VERSION 5.8 ;
BUSBITCHARS "[]" ;
DIVIDERCHAR "/" ;
UNITS
    DATABASE MICRONS 1000 ;
END UNITS

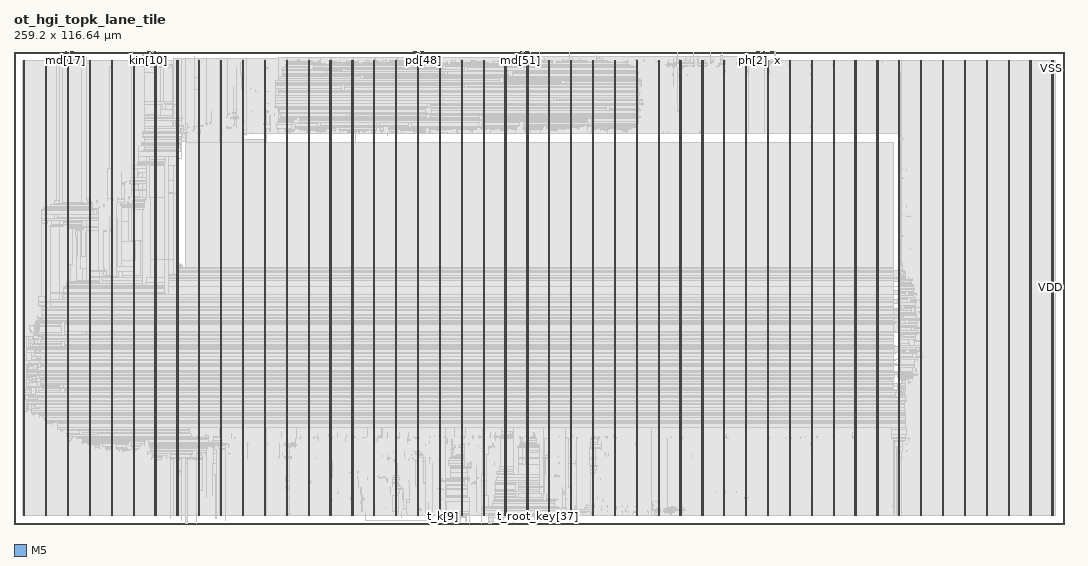
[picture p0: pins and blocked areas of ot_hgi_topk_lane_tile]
MACRO ot_hgi_topk_lane_tile
  FOREIGN ot_hgi_topk_lane_tile 0 0 ;
  CLASS BLOCK ;
  SIZE 259.2 BY 116.64 ;
  PIN clk
    DIRECTION INPUT ;
    USE SIGNAL ;
    PORT
      LAYER M5 ;
        RECT  31.92 116.556 31.944 116.64 ;
    END
  END clk
  PIN clr
    DIRECTION INPUT ;
    USE SIGNAL ;
    PORT
      LAYER M5 ;
        RECT  32.016 116.556 32.04 116.64 ;
    END
  END clr
  PIN kin[0]
    DIRECTION INPUT ;
    USE SIGNAL ;
    PORT
      LAYER M5 ;
        RECT  32.112 116.556 32.136 116.64 ;
    END
  END kin[0]
  PIN kin[10]
    DIRECTION INPUT ;
    USE SIGNAL ;
    PORT
      LAYER M5 ;
        RECT  33.072 116.556 33.096 116.64 ;
    END
  END kin[10]
  PIN kin[11]
    DIRECTION INPUT ;
    USE SIGNAL ;
    PORT
      LAYER M5 ;
        RECT  33.168 116.556 33.192 116.64 ;
    END
  END kin[11]
  PIN kin[1]
    DIRECTION INPUT ;
    USE SIGNAL ;
    PORT
      LAYER M5 ;
        RECT  32.208 116.556 32.232 116.64 ;
    END
  END kin[1]
  PIN kin[2]
    DIRECTION INPUT ;
    USE SIGNAL ;
    PORT
      LAYER M5 ;
        RECT  32.304 116.556 32.328 116.64 ;
    END
  END kin[2]
  PIN kin[3]
    DIRECTION INPUT ;
    USE SIGNAL ;
    PORT
      LAYER M5 ;
        RECT  32.4 116.556 32.424 116.64 ;
    END
  END kin[3]
  PIN kin[4]
    DIRECTION INPUT ;
    USE SIGNAL ;
    PORT
      LAYER M5 ;
        RECT  32.496 116.556 32.52 116.64 ;
    END
  END kin[4]
  PIN kin[5]
    DIRECTION INPUT ;
    USE SIGNAL ;
    PORT
      LAYER M5 ;
        RECT  32.592 116.556 32.616 116.64 ;
    END
  END kin[5]
  PIN kin[6]
    DIRECTION INPUT ;
    USE SIGNAL ;
    PORT
      LAYER M5 ;
        RECT  32.688 116.556 32.712 116.64 ;
    END
  END kin[6]
  PIN kin[7]
    DIRECTION INPUT ;
    USE SIGNAL ;
    PORT
      LAYER M5 ;
        RECT  32.784 116.556 32.808 116.64 ;
    END
  END kin[7]
  PIN kin[8]
    DIRECTION INPUT ;
    USE SIGNAL ;
    PORT
      LAYER M5 ;
        RECT  32.88 116.556 32.904 116.64 ;
    END
  END kin[8]
  PIN kin[9]
    DIRECTION INPUT ;
    USE SIGNAL ;
    PORT
      LAYER M5 ;
        RECT  32.976 116.556 33 116.64 ;
    END
  END kin[9]
  PIN mcr
    DIRECTION INPUT ;
    USE SIGNAL ;
    PORT
      LAYER M5 ;
        RECT  33.264 116.556 33.288 116.64 ;
    END
  END mcr
  PIN md[0]
    DIRECTION OUTPUT ;
    USE SIGNAL ;
    PORT
      LAYER M5 ;
        RECT  33.36 116.556 33.384 116.64 ;
    END
  END md[0]
  PIN md[10]
    DIRECTION OUTPUT ;
    USE SIGNAL ;
    PORT
      LAYER M5 ;
        RECT  34.32 116.556 34.344 116.64 ;
    END
  END md[10]
  PIN md[11]
    DIRECTION OUTPUT ;
    USE SIGNAL ;
    PORT
      LAYER M5 ;
        RECT  34.416 116.556 34.44 116.64 ;
    END
  END md[11]
  PIN md[12]
    DIRECTION OUTPUT ;
    USE SIGNAL ;
    PORT
      LAYER M5 ;
        RECT  34.512 116.556 34.536 116.64 ;
    END
  END md[12]
  PIN md[13]
    DIRECTION OUTPUT ;
    USE SIGNAL ;
    PORT
      LAYER M5 ;
        RECT  34.608 116.556 34.632 116.64 ;
    END
  END md[13]
  PIN md[14]
    DIRECTION OUTPUT ;
    USE SIGNAL ;
    PORT
      LAYER M5 ;
        RECT  34.704 116.556 34.728 116.64 ;
    END
  END md[14]
  PIN md[15]
    DIRECTION OUTPUT ;
    USE SIGNAL ;
    PORT
      LAYER M5 ;
        RECT  34.8 116.556 34.824 116.64 ;
    END
  END md[15]
  PIN md[16]
    DIRECTION OUTPUT ;
    USE SIGNAL ;
    PORT
      LAYER M5 ;
        RECT  34.896 116.556 34.92 116.64 ;
    END
  END md[16]
  PIN md[17]
    DIRECTION OUTPUT ;
    USE SIGNAL ;
    PORT
      LAYER M5 ;
        RECT  12.72 116.556 12.744 116.64 ;
    END
  END md[17]
  PIN md[18]
    DIRECTION OUTPUT ;
    USE SIGNAL ;
    PORT
      LAYER M5 ;
        RECT  12.816 116.556 12.84 116.64 ;
    END
  END md[18]
  PIN md[19]
    DIRECTION OUTPUT ;
    USE SIGNAL ;
    PORT
      LAYER M5 ;
        RECT  12.912 116.556 12.936 116.64 ;
    END
  END md[19]
  PIN md[1]
    DIRECTION OUTPUT ;
    USE SIGNAL ;
    PORT
      LAYER M5 ;
        RECT  33.456 116.556 33.48 116.64 ;
    END
  END md[1]
  PIN md[20]
    DIRECTION OUTPUT ;
    USE SIGNAL ;
    PORT
      LAYER M5 ;
        RECT  13.008 116.556 13.032 116.64 ;
    END
  END md[20]
  PIN md[21]
    DIRECTION OUTPUT ;
    USE SIGNAL ;
    PORT
      LAYER M5 ;
        RECT  13.104 116.556 13.128 116.64 ;
    END
  END md[21]
  PIN md[22]
    DIRECTION OUTPUT ;
    USE SIGNAL ;
    PORT
      LAYER M5 ;
        RECT  13.2 116.556 13.224 116.64 ;
    END
  END md[22]
  PIN md[23]
    DIRECTION OUTPUT ;
    USE SIGNAL ;
    PORT
      LAYER M5 ;
        RECT  13.296 116.556 13.32 116.64 ;
    END
  END md[23]
  PIN md[24]
    DIRECTION OUTPUT ;
    USE SIGNAL ;
    PORT
      LAYER M5 ;
        RECT  13.392 116.556 13.416 116.64 ;
    END
  END md[24]
  PIN md[25]
    DIRECTION OUTPUT ;
    USE SIGNAL ;
    PORT
      LAYER M5 ;
        RECT  13.488 116.556 13.512 116.64 ;
    END
  END md[25]
  PIN md[26]
    DIRECTION OUTPUT ;
    USE SIGNAL ;
    PORT
      LAYER M5 ;
        RECT  13.584 116.556 13.608 116.64 ;
    END
  END md[26]
  PIN md[27]
    DIRECTION OUTPUT ;
    USE SIGNAL ;
    PORT
      LAYER M5 ;
        RECT  13.68 116.556 13.704 116.64 ;
    END
  END md[27]
  PIN md[28]
    DIRECTION OUTPUT ;
    USE SIGNAL ;
    PORT
      LAYER M5 ;
        RECT  13.776 116.556 13.8 116.64 ;
    END
  END md[28]
  PIN md[29]
    DIRECTION OUTPUT ;
    USE SIGNAL ;
    PORT
      LAYER M5 ;
        RECT  13.872 116.556 13.896 116.64 ;
    END
  END md[29]
  PIN md[2]
    DIRECTION OUTPUT ;
    USE SIGNAL ;
    PORT
      LAYER M5 ;
        RECT  33.552 116.556 33.576 116.64 ;
    END
  END md[2]
  PIN md[30]
    DIRECTION OUTPUT ;
    USE SIGNAL ;
    PORT
      LAYER M5 ;
        RECT  13.968 116.556 13.992 116.64 ;
    END
  END md[30]
  PIN md[31]
    DIRECTION OUTPUT ;
    USE SIGNAL ;
    PORT
      LAYER M5 ;
        RECT  14.064 116.556 14.088 116.64 ;
    END
  END md[31]
  PIN md[32]
    DIRECTION OUTPUT ;
    USE SIGNAL ;
    PORT
      LAYER M5 ;
        RECT  14.16 116.556 14.184 116.64 ;
    END
  END md[32]
  PIN md[33]
    DIRECTION OUTPUT ;
    USE SIGNAL ;
    PORT
      LAYER M5 ;
        RECT  14.256 116.556 14.28 116.64 ;
    END
  END md[33]
  PIN md[34]
    DIRECTION OUTPUT ;
    USE SIGNAL ;
    PORT
      LAYER M5 ;
        RECT  14.352 116.556 14.376 116.64 ;
    END
  END md[34]
  PIN md[35]
    DIRECTION OUTPUT ;
    USE SIGNAL ;
    PORT
      LAYER M5 ;
        RECT  14.448 116.556 14.472 116.64 ;
    END
  END md[35]
  PIN md[36]
    DIRECTION OUTPUT ;
    USE SIGNAL ;
    PORT
      LAYER M5 ;
        RECT  14.544 116.556 14.568 116.64 ;
    END
  END md[36]
  PIN md[37]
    DIRECTION OUTPUT ;
    USE SIGNAL ;
    PORT
      LAYER M5 ;
        RECT  14.64 116.556 14.664 116.64 ;
    END
  END md[37]
  PIN md[38]
    DIRECTION OUTPUT ;
    USE SIGNAL ;
    PORT
      LAYER M5 ;
        RECT  14.736 116.556 14.76 116.64 ;
    END
  END md[38]
  PIN md[39]
    DIRECTION OUTPUT ;
    USE SIGNAL ;
    PORT
      LAYER M5 ;
        RECT  14.832 116.556 14.856 116.64 ;
    END
  END md[39]
  PIN md[3]
    DIRECTION OUTPUT ;
    USE SIGNAL ;
    PORT
      LAYER M5 ;
        RECT  33.648 116.556 33.672 116.64 ;
    END
  END md[3]
  PIN md[40]
    DIRECTION OUTPUT ;
    USE SIGNAL ;
    PORT
      LAYER M5 ;
        RECT  14.928 116.556 14.952 116.64 ;
    END
  END md[40]
  PIN md[41]
    DIRECTION OUTPUT ;
    USE SIGNAL ;
    PORT
      LAYER M5 ;
        RECT  15.024 116.556 15.048 116.64 ;
    END
  END md[41]
  PIN md[42]
    DIRECTION OUTPUT ;
    USE SIGNAL ;
    PORT
      LAYER M5 ;
        RECT  15.12 116.556 15.144 116.64 ;
    END
  END md[42]
  PIN md[43]
    DIRECTION OUTPUT ;
    USE SIGNAL ;
    PORT
      LAYER M5 ;
        RECT  15.216 116.556 15.24 116.64 ;
    END
  END md[43]
  PIN md[44]
    DIRECTION OUTPUT ;
    USE SIGNAL ;
    PORT
      LAYER M5 ;
        RECT  15.312 116.556 15.336 116.64 ;
    END
  END md[44]
  PIN md[45]
    DIRECTION OUTPUT ;
    USE SIGNAL ;
    PORT
      LAYER M5 ;
        RECT  15.408 116.556 15.432 116.64 ;
    END
  END md[45]
  PIN md[46]
    DIRECTION OUTPUT ;
    USE SIGNAL ;
    PORT
      LAYER M5 ;
        RECT  15.504 116.556 15.528 116.64 ;
    END
  END md[46]
  PIN md[47]
    DIRECTION OUTPUT ;
    USE SIGNAL ;
    PORT
      LAYER M5 ;
        RECT  15.6 116.556 15.624 116.64 ;
    END
  END md[47]
  PIN md[48]
    DIRECTION OUTPUT ;
    USE SIGNAL ;
    PORT
      LAYER M5 ;
        RECT  15.696 116.556 15.72 116.64 ;
    END
  END md[48]
  PIN md[49]
    DIRECTION OUTPUT ;
    USE SIGNAL ;
    PORT
      LAYER M5 ;
        RECT  124.848 116.556 124.872 116.64 ;
    END
  END md[49]
  PIN md[4]
    DIRECTION OUTPUT ;
    USE SIGNAL ;
    PORT
      LAYER M5 ;
        RECT  33.744 116.556 33.768 116.64 ;
    END
  END md[4]
  PIN md[50]
    DIRECTION OUTPUT ;
    USE SIGNAL ;
    PORT
      LAYER M5 ;
        RECT  124.944 116.556 124.968 116.64 ;
    END
  END md[50]
  PIN md[51]
    DIRECTION OUTPUT ;
    USE SIGNAL ;
    PORT
      LAYER M5 ;
        RECT  125.04 116.556 125.064 116.64 ;
    END
  END md[51]
  PIN md[52]
    DIRECTION OUTPUT ;
    USE SIGNAL ;
    PORT
      LAYER M5 ;
        RECT  125.136 116.556 125.16 116.64 ;
    END
  END md[52]
  PIN md[53]
    DIRECTION OUTPUT ;
    USE SIGNAL ;
    PORT
      LAYER M5 ;
        RECT  125.232 116.556 125.256 116.64 ;
    END
  END md[53]
  PIN md[5]
    DIRECTION OUTPUT ;
    USE SIGNAL ;
    PORT
      LAYER M5 ;
        RECT  33.84 116.556 33.864 116.64 ;
    END
  END md[5]
  PIN md[6]
    DIRECTION OUTPUT ;
    USE SIGNAL ;
    PORT
      LAYER M5 ;
        RECT  33.936 116.556 33.96 116.64 ;
    END
  END md[6]
  PIN md[7]
    DIRECTION OUTPUT ;
    USE SIGNAL ;
    PORT
      LAYER M5 ;
        RECT  34.032 116.556 34.056 116.64 ;
    END
  END md[7]
  PIN md[8]
    DIRECTION OUTPUT ;
    USE SIGNAL ;
    PORT
      LAYER M5 ;
        RECT  34.128 116.556 34.152 116.64 ;
    END
  END md[8]
  PIN md[9]
    DIRECTION OUTPUT ;
    USE SIGNAL ;
    PORT
      LAYER M5 ;
        RECT  34.224 116.556 34.248 116.64 ;
    END
  END md[9]
  PIN me
    DIRECTION OUTPUT ;
    USE SIGNAL ;
    PORT
      LAYER M5 ;
        RECT  125.328 116.556 125.352 116.64 ;
    END
  END me
  PIN mv
    DIRECTION OUTPUT ;
    USE SIGNAL ;
    PORT
      LAYER M5 ;
        RECT  125.424 116.556 125.448 116.64 ;
    END
  END mv
  PIN ok
    DIRECTION OUTPUT ;
    USE SIGNAL ;
    PORT
      LAYER M5 ;
        RECT  125.52 116.556 125.544 116.64 ;
    END
  END ok
  PIN pd[0]
    DIRECTION INPUT ;
    USE SIGNAL ;
    PORT
      LAYER M5 ;
        RECT  125.616 116.556 125.64 116.64 ;
    END
  END pd[0]
  PIN pd[10]
    DIRECTION INPUT ;
    USE SIGNAL ;
    PORT
      LAYER M5 ;
        RECT  126.576 116.556 126.6 116.64 ;
    END
  END pd[10]
  PIN pd[11]
    DIRECTION INPUT ;
    USE SIGNAL ;
    PORT
      LAYER M5 ;
        RECT  126.672 116.556 126.696 116.64 ;
    END
  END pd[11]
  PIN pd[12]
    DIRECTION INPUT ;
    USE SIGNAL ;
    PORT
      LAYER M5 ;
        RECT  126.768 116.556 126.792 116.64 ;
    END
  END pd[12]
  PIN pd[13]
    DIRECTION INPUT ;
    USE SIGNAL ;
    PORT
      LAYER M5 ;
        RECT  126.864 116.556 126.888 116.64 ;
    END
  END pd[13]
  PIN pd[14]
    DIRECTION INPUT ;
    USE SIGNAL ;
    PORT
      LAYER M5 ;
        RECT  126.96 116.556 126.984 116.64 ;
    END
  END pd[14]
  PIN pd[15]
    DIRECTION INPUT ;
    USE SIGNAL ;
    PORT
      LAYER M5 ;
        RECT  127.056 116.556 127.08 116.64 ;
    END
  END pd[15]
  PIN pd[16]
    DIRECTION INPUT ;
    USE SIGNAL ;
    PORT
      LAYER M5 ;
        RECT  127.152 116.556 127.176 116.64 ;
    END
  END pd[16]
  PIN pd[17]
    DIRECTION INPUT ;
    USE SIGNAL ;
    PORT
      LAYER M5 ;
        RECT  127.248 116.556 127.272 116.64 ;
    END
  END pd[17]
  PIN pd[18]
    DIRECTION INPUT ;
    USE SIGNAL ;
    PORT
      LAYER M5 ;
        RECT  127.344 116.556 127.368 116.64 ;
    END
  END pd[18]
  PIN pd[19]
    DIRECTION INPUT ;
    USE SIGNAL ;
    PORT
      LAYER M5 ;
        RECT  127.44 116.556 127.464 116.64 ;
    END
  END pd[19]
  PIN pd[1]
    DIRECTION INPUT ;
    USE SIGNAL ;
    PORT
      LAYER M5 ;
        RECT  125.712 116.556 125.736 116.64 ;
    END
  END pd[1]
  PIN pd[20]
    DIRECTION INPUT ;
    USE SIGNAL ;
    PORT
      LAYER M5 ;
        RECT  127.536 116.556 127.56 116.64 ;
    END
  END pd[20]
  PIN pd[21]
    DIRECTION INPUT ;
    USE SIGNAL ;
    PORT
      LAYER M5 ;
        RECT  127.632 116.556 127.656 116.64 ;
    END
  END pd[21]
  PIN pd[22]
    DIRECTION INPUT ;
    USE SIGNAL ;
    PORT
      LAYER M5 ;
        RECT  127.728 116.556 127.752 116.64 ;
    END
  END pd[22]
  PIN pd[23]
    DIRECTION INPUT ;
    USE SIGNAL ;
    PORT
      LAYER M5 ;
        RECT  127.824 116.556 127.848 116.64 ;
    END
  END pd[23]
  PIN pd[24]
    DIRECTION INPUT ;
    USE SIGNAL ;
    PORT
      LAYER M5 ;
        RECT  98.736 116.556 98.76 116.64 ;
    END
  END pd[24]
  PIN pd[25]
    DIRECTION INPUT ;
    USE SIGNAL ;
    PORT
      LAYER M5 ;
        RECT  98.832 116.556 98.856 116.64 ;
    END
  END pd[25]
  PIN pd[26]
    DIRECTION INPUT ;
    USE SIGNAL ;
    PORT
      LAYER M5 ;
        RECT  98.928 116.556 98.952 116.64 ;
    END
  END pd[26]
  PIN pd[27]
    DIRECTION INPUT ;
    USE SIGNAL ;
    PORT
      LAYER M5 ;
        RECT  99.024 116.556 99.048 116.64 ;
    END
  END pd[27]
  PIN pd[28]
    DIRECTION INPUT ;
    USE SIGNAL ;
    PORT
      LAYER M5 ;
        RECT  99.12 116.556 99.144 116.64 ;
    END
  END pd[28]
  PIN pd[29]
    DIRECTION INPUT ;
    USE SIGNAL ;
    PORT
      LAYER M5 ;
        RECT  99.216 116.556 99.24 116.64 ;
    END
  END pd[29]
  PIN pd[2]
    DIRECTION INPUT ;
    USE SIGNAL ;
    PORT
      LAYER M5 ;
        RECT  125.808 116.556 125.832 116.64 ;
    END
  END pd[2]
  PIN pd[30]
    DIRECTION INPUT ;
    USE SIGNAL ;
    PORT
      LAYER M5 ;
        RECT  99.312 116.556 99.336 116.64 ;
    END
  END pd[30]
  PIN pd[31]
    DIRECTION INPUT ;
    USE SIGNAL ;
    PORT
      LAYER M5 ;
        RECT  99.408 116.556 99.432 116.64 ;
    END
  END pd[31]
  PIN pd[32]
    DIRECTION INPUT ;
    USE SIGNAL ;
    PORT
      LAYER M5 ;
        RECT  99.504 116.556 99.528 116.64 ;
    END
  END pd[32]
  PIN pd[33]
    DIRECTION INPUT ;
    USE SIGNAL ;
    PORT
      LAYER M5 ;
        RECT  99.6 116.556 99.624 116.64 ;
    END
  END pd[33]
  PIN pd[34]
    DIRECTION INPUT ;
    USE SIGNAL ;
    PORT
      LAYER M5 ;
        RECT  99.696 116.556 99.72 116.64 ;
    END
  END pd[34]
  PIN pd[35]
    DIRECTION INPUT ;
    USE SIGNAL ;
    PORT
      LAYER M5 ;
        RECT  99.792 116.556 99.816 116.64 ;
    END
  END pd[35]
  PIN pd[36]
    DIRECTION INPUT ;
    USE SIGNAL ;
    PORT
      LAYER M5 ;
        RECT  99.888 116.556 99.912 116.64 ;
    END
  END pd[36]
  PIN pd[37]
    DIRECTION INPUT ;
    USE SIGNAL ;
    PORT
      LAYER M5 ;
        RECT  99.984 116.556 100.008 116.64 ;
    END
  END pd[37]
  PIN pd[38]
    DIRECTION INPUT ;
    USE SIGNAL ;
    PORT
      LAYER M5 ;
        RECT  100.08 116.556 100.104 116.64 ;
    END
  END pd[38]
  PIN pd[39]
    DIRECTION INPUT ;
    USE SIGNAL ;
    PORT
      LAYER M5 ;
        RECT  100.176 116.556 100.2 116.64 ;
    END
  END pd[39]
  PIN pd[3]
    DIRECTION INPUT ;
    USE SIGNAL ;
    PORT
      LAYER M5 ;
        RECT  125.904 116.556 125.928 116.64 ;
    END
  END pd[3]
  PIN pd[40]
    DIRECTION INPUT ;
    USE SIGNAL ;
    PORT
      LAYER M5 ;
        RECT  100.272 116.556 100.296 116.64 ;
    END
  END pd[40]
  PIN pd[41]
    DIRECTION INPUT ;
    USE SIGNAL ;
    PORT
      LAYER M5 ;
        RECT  100.368 116.556 100.392 116.64 ;
    END
  END pd[41]
  PIN pd[42]
    DIRECTION INPUT ;
    USE SIGNAL ;
    PORT
      LAYER M5 ;
        RECT  100.464 116.556 100.488 116.64 ;
    END
  END pd[42]
  PIN pd[43]
    DIRECTION INPUT ;
    USE SIGNAL ;
    PORT
      LAYER M5 ;
        RECT  100.56 116.556 100.584 116.64 ;
    END
  END pd[43]
  PIN pd[44]
    DIRECTION INPUT ;
    USE SIGNAL ;
    PORT
      LAYER M5 ;
        RECT  100.656 116.556 100.68 116.64 ;
    END
  END pd[44]
  PIN pd[45]
    DIRECTION INPUT ;
    USE SIGNAL ;
    PORT
      LAYER M5 ;
        RECT  100.752 116.556 100.776 116.64 ;
    END
  END pd[45]
  PIN pd[46]
    DIRECTION INPUT ;
    USE SIGNAL ;
    PORT
      LAYER M5 ;
        RECT  100.848 116.556 100.872 116.64 ;
    END
  END pd[46]
  PIN pd[47]
    DIRECTION INPUT ;
    USE SIGNAL ;
    PORT
      LAYER M5 ;
        RECT  100.944 116.556 100.968 116.64 ;
    END
  END pd[47]
  PIN pd[48]
    DIRECTION INPUT ;
    USE SIGNAL ;
    PORT
      LAYER M5 ;
        RECT  101.04 116.556 101.064 116.64 ;
    END
  END pd[48]
  PIN pd[49]
    DIRECTION INPUT ;
    USE SIGNAL ;
    PORT
      LAYER M5 ;
        RECT  101.136 116.556 101.16 116.64 ;
    END
  END pd[49]
  PIN pd[4]
    DIRECTION INPUT ;
    USE SIGNAL ;
    PORT
      LAYER M5 ;
        RECT  126 116.556 126.024 116.64 ;
    END
  END pd[4]
  PIN pd[50]
    DIRECTION INPUT ;
    USE SIGNAL ;
    PORT
      LAYER M5 ;
        RECT  101.232 116.556 101.256 116.64 ;
    END
  END pd[50]
  PIN pd[51]
    DIRECTION INPUT ;
    USE SIGNAL ;
    PORT
      LAYER M5 ;
        RECT  101.328 116.556 101.352 116.64 ;
    END
  END pd[51]
  PIN pd[52]
    DIRECTION INPUT ;
    USE SIGNAL ;
    PORT
      LAYER M5 ;
        RECT  101.424 116.556 101.448 116.64 ;
    END
  END pd[52]
  PIN pd[53]
    DIRECTION INPUT ;
    USE SIGNAL ;
    PORT
      LAYER M5 ;
        RECT  101.52 116.556 101.544 116.64 ;
    END
  END pd[53]
  PIN pd[5]
    DIRECTION INPUT ;
    USE SIGNAL ;
    PORT
      LAYER M5 ;
        RECT  126.096 116.556 126.12 116.64 ;
    END
  END pd[5]
  PIN pd[6]
    DIRECTION INPUT ;
    USE SIGNAL ;
    PORT
      LAYER M5 ;
        RECT  126.192 116.556 126.216 116.64 ;
    END
  END pd[6]
  PIN pd[7]
    DIRECTION INPUT ;
    USE SIGNAL ;
    PORT
      LAYER M5 ;
        RECT  126.288 116.556 126.312 116.64 ;
    END
  END pd[7]
  PIN pd[8]
    DIRECTION INPUT ;
    USE SIGNAL ;
    PORT
      LAYER M5 ;
        RECT  126.384 116.556 126.408 116.64 ;
    END
  END pd[8]
  PIN pd[9]
    DIRECTION INPUT ;
    USE SIGNAL ;
    PORT
      LAYER M5 ;
        RECT  126.48 116.556 126.504 116.64 ;
    END
  END pd[9]
  PIN ph[0]
    DIRECTION INPUT ;
    USE SIGNAL ;
    PORT
      LAYER M5 ;
        RECT  101.616 116.556 101.64 116.64 ;
    END
  END ph[0]
  PIN ph[1]
    DIRECTION INPUT ;
    USE SIGNAL ;
    PORT
      LAYER M5 ;
        RECT  101.712 116.556 101.736 116.64 ;
    END
  END ph[1]
  PIN ph[2]
    DIRECTION INPUT ;
    USE SIGNAL ;
    PORT
      LAYER M5 ;
        RECT  182.448 116.556 182.472 116.64 ;
    END
  END ph[2]
  PIN pv
    DIRECTION INPUT ;
    USE SIGNAL ;
    PORT
      LAYER M5 ;
        RECT  182.544 116.556 182.568 116.64 ;
    END
  END pv
  PIN q
    DIRECTION OUTPUT ;
    USE SIGNAL ;
    PORT
      LAYER M5 ;
        RECT  182.64 116.556 182.664 116.64 ;
    END
  END q
  PIN root[0]
    DIRECTION OUTPUT ;
    USE SIGNAL ;
    PORT
      LAYER M5 ;
        RECT  182.736 116.556 182.76 116.64 ;
    END
  END root[0]
  PIN root[10]
    DIRECTION OUTPUT ;
    USE SIGNAL ;
    PORT
      LAYER M5 ;
        RECT  183.696 116.556 183.72 116.64 ;
    END
  END root[10]
  PIN root[11]
    DIRECTION OUTPUT ;
    USE SIGNAL ;
    PORT
      LAYER M5 ;
        RECT  183.792 116.556 183.816 116.64 ;
    END
  END root[11]
  PIN root[12]
    DIRECTION OUTPUT ;
    USE SIGNAL ;
    PORT
      LAYER M5 ;
        RECT  183.888 116.556 183.912 116.64 ;
    END
  END root[12]
  PIN root[13]
    DIRECTION OUTPUT ;
    USE SIGNAL ;
    PORT
      LAYER M5 ;
        RECT  183.984 116.556 184.008 116.64 ;
    END
  END root[13]
  PIN root[14]
    DIRECTION OUTPUT ;
    USE SIGNAL ;
    PORT
      LAYER M5 ;
        RECT  184.08 116.556 184.104 116.64 ;
    END
  END root[14]
  PIN root[15]
    DIRECTION OUTPUT ;
    USE SIGNAL ;
    PORT
      LAYER M5 ;
        RECT  184.176 116.556 184.2 116.64 ;
    END
  END root[15]
  PIN root[16]
    DIRECTION OUTPUT ;
    USE SIGNAL ;
    PORT
      LAYER M5 ;
        RECT  184.272 116.556 184.296 116.64 ;
    END
  END root[16]
  PIN root[17]
    DIRECTION OUTPUT ;
    USE SIGNAL ;
    PORT
      LAYER M5 ;
        RECT  184.368 116.556 184.392 116.64 ;
    END
  END root[17]
  PIN root[18]
    DIRECTION OUTPUT ;
    USE SIGNAL ;
    PORT
      LAYER M5 ;
        RECT  184.464 116.556 184.488 116.64 ;
    END
  END root[18]
  PIN root[19]
    DIRECTION OUTPUT ;
    USE SIGNAL ;
    PORT
      LAYER M5 ;
        RECT  184.56 116.556 184.584 116.64 ;
    END
  END root[19]
  PIN root[1]
    DIRECTION OUTPUT ;
    USE SIGNAL ;
    PORT
      LAYER M5 ;
        RECT  182.832 116.556 182.856 116.64 ;
    END
  END root[1]
  PIN root[20]
    DIRECTION OUTPUT ;
    USE SIGNAL ;
    PORT
      LAYER M5 ;
        RECT  184.656 116.556 184.68 116.64 ;
    END
  END root[20]
  PIN root[21]
    DIRECTION OUTPUT ;
    USE SIGNAL ;
    PORT
      LAYER M5 ;
        RECT  184.752 116.556 184.776 116.64 ;
    END
  END root[21]
  PIN root[22]
    DIRECTION OUTPUT ;
    USE SIGNAL ;
    PORT
      LAYER M5 ;
        RECT  184.848 116.556 184.872 116.64 ;
    END
  END root[22]
  PIN root[23]
    DIRECTION OUTPUT ;
    USE SIGNAL ;
    PORT
      LAYER M5 ;
        RECT  184.944 116.556 184.968 116.64 ;
    END
  END root[23]
  PIN root[24]
    DIRECTION OUTPUT ;
    USE SIGNAL ;
    PORT
      LAYER M5 ;
        RECT  185.04 116.556 185.064 116.64 ;
    END
  END root[24]
  PIN root[25]
    DIRECTION OUTPUT ;
    USE SIGNAL ;
    PORT
      LAYER M5 ;
        RECT  185.136 116.556 185.16 116.64 ;
    END
  END root[25]
  PIN root[26]
    DIRECTION OUTPUT ;
    USE SIGNAL ;
    PORT
      LAYER M5 ;
        RECT  185.232 116.556 185.256 116.64 ;
    END
  END root[26]
  PIN root[27]
    DIRECTION OUTPUT ;
    USE SIGNAL ;
    PORT
      LAYER M5 ;
        RECT  185.328 116.556 185.352 116.64 ;
    END
  END root[27]
  PIN root[28]
    DIRECTION OUTPUT ;
    USE SIGNAL ;
    PORT
      LAYER M5 ;
        RECT  185.424 116.556 185.448 116.64 ;
    END
  END root[28]
  PIN root[29]
    DIRECTION OUTPUT ;
    USE SIGNAL ;
    PORT
      LAYER M5 ;
        RECT  186.096 116.556 186.12 116.64 ;
    END
  END root[29]
  PIN root[2]
    DIRECTION OUTPUT ;
    USE SIGNAL ;
    PORT
      LAYER M5 ;
        RECT  182.928 116.556 182.952 116.64 ;
    END
  END root[2]
  PIN root[30]
    DIRECTION OUTPUT ;
    USE SIGNAL ;
    PORT
      LAYER M5 ;
        RECT  186.192 116.556 186.216 116.64 ;
    END
  END root[30]
  PIN root[31]
    DIRECTION OUTPUT ;
    USE SIGNAL ;
    PORT
      LAYER M5 ;
        RECT  186.288 116.556 186.312 116.64 ;
    END
  END root[31]
  PIN root[32]
    DIRECTION OUTPUT ;
    USE SIGNAL ;
    PORT
      LAYER M5 ;
        RECT  186.384 116.556 186.408 116.64 ;
    END
  END root[32]
  PIN root[33]
    DIRECTION OUTPUT ;
    USE SIGNAL ;
    PORT
      LAYER M5 ;
        RECT  186.48 116.556 186.504 116.64 ;
    END
  END root[33]
  PIN root[34]
    DIRECTION OUTPUT ;
    USE SIGNAL ;
    PORT
      LAYER M5 ;
        RECT  186.576 116.556 186.6 116.64 ;
    END
  END root[34]
  PIN root[35]
    DIRECTION OUTPUT ;
    USE SIGNAL ;
    PORT
      LAYER M5 ;
        RECT  186.672 116.556 186.696 116.64 ;
    END
  END root[35]
  PIN root[36]
    DIRECTION OUTPUT ;
    USE SIGNAL ;
    PORT
      LAYER M5 ;
        RECT  186.768 116.556 186.792 116.64 ;
    END
  END root[36]
  PIN root[37]
    DIRECTION OUTPUT ;
    USE SIGNAL ;
    PORT
      LAYER M5 ;
        RECT  186.864 116.556 186.888 116.64 ;
    END
  END root[37]
  PIN root[38]
    DIRECTION OUTPUT ;
    USE SIGNAL ;
    PORT
      LAYER M5 ;
        RECT  186.96 116.556 186.984 116.64 ;
    END
  END root[38]
  PIN root[39]
    DIRECTION OUTPUT ;
    USE SIGNAL ;
    PORT
      LAYER M5 ;
        RECT  187.056 116.556 187.08 116.64 ;
    END
  END root[39]
  PIN root[3]
    DIRECTION OUTPUT ;
    USE SIGNAL ;
    PORT
      LAYER M5 ;
        RECT  183.024 116.556 183.048 116.64 ;
    END
  END root[3]
  PIN root[40]
    DIRECTION OUTPUT ;
    USE SIGNAL ;
    PORT
      LAYER M5 ;
        RECT  187.152 116.556 187.176 116.64 ;
    END
  END root[40]
  PIN root[41]
    DIRECTION OUTPUT ;
    USE SIGNAL ;
    PORT
      LAYER M5 ;
        RECT  187.248 116.556 187.272 116.64 ;
    END
  END root[41]
  PIN root[42]
    DIRECTION OUTPUT ;
    USE SIGNAL ;
    PORT
      LAYER M5 ;
        RECT  187.344 116.556 187.368 116.64 ;
    END
  END root[42]
  PIN root[43]
    DIRECTION OUTPUT ;
    USE SIGNAL ;
    PORT
      LAYER M5 ;
        RECT  187.44 116.556 187.464 116.64 ;
    END
  END root[43]
  PIN root[44]
    DIRECTION OUTPUT ;
    USE SIGNAL ;
    PORT
      LAYER M5 ;
        RECT  187.536 116.556 187.56 116.64 ;
    END
  END root[44]
  PIN root[45]
    DIRECTION OUTPUT ;
    USE SIGNAL ;
    PORT
      LAYER M5 ;
        RECT  187.632 116.556 187.656 116.64 ;
    END
  END root[45]
  PIN root[46]
    DIRECTION OUTPUT ;
    USE SIGNAL ;
    PORT
      LAYER M5 ;
        RECT  187.728 116.556 187.752 116.64 ;
    END
  END root[46]
  PIN root[47]
    DIRECTION OUTPUT ;
    USE SIGNAL ;
    PORT
      LAYER M5 ;
        RECT  187.824 116.556 187.848 116.64 ;
    END
  END root[47]
  PIN root[48]
    DIRECTION OUTPUT ;
    USE SIGNAL ;
    PORT
      LAYER M5 ;
        RECT  187.92 116.556 187.944 116.64 ;
    END
  END root[48]
  PIN root[49]
    DIRECTION OUTPUT ;
    USE SIGNAL ;
    PORT
      LAYER M5 ;
        RECT  188.016 116.556 188.04 116.64 ;
    END
  END root[49]
  PIN root[4]
    DIRECTION OUTPUT ;
    USE SIGNAL ;
    PORT
      LAYER M5 ;
        RECT  183.12 116.556 183.144 116.64 ;
    END
  END root[4]
  PIN root[50]
    DIRECTION OUTPUT ;
    USE SIGNAL ;
    PORT
      LAYER M5 ;
        RECT  188.112 116.556 188.136 116.64 ;
    END
  END root[50]
  PIN root[51]
    DIRECTION OUTPUT ;
    USE SIGNAL ;
    PORT
      LAYER M5 ;
        RECT  188.208 116.556 188.232 116.64 ;
    END
  END root[51]
  PIN root[52]
    DIRECTION OUTPUT ;
    USE SIGNAL ;
    PORT
      LAYER M5 ;
        RECT  188.304 116.556 188.328 116.64 ;
    END
  END root[52]
  PIN root[5]
    DIRECTION OUTPUT ;
    USE SIGNAL ;
    PORT
      LAYER M5 ;
        RECT  183.216 116.556 183.24 116.64 ;
    END
  END root[5]
  PIN root[6]
    DIRECTION OUTPUT ;
    USE SIGNAL ;
    PORT
      LAYER M5 ;
        RECT  183.312 116.556 183.336 116.64 ;
    END
  END root[6]
  PIN root[7]
    DIRECTION OUTPUT ;
    USE SIGNAL ;
    PORT
      LAYER M5 ;
        RECT  183.408 116.556 183.432 116.64 ;
    END
  END root[7]
  PIN root[8]
    DIRECTION OUTPUT ;
    USE SIGNAL ;
    PORT
      LAYER M5 ;
        RECT  183.504 116.556 183.528 116.64 ;
    END
  END root[8]
  PIN root[9]
    DIRECTION OUTPUT ;
    USE SIGNAL ;
    PORT
      LAYER M5 ;
        RECT  183.6 116.556 183.624 116.64 ;
    END
  END root[9]
  PIN rst_n
    DIRECTION INPUT ;
    USE SIGNAL ;
    PORT
      LAYER M5 ;
        RECT  188.4 116.556 188.424 116.64 ;
    END
  END rst_n
  PIN t_clr_go
    DIRECTION OUTPUT ;
    USE SIGNAL ;
    PORT
      LAYER M5 ;
        RECT  118.032 0 118.056 0.084 ;
    END
  END t_clr_go
  PIN t_ext_d[0]
    DIRECTION INPUT ;
    USE SIGNAL ;
    PORT
      LAYER M5 ;
        RECT  118.128 0 118.152 0.084 ;
    END
  END t_ext_d[0]
  PIN t_ext_d[10]
    DIRECTION INPUT ;
    USE SIGNAL ;
    PORT
      LAYER M5 ;
        RECT  119.088 0 119.112 0.084 ;
    END
  END t_ext_d[10]
  PIN t_ext_d[11]
    DIRECTION INPUT ;
    USE SIGNAL ;
    PORT
      LAYER M5 ;
        RECT  119.184 0 119.208 0.084 ;
    END
  END t_ext_d[11]
  PIN t_ext_d[12]
    DIRECTION INPUT ;
    USE SIGNAL ;
    PORT
      LAYER M5 ;
        RECT  119.28 0 119.304 0.084 ;
    END
  END t_ext_d[12]
  PIN t_ext_d[13]
    DIRECTION INPUT ;
    USE SIGNAL ;
    PORT
      LAYER M5 ;
        RECT  119.376 0 119.4 0.084 ;
    END
  END t_ext_d[13]
  PIN t_ext_d[14]
    DIRECTION INPUT ;
    USE SIGNAL ;
    PORT
      LAYER M5 ;
        RECT  119.472 0 119.496 0.084 ;
    END
  END t_ext_d[14]
  PIN t_ext_d[15]
    DIRECTION INPUT ;
    USE SIGNAL ;
    PORT
      LAYER M5 ;
        RECT  119.568 0 119.592 0.084 ;
    END
  END t_ext_d[15]
  PIN t_ext_d[16]
    DIRECTION INPUT ;
    USE SIGNAL ;
    PORT
      LAYER M5 ;
        RECT  119.664 0 119.688 0.084 ;
    END
  END t_ext_d[16]
  PIN t_ext_d[17]
    DIRECTION INPUT ;
    USE SIGNAL ;
    PORT
      LAYER M5 ;
        RECT  119.76 0 119.784 0.084 ;
    END
  END t_ext_d[17]
  PIN t_ext_d[18]
    DIRECTION INPUT ;
    USE SIGNAL ;
    PORT
      LAYER M5 ;
        RECT  119.856 0 119.88 0.084 ;
    END
  END t_ext_d[18]
  PIN t_ext_d[19]
    DIRECTION INPUT ;
    USE SIGNAL ;
    PORT
      LAYER M5 ;
        RECT  119.952 0 119.976 0.084 ;
    END
  END t_ext_d[19]
  PIN t_ext_d[1]
    DIRECTION INPUT ;
    USE SIGNAL ;
    PORT
      LAYER M5 ;
        RECT  118.224 0 118.248 0.084 ;
    END
  END t_ext_d[1]
  PIN t_ext_d[20]
    DIRECTION INPUT ;
    USE SIGNAL ;
    PORT
      LAYER M5 ;
        RECT  120.048 0 120.072 0.084 ;
    END
  END t_ext_d[20]
  PIN t_ext_d[21]
    DIRECTION INPUT ;
    USE SIGNAL ;
    PORT
      LAYER M5 ;
        RECT  120.144 0 120.168 0.084 ;
    END
  END t_ext_d[21]
  PIN t_ext_d[22]
    DIRECTION INPUT ;
    USE SIGNAL ;
    PORT
      LAYER M5 ;
        RECT  120.24 0 120.264 0.084 ;
    END
  END t_ext_d[22]
  PIN t_ext_d[23]
    DIRECTION INPUT ;
    USE SIGNAL ;
    PORT
      LAYER M5 ;
        RECT  120.336 0 120.36 0.084 ;
    END
  END t_ext_d[23]
  PIN t_ext_d[24]
    DIRECTION INPUT ;
    USE SIGNAL ;
    PORT
      LAYER M5 ;
        RECT  120.432 0 120.456 0.084 ;
    END
  END t_ext_d[24]
  PIN t_ext_d[25]
    DIRECTION INPUT ;
    USE SIGNAL ;
    PORT
      LAYER M5 ;
        RECT  120.528 0 120.552 0.084 ;
    END
  END t_ext_d[25]
  PIN t_ext_d[26]
    DIRECTION INPUT ;
    USE SIGNAL ;
    PORT
      LAYER M5 ;
        RECT  120.624 0 120.648 0.084 ;
    END
  END t_ext_d[26]
  PIN t_ext_d[27]
    DIRECTION INPUT ;
    USE SIGNAL ;
    PORT
      LAYER M5 ;
        RECT  120.72 0 120.744 0.084 ;
    END
  END t_ext_d[27]
  PIN t_ext_d[28]
    DIRECTION INPUT ;
    USE SIGNAL ;
    PORT
      LAYER M5 ;
        RECT  120.816 0 120.84 0.084 ;
    END
  END t_ext_d[28]
  PIN t_ext_d[29]
    DIRECTION INPUT ;
    USE SIGNAL ;
    PORT
      LAYER M5 ;
        RECT  120.912 0 120.936 0.084 ;
    END
  END t_ext_d[29]
  PIN t_ext_d[2]
    DIRECTION INPUT ;
    USE SIGNAL ;
    PORT
      LAYER M5 ;
        RECT  118.32 0 118.344 0.084 ;
    END
  END t_ext_d[2]
  PIN t_ext_d[30]
    DIRECTION INPUT ;
    USE SIGNAL ;
    PORT
      LAYER M5 ;
        RECT  124.848 0 124.872 0.084 ;
    END
  END t_ext_d[30]
  PIN t_ext_d[31]
    DIRECTION INPUT ;
    USE SIGNAL ;
    PORT
      LAYER M5 ;
        RECT  124.944 0 124.968 0.084 ;
    END
  END t_ext_d[31]
  PIN t_ext_d[32]
    DIRECTION INPUT ;
    USE SIGNAL ;
    PORT
      LAYER M5 ;
        RECT  125.04 0 125.064 0.084 ;
    END
  END t_ext_d[32]
  PIN t_ext_d[33]
    DIRECTION INPUT ;
    USE SIGNAL ;
    PORT
      LAYER M5 ;
        RECT  125.136 0 125.16 0.084 ;
    END
  END t_ext_d[33]
  PIN t_ext_d[34]
    DIRECTION INPUT ;
    USE SIGNAL ;
    PORT
      LAYER M5 ;
        RECT  125.232 0 125.256 0.084 ;
    END
  END t_ext_d[34]
  PIN t_ext_d[35]
    DIRECTION INPUT ;
    USE SIGNAL ;
    PORT
      LAYER M5 ;
        RECT  125.328 0 125.352 0.084 ;
    END
  END t_ext_d[35]
  PIN t_ext_d[36]
    DIRECTION INPUT ;
    USE SIGNAL ;
    PORT
      LAYER M5 ;
        RECT  125.424 0 125.448 0.084 ;
    END
  END t_ext_d[36]
  PIN t_ext_d[37]
    DIRECTION INPUT ;
    USE SIGNAL ;
    PORT
      LAYER M5 ;
        RECT  125.52 0 125.544 0.084 ;
    END
  END t_ext_d[37]
  PIN t_ext_d[38]
    DIRECTION INPUT ;
    USE SIGNAL ;
    PORT
      LAYER M5 ;
        RECT  125.616 0 125.64 0.084 ;
    END
  END t_ext_d[38]
  PIN t_ext_d[39]
    DIRECTION INPUT ;
    USE SIGNAL ;
    PORT
      LAYER M5 ;
        RECT  125.712 0 125.736 0.084 ;
    END
  END t_ext_d[39]
  PIN t_ext_d[3]
    DIRECTION INPUT ;
    USE SIGNAL ;
    PORT
      LAYER M5 ;
        RECT  118.416 0 118.44 0.084 ;
    END
  END t_ext_d[3]
  PIN t_ext_d[40]
    DIRECTION INPUT ;
    USE SIGNAL ;
    PORT
      LAYER M5 ;
        RECT  125.808 0 125.832 0.084 ;
    END
  END t_ext_d[40]
  PIN t_ext_d[41]
    DIRECTION INPUT ;
    USE SIGNAL ;
    PORT
      LAYER M5 ;
        RECT  125.904 0 125.928 0.084 ;
    END
  END t_ext_d[41]
  PIN t_ext_d[42]
    DIRECTION INPUT ;
    USE SIGNAL ;
    PORT
      LAYER M5 ;
        RECT  126 0 126.024 0.084 ;
    END
  END t_ext_d[42]
  PIN t_ext_d[43]
    DIRECTION INPUT ;
    USE SIGNAL ;
    PORT
      LAYER M5 ;
        RECT  126.096 0 126.12 0.084 ;
    END
  END t_ext_d[43]
  PIN t_ext_d[44]
    DIRECTION INPUT ;
    USE SIGNAL ;
    PORT
      LAYER M5 ;
        RECT  126.192 0 126.216 0.084 ;
    END
  END t_ext_d[44]
  PIN t_ext_d[45]
    DIRECTION INPUT ;
    USE SIGNAL ;
    PORT
      LAYER M5 ;
        RECT  126.288 0 126.312 0.084 ;
    END
  END t_ext_d[45]
  PIN t_ext_d[46]
    DIRECTION INPUT ;
    USE SIGNAL ;
    PORT
      LAYER M5 ;
        RECT  126.384 0 126.408 0.084 ;
    END
  END t_ext_d[46]
  PIN t_ext_d[47]
    DIRECTION INPUT ;
    USE SIGNAL ;
    PORT
      LAYER M5 ;
        RECT  126.48 0 126.504 0.084 ;
    END
  END t_ext_d[47]
  PIN t_ext_d[48]
    DIRECTION INPUT ;
    USE SIGNAL ;
    PORT
      LAYER M5 ;
        RECT  126.576 0 126.6 0.084 ;
    END
  END t_ext_d[48]
  PIN t_ext_d[49]
    DIRECTION INPUT ;
    USE SIGNAL ;
    PORT
      LAYER M5 ;
        RECT  126.672 0 126.696 0.084 ;
    END
  END t_ext_d[49]
  PIN t_ext_d[4]
    DIRECTION INPUT ;
    USE SIGNAL ;
    PORT
      LAYER M5 ;
        RECT  118.512 0 118.536 0.084 ;
    END
  END t_ext_d[4]
  PIN t_ext_d[50]
    DIRECTION INPUT ;
    USE SIGNAL ;
    PORT
      LAYER M5 ;
        RECT  126.768 0 126.792 0.084 ;
    END
  END t_ext_d[50]
  PIN t_ext_d[51]
    DIRECTION INPUT ;
    USE SIGNAL ;
    PORT
      LAYER M5 ;
        RECT  126.864 0 126.888 0.084 ;
    END
  END t_ext_d[51]
  PIN t_ext_d[52]
    DIRECTION INPUT ;
    USE SIGNAL ;
    PORT
      LAYER M5 ;
        RECT  126.96 0 126.984 0.084 ;
    END
  END t_ext_d[52]
  PIN t_ext_d[53]
    DIRECTION INPUT ;
    USE SIGNAL ;
    PORT
      LAYER M5 ;
        RECT  127.056 0 127.08 0.084 ;
    END
  END t_ext_d[53]
  PIN t_ext_d[5]
    DIRECTION INPUT ;
    USE SIGNAL ;
    PORT
      LAYER M5 ;
        RECT  118.608 0 118.632 0.084 ;
    END
  END t_ext_d[5]
  PIN t_ext_d[6]
    DIRECTION INPUT ;
    USE SIGNAL ;
    PORT
      LAYER M5 ;
        RECT  118.704 0 118.728 0.084 ;
    END
  END t_ext_d[6]
  PIN t_ext_d[7]
    DIRECTION INPUT ;
    USE SIGNAL ;
    PORT
      LAYER M5 ;
        RECT  118.8 0 118.824 0.084 ;
    END
  END t_ext_d[7]
  PIN t_ext_d[8]
    DIRECTION INPUT ;
    USE SIGNAL ;
    PORT
      LAYER M5 ;
        RECT  118.896 0 118.92 0.084 ;
    END
  END t_ext_d[8]
  PIN t_ext_d[9]
    DIRECTION INPUT ;
    USE SIGNAL ;
    PORT
      LAYER M5 ;
        RECT  118.992 0 119.016 0.084 ;
    END
  END t_ext_d[9]
  PIN t_ext_v
    DIRECTION INPUT ;
    USE SIGNAL ;
    PORT
      LAYER M5 ;
        RECT  127.152 0 127.176 0.084 ;
    END
  END t_ext_v
  PIN t_idle
    DIRECTION INPUT ;
    USE SIGNAL ;
    PORT
      LAYER M5 ;
        RECT  127.248 0 127.272 0.084 ;
    END
  END t_idle
  PIN t_k[0]
    DIRECTION OUTPUT ;
    USE SIGNAL ;
    PORT
      LAYER M5 ;
        RECT  127.344 0 127.368 0.084 ;
    END
  END t_k[0]
  PIN t_k[10]
    DIRECTION OUTPUT ;
    USE SIGNAL ;
    PORT
      LAYER M5 ;
        RECT  106.032 0 106.056 0.084 ;
    END
  END t_k[10]
  PIN t_k[11]
    DIRECTION OUTPUT ;
    USE SIGNAL ;
    PORT
      LAYER M5 ;
        RECT  106.128 0 106.152 0.084 ;
    END
  END t_k[11]
  PIN t_k[1]
    DIRECTION OUTPUT ;
    USE SIGNAL ;
    PORT
      LAYER M5 ;
        RECT  127.44 0 127.464 0.084 ;
    END
  END t_k[1]
  PIN t_k[2]
    DIRECTION OUTPUT ;
    USE SIGNAL ;
    PORT
      LAYER M5 ;
        RECT  127.536 0 127.56 0.084 ;
    END
  END t_k[2]
  PIN t_k[3]
    DIRECTION OUTPUT ;
    USE SIGNAL ;
    PORT
      LAYER M5 ;
        RECT  127.632 0 127.656 0.084 ;
    END
  END t_k[3]
  PIN t_k[4]
    DIRECTION OUTPUT ;
    USE SIGNAL ;
    PORT
      LAYER M5 ;
        RECT  127.728 0 127.752 0.084 ;
    END
  END t_k[4]
  PIN t_k[5]
    DIRECTION OUTPUT ;
    USE SIGNAL ;
    PORT
      LAYER M5 ;
        RECT  127.824 0 127.848 0.084 ;
    END
  END t_k[5]
  PIN t_k[6]
    DIRECTION OUTPUT ;
    USE SIGNAL ;
    PORT
      LAYER M5 ;
        RECT  105.648 0 105.672 0.084 ;
    END
  END t_k[6]
  PIN t_k[7]
    DIRECTION OUTPUT ;
    USE SIGNAL ;
    PORT
      LAYER M5 ;
        RECT  105.744 0 105.768 0.084 ;
    END
  END t_k[7]
  PIN t_k[8]
    DIRECTION OUTPUT ;
    USE SIGNAL ;
    PORT
      LAYER M5 ;
        RECT  105.84 0 105.864 0.084 ;
    END
  END t_k[8]
  PIN t_k[9]
    DIRECTION OUTPUT ;
    USE SIGNAL ;
    PORT
      LAYER M5 ;
        RECT  105.936 0 105.96 0.084 ;
    END
  END t_k[9]
  PIN t_op_cr
    DIRECTION INPUT ;
    USE SIGNAL ;
    PORT
      LAYER M5 ;
        RECT  106.224 0 106.248 0.084 ;
    END
  END t_op_cr
  PIN t_op_ext
    DIRECTION OUTPUT ;
    USE SIGNAL ;
    PORT
      LAYER M5 ;
        RECT  106.32 0 106.344 0.084 ;
    END
  END t_op_ext
  PIN t_op_v
    DIRECTION OUTPUT ;
    USE SIGNAL ;
    PORT
      LAYER M5 ;
        RECT  106.416 0 106.44 0.084 ;
    END
  END t_op_v
  PIN t_op_x[0]
    DIRECTION OUTPUT ;
    USE SIGNAL ;
    PORT
      LAYER M5 ;
        RECT  106.512 0 106.536 0.084 ;
    END
  END t_op_x[0]
  PIN t_op_x[10]
    DIRECTION OUTPUT ;
    USE SIGNAL ;
    PORT
      LAYER M5 ;
        RECT  107.472 0 107.496 0.084 ;
    END
  END t_op_x[10]
  PIN t_op_x[11]
    DIRECTION OUTPUT ;
    USE SIGNAL ;
    PORT
      LAYER M5 ;
        RECT  107.568 0 107.592 0.084 ;
    END
  END t_op_x[11]
  PIN t_op_x[12]
    DIRECTION OUTPUT ;
    USE SIGNAL ;
    PORT
      LAYER M5 ;
        RECT  107.664 0 107.688 0.084 ;
    END
  END t_op_x[12]
  PIN t_op_x[13]
    DIRECTION OUTPUT ;
    USE SIGNAL ;
    PORT
      LAYER M5 ;
        RECT  107.76 0 107.784 0.084 ;
    END
  END t_op_x[13]
  PIN t_op_x[14]
    DIRECTION OUTPUT ;
    USE SIGNAL ;
    PORT
      LAYER M5 ;
        RECT  107.856 0 107.88 0.084 ;
    END
  END t_op_x[14]
  PIN t_op_x[15]
    DIRECTION OUTPUT ;
    USE SIGNAL ;
    PORT
      LAYER M5 ;
        RECT  107.952 0 107.976 0.084 ;
    END
  END t_op_x[15]
  PIN t_op_x[16]
    DIRECTION OUTPUT ;
    USE SIGNAL ;
    PORT
      LAYER M5 ;
        RECT  108.048 0 108.072 0.084 ;
    END
  END t_op_x[16]
  PIN t_op_x[17]
    DIRECTION OUTPUT ;
    USE SIGNAL ;
    PORT
      LAYER M5 ;
        RECT  108.144 0 108.168 0.084 ;
    END
  END t_op_x[17]
  PIN t_op_x[18]
    DIRECTION OUTPUT ;
    USE SIGNAL ;
    PORT
      LAYER M5 ;
        RECT  108.24 0 108.264 0.084 ;
    END
  END t_op_x[18]
  PIN t_op_x[19]
    DIRECTION OUTPUT ;
    USE SIGNAL ;
    PORT
      LAYER M5 ;
        RECT  108.336 0 108.36 0.084 ;
    END
  END t_op_x[19]
  PIN t_op_x[1]
    DIRECTION OUTPUT ;
    USE SIGNAL ;
    PORT
      LAYER M5 ;
        RECT  106.608 0 106.632 0.084 ;
    END
  END t_op_x[1]
  PIN t_op_x[20]
    DIRECTION OUTPUT ;
    USE SIGNAL ;
    PORT
      LAYER M5 ;
        RECT  108.432 0 108.456 0.084 ;
    END
  END t_op_x[20]
  PIN t_op_x[21]
    DIRECTION OUTPUT ;
    USE SIGNAL ;
    PORT
      LAYER M5 ;
        RECT  108.528 0 108.552 0.084 ;
    END
  END t_op_x[21]
  PIN t_op_x[22]
    DIRECTION OUTPUT ;
    USE SIGNAL ;
    PORT
      LAYER M5 ;
        RECT  108.624 0 108.648 0.084 ;
    END
  END t_op_x[22]
  PIN t_op_x[23]
    DIRECTION OUTPUT ;
    USE SIGNAL ;
    PORT
      LAYER M5 ;
        RECT  108.72 0 108.744 0.084 ;
    END
  END t_op_x[23]
  PIN t_op_x[24]
    DIRECTION OUTPUT ;
    USE SIGNAL ;
    PORT
      LAYER M5 ;
        RECT  108.816 0 108.84 0.084 ;
    END
  END t_op_x[24]
  PIN t_op_x[25]
    DIRECTION OUTPUT ;
    USE SIGNAL ;
    PORT
      LAYER M5 ;
        RECT  108.912 0 108.936 0.084 ;
    END
  END t_op_x[25]
  PIN t_op_x[26]
    DIRECTION OUTPUT ;
    USE SIGNAL ;
    PORT
      LAYER M5 ;
        RECT  109.008 0 109.032 0.084 ;
    END
  END t_op_x[26]
  PIN t_op_x[27]
    DIRECTION OUTPUT ;
    USE SIGNAL ;
    PORT
      LAYER M5 ;
        RECT  109.104 0 109.128 0.084 ;
    END
  END t_op_x[27]
  PIN t_op_x[28]
    DIRECTION OUTPUT ;
    USE SIGNAL ;
    PORT
      LAYER M5 ;
        RECT  109.2 0 109.224 0.084 ;
    END
  END t_op_x[28]
  PIN t_op_x[29]
    DIRECTION OUTPUT ;
    USE SIGNAL ;
    PORT
      LAYER M5 ;
        RECT  109.296 0 109.32 0.084 ;
    END
  END t_op_x[29]
  PIN t_op_x[2]
    DIRECTION OUTPUT ;
    USE SIGNAL ;
    PORT
      LAYER M5 ;
        RECT  106.704 0 106.728 0.084 ;
    END
  END t_op_x[2]
  PIN t_op_x[30]
    DIRECTION OUTPUT ;
    USE SIGNAL ;
    PORT
      LAYER M5 ;
        RECT  109.392 0 109.416 0.084 ;
    END
  END t_op_x[30]
  PIN t_op_x[31]
    DIRECTION OUTPUT ;
    USE SIGNAL ;
    PORT
      LAYER M5 ;
        RECT  109.488 0 109.512 0.084 ;
    END
  END t_op_x[31]
  PIN t_op_x[32]
    DIRECTION OUTPUT ;
    USE SIGNAL ;
    PORT
      LAYER M5 ;
        RECT  109.584 0 109.608 0.084 ;
    END
  END t_op_x[32]
  PIN t_op_x[33]
    DIRECTION OUTPUT ;
    USE SIGNAL ;
    PORT
      LAYER M5 ;
        RECT  109.68 0 109.704 0.084 ;
    END
  END t_op_x[33]
  PIN t_op_x[34]
    DIRECTION OUTPUT ;
    USE SIGNAL ;
    PORT
      LAYER M5 ;
        RECT  109.776 0 109.8 0.084 ;
    END
  END t_op_x[34]
  PIN t_op_x[35]
    DIRECTION OUTPUT ;
    USE SIGNAL ;
    PORT
      LAYER M5 ;
        RECT  109.872 0 109.896 0.084 ;
    END
  END t_op_x[35]
  PIN t_op_x[36]
    DIRECTION OUTPUT ;
    USE SIGNAL ;
    PORT
      LAYER M5 ;
        RECT  109.968 0 109.992 0.084 ;
    END
  END t_op_x[36]
  PIN t_op_x[37]
    DIRECTION OUTPUT ;
    USE SIGNAL ;
    PORT
      LAYER M5 ;
        RECT  110.064 0 110.088 0.084 ;
    END
  END t_op_x[37]
  PIN t_op_x[38]
    DIRECTION OUTPUT ;
    USE SIGNAL ;
    PORT
      LAYER M5 ;
        RECT  110.16 0 110.184 0.084 ;
    END
  END t_op_x[38]
  PIN t_op_x[39]
    DIRECTION OUTPUT ;
    USE SIGNAL ;
    PORT
      LAYER M5 ;
        RECT  110.256 0 110.28 0.084 ;
    END
  END t_op_x[39]
  PIN t_op_x[3]
    DIRECTION OUTPUT ;
    USE SIGNAL ;
    PORT
      LAYER M5 ;
        RECT  106.8 0 106.824 0.084 ;
    END
  END t_op_x[3]
  PIN t_op_x[40]
    DIRECTION OUTPUT ;
    USE SIGNAL ;
    PORT
      LAYER M5 ;
        RECT  110.352 0 110.376 0.084 ;
    END
  END t_op_x[40]
  PIN t_op_x[41]
    DIRECTION OUTPUT ;
    USE SIGNAL ;
    PORT
      LAYER M5 ;
        RECT  110.448 0 110.472 0.084 ;
    END
  END t_op_x[41]
  PIN t_op_x[42]
    DIRECTION OUTPUT ;
    USE SIGNAL ;
    PORT
      LAYER M5 ;
        RECT  110.544 0 110.568 0.084 ;
    END
  END t_op_x[42]
  PIN t_op_x[43]
    DIRECTION OUTPUT ;
    USE SIGNAL ;
    PORT
      LAYER M5 ;
        RECT  110.64 0 110.664 0.084 ;
    END
  END t_op_x[43]
  PIN t_op_x[44]
    DIRECTION OUTPUT ;
    USE SIGNAL ;
    PORT
      LAYER M5 ;
        RECT  110.736 0 110.76 0.084 ;
    END
  END t_op_x[44]
  PIN t_op_x[45]
    DIRECTION OUTPUT ;
    USE SIGNAL ;
    PORT
      LAYER M5 ;
        RECT  110.832 0 110.856 0.084 ;
    END
  END t_op_x[45]
  PIN t_op_x[46]
    DIRECTION OUTPUT ;
    USE SIGNAL ;
    PORT
      LAYER M5 ;
        RECT  110.928 0 110.952 0.084 ;
    END
  END t_op_x[46]
  PIN t_op_x[47]
    DIRECTION OUTPUT ;
    USE SIGNAL ;
    PORT
      LAYER M5 ;
        RECT  111.024 0 111.048 0.084 ;
    END
  END t_op_x[47]
  PIN t_op_x[48]
    DIRECTION OUTPUT ;
    USE SIGNAL ;
    PORT
      LAYER M5 ;
        RECT  111.12 0 111.144 0.084 ;
    END
  END t_op_x[48]
  PIN t_op_x[49]
    DIRECTION OUTPUT ;
    USE SIGNAL ;
    PORT
      LAYER M5 ;
        RECT  111.216 0 111.24 0.084 ;
    END
  END t_op_x[49]
  PIN t_op_x[4]
    DIRECTION OUTPUT ;
    USE SIGNAL ;
    PORT
      LAYER M5 ;
        RECT  106.896 0 106.92 0.084 ;
    END
  END t_op_x[4]
  PIN t_op_x[50]
    DIRECTION OUTPUT ;
    USE SIGNAL ;
    PORT
      LAYER M5 ;
        RECT  111.312 0 111.336 0.084 ;
    END
  END t_op_x[50]
  PIN t_op_x[51]
    DIRECTION OUTPUT ;
    USE SIGNAL ;
    PORT
      LAYER M5 ;
        RECT  111.408 0 111.432 0.084 ;
    END
  END t_op_x[51]
  PIN t_op_x[52]
    DIRECTION OUTPUT ;
    USE SIGNAL ;
    PORT
      LAYER M5 ;
        RECT  111.504 0 111.528 0.084 ;
    END
  END t_op_x[52]
  PIN t_op_x[53]
    DIRECTION OUTPUT ;
    USE SIGNAL ;
    PORT
      LAYER M5 ;
        RECT  111.6 0 111.624 0.084 ;
    END
  END t_op_x[53]
  PIN t_op_x[5]
    DIRECTION OUTPUT ;
    USE SIGNAL ;
    PORT
      LAYER M5 ;
        RECT  106.992 0 107.016 0.084 ;
    END
  END t_op_x[5]
  PIN t_op_x[6]
    DIRECTION OUTPUT ;
    USE SIGNAL ;
    PORT
      LAYER M5 ;
        RECT  107.088 0 107.112 0.084 ;
    END
  END t_op_x[6]
  PIN t_op_x[7]
    DIRECTION OUTPUT ;
    USE SIGNAL ;
    PORT
      LAYER M5 ;
        RECT  107.184 0 107.208 0.084 ;
    END
  END t_op_x[7]
  PIN t_op_x[8]
    DIRECTION OUTPUT ;
    USE SIGNAL ;
    PORT
      LAYER M5 ;
        RECT  107.28 0 107.304 0.084 ;
    END
  END t_op_x[8]
  PIN t_op_x[9]
    DIRECTION OUTPUT ;
    USE SIGNAL ;
    PORT
      LAYER M5 ;
        RECT  107.376 0 107.4 0.084 ;
    END
  END t_op_x[9]
  PIN t_root_key[0]
    DIRECTION INPUT ;
    USE SIGNAL ;
    PORT
      LAYER M5 ;
        RECT  111.696 0 111.72 0.084 ;
    END
  END t_root_key[0]
  PIN t_root_key[10]
    DIRECTION INPUT ;
    USE SIGNAL ;
    PORT
      LAYER M5 ;
        RECT  121.872 0 121.896 0.084 ;
    END
  END t_root_key[10]
  PIN t_root_key[11]
    DIRECTION INPUT ;
    USE SIGNAL ;
    PORT
      LAYER M5 ;
        RECT  121.968 0 121.992 0.084 ;
    END
  END t_root_key[11]
  PIN t_root_key[12]
    DIRECTION INPUT ;
    USE SIGNAL ;
    PORT
      LAYER M5 ;
        RECT  122.064 0 122.088 0.084 ;
    END
  END t_root_key[12]
  PIN t_root_key[13]
    DIRECTION INPUT ;
    USE SIGNAL ;
    PORT
      LAYER M5 ;
        RECT  122.16 0 122.184 0.084 ;
    END
  END t_root_key[13]
  PIN t_root_key[14]
    DIRECTION INPUT ;
    USE SIGNAL ;
    PORT
      LAYER M5 ;
        RECT  122.256 0 122.28 0.084 ;
    END
  END t_root_key[14]
  PIN t_root_key[15]
    DIRECTION INPUT ;
    USE SIGNAL ;
    PORT
      LAYER M5 ;
        RECT  122.352 0 122.376 0.084 ;
    END
  END t_root_key[15]
  PIN t_root_key[16]
    DIRECTION INPUT ;
    USE SIGNAL ;
    PORT
      LAYER M5 ;
        RECT  122.448 0 122.472 0.084 ;
    END
  END t_root_key[16]
  PIN t_root_key[17]
    DIRECTION INPUT ;
    USE SIGNAL ;
    PORT
      LAYER M5 ;
        RECT  122.544 0 122.568 0.084 ;
    END
  END t_root_key[17]
  PIN t_root_key[18]
    DIRECTION INPUT ;
    USE SIGNAL ;
    PORT
      LAYER M5 ;
        RECT  122.64 0 122.664 0.084 ;
    END
  END t_root_key[18]
  PIN t_root_key[19]
    DIRECTION INPUT ;
    USE SIGNAL ;
    PORT
      LAYER M5 ;
        RECT  122.736 0 122.76 0.084 ;
    END
  END t_root_key[19]
  PIN t_root_key[1]
    DIRECTION INPUT ;
    USE SIGNAL ;
    PORT
      LAYER M5 ;
        RECT  121.008 0 121.032 0.084 ;
    END
  END t_root_key[1]
  PIN t_root_key[20]
    DIRECTION INPUT ;
    USE SIGNAL ;
    PORT
      LAYER M5 ;
        RECT  122.832 0 122.856 0.084 ;
    END
  END t_root_key[20]
  PIN t_root_key[21]
    DIRECTION INPUT ;
    USE SIGNAL ;
    PORT
      LAYER M5 ;
        RECT  122.928 0 122.952 0.084 ;
    END
  END t_root_key[21]
  PIN t_root_key[22]
    DIRECTION INPUT ;
    USE SIGNAL ;
    PORT
      LAYER M5 ;
        RECT  123.024 0 123.048 0.084 ;
    END
  END t_root_key[22]
  PIN t_root_key[23]
    DIRECTION INPUT ;
    USE SIGNAL ;
    PORT
      LAYER M5 ;
        RECT  123.12 0 123.144 0.084 ;
    END
  END t_root_key[23]
  PIN t_root_key[24]
    DIRECTION INPUT ;
    USE SIGNAL ;
    PORT
      LAYER M5 ;
        RECT  123.216 0 123.24 0.084 ;
    END
  END t_root_key[24]
  PIN t_root_key[25]
    DIRECTION INPUT ;
    USE SIGNAL ;
    PORT
      LAYER M5 ;
        RECT  123.312 0 123.336 0.084 ;
    END
  END t_root_key[25]
  PIN t_root_key[26]
    DIRECTION INPUT ;
    USE SIGNAL ;
    PORT
      LAYER M5 ;
        RECT  123.408 0 123.432 0.084 ;
    END
  END t_root_key[26]
  PIN t_root_key[27]
    DIRECTION INPUT ;
    USE SIGNAL ;
    PORT
      LAYER M5 ;
        RECT  123.504 0 123.528 0.084 ;
    END
  END t_root_key[27]
  PIN t_root_key[28]
    DIRECTION INPUT ;
    USE SIGNAL ;
    PORT
      LAYER M5 ;
        RECT  123.6 0 123.624 0.084 ;
    END
  END t_root_key[28]
  PIN t_root_key[29]
    DIRECTION INPUT ;
    USE SIGNAL ;
    PORT
      LAYER M5 ;
        RECT  123.696 0 123.72 0.084 ;
    END
  END t_root_key[29]
  PIN t_root_key[2]
    DIRECTION INPUT ;
    USE SIGNAL ;
    PORT
      LAYER M5 ;
        RECT  121.104 0 121.128 0.084 ;
    END
  END t_root_key[2]
  PIN t_root_key[30]
    DIRECTION INPUT ;
    USE SIGNAL ;
    PORT
      LAYER M5 ;
        RECT  123.792 0 123.816 0.084 ;
    END
  END t_root_key[30]
  PIN t_root_key[31]
    DIRECTION INPUT ;
    USE SIGNAL ;
    PORT
      LAYER M5 ;
        RECT  123.888 0 123.912 0.084 ;
    END
  END t_root_key[31]
  PIN t_root_key[32]
    DIRECTION INPUT ;
    USE SIGNAL ;
    PORT
      LAYER M5 ;
        RECT  123.984 0 124.008 0.084 ;
    END
  END t_root_key[32]
  PIN t_root_key[33]
    DIRECTION INPUT ;
    USE SIGNAL ;
    PORT
      LAYER M5 ;
        RECT  128.976 0 129 0.084 ;
    END
  END t_root_key[33]
  PIN t_root_key[34]
    DIRECTION INPUT ;
    USE SIGNAL ;
    PORT
      LAYER M5 ;
        RECT  129.072 0 129.096 0.084 ;
    END
  END t_root_key[34]
  PIN t_root_key[35]
    DIRECTION INPUT ;
    USE SIGNAL ;
    PORT
      LAYER M5 ;
        RECT  129.168 0 129.192 0.084 ;
    END
  END t_root_key[35]
  PIN t_root_key[36]
    DIRECTION INPUT ;
    USE SIGNAL ;
    PORT
      LAYER M5 ;
        RECT  129.264 0 129.288 0.084 ;
    END
  END t_root_key[36]
  PIN t_root_key[37]
    DIRECTION INPUT ;
    USE SIGNAL ;
    PORT
      LAYER M5 ;
        RECT  129.36 0 129.384 0.084 ;
    END
  END t_root_key[37]
  PIN t_root_key[38]
    DIRECTION INPUT ;
    USE SIGNAL ;
    PORT
      LAYER M5 ;
        RECT  129.456 0 129.48 0.084 ;
    END
  END t_root_key[38]
  PIN t_root_key[39]
    DIRECTION INPUT ;
    USE SIGNAL ;
    PORT
      LAYER M5 ;
        RECT  129.552 0 129.576 0.084 ;
    END
  END t_root_key[39]
  PIN t_root_key[3]
    DIRECTION INPUT ;
    USE SIGNAL ;
    PORT
      LAYER M5 ;
        RECT  121.2 0 121.224 0.084 ;
    END
  END t_root_key[3]
  PIN t_root_key[40]
    DIRECTION INPUT ;
    USE SIGNAL ;
    PORT
      LAYER M5 ;
        RECT  129.648 0 129.672 0.084 ;
    END
  END t_root_key[40]
  PIN t_root_key[41]
    DIRECTION INPUT ;
    USE SIGNAL ;
    PORT
      LAYER M5 ;
        RECT  129.744 0 129.768 0.084 ;
    END
  END t_root_key[41]
  PIN t_root_key[42]
    DIRECTION INPUT ;
    USE SIGNAL ;
    PORT
      LAYER M5 ;
        RECT  129.84 0 129.864 0.084 ;
    END
  END t_root_key[42]
  PIN t_root_key[43]
    DIRECTION INPUT ;
    USE SIGNAL ;
    PORT
      LAYER M5 ;
        RECT  129.936 0 129.96 0.084 ;
    END
  END t_root_key[43]
  PIN t_root_key[44]
    DIRECTION INPUT ;
    USE SIGNAL ;
    PORT
      LAYER M5 ;
        RECT  130.032 0 130.056 0.084 ;
    END
  END t_root_key[44]
  PIN t_root_key[45]
    DIRECTION INPUT ;
    USE SIGNAL ;
    PORT
      LAYER M5 ;
        RECT  130.128 0 130.152 0.084 ;
    END
  END t_root_key[45]
  PIN t_root_key[46]
    DIRECTION INPUT ;
    USE SIGNAL ;
    PORT
      LAYER M5 ;
        RECT  130.224 0 130.248 0.084 ;
    END
  END t_root_key[46]
  PIN t_root_key[47]
    DIRECTION INPUT ;
    USE SIGNAL ;
    PORT
      LAYER M5 ;
        RECT  130.32 0 130.344 0.084 ;
    END
  END t_root_key[47]
  PIN t_root_key[48]
    DIRECTION INPUT ;
    USE SIGNAL ;
    PORT
      LAYER M5 ;
        RECT  130.416 0 130.44 0.084 ;
    END
  END t_root_key[48]
  PIN t_root_key[49]
    DIRECTION INPUT ;
    USE SIGNAL ;
    PORT
      LAYER M5 ;
        RECT  130.512 0 130.536 0.084 ;
    END
  END t_root_key[49]
  PIN t_root_key[4]
    DIRECTION INPUT ;
    USE SIGNAL ;
    PORT
      LAYER M5 ;
        RECT  121.296 0 121.32 0.084 ;
    END
  END t_root_key[4]
  PIN t_root_key[50]
    DIRECTION INPUT ;
    USE SIGNAL ;
    PORT
      LAYER M5 ;
        RECT  130.608 0 130.632 0.084 ;
    END
  END t_root_key[50]
  PIN t_root_key[51]
    DIRECTION INPUT ;
    USE SIGNAL ;
    PORT
      LAYER M5 ;
        RECT  130.704 0 130.728 0.084 ;
    END
  END t_root_key[51]
  PIN t_root_key[52]
    DIRECTION INPUT ;
    USE SIGNAL ;
    PORT
      LAYER M5 ;
        RECT  130.8 0 130.824 0.084 ;
    END
  END t_root_key[52]
  PIN t_root_key[5]
    DIRECTION INPUT ;
    USE SIGNAL ;
    PORT
      LAYER M5 ;
        RECT  121.392 0 121.416 0.084 ;
    END
  END t_root_key[5]
  PIN t_root_key[6]
    DIRECTION INPUT ;
    USE SIGNAL ;
    PORT
      LAYER M5 ;
        RECT  121.488 0 121.512 0.084 ;
    END
  END t_root_key[6]
  PIN t_root_key[7]
    DIRECTION INPUT ;
    USE SIGNAL ;
    PORT
      LAYER M5 ;
        RECT  121.584 0 121.608 0.084 ;
    END
  END t_root_key[7]
  PIN t_root_key[8]
    DIRECTION INPUT ;
    USE SIGNAL ;
    PORT
      LAYER M5 ;
        RECT  121.68 0 121.704 0.084 ;
    END
  END t_root_key[8]
  PIN t_root_key[9]
    DIRECTION INPUT ;
    USE SIGNAL ;
    PORT
      LAYER M5 ;
        RECT  121.776 0 121.8 0.084 ;
    END
  END t_root_key[9]
  PIN x
    DIRECTION OUTPUT ;
    USE SIGNAL ;
    PORT
      LAYER M5 ;
        RECT  188.496 116.556 188.52 116.64 ;
    END
  END x
  PIN VDD
    DIRECTION INOUT ;
    USE POWER ;
    PORT
      LAYER M5 ;
        RECT  256.392 2.151 256.512 114.489 ;
        RECT  250.992 2.151 251.112 114.489 ;
        RECT  245.592 2.151 245.712 114.489 ;
        RECT  240.192 2.151 240.312 114.489 ;
        RECT  234.792 2.151 234.912 114.489 ;
        RECT  229.392 2.151 229.512 114.489 ;
        RECT  223.992 2.151 224.112 114.489 ;
        RECT  218.592 2.151 218.712 114.489 ;
        RECT  213.192 2.151 213.312 114.489 ;
        RECT  207.792 2.151 207.912 114.489 ;
        RECT  202.392 2.151 202.512 114.489 ;
        RECT  196.992 2.151 197.112 114.489 ;
        RECT  191.592 2.151 191.712 114.489 ;
        RECT  186.192 2.151 186.312 114.489 ;
        RECT  180.792 2.151 180.912 114.489 ;
        RECT  175.392 2.151 175.512 114.489 ;
        RECT  169.992 2.151 170.112 114.489 ;
        RECT  164.592 2.151 164.712 114.489 ;
        RECT  159.192 2.151 159.312 114.489 ;
        RECT  153.792 2.151 153.912 114.489 ;
        RECT  148.392 2.151 148.512 114.489 ;
        RECT  142.992 2.151 143.112 114.489 ;
        RECT  137.592 2.151 137.712 114.489 ;
        RECT  132.192 2.151 132.312 114.489 ;
        RECT  126.792 2.151 126.912 114.489 ;
        RECT  121.392 2.151 121.512 114.489 ;
        RECT  115.992 2.151 116.112 114.489 ;
        RECT  110.592 2.151 110.712 114.489 ;
        RECT  105.192 2.151 105.312 114.489 ;
        RECT  99.792 2.151 99.912 114.489 ;
        RECT  94.392 2.151 94.512 114.489 ;
        RECT  88.992 2.151 89.112 114.489 ;
        RECT  83.592 2.151 83.712 114.489 ;
        RECT  78.192 2.151 78.312 114.489 ;
        RECT  72.792 2.151 72.912 114.489 ;
        RECT  67.392 2.151 67.512 114.489 ;
        RECT  61.992 2.151 62.112 114.489 ;
        RECT  56.592 2.151 56.712 114.489 ;
        RECT  51.192 2.151 51.312 114.489 ;
        RECT  45.792 2.151 45.912 114.489 ;
        RECT  40.392 2.151 40.512 114.489 ;
        RECT  34.992 2.151 35.112 114.489 ;
        RECT  29.592 2.151 29.712 114.489 ;
        RECT  24.192 2.151 24.312 114.489 ;
        RECT  18.792 2.151 18.912 114.489 ;
        RECT  13.392 2.151 13.512 114.489 ;
        RECT  7.992 2.151 8.112 114.489 ;
        RECT  2.592 2.151 2.712 114.489 ;
    END
  END VDD
  PIN VSS
    DIRECTION INOUT ;
    USE GROUND ;
    PORT
      LAYER M5 ;
        RECT  256.2 2.137 256.32 114.503 ;
        RECT  250.8 2.137 250.92 114.503 ;
        RECT  245.4 2.137 245.52 114.503 ;
        RECT  240 2.137 240.12 114.503 ;
        RECT  234.6 2.137 234.72 114.503 ;
        RECT  229.2 2.137 229.32 114.503 ;
        RECT  223.8 2.137 223.92 114.503 ;
        RECT  218.4 2.137 218.52 114.503 ;
        RECT  213 2.137 213.12 114.503 ;
        RECT  207.6 2.137 207.72 114.503 ;
        RECT  202.2 2.137 202.32 114.503 ;
        RECT  196.8 2.137 196.92 114.503 ;
        RECT  191.4 2.137 191.52 114.503 ;
        RECT  186 2.137 186.12 114.503 ;
        RECT  180.6 2.137 180.72 114.503 ;
        RECT  175.2 2.137 175.32 114.503 ;
        RECT  169.8 2.137 169.92 114.503 ;
        RECT  164.4 2.137 164.52 114.503 ;
        RECT  159 2.137 159.12 114.503 ;
        RECT  153.6 2.137 153.72 114.503 ;
        RECT  148.2 2.137 148.32 114.503 ;
        RECT  142.8 2.137 142.92 114.503 ;
        RECT  137.4 2.137 137.52 114.503 ;
        RECT  132 2.137 132.12 114.503 ;
        RECT  126.6 2.137 126.72 114.503 ;
        RECT  121.2 2.137 121.32 114.503 ;
        RECT  115.8 2.137 115.92 114.503 ;
        RECT  110.4 2.137 110.52 114.503 ;
        RECT  105 2.137 105.12 114.503 ;
        RECT  99.6 2.137 99.72 114.503 ;
        RECT  94.2 2.137 94.32 114.503 ;
        RECT  88.8 2.137 88.92 114.503 ;
        RECT  83.4 2.137 83.52 114.503 ;
        RECT  78 2.137 78.12 114.503 ;
        RECT  72.6 2.137 72.72 114.503 ;
        RECT  67.2 2.137 67.32 114.503 ;
        RECT  61.8 2.137 61.92 114.503 ;
        RECT  56.4 2.137 56.52 114.503 ;
        RECT  51 2.137 51.12 114.503 ;
        RECT  45.6 2.137 45.72 114.503 ;
        RECT  40.2 2.137 40.32 114.503 ;
        RECT  34.8 2.137 34.92 114.503 ;
        RECT  29.4 2.137 29.52 114.503 ;
        RECT  24 2.137 24.12 114.503 ;
        RECT  18.6 2.137 18.72 114.503 ;
        RECT  13.2 2.137 13.32 114.503 ;
        RECT  7.8 2.137 7.92 114.503 ;
        RECT  2.4 2.137 2.52 114.503 ;
    END
  END VSS
  OBS
    LAYER RVTN ;
     RECT  2.16 2.16 257.04 2.295 ;
     RECT  2.16 2.565 257.04 2.835 ;
     RECT  2.16 3.105 257.04 3.375 ;
     RECT  2.16 3.645 257.04 3.915 ;
     RECT  2.16 4.185 257.04 4.455 ;
     RECT  2.16 4.725 257.04 4.995 ;
     RECT  2.16 5.265 257.04 5.535 ;
     RECT  2.16 5.805 257.04 6.075 ;
     RECT  2.16 6.345 257.04 6.615 ;
     RECT  2.16 6.885 257.04 7.155 ;
     RECT  2.16 7.425 257.04 7.695 ;
     RECT  2.16 7.965 257.04 8.235 ;
     RECT  2.16 8.505 257.04 8.775 ;
     RECT  2.16 9.045 257.04 9.315 ;
     RECT  2.16 9.585 257.04 9.855 ;
     RECT  2.16 10.125 257.04 10.395 ;
     RECT  2.16 10.665 257.04 10.935 ;
     RECT  2.16 11.205 257.04 11.475 ;
     RECT  2.16 11.745 257.04 12.015 ;
     RECT  2.16 12.285 257.04 12.555 ;
     RECT  2.16 12.825 257.04 13.095 ;
     RECT  2.16 13.365 257.04 13.635 ;
     RECT  2.16 13.905 257.04 14.175 ;
     RECT  2.16 14.445 257.04 14.715 ;
     RECT  2.16 14.985 257.04 15.255 ;
     RECT  2.16 15.525 257.04 15.795 ;
     RECT  2.16 16.065 257.04 16.335 ;
     RECT  2.16 16.605 257.04 16.875 ;
     RECT  2.16 17.145 257.04 17.415 ;
     RECT  2.16 17.685 257.04 17.955 ;
     RECT  2.16 18.225 257.04 18.495 ;
     RECT  2.16 18.765 257.04 19.035 ;
     RECT  2.16 19.305 257.04 19.575 ;
     RECT  2.16 19.845 257.04 20.115 ;
     RECT  2.16 20.385 257.04 20.655 ;
     RECT  2.16 20.925 257.04 21.195 ;
     RECT  2.16 21.465 257.04 21.6 ;
     RECT  2.16 21.6 40.284 21.735 ;
     RECT  219.132 21.6 257.04 21.735 ;
     RECT  2.16 22.005 40.284 22.275 ;
     RECT  219.132 22.005 257.04 22.275 ;
     RECT  2.16 22.545 40.284 22.815 ;
     RECT  219.132 22.545 257.04 22.815 ;
     RECT  2.16 23.085 40.284 23.355 ;
     RECT  219.132 23.085 257.04 23.355 ;
     RECT  2.16 23.625 40.284 23.895 ;
     RECT  219.132 23.625 257.04 23.895 ;
     RECT  2.16 24.165 40.284 24.435 ;
     RECT  219.132 24.165 257.04 24.435 ;
     RECT  2.16 24.705 40.284 24.975 ;
     RECT  219.132 24.705 257.04 24.975 ;
     RECT  2.16 25.245 40.284 25.515 ;
     RECT  219.132 25.245 257.04 25.515 ;
     RECT  2.16 25.785 40.284 26.055 ;
     RECT  219.132 25.785 257.04 26.055 ;
     RECT  2.16 26.325 40.284 26.595 ;
     RECT  219.132 26.325 257.04 26.595 ;
     RECT  2.16 26.865 40.284 27.135 ;
     RECT  219.132 26.865 257.04 27.135 ;
     RECT  2.16 27.405 40.284 27.675 ;
     RECT  219.132 27.405 257.04 27.675 ;
     RECT  2.16 27.945 40.284 28.215 ;
     RECT  219.132 27.945 257.04 28.215 ;
     RECT  2.16 28.485 40.284 28.755 ;
     RECT  219.132 28.485 257.04 28.755 ;
     RECT  2.16 29.025 40.284 29.295 ;
     RECT  219.132 29.025 257.04 29.295 ;
     RECT  2.16 29.565 40.284 29.835 ;
     RECT  219.132 29.565 257.04 29.835 ;
     RECT  2.16 30.105 40.284 30.375 ;
     RECT  219.132 30.105 257.04 30.375 ;
     RECT  2.16 30.645 40.284 30.915 ;
     RECT  219.132 30.645 257.04 30.915 ;
     RECT  2.16 31.185 40.284 31.455 ;
     RECT  219.132 31.185 257.04 31.455 ;
     RECT  2.16 31.725 40.284 31.995 ;
     RECT  219.132 31.725 257.04 31.995 ;
     RECT  2.16 32.265 40.284 32.535 ;
     RECT  219.132 32.265 257.04 32.535 ;
     RECT  2.16 32.805 40.284 33.075 ;
     RECT  219.132 32.805 257.04 33.075 ;
     RECT  2.16 33.345 40.284 33.615 ;
     RECT  219.132 33.345 257.04 33.615 ;
     RECT  2.16 33.885 40.284 34.155 ;
     RECT  219.132 33.885 257.04 34.155 ;
     RECT  2.16 34.425 40.284 34.695 ;
     RECT  219.132 34.425 257.04 34.695 ;
     RECT  2.16 34.965 40.284 35.235 ;
     RECT  219.132 34.965 257.04 35.235 ;
     RECT  2.16 35.505 40.284 35.775 ;
     RECT  219.132 35.505 257.04 35.775 ;
     RECT  2.16 36.045 40.284 36.315 ;
     RECT  219.132 36.045 257.04 36.315 ;
     RECT  2.16 36.585 40.284 36.855 ;
     RECT  219.132 36.585 257.04 36.855 ;
     RECT  2.16 37.125 40.284 37.395 ;
     RECT  219.132 37.125 257.04 37.395 ;
     RECT  2.16 37.665 40.284 37.935 ;
     RECT  219.132 37.665 257.04 37.935 ;
     RECT  2.16 38.205 40.284 38.475 ;
     RECT  219.132 38.205 257.04 38.475 ;
     RECT  2.16 38.745 40.284 39.015 ;
     RECT  219.132 38.745 257.04 39.015 ;
     RECT  2.16 39.285 40.284 39.555 ;
     RECT  219.132 39.285 257.04 39.555 ;
     RECT  2.16 39.825 40.284 40.095 ;
     RECT  219.132 39.825 257.04 40.095 ;
     RECT  2.16 40.365 40.284 40.635 ;
     RECT  219.132 40.365 257.04 40.635 ;
     RECT  2.16 40.905 40.284 41.175 ;
     RECT  219.132 40.905 257.04 41.175 ;
     RECT  2.16 41.445 40.284 41.715 ;
     RECT  219.132 41.445 257.04 41.715 ;
     RECT  2.16 41.985 40.284 42.255 ;
     RECT  219.132 41.985 257.04 42.255 ;
     RECT  2.16 42.525 40.284 42.795 ;
     RECT  219.132 42.525 257.04 42.795 ;
     RECT  2.16 43.065 40.284 43.335 ;
     RECT  219.132 43.065 257.04 43.335 ;
     RECT  2.16 43.605 40.284 43.875 ;
     RECT  219.132 43.605 257.04 43.875 ;
     RECT  2.16 44.145 40.284 44.415 ;
     RECT  219.132 44.145 257.04 44.415 ;
     RECT  2.16 44.685 40.284 44.955 ;
     RECT  219.132 44.685 257.04 44.955 ;
     RECT  2.16 45.225 40.284 45.495 ;
     RECT  219.132 45.225 257.04 45.495 ;
     RECT  2.16 45.765 40.284 46.035 ;
     RECT  219.132 45.765 257.04 46.035 ;
     RECT  2.16 46.305 40.284 46.575 ;
     RECT  219.132 46.305 257.04 46.575 ;
     RECT  2.16 46.845 40.284 47.115 ;
     RECT  219.132 46.845 257.04 47.115 ;
     RECT  2.16 47.385 40.284 47.655 ;
     RECT  219.132 47.385 257.04 47.655 ;
     RECT  2.16 47.925 40.284 48.195 ;
     RECT  219.132 47.925 257.04 48.195 ;
     RECT  2.16 48.465 40.284 48.735 ;
     RECT  219.132 48.465 257.04 48.735 ;
     RECT  2.16 49.005 40.284 49.275 ;
     RECT  219.132 49.005 257.04 49.275 ;
     RECT  2.16 49.545 40.284 49.815 ;
     RECT  219.132 49.545 257.04 49.815 ;
     RECT  2.16 50.085 40.284 50.355 ;
     RECT  219.132 50.085 257.04 50.355 ;
     RECT  2.16 50.625 40.284 50.895 ;
     RECT  219.132 50.625 257.04 50.895 ;
     RECT  2.16 51.165 40.284 51.435 ;
     RECT  219.132 51.165 257.04 51.435 ;
     RECT  2.16 51.705 40.284 51.975 ;
     RECT  219.132 51.705 257.04 51.975 ;
     RECT  2.16 52.245 40.284 52.515 ;
     RECT  219.132 52.245 257.04 52.515 ;
     RECT  2.16 52.785 40.284 53.055 ;
     RECT  219.132 52.785 257.04 53.055 ;
     RECT  2.16 53.325 40.284 53.595 ;
     RECT  219.132 53.325 257.04 53.595 ;
     RECT  2.16 53.865 40.284 54.135 ;
     RECT  219.132 53.865 257.04 54.135 ;
     RECT  2.16 54.405 40.284 54.675 ;
     RECT  219.132 54.405 257.04 54.675 ;
     RECT  2.16 54.945 40.284 55.215 ;
     RECT  219.132 54.945 257.04 55.215 ;
     RECT  2.16 55.485 40.284 55.755 ;
     RECT  219.132 55.485 257.04 55.755 ;
     RECT  2.16 56.025 40.284 56.295 ;
     RECT  219.132 56.025 257.04 56.295 ;
     RECT  2.16 56.565 40.284 56.835 ;
     RECT  219.132 56.565 257.04 56.835 ;
     RECT  2.16 57.105 40.284 57.375 ;
     RECT  219.132 57.105 257.04 57.375 ;
     RECT  2.16 57.645 40.284 57.915 ;
     RECT  219.132 57.645 257.04 57.915 ;
     RECT  2.16 58.185 40.284 58.455 ;
     RECT  219.132 58.185 257.04 58.455 ;
     RECT  2.16 58.725 40.284 58.995 ;
     RECT  219.132 58.725 257.04 58.995 ;
     RECT  2.16 59.265 40.284 59.535 ;
     RECT  219.132 59.265 257.04 59.535 ;
     RECT  2.16 59.805 40.284 60.075 ;
     RECT  219.132 59.805 257.04 60.075 ;
     RECT  2.16 60.345 40.284 60.615 ;
     RECT  219.132 60.345 257.04 60.615 ;
     RECT  2.16 60.885 40.284 61.155 ;
     RECT  219.132 60.885 257.04 61.155 ;
     RECT  2.16 61.425 40.284 61.695 ;
     RECT  219.132 61.425 257.04 61.695 ;
     RECT  2.16 61.965 40.284 62.235 ;
     RECT  219.132 61.965 257.04 62.235 ;
     RECT  2.16 62.505 40.284 62.775 ;
     RECT  219.132 62.505 257.04 62.775 ;
     RECT  2.16 63.045 40.284 63.315 ;
     RECT  219.132 63.045 257.04 63.315 ;
     RECT  2.16 63.585 40.284 63.855 ;
     RECT  219.132 63.585 257.04 63.855 ;
     RECT  2.16 64.125 40.284 64.395 ;
     RECT  219.132 64.125 257.04 64.395 ;
     RECT  2.16 64.665 40.284 64.935 ;
     RECT  219.132 64.665 257.04 64.935 ;
     RECT  2.16 65.205 40.284 65.475 ;
     RECT  219.132 65.205 257.04 65.475 ;
     RECT  2.16 65.745 40.284 66.015 ;
     RECT  219.132 65.745 257.04 66.015 ;
     RECT  2.16 66.285 40.284 66.555 ;
     RECT  219.132 66.285 257.04 66.555 ;
     RECT  2.16 66.825 40.284 67.095 ;
     RECT  219.132 66.825 257.04 67.095 ;
     RECT  2.16 67.365 40.284 67.635 ;
     RECT  219.132 67.365 257.04 67.635 ;
     RECT  2.16 67.905 40.284 68.175 ;
     RECT  219.132 67.905 257.04 68.175 ;
     RECT  2.16 68.445 40.284 68.715 ;
     RECT  219.132 68.445 257.04 68.715 ;
     RECT  2.16 68.985 40.284 69.255 ;
     RECT  219.132 68.985 257.04 69.255 ;
     RECT  2.16 69.525 40.284 69.795 ;
     RECT  219.132 69.525 257.04 69.795 ;
     RECT  2.16 70.065 40.284 70.335 ;
     RECT  219.132 70.065 257.04 70.335 ;
     RECT  2.16 70.605 40.284 70.875 ;
     RECT  219.132 70.605 257.04 70.875 ;
     RECT  2.16 71.145 40.284 71.415 ;
     RECT  219.132 71.145 257.04 71.415 ;
     RECT  2.16 71.685 40.284 71.955 ;
     RECT  219.132 71.685 257.04 71.955 ;
     RECT  2.16 72.225 40.284 72.495 ;
     RECT  219.132 72.225 257.04 72.495 ;
     RECT  2.16 72.765 40.284 73.035 ;
     RECT  219.132 72.765 257.04 73.035 ;
     RECT  2.16 73.305 40.284 73.575 ;
     RECT  219.132 73.305 257.04 73.575 ;
     RECT  2.16 73.845 40.284 74.115 ;
     RECT  219.132 73.845 257.04 74.115 ;
     RECT  2.16 74.385 40.284 74.655 ;
     RECT  219.132 74.385 257.04 74.655 ;
     RECT  2.16 74.925 40.284 75.195 ;
     RECT  219.132 74.925 257.04 75.195 ;
     RECT  2.16 75.465 40.284 75.735 ;
     RECT  219.132 75.465 257.04 75.735 ;
     RECT  2.16 76.005 40.284 76.275 ;
     RECT  219.132 76.005 257.04 76.275 ;
     RECT  2.16 76.545 40.284 76.815 ;
     RECT  219.132 76.545 257.04 76.815 ;
     RECT  2.16 77.085 40.284 77.355 ;
     RECT  219.132 77.085 257.04 77.355 ;
     RECT  2.16 77.625 40.284 77.895 ;
     RECT  219.132 77.625 257.04 77.895 ;
     RECT  2.16 78.165 40.284 78.435 ;
     RECT  219.132 78.165 257.04 78.435 ;
     RECT  2.16 78.705 40.284 78.975 ;
     RECT  219.132 78.705 257.04 78.975 ;
     RECT  2.16 79.245 40.284 79.515 ;
     RECT  219.132 79.245 257.04 79.515 ;
     RECT  2.16 79.785 40.284 80.055 ;
     RECT  219.132 79.785 257.04 80.055 ;
     RECT  2.16 80.325 40.284 80.595 ;
     RECT  219.132 80.325 257.04 80.595 ;
     RECT  2.16 80.865 40.284 81.135 ;
     RECT  219.132 80.865 257.04 81.135 ;
     RECT  2.16 81.405 40.284 81.675 ;
     RECT  219.132 81.405 257.04 81.675 ;
     RECT  2.16 81.945 40.284 82.215 ;
     RECT  219.132 81.945 257.04 82.215 ;
     RECT  2.16 82.485 40.284 82.755 ;
     RECT  219.132 82.485 257.04 82.755 ;
     RECT  2.16 83.025 40.284 83.295 ;
     RECT  219.132 83.025 257.04 83.295 ;
     RECT  2.16 83.565 40.284 83.835 ;
     RECT  219.132 83.565 257.04 83.835 ;
     RECT  2.16 84.105 40.284 84.375 ;
     RECT  219.132 84.105 257.04 84.375 ;
     RECT  2.16 84.645 40.284 84.915 ;
     RECT  219.132 84.645 257.04 84.915 ;
     RECT  2.16 85.185 40.284 85.455 ;
     RECT  219.132 85.185 257.04 85.455 ;
     RECT  2.16 85.725 40.284 85.995 ;
     RECT  219.132 85.725 257.04 85.995 ;
     RECT  2.16 86.265 40.284 86.535 ;
     RECT  219.132 86.265 257.04 86.535 ;
     RECT  2.16 86.805 40.284 87.075 ;
     RECT  219.132 86.805 257.04 87.075 ;
     RECT  2.16 87.345 40.284 87.615 ;
     RECT  219.132 87.345 257.04 87.615 ;
     RECT  2.16 87.885 40.284 88.155 ;
     RECT  219.132 87.885 257.04 88.155 ;
     RECT  2.16 88.425 40.284 88.695 ;
     RECT  219.132 88.425 257.04 88.695 ;
     RECT  2.16 88.965 40.284 89.235 ;
     RECT  219.132 88.965 257.04 89.235 ;
     RECT  2.16 89.505 40.284 89.775 ;
     RECT  219.132 89.505 257.04 89.775 ;
     RECT  2.16 90.045 40.284 90.315 ;
     RECT  219.132 90.045 257.04 90.315 ;
     RECT  2.16 90.585 40.284 90.855 ;
     RECT  219.132 90.585 257.04 90.855 ;
     RECT  2.16 91.125 40.284 91.395 ;
     RECT  219.132 91.125 257.04 91.395 ;
     RECT  2.16 91.665 40.284 91.935 ;
     RECT  219.132 91.665 257.04 91.935 ;
     RECT  2.16 92.205 40.284 92.475 ;
     RECT  219.132 92.205 257.04 92.475 ;
     RECT  2.16 92.745 40.284 93.015 ;
     RECT  219.132 92.745 257.04 93.015 ;
     RECT  2.16 93.285 40.284 93.555 ;
     RECT  219.132 93.285 257.04 93.555 ;
     RECT  2.16 93.825 40.284 94.095 ;
     RECT  219.132 93.825 257.04 94.095 ;
     RECT  2.16 94.365 40.284 94.635 ;
     RECT  219.132 94.365 257.04 94.635 ;
     RECT  2.16 94.905 40.284 95.175 ;
     RECT  219.132 94.905 257.04 95.175 ;
     RECT  2.16 95.445 40.284 95.715 ;
     RECT  219.132 95.445 257.04 95.715 ;
     RECT  2.16 95.985 40.284 96.255 ;
     RECT  219.132 95.985 257.04 96.255 ;
     RECT  2.16 96.525 257.04 96.795 ;
     RECT  2.16 97.065 257.04 97.335 ;
     RECT  2.16 97.605 257.04 97.875 ;
     RECT  2.16 98.145 257.04 98.415 ;
     RECT  2.16 98.685 257.04 98.955 ;
     RECT  2.16 99.225 257.04 99.495 ;
     RECT  2.16 99.765 257.04 100.035 ;
     RECT  2.16 100.305 257.04 100.575 ;
     RECT  2.16 100.845 257.04 101.115 ;
     RECT  2.16 101.385 257.04 101.655 ;
     RECT  2.16 101.925 257.04 102.195 ;
     RECT  2.16 102.465 257.04 102.735 ;
     RECT  2.16 103.005 257.04 103.275 ;
     RECT  2.16 103.545 257.04 103.815 ;
     RECT  2.16 104.085 257.04 104.355 ;
     RECT  2.16 104.625 257.04 104.895 ;
     RECT  2.16 105.165 257.04 105.435 ;
     RECT  2.16 105.705 257.04 105.975 ;
     RECT  2.16 106.245 257.04 106.515 ;
     RECT  2.16 106.785 257.04 107.055 ;
     RECT  2.16 107.325 257.04 107.595 ;
     RECT  2.16 107.865 257.04 108.135 ;
     RECT  2.16 108.405 257.04 108.675 ;
     RECT  2.16 108.945 257.04 109.215 ;
     RECT  2.16 109.485 257.04 109.755 ;
     RECT  2.16 110.025 257.04 110.295 ;
     RECT  2.16 110.565 257.04 110.835 ;
     RECT  2.16 111.105 257.04 111.375 ;
     RECT  2.16 111.645 257.04 111.915 ;
     RECT  2.16 112.185 257.04 112.455 ;
     RECT  2.16 112.725 257.04 112.995 ;
     RECT  2.16 113.265 257.04 113.535 ;
     RECT  2.16 113.805 257.04 114.075 ;
     RECT  2.16 114.345 257.04 114.48 ;
    LAYER RVTP ;
     RECT  2.16 2.295 257.04 2.565 ;
     RECT  2.16 2.835 257.04 3.105 ;
     RECT  2.16 3.375 257.04 3.645 ;
     RECT  2.16 3.915 257.04 4.185 ;
     RECT  2.16 4.455 257.04 4.725 ;
     RECT  2.16 4.995 257.04 5.265 ;
     RECT  2.16 5.535 257.04 5.805 ;
     RECT  2.16 6.075 257.04 6.345 ;
     RECT  2.16 6.615 257.04 6.885 ;
     RECT  2.16 7.155 257.04 7.425 ;
     RECT  2.16 7.695 257.04 7.965 ;
     RECT  2.16 8.235 257.04 8.505 ;
     RECT  2.16 8.775 257.04 9.045 ;
     RECT  2.16 9.315 257.04 9.585 ;
     RECT  2.16 9.855 257.04 10.125 ;
     RECT  2.16 10.395 257.04 10.665 ;
     RECT  2.16 10.935 257.04 11.205 ;
     RECT  2.16 11.475 257.04 11.745 ;
     RECT  2.16 12.015 257.04 12.285 ;
     RECT  2.16 12.555 257.04 12.825 ;
     RECT  2.16 13.095 257.04 13.365 ;
     RECT  2.16 13.635 257.04 13.905 ;
     RECT  2.16 14.175 257.04 14.445 ;
     RECT  2.16 14.715 257.04 14.985 ;
     RECT  2.16 15.255 257.04 15.525 ;
     RECT  2.16 15.795 257.04 16.065 ;
     RECT  2.16 16.335 257.04 16.605 ;
     RECT  2.16 16.875 257.04 17.145 ;
     RECT  2.16 17.415 257.04 17.685 ;
     RECT  2.16 17.955 257.04 18.225 ;
     RECT  2.16 18.495 257.04 18.765 ;
     RECT  2.16 19.035 257.04 19.305 ;
     RECT  2.16 19.575 257.04 19.845 ;
     RECT  2.16 20.115 257.04 20.385 ;
     RECT  2.16 20.655 257.04 20.925 ;
     RECT  2.16 21.195 257.04 21.465 ;
     RECT  2.16 21.735 40.284 22.005 ;
     RECT  219.132 21.735 257.04 22.005 ;
     RECT  2.16 22.275 40.284 22.545 ;
     RECT  219.132 22.275 257.04 22.545 ;
     RECT  2.16 22.815 40.284 23.085 ;
     RECT  219.132 22.815 257.04 23.085 ;
     RECT  2.16 23.355 40.284 23.625 ;
     RECT  219.132 23.355 257.04 23.625 ;
     RECT  2.16 23.895 40.284 24.165 ;
     RECT  219.132 23.895 257.04 24.165 ;
     RECT  2.16 24.435 40.284 24.705 ;
     RECT  219.132 24.435 257.04 24.705 ;
     RECT  2.16 24.975 40.284 25.245 ;
     RECT  219.132 24.975 257.04 25.245 ;
     RECT  2.16 25.515 40.284 25.785 ;
     RECT  219.132 25.515 257.04 25.785 ;
     RECT  2.16 26.055 40.284 26.325 ;
     RECT  219.132 26.055 257.04 26.325 ;
     RECT  2.16 26.595 40.284 26.865 ;
     RECT  219.132 26.595 257.04 26.865 ;
     RECT  2.16 27.135 40.284 27.405 ;
     RECT  219.132 27.135 257.04 27.405 ;
     RECT  2.16 27.675 40.284 27.945 ;
     RECT  219.132 27.675 257.04 27.945 ;
     RECT  2.16 28.215 40.284 28.485 ;
     RECT  219.132 28.215 257.04 28.485 ;
     RECT  2.16 28.755 40.284 29.025 ;
     RECT  219.132 28.755 257.04 29.025 ;
     RECT  2.16 29.295 40.284 29.565 ;
     RECT  219.132 29.295 257.04 29.565 ;
     RECT  2.16 29.835 40.284 30.105 ;
     RECT  219.132 29.835 257.04 30.105 ;
     RECT  2.16 30.375 40.284 30.645 ;
     RECT  219.132 30.375 257.04 30.645 ;
     RECT  2.16 30.915 40.284 31.185 ;
     RECT  219.132 30.915 257.04 31.185 ;
     RECT  2.16 31.455 40.284 31.725 ;
     RECT  219.132 31.455 257.04 31.725 ;
     RECT  2.16 31.995 40.284 32.265 ;
     RECT  219.132 31.995 257.04 32.265 ;
     RECT  2.16 32.535 40.284 32.805 ;
     RECT  219.132 32.535 257.04 32.805 ;
     RECT  2.16 33.075 40.284 33.345 ;
     RECT  219.132 33.075 257.04 33.345 ;
     RECT  2.16 33.615 40.284 33.885 ;
     RECT  219.132 33.615 257.04 33.885 ;
     RECT  2.16 34.155 40.284 34.425 ;
     RECT  219.132 34.155 257.04 34.425 ;
     RECT  2.16 34.695 40.284 34.965 ;
     RECT  219.132 34.695 257.04 34.965 ;
     RECT  2.16 35.235 40.284 35.505 ;
     RECT  219.132 35.235 257.04 35.505 ;
     RECT  2.16 35.775 40.284 36.045 ;
     RECT  219.132 35.775 257.04 36.045 ;
     RECT  2.16 36.315 40.284 36.585 ;
     RECT  219.132 36.315 257.04 36.585 ;
     RECT  2.16 36.855 40.284 37.125 ;
     RECT  219.132 36.855 257.04 37.125 ;
     RECT  2.16 37.395 40.284 37.665 ;
     RECT  219.132 37.395 257.04 37.665 ;
     RECT  2.16 37.935 40.284 38.205 ;
     RECT  219.132 37.935 257.04 38.205 ;
     RECT  2.16 38.475 40.284 38.745 ;
     RECT  219.132 38.475 257.04 38.745 ;
     RECT  2.16 39.015 40.284 39.285 ;
     RECT  219.132 39.015 257.04 39.285 ;
     RECT  2.16 39.555 40.284 39.825 ;
     RECT  219.132 39.555 257.04 39.825 ;
     RECT  2.16 40.095 40.284 40.365 ;
     RECT  219.132 40.095 257.04 40.365 ;
     RECT  2.16 40.635 40.284 40.905 ;
     RECT  219.132 40.635 257.04 40.905 ;
     RECT  2.16 41.175 40.284 41.445 ;
     RECT  219.132 41.175 257.04 41.445 ;
     RECT  2.16 41.715 40.284 41.985 ;
     RECT  219.132 41.715 257.04 41.985 ;
     RECT  2.16 42.255 40.284 42.525 ;
     RECT  219.132 42.255 257.04 42.525 ;
     RECT  2.16 42.795 40.284 43.065 ;
     RECT  219.132 42.795 257.04 43.065 ;
     RECT  2.16 43.335 40.284 43.605 ;
     RECT  219.132 43.335 257.04 43.605 ;
     RECT  2.16 43.875 40.284 44.145 ;
     RECT  219.132 43.875 257.04 44.145 ;
     RECT  2.16 44.415 40.284 44.685 ;
     RECT  219.132 44.415 257.04 44.685 ;
     RECT  2.16 44.955 40.284 45.225 ;
     RECT  219.132 44.955 257.04 45.225 ;
     RECT  2.16 45.495 40.284 45.765 ;
     RECT  219.132 45.495 257.04 45.765 ;
     RECT  2.16 46.035 40.284 46.305 ;
     RECT  219.132 46.035 257.04 46.305 ;
     RECT  2.16 46.575 40.284 46.845 ;
     RECT  219.132 46.575 257.04 46.845 ;
     RECT  2.16 47.115 40.284 47.385 ;
     RECT  219.132 47.115 257.04 47.385 ;
     RECT  2.16 47.655 40.284 47.925 ;
     RECT  219.132 47.655 257.04 47.925 ;
     RECT  2.16 48.195 40.284 48.465 ;
     RECT  219.132 48.195 257.04 48.465 ;
     RECT  2.16 48.735 40.284 49.005 ;
     RECT  219.132 48.735 257.04 49.005 ;
     RECT  2.16 49.275 40.284 49.545 ;
     RECT  219.132 49.275 257.04 49.545 ;
     RECT  2.16 49.815 40.284 50.085 ;
     RECT  219.132 49.815 257.04 50.085 ;
     RECT  2.16 50.355 40.284 50.625 ;
     RECT  219.132 50.355 257.04 50.625 ;
     RECT  2.16 50.895 40.284 51.165 ;
     RECT  219.132 50.895 257.04 51.165 ;
     RECT  2.16 51.435 40.284 51.705 ;
     RECT  219.132 51.435 257.04 51.705 ;
     RECT  2.16 51.975 40.284 52.245 ;
     RECT  219.132 51.975 257.04 52.245 ;
     RECT  2.16 52.515 40.284 52.785 ;
     RECT  219.132 52.515 257.04 52.785 ;
     RECT  2.16 53.055 40.284 53.325 ;
     RECT  219.132 53.055 257.04 53.325 ;
     RECT  2.16 53.595 40.284 53.865 ;
     RECT  219.132 53.595 257.04 53.865 ;
     RECT  2.16 54.135 40.284 54.405 ;
     RECT  219.132 54.135 257.04 54.405 ;
     RECT  2.16 54.675 40.284 54.945 ;
     RECT  219.132 54.675 257.04 54.945 ;
     RECT  2.16 55.215 40.284 55.485 ;
     RECT  219.132 55.215 257.04 55.485 ;
     RECT  2.16 55.755 40.284 56.025 ;
     RECT  219.132 55.755 257.04 56.025 ;
     RECT  2.16 56.295 40.284 56.565 ;
     RECT  219.132 56.295 257.04 56.565 ;
     RECT  2.16 56.835 40.284 57.105 ;
     RECT  219.132 56.835 257.04 57.105 ;
     RECT  2.16 57.375 40.284 57.645 ;
     RECT  219.132 57.375 257.04 57.645 ;
     RECT  2.16 57.915 40.284 58.185 ;
     RECT  219.132 57.915 257.04 58.185 ;
     RECT  2.16 58.455 40.284 58.725 ;
     RECT  219.132 58.455 257.04 58.725 ;
     RECT  2.16 58.995 40.284 59.265 ;
     RECT  219.132 58.995 257.04 59.265 ;
     RECT  2.16 59.535 40.284 59.805 ;
     RECT  219.132 59.535 257.04 59.805 ;
     RECT  2.16 60.075 40.284 60.345 ;
     RECT  219.132 60.075 257.04 60.345 ;
     RECT  2.16 60.615 40.284 60.885 ;
     RECT  219.132 60.615 257.04 60.885 ;
     RECT  2.16 61.155 40.284 61.425 ;
     RECT  219.132 61.155 257.04 61.425 ;
     RECT  2.16 61.695 40.284 61.965 ;
     RECT  219.132 61.695 257.04 61.965 ;
     RECT  2.16 62.235 40.284 62.505 ;
     RECT  219.132 62.235 257.04 62.505 ;
     RECT  2.16 62.775 40.284 63.045 ;
     RECT  219.132 62.775 257.04 63.045 ;
     RECT  2.16 63.315 40.284 63.585 ;
     RECT  219.132 63.315 257.04 63.585 ;
     RECT  2.16 63.855 40.284 64.125 ;
     RECT  219.132 63.855 257.04 64.125 ;
     RECT  2.16 64.395 40.284 64.665 ;
     RECT  219.132 64.395 257.04 64.665 ;
     RECT  2.16 64.935 40.284 65.205 ;
     RECT  219.132 64.935 257.04 65.205 ;
     RECT  2.16 65.475 40.284 65.745 ;
     RECT  219.132 65.475 257.04 65.745 ;
     RECT  2.16 66.015 40.284 66.285 ;
     RECT  219.132 66.015 257.04 66.285 ;
     RECT  2.16 66.555 40.284 66.825 ;
     RECT  219.132 66.555 257.04 66.825 ;
     RECT  2.16 67.095 40.284 67.365 ;
     RECT  219.132 67.095 257.04 67.365 ;
     RECT  2.16 67.635 40.284 67.905 ;
     RECT  219.132 67.635 257.04 67.905 ;
     RECT  2.16 68.175 40.284 68.445 ;
     RECT  219.132 68.175 257.04 68.445 ;
     RECT  2.16 68.715 40.284 68.985 ;
     RECT  219.132 68.715 257.04 68.985 ;
     RECT  2.16 69.255 40.284 69.525 ;
     RECT  219.132 69.255 257.04 69.525 ;
     RECT  2.16 69.795 40.284 70.065 ;
     RECT  219.132 69.795 257.04 70.065 ;
     RECT  2.16 70.335 40.284 70.605 ;
     RECT  219.132 70.335 257.04 70.605 ;
     RECT  2.16 70.875 40.284 71.145 ;
     RECT  219.132 70.875 257.04 71.145 ;
     RECT  2.16 71.415 40.284 71.685 ;
     RECT  219.132 71.415 257.04 71.685 ;
     RECT  2.16 71.955 40.284 72.225 ;
     RECT  219.132 71.955 257.04 72.225 ;
     RECT  2.16 72.495 40.284 72.765 ;
     RECT  219.132 72.495 257.04 72.765 ;
     RECT  2.16 73.035 40.284 73.305 ;
     RECT  219.132 73.035 257.04 73.305 ;
     RECT  2.16 73.575 40.284 73.845 ;
     RECT  219.132 73.575 257.04 73.845 ;
     RECT  2.16 74.115 40.284 74.385 ;
     RECT  219.132 74.115 257.04 74.385 ;
     RECT  2.16 74.655 40.284 74.925 ;
     RECT  219.132 74.655 257.04 74.925 ;
     RECT  2.16 75.195 40.284 75.465 ;
     RECT  219.132 75.195 257.04 75.465 ;
     RECT  2.16 75.735 40.284 76.005 ;
     RECT  219.132 75.735 257.04 76.005 ;
     RECT  2.16 76.275 40.284 76.545 ;
     RECT  219.132 76.275 257.04 76.545 ;
     RECT  2.16 76.815 40.284 77.085 ;
     RECT  219.132 76.815 257.04 77.085 ;
     RECT  2.16 77.355 40.284 77.625 ;
     RECT  219.132 77.355 257.04 77.625 ;
     RECT  2.16 77.895 40.284 78.165 ;
     RECT  219.132 77.895 257.04 78.165 ;
     RECT  2.16 78.435 40.284 78.705 ;
     RECT  219.132 78.435 257.04 78.705 ;
     RECT  2.16 78.975 40.284 79.245 ;
     RECT  219.132 78.975 257.04 79.245 ;
     RECT  2.16 79.515 40.284 79.785 ;
     RECT  219.132 79.515 257.04 79.785 ;
     RECT  2.16 80.055 40.284 80.325 ;
     RECT  219.132 80.055 257.04 80.325 ;
     RECT  2.16 80.595 40.284 80.865 ;
     RECT  219.132 80.595 257.04 80.865 ;
     RECT  2.16 81.135 40.284 81.405 ;
     RECT  219.132 81.135 257.04 81.405 ;
     RECT  2.16 81.675 40.284 81.945 ;
     RECT  219.132 81.675 257.04 81.945 ;
     RECT  2.16 82.215 40.284 82.485 ;
     RECT  219.132 82.215 257.04 82.485 ;
     RECT  2.16 82.755 40.284 83.025 ;
     RECT  219.132 82.755 257.04 83.025 ;
     RECT  2.16 83.295 40.284 83.565 ;
     RECT  219.132 83.295 257.04 83.565 ;
     RECT  2.16 83.835 40.284 84.105 ;
     RECT  219.132 83.835 257.04 84.105 ;
     RECT  2.16 84.375 40.284 84.645 ;
     RECT  219.132 84.375 257.04 84.645 ;
     RECT  2.16 84.915 40.284 85.185 ;
     RECT  219.132 84.915 257.04 85.185 ;
     RECT  2.16 85.455 40.284 85.725 ;
     RECT  219.132 85.455 257.04 85.725 ;
     RECT  2.16 85.995 40.284 86.265 ;
     RECT  219.132 85.995 257.04 86.265 ;
     RECT  2.16 86.535 40.284 86.805 ;
     RECT  219.132 86.535 257.04 86.805 ;
     RECT  2.16 87.075 40.284 87.345 ;
     RECT  219.132 87.075 257.04 87.345 ;
     RECT  2.16 87.615 40.284 87.885 ;
     RECT  219.132 87.615 257.04 87.885 ;
     RECT  2.16 88.155 40.284 88.425 ;
     RECT  219.132 88.155 257.04 88.425 ;
     RECT  2.16 88.695 40.284 88.965 ;
     RECT  219.132 88.695 257.04 88.965 ;
     RECT  2.16 89.235 40.284 89.505 ;
     RECT  219.132 89.235 257.04 89.505 ;
     RECT  2.16 89.775 40.284 90.045 ;
     RECT  219.132 89.775 257.04 90.045 ;
     RECT  2.16 90.315 40.284 90.585 ;
     RECT  219.132 90.315 257.04 90.585 ;
     RECT  2.16 90.855 40.284 91.125 ;
     RECT  219.132 90.855 257.04 91.125 ;
     RECT  2.16 91.395 40.284 91.665 ;
     RECT  219.132 91.395 257.04 91.665 ;
     RECT  2.16 91.935 40.284 92.205 ;
     RECT  219.132 91.935 257.04 92.205 ;
     RECT  2.16 92.475 40.284 92.745 ;
     RECT  219.132 92.475 257.04 92.745 ;
     RECT  2.16 93.015 40.284 93.285 ;
     RECT  219.132 93.015 257.04 93.285 ;
     RECT  2.16 93.555 40.284 93.825 ;
     RECT  219.132 93.555 257.04 93.825 ;
     RECT  2.16 94.095 40.284 94.365 ;
     RECT  219.132 94.095 257.04 94.365 ;
     RECT  2.16 94.635 40.284 94.905 ;
     RECT  219.132 94.635 257.04 94.905 ;
     RECT  2.16 95.175 40.284 95.445 ;
     RECT  219.132 95.175 257.04 95.445 ;
     RECT  2.16 95.715 40.284 95.985 ;
     RECT  219.132 95.715 257.04 95.985 ;
     RECT  2.16 96.255 40.284 96.39 ;
     RECT  219.132 96.255 257.04 96.39 ;
     RECT  2.16 96.39 257.04 96.525 ;
     RECT  2.16 96.795 257.04 97.065 ;
     RECT  2.16 97.335 257.04 97.605 ;
     RECT  2.16 97.875 257.04 98.145 ;
     RECT  2.16 98.415 257.04 98.685 ;
     RECT  2.16 98.955 257.04 99.225 ;
     RECT  2.16 99.495 257.04 99.765 ;
     RECT  2.16 100.035 257.04 100.305 ;
     RECT  2.16 100.575 257.04 100.845 ;
     RECT  2.16 101.115 257.04 101.385 ;
     RECT  2.16 101.655 257.04 101.925 ;
     RECT  2.16 102.195 257.04 102.465 ;
     RECT  2.16 102.735 257.04 103.005 ;
     RECT  2.16 103.275 257.04 103.545 ;
     RECT  2.16 103.815 257.04 104.085 ;
     RECT  2.16 104.355 257.04 104.625 ;
     RECT  2.16 104.895 257.04 105.165 ;
     RECT  2.16 105.435 257.04 105.705 ;
     RECT  2.16 105.975 257.04 106.245 ;
     RECT  2.16 106.515 257.04 106.785 ;
     RECT  2.16 107.055 257.04 107.325 ;
     RECT  2.16 107.595 257.04 107.865 ;
     RECT  2.16 108.135 257.04 108.405 ;
     RECT  2.16 108.675 257.04 108.945 ;
     RECT  2.16 109.215 257.04 109.485 ;
     RECT  2.16 109.755 257.04 110.025 ;
     RECT  2.16 110.295 257.04 110.565 ;
     RECT  2.16 110.835 257.04 111.105 ;
     RECT  2.16 111.375 257.04 111.645 ;
     RECT  2.16 111.915 257.04 112.185 ;
     RECT  2.16 112.455 257.04 112.725 ;
     RECT  2.16 112.995 257.04 113.265 ;
     RECT  2.16 113.535 257.04 113.805 ;
     RECT  2.16 114.075 257.04 114.345 ;
    LAYER M1 ;
     RECT  2.16 2.151 257.04 21.609 ;
     RECT  42.336 23.76 217.08 94.248 ;
     RECT  2.16 21.609 40.284 96.381 ;
     RECT  219.132 21.609 257.04 96.381 ;
     RECT  2.16 96.381 257.04 114.489 ;
    LAYER M2 ;
     RECT  2.16 2.151 39.307 114.489 ;
     RECT  39.307 2.151 40.284 114.876 ;
     RECT  40.284 2.151 40.32 24.309 ;
     RECT  40.284 53.064 40.32 55.476 ;
     RECT  40.284 58.851 40.32 58.869 ;
     RECT  40.284 63.171 40.32 63.189 ;
     RECT  40.284 64.791 40.32 114.876 ;
     RECT  40.284 43.002 40.343 47.754 ;
     RECT  40.32 54.72 40.379 55.476 ;
     RECT  40.284 25.29 40.487 42.246 ;
     RECT  40.32 53.064 40.487 53.856 ;
     RECT  40.32 92.826 40.487 92.844 ;
     RECT  40.343 43.002 40.667 45.414 ;
     RECT  40.343 46.206 40.667 47.07 ;
     RECT  40.667 46.206 40.703 47.034 ;
     RECT  40.487 53.568 40.919 53.856 ;
     RECT  40.32 92.016 41.063 92.034 ;
     RECT  40.284 48.942 41.135 51.354 ;
     RECT  41.135 48.978 41.279 51.354 ;
     RECT  40.32 94.374 41.287 95.544 ;
     RECT  40.32 96.381 41.287 114.876 ;
     RECT  41.279 49.248 41.315 51.354 ;
     RECT  40.919 53.568 41.315 53.658 ;
     RECT  40.32 90.216 41.315 90.234 ;
     RECT  41.315 50.13 41.387 51.354 ;
     RECT  41.215 57.582 41.495 57.6 ;
     RECT  41.315 49.248 41.567 49.266 ;
     RECT  40.667 43.002 41.603 45.288 ;
     RECT  40.487 25.596 41.863 42.246 ;
     RECT  40.32 2.151 42.336 23.724 ;
     RECT  41.863 25.326 42.336 42.246 ;
     RECT  41.603 43.074 42.336 45.288 ;
     RECT  40.703 46.35 42.336 47.034 ;
     RECT  41.387 50.256 42.336 51.354 ;
     RECT  41.315 53.568 42.336 53.586 ;
     RECT  40.379 55.458 42.336 55.476 ;
     RECT  40.284 56.376 42.336 56.394 ;
     RECT  41.287 94.374 42.336 114.876 ;
     RECT  42.336 2.151 50.611 114.876 ;
     RECT  50.611 2.07 56.759 114.876 ;
     RECT  56.759 96.03 57.515 114.876 ;
     RECT  57.515 96.381 61.915 114.876 ;
     RECT  61.915 96.336 62.195 114.876 ;
     RECT  56.759 2.07 62.375 94.896 ;
     RECT  62.195 96.381 65.191 114.876 ;
     RECT  65.191 96.381 67.315 115.182 ;
     RECT  67.315 96.336 67.595 115.182 ;
     RECT  67.595 96.381 72.715 115.182 ;
     RECT  72.715 96.336 72.995 115.182 ;
     RECT  72.995 96.381 75.703 115.182 ;
     RECT  75.703 96.381 78.115 115.218 ;
     RECT  78.115 96.336 78.395 115.218 ;
     RECT  78.395 96.381 83.515 115.218 ;
     RECT  83.515 96.336 83.795 115.218 ;
     RECT  83.795 96.381 88.915 115.218 ;
     RECT  88.915 96.336 89.195 115.218 ;
     RECT  89.195 96.381 94.315 115.218 ;
     RECT  94.315 96.336 94.595 115.218 ;
     RECT  94.595 96.381 99.643 115.218 ;
     RECT  99.643 96.336 101.507 115.218 ;
     RECT  62.375 2.07 106.591 94.248 ;
     RECT  86.719 0.846 108.311 0.864 ;
     RECT  109.543 1.152 109.643 1.17 ;
     RECT  106.591 1.998 110.435 94.248 ;
     RECT  110.435 2.07 115.735 94.248 ;
     RECT  115.735 1.998 123.079 94.248 ;
     RECT  123.079 1.926 126.563 94.248 ;
     RECT  101.507 96.381 127.435 115.218 ;
     RECT  126.563 1.962 130.595 94.248 ;
     RECT  130.595 1.998 136.175 94.248 ;
     RECT  136.175 2.034 157.451 94.248 ;
     RECT  127.435 96.381 181.427 115.416 ;
     RECT  181.427 115.398 183.587 115.416 ;
     RECT  181.427 96.381 185.351 114.57 ;
     RECT  157.451 2.151 217.08 94.248 ;
     RECT  217.08 2.151 217.319 23.85 ;
     RECT  217.08 31.392 217.463 32.454 ;
     RECT  217.08 26.91 217.499 26.928 ;
     RECT  217.319 2.151 217.967 23.544 ;
     RECT  217.08 54.45 218.083 55.512 ;
     RECT  217.967 2.151 218.147 23.454 ;
     RECT  217.08 28.458 218.191 28.476 ;
     RECT  217.08 33.822 218.191 34.614 ;
     RECT  217.08 37.026 218.191 37.584 ;
     RECT  218.191 28.458 218.291 29.052 ;
     RECT  217.463 31.5 218.299 32.454 ;
     RECT  218.191 33.282 218.299 34.614 ;
     RECT  217.08 56.574 218.299 57.564 ;
     RECT  217.08 58.536 218.299 58.716 ;
     RECT  218.191 36.396 218.327 37.584 ;
     RECT  218.335 82.611 218.399 82.629 ;
     RECT  217.08 59.742 218.659 62.604 ;
     RECT  218.299 31.5 218.731 34.614 ;
     RECT  218.551 25.182 218.803 25.2 ;
     RECT  218.659 59.742 218.839 62.73 ;
     RECT  218.731 70.65 218.839 70.668 ;
     RECT  218.731 30.771 218.875 34.614 ;
     RECT  218.327 36.396 218.875 37.494 ;
     RECT  218.875 64.602 218.911 64.62 ;
     RECT  217.08 42.336 218.947 43.794 ;
     RECT  218.839 59.508 218.947 62.73 ;
     RECT  218.947 59.508 219.019 63.144 ;
     RECT  218.147 2.151 219.132 23.148 ;
     RECT  218.803 25.101 219.132 25.2 ;
     RECT  217.08 25.956 219.132 25.974 ;
     RECT  218.291 28.458 219.132 28.476 ;
     RECT  218.875 29.466 219.132 29.484 ;
     RECT  218.875 30.771 219.132 34.686 ;
     RECT  218.875 35.676 219.132 37.494 ;
     RECT  217.08 39.186 219.132 39.204 ;
     RECT  217.08 40.608 219.132 40.626 ;
     RECT  218.947 42.336 219.132 44.406 ;
     RECT  218.911 46.116 219.132 46.134 ;
     RECT  217.08 47.196 219.132 53.244 ;
     RECT  218.083 54.45 219.132 55.674 ;
     RECT  218.299 56.574 219.132 58.716 ;
     RECT  219.019 59.508 219.132 63.846 ;
     RECT  218.911 64.602 219.132 64.854 ;
     RECT  218.839 70.65 219.132 70.704 ;
     RECT  218.803 78.642 219.132 78.696 ;
     RECT  218.767 86.58 219.132 86.679 ;
     RECT  218.767 94.572 219.132 94.662 ;
     RECT  185.351 96.381 219.132 114.489 ;
     RECT  219.132 2.151 257.04 114.489 ;
    LAYER M3 ;
     RECT  42.408 0.043 42.426 0.091 ;
     RECT  117.684 0.091 118.17 0.139 ;
     RECT  127.224 0.091 127.386 0.221 ;
     RECT  102.312 0.187 102.618 0.317 ;
     RECT  107.784 0.091 108.306 0.523 ;
     RECT  109.152 0.475 109.17 0.523 ;
     RECT  106.416 0.523 106.434 0.571 ;
     RECT  107.784 0.523 109.17 0.571 ;
     RECT  111.384 0.523 111.402 0.571 ;
     RECT  117.108 0.139 118.17 0.571 ;
     RECT  120.24 0.523 120.258 0.571 ;
     RECT  106.2 0.571 106.434 1.003 ;
     RECT  124.92 0.571 125.478 1.003 ;
     RECT  124.668 1.003 125.478 1.099 ;
     RECT  107.784 0.571 110.286 1.147 ;
     RECT  124.596 1.099 125.478 1.675 ;
     RECT  106.2 1.003 106.578 1.723 ;
     RECT  107.784 1.147 110.322 1.723 ;
     RECT  111.384 0.571 111.582 1.723 ;
     RECT  117.108 0.571 118.35 1.723 ;
     RECT  119.772 0.571 120.906 1.723 ;
     RECT  123.372 0.187 123.39 1.723 ;
     RECT  124.596 1.675 126.054 1.723 ;
     RECT  127.368 0.221 127.386 1.723 ;
     RECT  128.592 0.091 128.61 1.723 ;
     RECT  129.636 0.571 129.654 1.723 ;
     RECT  106.2 1.723 111.618 1.771 ;
     RECT  128.592 1.723 130.662 1.771 ;
     RECT  131.472 0.859 131.49 1.771 ;
     RECT  106.2 1.771 111.69 1.867 ;
     RECT  115.452 0.187 115.47 1.993 ;
     RECT  117.108 1.723 127.53 2.065 ;
     RECT  128.592 1.771 131.49 2.065 ;
     RECT  104.868 0.955 104.886 2.101 ;
     RECT  106.2 1.867 111.726 2.101 ;
     RECT  45.108 0.139 45.126 2.143 ;
     RECT  50.616 2.065 50.634 2.143 ;
     RECT  115.452 1.993 115.758 2.143 ;
     RECT  117.108 2.065 131.49 2.143 ;
     RECT  117.108 2.143 132.105 2.191 ;
     RECT  157.428 2.029 157.446 2.219 ;
     RECT  67.215 2.143 67.305 2.227 ;
     RECT  157.284 2.227 157.302 2.285 ;
     RECT  117.108 2.191 132.822 2.299 ;
     RECT  134.604 2.299 134.622 2.371 ;
     RECT  159.015 2.143 159.105 2.371 ;
     RECT  2.415 2.143 2.505 2.413 ;
     RECT  7.815 2.143 7.905 2.413 ;
     RECT  13.215 2.143 13.305 2.413 ;
     RECT  18.615 2.143 18.705 2.413 ;
     RECT  24.015 2.143 24.105 2.413 ;
     RECT  29.415 2.143 29.505 2.413 ;
     RECT  34.815 2.143 34.905 2.413 ;
     RECT  40.215 2.143 40.305 2.413 ;
     RECT  45.108 2.143 45.705 2.413 ;
     RECT  50.616 2.143 51.105 2.413 ;
     RECT  56.415 2.143 56.505 2.413 ;
     RECT  61.815 2.143 61.905 2.413 ;
     RECT  72.615 2.143 72.705 2.413 ;
     RECT  78.015 2.143 78.105 2.413 ;
     RECT  83.415 2.143 83.505 2.413 ;
     RECT  88.815 2.143 88.905 2.413 ;
     RECT  94.215 2.143 94.305 2.413 ;
     RECT  99.615 2.143 99.705 2.413 ;
     RECT  115.452 2.143 115.905 2.413 ;
     RECT  137.415 2.143 137.505 2.413 ;
     RECT  142.815 2.143 142.905 2.413 ;
     RECT  148.215 2.143 148.305 2.413 ;
     RECT  153.615 2.143 153.705 2.413 ;
     RECT  158.22 2.371 159.105 2.413 ;
     RECT  164.415 2.143 164.505 2.413 ;
     RECT  169.815 2.143 169.905 2.413 ;
     RECT  175.215 2.143 175.305 2.413 ;
     RECT  180.615 2.143 180.705 2.413 ;
     RECT  186.015 2.143 186.105 2.413 ;
     RECT  191.415 2.143 191.505 2.413 ;
     RECT  196.815 2.143 196.905 2.413 ;
     RECT  202.215 2.143 202.305 2.413 ;
     RECT  207.615 2.143 207.705 2.413 ;
     RECT  213.015 2.143 213.105 2.413 ;
     RECT  218.415 2.143 218.505 2.413 ;
     RECT  223.815 2.143 223.905 2.413 ;
     RECT  229.215 2.143 229.305 2.413 ;
     RECT  234.615 2.143 234.705 2.413 ;
     RECT  240.015 2.143 240.105 2.413 ;
     RECT  245.415 2.143 245.505 2.413 ;
     RECT  250.815 2.143 250.905 2.413 ;
     RECT  256.215 2.143 256.305 2.413 ;
     RECT  104.868 2.101 111.726 2.461 ;
     RECT  112.536 0.043 112.554 2.461 ;
     RECT  117.108 2.299 133.29 2.461 ;
     RECT  142.815 2.413 143.097 2.461 ;
     RECT  104.868 2.461 112.554 2.489 ;
     RECT  152.784 2.371 152.802 2.489 ;
     RECT  138.528 2.461 138.546 2.497 ;
     RECT  97.164 2.371 97.182 2.525 ;
     RECT  117.108 2.461 133.362 2.569 ;
     RECT  142.344 2.461 143.097 2.569 ;
     RECT  94.215 2.413 94.497 2.605 ;
     RECT  115.452 2.413 116.097 2.605 ;
     RECT  117.108 2.569 133.398 2.605 ;
     RECT  162.18 2.371 162.198 2.605 ;
     RECT  114.588 2.101 114.606 2.633 ;
     RECT  56.415 2.413 56.697 2.635 ;
     RECT  67.215 2.227 67.914 2.635 ;
     RECT  78.015 2.413 78.297 2.635 ;
     RECT  88.815 2.413 89.097 2.635 ;
     RECT  99.615 2.413 99.897 2.635 ;
     RECT  162.036 2.605 162.198 2.641 ;
     RECT  164.415 2.413 164.697 2.641 ;
     RECT  56.304 2.635 56.697 2.669 ;
     RECT  67.104 2.635 67.914 2.669 ;
     RECT  77.904 2.635 78.297 2.669 ;
     RECT  88.704 2.635 89.097 2.669 ;
     RECT  99.504 2.635 99.897 2.669 ;
     RECT  161.676 2.641 162.306 2.731 ;
     RECT  141.372 2.641 141.39 2.767 ;
     RECT  142.272 2.569 143.097 2.767 ;
     RECT  140.328 2.263 140.346 2.803 ;
     RECT  33.948 2.731 33.966 2.813 ;
     RECT  158.22 2.413 159.297 2.827 ;
     RECT  160.74 2.605 160.758 2.827 ;
     RECT  140.148 2.803 140.346 2.839 ;
     RECT  134.532 2.371 134.622 2.875 ;
     RECT  137.415 2.413 137.697 2.875 ;
     RECT  138.528 2.497 139.122 2.875 ;
     RECT  153.615 2.413 153.897 2.875 ;
     RECT  155.592 2.839 155.61 2.909 ;
     RECT  102.312 0.317 102.33 2.911 ;
     RECT  139.896 2.839 140.346 2.911 ;
     RECT  141.12 2.767 141.39 2.911 ;
     RECT  160.488 2.827 160.758 2.911 ;
     RECT  161.676 2.731 163.026 2.911 ;
     RECT  134.496 2.875 134.622 3.001 ;
     RECT  136.152 1.993 136.17 3.001 ;
     RECT  134.172 3.001 134.91 3.019 ;
     RECT  150.156 2.101 150.174 3.019 ;
     RECT  156.528 2.605 156.546 3.019 ;
     RECT  86.724 0.841 86.742 3.029 ;
     RECT  95.724 1.483 95.742 3.029 ;
     RECT  101.7 2.911 102.33 3.029 ;
     RECT  105.015 2.489 112.554 3.029 ;
     RECT  149.976 3.019 150.174 3.029 ;
     RECT  156.348 3.019 156.546 3.029 ;
     RECT  158.22 2.827 159.57 3.029 ;
     RECT  149.976 3.029 149.994 3.065 ;
     RECT  152.82 2.875 153.897 3.065 ;
     RECT  136.044 3.001 136.17 3.067 ;
     RECT  139.896 2.911 141.39 3.067 ;
     RECT  142.2 2.767 143.097 3.067 ;
     RECT  105.015 3.029 105.966 3.101 ;
     RECT  135.9 3.067 136.17 3.109 ;
     RECT  137.415 2.875 139.122 3.109 ;
     RECT  160.488 2.911 163.026 3.109 ;
     RECT  152.82 3.065 152.838 3.137 ;
     RECT  94.215 2.605 94.986 3.145 ;
     RECT  151.632 2.875 151.65 3.173 ;
     RECT  134.136 3.019 134.91 3.181 ;
     RECT  135.684 3.109 136.17 3.181 ;
     RECT  136.944 3.109 139.122 3.181 ;
     RECT  157.32 3.145 157.338 3.181 ;
     RECT  160.416 3.109 163.026 3.271 ;
     RECT  146.484 3.181 146.502 3.299 ;
     RECT  151.056 3.181 151.146 3.299 ;
     RECT  156.348 3.029 156.474 3.299 ;
     RECT  157.248 3.181 157.338 3.299 ;
     RECT  115.452 2.605 133.398 3.307 ;
     RECT  134.136 3.181 139.122 3.307 ;
     RECT  157.32 3.299 157.338 3.307 ;
     RECT  164.415 2.641 164.97 3.307 ;
     RECT  115.416 3.307 139.122 3.341 ;
     RECT  156.348 3.299 156.366 3.341 ;
     RECT  99.54 2.669 99.897 3.343 ;
     RECT  160.272 3.271 163.026 3.343 ;
     RECT  163.908 3.307 165.222 3.343 ;
     RECT  160.272 3.343 165.222 3.403 ;
     RECT  115.452 3.341 139.122 3.407 ;
     RECT  157.32 3.307 157.41 3.451 ;
     RECT  158.22 3.029 159.534 3.451 ;
     RECT  157.32 3.451 159.534 3.479 ;
     RECT  105.015 3.101 105.297 3.541 ;
     RECT  88.815 2.669 89.097 3.547 ;
     RECT  218.415 2.413 218.697 3.547 ;
     RECT  99.54 3.343 100.566 3.569 ;
     RECT  137.415 3.407 139.122 3.569 ;
     RECT  160.272 3.403 165.654 3.569 ;
     RECT  104.472 3.541 105.297 3.581 ;
     RECT  158.472 3.479 159.534 3.605 ;
     RECT  160.56 3.569 165.402 3.605 ;
     RECT  91.872 3.595 91.89 3.641 ;
     RECT  139.896 3.067 143.097 3.641 ;
     RECT  88.815 3.547 89.19 3.677 ;
     RECT  139.896 3.641 139.914 3.677 ;
     RECT  158.58 3.605 159.534 3.677 ;
     RECT  160.56 3.605 165.222 3.677 ;
     RECT  218.412 3.547 218.697 3.677 ;
     RECT  148.215 2.413 148.497 3.685 ;
     RECT  158.652 3.677 159.534 3.749 ;
     RECT  96.156 3.595 96.174 3.811 ;
     RECT  96.948 2.605 96.966 3.811 ;
     RECT  159.015 3.749 159.534 3.839 ;
     RECT  96.156 3.811 96.966 3.869 ;
     RECT  99.54 3.569 100.386 3.869 ;
     RECT  152.172 3.811 152.19 3.869 ;
     RECT  96.156 3.869 96.174 3.875 ;
     RECT  151.056 3.299 151.074 3.875 ;
     RECT  157.32 3.479 157.662 3.875 ;
     RECT  160.56 3.677 163.458 3.911 ;
     RECT  160.704 3.911 163.458 3.917 ;
     RECT  115.452 3.407 136.278 3.947 ;
     RECT  135.324 3.947 136.278 3.965 ;
     RECT  161.424 3.917 163.458 3.965 ;
     RECT  164.304 3.677 165.222 3.965 ;
     RECT  140.796 3.641 143.097 3.979 ;
     RECT  138.42 3.569 138.87 4.019 ;
     RECT  91.764 3.721 91.782 4.109 ;
     RECT  115.452 3.947 134.55 4.109 ;
     RECT  161.424 3.965 163.026 4.109 ;
     RECT  140.796 3.979 143.19 4.123 ;
     RECT  146.592 3.979 146.61 4.123 ;
     RECT  140.796 4.123 143.298 4.145 ;
     RECT  146.484 4.123 146.61 4.157 ;
     RECT  148.215 3.685 148.806 4.219 ;
     RECT  162.288 4.109 163.026 4.253 ;
     RECT  163.008 4.253 163.026 4.289 ;
     RECT  115.452 4.109 134.118 4.301 ;
     RECT  56.415 2.669 56.697 4.351 ;
     RECT  67.215 2.669 67.914 4.351 ;
     RECT  78.015 2.669 78.297 4.351 ;
     RECT  88.815 3.677 89.097 4.351 ;
     RECT  146.484 4.157 146.502 4.351 ;
     RECT  153.615 3.065 153.897 4.351 ;
     RECT  175.215 2.413 175.497 4.351 ;
     RECT  186.015 2.413 186.297 4.351 ;
     RECT  196.815 2.413 197.097 4.351 ;
     RECT  207.615 2.413 207.897 4.351 ;
     RECT  90.792 4.225 90.81 4.379 ;
     RECT  145.044 3.271 145.062 4.379 ;
     RECT  148.215 4.219 149.094 4.379 ;
     RECT  151.344 4.123 151.47 4.379 ;
     RECT  56.304 4.351 56.697 4.397 ;
     RECT  67.104 4.351 67.914 4.397 ;
     RECT  77.904 4.351 78.297 4.397 ;
     RECT  88.632 4.351 89.097 4.397 ;
     RECT  146.196 4.351 146.502 4.397 ;
     RECT  153.504 4.351 153.897 4.397 ;
     RECT  164.304 3.965 164.697 4.397 ;
     RECT  175.104 4.351 175.497 4.397 ;
     RECT  185.904 4.351 186.297 4.397 ;
     RECT  196.704 4.351 197.097 4.397 ;
     RECT  207.504 4.351 207.897 4.397 ;
     RECT  118.08 4.301 134.118 4.415 ;
     RECT  138.528 4.019 138.87 4.445 ;
     RECT  141.372 4.145 143.298 4.445 ;
     RECT  150.192 4.411 150.21 4.451 ;
     RECT  146.484 4.397 146.502 4.493 ;
     RECT  151.452 4.379 151.47 4.493 ;
     RECT  152.46 4.459 152.478 4.493 ;
     RECT  216.936 4.363 216.954 4.493 ;
     RECT  90.288 4.495 90.306 4.531 ;
     RECT  141.372 4.445 143.097 4.541 ;
     RECT  157.644 3.875 157.662 4.603 ;
     RECT  90.108 4.531 90.306 4.649 ;
     RECT  90.108 4.649 90.126 4.685 ;
     RECT  157.644 4.603 157.986 4.801 ;
     RECT  141.372 4.541 141.39 4.829 ;
     RECT  157.608 4.801 157.986 4.877 ;
     RECT  99.54 3.869 99.897 4.891 ;
     RECT  157.644 4.877 157.986 4.919 ;
     RECT  88.704 4.397 89.097 4.925 ;
     RECT  99.504 4.891 99.897 4.925 ;
     RECT  118.08 4.415 133.47 4.955 ;
     RECT  85.896 3.145 85.914 5.131 ;
     RECT  102.312 3.029 102.33 5.189 ;
     RECT  96.948 3.869 96.966 5.197 ;
     RECT  106.848 3.029 112.554 5.431 ;
     RECT  159.015 3.839 159.297 5.431 ;
     RECT  85.464 5.131 85.914 5.459 ;
     RECT  157.644 4.919 157.662 5.459 ;
     RECT  118.404 4.955 133.47 5.467 ;
     RECT  85.536 5.459 85.914 5.501 ;
     RECT  158.436 5.431 159.297 5.549 ;
     RECT  118.404 5.467 133.758 5.729 ;
     RECT  118.404 5.729 130.554 5.741 ;
     RECT  145.188 5.611 145.206 5.765 ;
     RECT  78.015 4.397 78.297 5.851 ;
     RECT  131.364 5.729 133.758 5.947 ;
     RECT  136.224 5.947 136.242 5.995 ;
     RECT  96.948 5.197 97.578 5.999 ;
     RECT  131.364 5.947 134.478 5.999 ;
     RECT  145.44 5.881 145.458 5.999 ;
     RECT  83.415 2.413 83.697 6.043 ;
     RECT  85.896 5.501 85.914 6.043 ;
     RECT  105.015 3.581 105.297 6.043 ;
     RECT  118.656 5.741 130.554 6.071 ;
     RECT  78.015 5.851 78.678 6.077 ;
     RECT  105.015 6.043 105.822 6.077 ;
     RECT  146.448 5.971 146.466 6.077 ;
     RECT  96.12 4.387 96.138 6.115 ;
     RECT  135.324 3.965 135.342 6.151 ;
     RECT  85.896 6.043 86.49 6.173 ;
     RECT  136.224 5.995 136.494 6.179 ;
     RECT  133.452 5.999 133.758 6.221 ;
     RECT  131.364 5.999 132.534 6.269 ;
     RECT  133.452 6.221 133.47 6.269 ;
     RECT  136.476 6.179 136.494 6.269 ;
     RECT  138.852 4.445 138.87 6.283 ;
     RECT  144.036 6.283 144.054 6.379 ;
     RECT  180.615 2.413 180.897 6.379 ;
     RECT  138.528 6.283 138.87 6.413 ;
     RECT  143.928 6.379 144.054 6.413 ;
     RECT  56.415 4.397 56.697 6.511 ;
     RECT  67.215 4.397 67.914 6.511 ;
     RECT  78.015 6.077 78.297 6.511 ;
     RECT  153.615 4.397 153.897 6.511 ;
     RECT  164.415 4.397 164.697 6.511 ;
     RECT  175.215 4.397 175.497 6.511 ;
     RECT  180.432 6.379 180.897 6.511 ;
     RECT  186.015 4.397 186.297 6.511 ;
     RECT  196.815 4.397 197.097 6.511 ;
     RECT  207.615 4.397 207.897 6.511 ;
     RECT  82.98 6.043 83.697 6.539 ;
     RECT  118.656 6.071 130.158 6.539 ;
     RECT  143.928 6.413 143.946 6.539 ;
     RECT  180.432 6.511 181.242 6.539 ;
     RECT  56.304 6.511 56.697 6.557 ;
     RECT  67.104 6.511 67.914 6.557 ;
     RECT  77.904 6.511 78.297 6.557 ;
     RECT  83.268 6.539 83.697 6.557 ;
     RECT  144.756 6.511 144.774 6.557 ;
     RECT  153.504 6.511 153.897 6.557 ;
     RECT  164.304 6.511 164.697 6.557 ;
     RECT  175.104 6.511 175.497 6.557 ;
     RECT  185.904 6.511 186.297 6.557 ;
     RECT  196.704 6.511 197.097 6.557 ;
     RECT  207.504 6.511 207.897 6.557 ;
     RECT  180.615 6.539 181.242 6.605 ;
     RECT  106.56 5.431 112.554 6.611 ;
     RECT  214.344 6.523 214.362 6.653 ;
     RECT  106.56 6.611 112.05 6.811 ;
     RECT  106.416 6.811 112.05 6.845 ;
     RECT  118.656 6.539 123.714 6.845 ;
     RECT  85.896 6.173 85.914 7.079 ;
     RECT  93.492 3.145 94.986 7.079 ;
     RECT  106.596 6.845 112.05 7.151 ;
     RECT  115.452 4.301 117.126 7.151 ;
     RECT  135.324 6.151 135.414 7.231 ;
     RECT  131.364 6.269 132.297 7.259 ;
     RECT  118.728 6.845 123.714 7.385 ;
     RECT  124.524 6.539 130.158 7.429 ;
     RECT  124.488 7.429 130.158 7.457 ;
     RECT  118.764 7.385 123.714 7.501 ;
     RECT  124.488 7.457 129.762 7.501 ;
     RECT  95.868 6.115 96.138 7.619 ;
     RECT  94.215 7.079 94.986 7.735 ;
     RECT  79.884 7.435 79.902 7.861 ;
     RECT  135.324 7.231 135.846 7.861 ;
     RECT  175.215 6.557 175.497 7.861 ;
     RECT  218.415 3.677 218.697 7.867 ;
     RECT  79.884 7.861 80.226 7.889 ;
     RECT  80.208 7.889 80.226 7.901 ;
     RECT  173.484 7.861 173.502 7.901 ;
     RECT  175.215 7.861 175.59 7.901 ;
     RECT  118.764 7.501 129.762 7.925 ;
     RECT  135.324 7.861 136.098 7.925 ;
     RECT  136.08 7.925 136.098 7.949 ;
     RECT  178.452 7.861 178.47 7.949 ;
     RECT  179.568 7.915 179.586 7.961 ;
     RECT  218.304 7.867 218.697 7.997 ;
     RECT  45.108 2.413 45.897 8.203 ;
     RECT  118.764 7.925 123.678 8.311 ;
     RECT  106.848 7.151 112.05 8.395 ;
     RECT  96.12 7.619 96.138 8.429 ;
     RECT  118.692 8.311 123.678 8.429 ;
     RECT  105.015 6.077 105.297 8.437 ;
     RECT  106.596 8.395 112.05 8.437 ;
     RECT  105.015 8.437 112.05 8.477 ;
     RECT  124.524 7.925 129.762 8.509 ;
     RECT  106.596 8.477 112.05 8.525 ;
     RECT  94.215 7.735 95.238 8.545 ;
     RECT  56.415 6.557 56.697 8.671 ;
     RECT  67.215 6.557 67.914 8.671 ;
     RECT  78.015 6.557 78.297 8.671 ;
     RECT  88.815 4.925 89.097 8.671 ;
     RECT  99.54 4.925 99.897 8.671 ;
     RECT  105.015 8.477 105.426 8.671 ;
     RECT  94.215 8.545 95.922 8.699 ;
     RECT  104.508 8.671 105.426 8.699 ;
     RECT  106.848 8.525 112.05 8.699 ;
     RECT  104.508 8.699 105.297 8.717 ;
     RECT  137.415 3.569 137.697 8.941 ;
     RECT  85.644 7.195 85.662 8.969 ;
     RECT  135.324 7.925 135.342 8.969 ;
     RECT  92.988 7.195 93.006 9.067 ;
     RECT  124.524 8.509 129.834 9.085 ;
     RECT  130.968 7.429 130.986 9.085 ;
     RECT  92.808 9.067 93.006 9.113 ;
     RECT  94.215 8.699 95.562 9.239 ;
     RECT  124.524 9.085 130.986 9.239 ;
     RECT  56.304 8.671 56.697 9.245 ;
     RECT  67.104 8.671 67.914 9.245 ;
     RECT  77.904 8.671 78.297 9.245 ;
     RECT  88.704 8.671 89.097 9.245 ;
     RECT  98.604 9.211 98.622 9.341 ;
     RECT  93.312 9.247 93.33 9.355 ;
     RECT  99.504 8.671 99.897 9.355 ;
     RECT  94.215 9.239 95.274 9.509 ;
     RECT  106.848 8.699 112.014 9.509 ;
     RECT  106.848 9.509 111.258 9.661 ;
     RECT  114.264 2.911 114.282 9.751 ;
     RECT  94.215 9.509 95.058 9.779 ;
     RECT  124.524 9.239 129.798 9.821 ;
     RECT  113.904 9.751 114.282 9.823 ;
     RECT  118.764 8.429 123.678 9.823 ;
     RECT  112.896 9.661 112.914 9.931 ;
     RECT  113.832 9.823 114.282 9.931 ;
     RECT  118.584 9.823 123.678 9.959 ;
     RECT  112.86 9.931 114.282 9.965 ;
     RECT  93.312 9.355 93.474 10.021 ;
     RECT  94.215 9.779 94.878 10.021 ;
     RECT  40.215 2.413 40.497 10.027 ;
     RECT  93.312 10.021 94.878 10.049 ;
     RECT  112.896 9.965 114.282 10.049 ;
     RECT  101.484 3.145 101.502 10.057 ;
     RECT  101.448 10.057 101.502 10.093 ;
     RECT  118.764 9.959 123.678 10.129 ;
     RECT  124.524 9.821 129.762 10.129 ;
     RECT  40.215 10.027 40.59 10.157 ;
     RECT  93.384 10.049 94.878 10.157 ;
     RECT  92.592 10.123 92.61 10.229 ;
     RECT  101.052 10.093 101.502 10.229 ;
     RECT  113.256 10.049 114.282 10.229 ;
     RECT  72.615 2.413 72.897 10.291 ;
     RECT  97.56 5.999 97.578 10.319 ;
     RECT  72.615 10.291 73.458 10.349 ;
     RECT  113.796 10.229 114.282 10.445 ;
     RECT  105.015 8.717 105.297 10.561 ;
     RECT  106.596 9.661 111.258 10.561 ;
     RECT  92.232 10.267 92.25 10.589 ;
     RECT  105.015 10.561 111.258 10.637 ;
     RECT  85.068 9.085 85.086 10.741 ;
     RECT  92.16 10.741 92.178 10.795 ;
     RECT  72.615 10.349 73.17 10.829 ;
     RECT  56.415 9.245 56.697 10.831 ;
     RECT  67.215 9.245 67.914 10.831 ;
     RECT  78.015 9.245 78.297 10.831 ;
     RECT  88.815 9.245 89.097 10.831 ;
     RECT  92.016 10.795 92.178 10.831 ;
     RECT  111.996 9.509 112.014 10.843 ;
     RECT  97.452 10.435 97.47 10.859 ;
     RECT  115.452 7.151 116.694 10.859 ;
     RECT  118.764 10.129 129.762 10.859 ;
     RECT  106.488 10.637 111.258 10.903 ;
     RECT  111.996 10.843 112.446 10.903 ;
     RECT  93.528 10.157 94.878 11.011 ;
     RECT  85.068 10.741 85.158 11.129 ;
     RECT  91.944 10.831 92.178 11.129 ;
     RECT  105.015 10.637 105.714 11.129 ;
     RECT  106.488 10.903 112.446 11.129 ;
     RECT  106.488 11.129 106.506 11.165 ;
     RECT  143.928 11.131 143.946 11.165 ;
     RECT  144.756 11.101 144.774 11.165 ;
     RECT  91.944 11.129 91.998 11.201 ;
     RECT  105.015 11.129 105.498 11.213 ;
     RECT  114.264 10.445 114.282 11.227 ;
     RECT  107.352 11.129 112.446 11.273 ;
     RECT  83.415 6.557 83.697 11.371 ;
     RECT  90.18 11.227 90.63 11.371 ;
     RECT  91.62 11.245 91.638 11.371 ;
     RECT  87.228 10.891 87.246 11.399 ;
     RECT  90.18 11.371 91.638 11.399 ;
     RECT  93.528 11.011 95.202 11.399 ;
     RECT  107.64 11.273 112.446 11.399 ;
     RECT  119.016 10.859 129.762 11.399 ;
     RECT  131.832 7.259 132.297 11.399 ;
     RECT  83.232 11.371 83.862 11.405 ;
     RECT  90.18 11.399 91.422 11.405 ;
     RECT  93.528 11.399 94.806 11.405 ;
     RECT  114.264 11.227 114.606 11.405 ;
     RECT  77.904 10.831 78.297 11.407 ;
     RECT  84.888 11.245 84.906 11.407 ;
     RECT  84.672 11.407 84.906 11.507 ;
     RECT  107.64 11.399 112.302 11.549 ;
     RECT  133.524 11.551 133.542 11.641 ;
     RECT  84.708 11.507 84.906 11.669 ;
     RECT  91.296 11.405 91.422 11.669 ;
     RECT  84.708 11.669 84.726 11.705 ;
     RECT  91.296 11.669 91.314 11.705 ;
     RECT  133.524 11.641 133.614 11.821 ;
     RECT  56.304 10.831 56.697 11.849 ;
     RECT  67.104 10.831 67.914 11.849 ;
     RECT  77.904 11.407 78.534 11.849 ;
     RECT  88.704 10.831 89.097 11.939 ;
     RECT  90.036 11.551 90.054 11.939 ;
     RECT  93.564 11.405 94.806 11.939 ;
     RECT  133.524 11.821 134.55 11.939 ;
     RECT  93.564 11.939 94.662 11.975 ;
     RECT  93.564 11.975 94.59 11.981 ;
     RECT  133.776 11.939 134.55 12.083 ;
     RECT  218.415 7.997 218.697 12.091 ;
     RECT  40.215 10.157 40.497 12.187 ;
     RECT  133.776 12.083 133.902 12.209 ;
     RECT  133.776 12.209 133.794 12.221 ;
     RECT  49.104 7.123 49.122 12.253 ;
     RECT  49.86 1.387 49.878 12.253 ;
     RECT  130.968 9.239 130.986 12.253 ;
     RECT  106.596 12.019 106.614 12.281 ;
     RECT  115.452 10.859 116.586 12.281 ;
     RECT  119.412 11.399 129.762 12.281 ;
     RECT  83.415 11.405 83.862 12.479 ;
     RECT  218.304 12.091 218.697 12.509 ;
     RECT  40.215 12.187 40.59 12.523 ;
     RECT  41.436 0.859 41.454 12.523 ;
     RECT  119.412 12.281 123.354 12.523 ;
     RECT  83.415 12.479 83.697 12.715 ;
     RECT  83.196 12.715 83.697 12.757 ;
     RECT  142.2 4.541 143.097 12.793 ;
     RECT  82.8 12.757 83.697 12.797 ;
     RECT  84.708 12.523 84.726 12.811 ;
     RECT  107.64 11.549 112.014 12.821 ;
     RECT  78.015 11.849 78.534 12.991 ;
     RECT  40.215 12.523 41.454 13.003 ;
     RECT  84.708 12.811 85.014 13.019 ;
     RECT  119.124 12.523 123.354 13.019 ;
     RECT  83.196 12.797 83.697 13.037 ;
     RECT  40.104 13.003 41.454 13.091 ;
     RECT  56.415 11.849 56.697 13.435 ;
     RECT  67.215 11.849 67.914 13.435 ;
     RECT  88.815 11.939 89.097 13.435 ;
     RECT  142.2 12.793 143.55 13.441 ;
     RECT  56.304 13.435 56.697 13.469 ;
     RECT  67.104 13.435 67.914 13.469 ;
     RECT  77.904 12.991 78.534 13.469 ;
     RECT  88.704 13.435 89.097 13.469 ;
     RECT  119.916 13.019 123.354 13.559 ;
     RECT  107.64 12.821 111.978 13.675 ;
     RECT  107.64 13.675 112.626 13.873 ;
     RECT  107.64 13.873 112.95 14.009 ;
     RECT  119.952 13.559 123.354 14.099 ;
     RECT  107.64 14.009 112.878 14.189 ;
     RECT  142.2 13.441 143.874 14.251 ;
     RECT  142.2 14.251 144.018 14.405 ;
     RECT  107.64 14.189 111.114 14.521 ;
     RECT  142.2 14.405 143.802 14.521 ;
     RECT  114.264 11.405 114.282 14.549 ;
     RECT  142.164 14.521 143.802 14.549 ;
     RECT  138.852 6.413 138.87 14.647 ;
     RECT  111.924 14.189 112.878 14.675 ;
     RECT  124.488 12.281 129.762 14.711 ;
     RECT  124.488 14.711 125.55 14.813 ;
     RECT  136.872 8.941 137.697 14.827 ;
     RECT  138.672 14.647 138.87 14.827 ;
     RECT  42.408 0.091 42.858 14.881 ;
     RECT  49.104 12.253 49.878 14.909 ;
     RECT  94.215 11.981 94.59 14.909 ;
     RECT  103.392 0.523 103.41 14.909 ;
     RECT  107.136 14.521 111.114 14.909 ;
     RECT  136.872 14.827 138.87 14.945 ;
     RECT  112.032 14.675 112.878 14.957 ;
     RECT  138.492 14.945 138.87 14.989 ;
     RECT  106.128 15.019 106.146 15.053 ;
     RECT  94.215 14.909 94.497 15.061 ;
     RECT  99.108 9.355 99.897 15.061 ;
     RECT  112.68 14.957 112.878 15.061 ;
     RECT  112.68 15.061 113.058 15.215 ;
     RECT  138.492 14.989 138.942 15.215 ;
     RECT  134.532 14.989 134.55 15.287 ;
     RECT  138.528 15.215 138.942 15.287 ;
     RECT  118.584 14.449 118.602 15.323 ;
     RECT  112.68 15.215 112.698 15.359 ;
     RECT  94.14 15.061 94.497 15.421 ;
     RECT  101.052 10.229 101.466 15.421 ;
     RECT  78.015 13.469 78.534 15.449 ;
     RECT  83.415 13.037 83.697 15.451 ;
     RECT  100.692 15.421 101.466 15.485 ;
     RECT  93.96 15.421 94.497 15.565 ;
     RECT  99.072 15.061 99.897 15.565 ;
     RECT  138.528 15.287 138.87 15.629 ;
     RECT  34.815 2.413 35.097 15.691 ;
     RECT  98.964 15.565 99.897 15.719 ;
     RECT  107.28 14.909 111.114 15.725 ;
     RECT  93.78 15.565 94.497 15.799 ;
     RECT  34.815 15.691 35.514 15.835 ;
     RECT  34.815 15.835 35.838 15.871 ;
     RECT  42.408 14.881 42.93 15.871 ;
     RECT  92.484 15.727 92.502 15.871 ;
     RECT  93.744 15.799 94.497 15.871 ;
     RECT  142.164 14.549 143.658 15.871 ;
     RECT  83.415 15.451 83.79 15.989 ;
     RECT  33.912 15.979 33.93 15.997 ;
     RECT  42.408 15.871 43.326 15.997 ;
     RECT  33.912 15.997 34.002 16.025 ;
     RECT  93.564 15.871 94.497 16.025 ;
     RECT  97.452 15.739 97.47 16.025 ;
     RECT  38.52 1.435 38.538 16.033 ;
     RECT  40.215 13.091 40.497 16.033 ;
     RECT  41.436 13.091 41.454 16.033 ;
     RECT  44.244 15.997 44.262 16.033 ;
     RECT  45.108 8.203 46.458 16.033 ;
     RECT  40.215 16.033 41.454 16.069 ;
     RECT  42.408 15.997 43.47 16.075 ;
     RECT  44.244 16.033 46.458 16.075 ;
     RECT  67.215 13.469 67.914 16.075 ;
     RECT  38.52 16.033 39.006 16.105 ;
     RECT  83.415 15.989 83.697 16.105 ;
     RECT  130.968 12.253 131.202 16.105 ;
     RECT  56.415 13.469 56.697 16.123 ;
     RECT  67.215 16.075 68.598 16.123 ;
     RECT  78.015 15.449 78.354 16.123 ;
     RECT  88.815 13.469 89.097 16.123 ;
     RECT  92.304 15.871 92.502 16.123 ;
     RECT  38.52 16.105 39.33 16.141 ;
     RECT  40.215 16.069 41.49 16.141 ;
     RECT  98.712 15.835 98.73 16.141 ;
     RECT  130.536 16.105 131.202 16.141 ;
     RECT  132.015 11.399 132.297 16.141 ;
     RECT  56.304 16.123 56.697 16.169 ;
     RECT  77.904 16.123 78.354 16.169 ;
     RECT  88.704 16.123 89.097 16.169 ;
     RECT  83.304 16.105 83.697 16.259 ;
     RECT  98.388 16.141 98.73 16.259 ;
     RECT  107.424 15.725 111.114 16.259 ;
     RECT  67.104 16.123 68.598 16.267 ;
     RECT  102.6 15.025 102.618 16.267 ;
     RECT  124.488 14.813 125.514 16.267 ;
     RECT  126.36 14.711 129.762 16.267 ;
     RECT  98.388 16.259 98.406 16.295 ;
     RECT  66.816 16.267 68.598 16.301 ;
     RECT  102.6 16.267 102.726 16.301 ;
     RECT  107.496 16.259 111.114 16.301 ;
     RECT  130.536 16.141 132.297 16.301 ;
     RECT  218.415 12.509 218.697 16.315 ;
     RECT  74.592 16.231 74.61 16.331 ;
     RECT  65.376 16.105 65.394 16.339 ;
     RECT  66.816 16.301 68.49 16.339 ;
     RECT  64.548 16.303 64.566 16.349 ;
     RECT  92.304 16.123 92.934 16.349 ;
     RECT  218.304 16.315 218.697 16.363 ;
     RECT  42.408 16.075 46.458 16.367 ;
     RECT  37.584 16.141 37.602 16.375 ;
     RECT  38.52 16.141 41.49 16.375 ;
     RECT  42.408 16.367 43.866 16.375 ;
     RECT  66.744 16.339 68.49 16.397 ;
     RECT  102.708 16.301 102.726 16.397 ;
     RECT  65.376 16.339 65.538 16.403 ;
     RECT  33.984 16.025 34.002 16.411 ;
     RECT  34.815 15.871 36.378 16.411 ;
     RECT  106.092 16.363 106.11 16.439 ;
     RECT  218.304 16.363 219.402 16.439 ;
     RECT  33.984 16.411 36.378 16.445 ;
     RECT  124.488 16.267 129.762 16.445 ;
     RECT  218.304 16.439 219.222 16.445 ;
     RECT  34.2 16.445 36.378 16.501 ;
     RECT  99.615 15.719 99.897 16.501 ;
     RECT  101.052 15.485 101.466 16.501 ;
     RECT  37.584 16.375 43.866 16.529 ;
     RECT  96.516 16.315 96.534 16.529 ;
     RECT  97.596 16.141 97.614 16.529 ;
     RECT  99.615 16.501 101.466 16.529 ;
     RECT  130.716 16.301 132.297 16.529 ;
     RECT  142.164 15.871 143.766 16.529 ;
     RECT  66.744 16.397 68.382 16.541 ;
     RECT  108 16.301 111.114 16.541 ;
     RECT  134.496 16.363 134.514 16.541 ;
     RECT  218.304 16.445 218.697 16.541 ;
     RECT  34.2 16.501 36.666 16.573 ;
     RECT  45.108 16.367 46.458 16.799 ;
     RECT  92.304 16.349 92.322 16.799 ;
     RECT  99.615 16.529 101.07 16.799 ;
     RECT  108 16.541 108.198 16.799 ;
     RECT  108.972 16.541 111.114 16.799 ;
     RECT  146.34 16.681 146.358 16.799 ;
     RECT  167.292 16.771 167.31 16.829 ;
     RECT  108 16.799 108.126 16.835 ;
     RECT  130.968 16.529 132.297 16.835 ;
     RECT  166.176 16.795 166.194 16.835 ;
     RECT  90.864 16.771 90.882 16.877 ;
     RECT  34.2 16.573 36.702 16.879 ;
     RECT  37.584 16.529 37.602 16.879 ;
     RECT  130.968 16.835 131.094 16.907 ;
     RECT  109.044 16.799 111.114 16.925 ;
     RECT  99.615 16.799 100.962 17.035 ;
     RECT  98.064 16.951 98.226 17.069 ;
     RECT  109.332 16.925 111.114 17.105 ;
     RECT  115.815 12.281 116.586 17.113 ;
     RECT  115.815 17.113 117.162 17.141 ;
     RECT  47.592 6.583 47.61 17.149 ;
     RECT  38.664 16.529 43.866 17.221 ;
     RECT  109.332 17.105 109.35 17.249 ;
     RECT  34.2 16.879 37.602 17.311 ;
     RECT  56.415 16.169 56.697 17.311 ;
     RECT  49.176 14.909 49.878 17.323 ;
     RECT  53.244 17.179 53.262 17.323 ;
     RECT  99.108 17.035 100.962 17.339 ;
     RECT  146.844 16.951 146.862 17.339 ;
     RECT  66.384 17.077 66.402 17.357 ;
     RECT  53.244 17.323 53.37 17.371 ;
     RECT  145.872 17.083 146.07 17.375 ;
     RECT  34.2 17.311 37.638 17.383 ;
     RECT  52.884 17.371 53.37 17.411 ;
     RECT  49.032 17.323 49.878 17.453 ;
     RECT  53.352 17.411 53.37 17.453 ;
     RECT  102.6 17.323 102.618 17.453 ;
     RECT  34.2 17.383 37.89 17.455 ;
     RECT  45.108 16.799 46.314 17.455 ;
     RECT  33.012 17.083 33.03 17.491 ;
     RECT  33.768 17.455 37.89 17.491 ;
     RECT  38.664 17.221 44.082 17.491 ;
     RECT  45 17.455 46.314 17.581 ;
     RECT  47.268 17.149 47.61 17.581 ;
     RECT  108.072 16.835 108.126 17.609 ;
     RECT  147.06 17.611 147.078 17.645 ;
     RECT  108.108 17.609 108.126 17.653 ;
     RECT  146.052 17.375 146.07 17.681 ;
     RECT  126.36 16.445 129.762 17.761 ;
     RECT  67.215 16.541 67.914 17.851 ;
     RECT  78.015 16.169 78.354 17.851 ;
     RECT  88.815 16.169 89.097 17.851 ;
     RECT  99.108 17.339 100.35 17.851 ;
     RECT  110.415 17.105 111.114 17.851 ;
     RECT  153.615 6.557 153.897 17.851 ;
     RECT  164.415 6.557 164.697 17.851 ;
     RECT  175.215 7.901 175.497 17.851 ;
     RECT  186.015 6.557 186.297 17.851 ;
     RECT  196.815 6.557 197.097 17.851 ;
     RECT  207.615 6.557 207.897 17.851 ;
     RECT  218.415 16.541 218.697 17.851 ;
     RECT  96.408 16.951 96.426 17.879 ;
     RECT  98.604 17.851 100.35 17.879 ;
     RECT  33.012 17.491 44.082 17.885 ;
     RECT  56.304 17.311 56.697 17.885 ;
     RECT  67.104 17.851 67.914 17.885 ;
     RECT  77.904 17.851 78.354 17.885 ;
     RECT  88.704 17.851 89.097 17.885 ;
     RECT  110.304 17.851 111.114 17.885 ;
     RECT  153.504 17.851 153.897 17.885 ;
     RECT  164.304 17.851 164.697 17.885 ;
     RECT  175.104 17.851 175.497 17.885 ;
     RECT  185.904 17.851 186.297 17.885 ;
     RECT  196.704 17.851 197.097 17.885 ;
     RECT  207.504 17.851 207.897 17.885 ;
     RECT  94.215 16.025 94.497 17.887 ;
     RECT  98.604 17.879 100.206 17.915 ;
     RECT  218.304 17.851 218.697 17.923 ;
     RECT  93.708 17.887 94.497 17.933 ;
     RECT  218.304 17.923 219.006 17.959 ;
     RECT  98.604 17.915 98.622 17.981 ;
     RECT  218.304 17.959 219.258 17.981 ;
     RECT  26.892 17.851 26.91 17.995 ;
     RECT  26.892 17.995 27.378 18.031 ;
     RECT  33.66 17.885 44.082 18.031 ;
     RECT  220.356 17.947 220.374 18.031 ;
     RECT  220.356 18.031 220.662 18.059 ;
     RECT  220.644 18.059 220.662 18.077 ;
     RECT  126.252 17.761 129.762 18.149 ;
     RECT  33.66 18.031 44.226 18.157 ;
     RECT  45 17.581 47.61 18.157 ;
     RECT  29.415 2.413 29.697 18.193 ;
     RECT  22.752 18.193 22.77 18.301 ;
     RECT  26.136 17.851 26.154 18.301 ;
     RECT  26.892 18.031 28.17 18.301 ;
     RECT  50.616 2.413 51.297 18.301 ;
     RECT  52.128 0.811 52.146 18.301 ;
     RECT  108.108 17.653 108.594 18.379 ;
     RECT  49.176 17.453 49.878 18.419 ;
     RECT  22.716 18.301 22.95 18.427 ;
     RECT  24.015 2.413 24.297 18.427 ;
     RECT  25.452 18.301 28.17 18.427 ;
     RECT  29.415 18.193 30.33 18.427 ;
     RECT  144.684 18.391 144.702 18.427 ;
     RECT  25.38 18.427 30.33 18.455 ;
     RECT  107.82 18.379 108.594 18.455 ;
     RECT  21.672 18.427 21.69 18.461 ;
     RECT  28.8 18.455 30.33 18.461 ;
     RECT  25.38 18.455 27.918 18.499 ;
     RECT  50.616 18.301 52.146 18.535 ;
     RECT  144.684 18.427 144.918 18.535 ;
     RECT  217.332 18.499 217.35 18.535 ;
     RECT  22.716 18.427 24.297 18.571 ;
     RECT  25.308 18.499 27.918 18.571 ;
     RECT  29.16 18.461 30.33 18.571 ;
     RECT  108.108 18.455 108.594 18.571 ;
     RECT  25.236 18.571 27.918 18.599 ;
     RECT  115.815 17.141 116.097 18.661 ;
     RECT  142.164 16.529 143.55 18.661 ;
     RECT  144.324 18.535 144.954 18.661 ;
     RECT  117.144 17.141 117.162 18.667 ;
     RECT  25.236 18.599 27.882 18.697 ;
     RECT  115.488 18.661 116.097 18.701 ;
     RECT  33.66 18.157 47.61 18.715 ;
     RECT  21.024 18.571 21.33 18.761 ;
     RECT  20.124 18.697 20.142 18.763 ;
     RECT  21.024 18.761 21.222 18.763 ;
     RECT  22.644 18.571 24.297 18.763 ;
     RECT  124.488 16.445 125.514 18.763 ;
     RECT  25.2 18.697 27.882 18.769 ;
     RECT  33.66 18.715 47.682 18.769 ;
     RECT  110.415 17.885 111.114 18.769 ;
     RECT  117.144 18.667 117.306 18.769 ;
     RECT  124.344 18.763 125.514 18.805 ;
     RECT  22.644 18.763 24.318 18.841 ;
     RECT  33.552 18.769 47.682 18.841 ;
     RECT  49.176 18.419 49.446 18.841 ;
     RECT  108.108 18.571 108.774 18.841 ;
     RECT  110.376 18.769 111.186 18.841 ;
     RECT  67.215 17.885 67.914 18.859 ;
     RECT  25.092 18.769 27.882 18.869 ;
     RECT  78.015 17.885 78.354 18.869 ;
     RECT  109.8 18.841 111.186 18.959 ;
     RECT  142.164 18.661 144.954 18.959 ;
     RECT  33.552 18.841 47.718 18.967 ;
     RECT  124.344 18.805 125.586 18.967 ;
     RECT  126.36 18.149 129.762 18.967 ;
     RECT  114.912 18.931 114.93 18.989 ;
     RECT  109.872 18.959 111.114 18.995 ;
     RECT  117.036 18.769 117.306 19.003 ;
     RECT  118.584 18.931 118.602 19.031 ;
     RECT  115.704 18.701 116.097 19.037 ;
     RECT  117.036 19.003 117.774 19.037 ;
     RECT  49.104 18.841 49.446 19.039 ;
     RECT  67.215 18.859 68.274 19.039 ;
     RECT  124.344 18.967 129.762 19.039 ;
     RECT  138.852 15.629 138.87 19.039 ;
     RECT  33.372 18.967 47.718 19.051 ;
     RECT  48.708 19.039 49.446 19.075 ;
     RECT  67.215 19.039 68.706 19.075 ;
     RECT  69.552 18.841 69.57 19.075 ;
     RECT  117.756 19.037 117.774 19.075 ;
     RECT  29.16 18.571 30.978 19.111 ;
     RECT  33.372 19.051 47.79 19.111 ;
     RECT  48.528 19.075 49.446 19.111 ;
     RECT  217.26 18.535 217.35 19.111 ;
     RECT  218.415 17.981 219.258 19.111 ;
     RECT  138.528 19.039 138.87 19.139 ;
     RECT  22.572 18.841 24.318 19.195 ;
     RECT  21.96 19.195 24.318 19.201 ;
     RECT  29.16 19.111 31.05 19.201 ;
     RECT  32.364 19.111 32.382 19.229 ;
     RECT  117.756 19.075 118.278 19.229 ;
     RECT  124.344 19.039 129.834 19.229 ;
     RECT  20.124 18.763 21.222 19.273 ;
     RECT  28.836 19.201 31.05 19.277 ;
     RECT  29.052 19.277 31.05 19.291 ;
     RECT  108.108 18.841 108.99 19.301 ;
     RECT  114.768 19.075 114.786 19.337 ;
     RECT  124.668 19.229 129.834 19.337 ;
     RECT  29.052 19.291 31.122 19.345 ;
     RECT  50.472 18.535 52.146 19.345 ;
     RECT  124.668 19.337 129.762 19.373 ;
     RECT  52.992 18.805 53.01 19.381 ;
     RECT  33.372 19.111 49.446 19.471 ;
     RECT  50.292 19.345 52.146 19.471 ;
     RECT  56.415 17.885 56.697 19.471 ;
     RECT  153.615 17.885 153.897 19.471 ;
     RECT  164.415 17.885 164.697 19.471 ;
     RECT  175.215 17.885 175.497 19.471 ;
     RECT  186.015 17.885 186.297 19.471 ;
     RECT  196.815 17.885 197.097 19.471 ;
     RECT  207.615 17.885 207.897 19.471 ;
     RECT  29.052 19.345 31.374 19.483 ;
     RECT  67.215 19.075 69.57 19.483 ;
     RECT  118.044 19.229 118.278 19.499 ;
     RECT  18.615 2.413 18.897 19.507 ;
     RECT  33.372 19.471 52.146 19.507 ;
     RECT  52.92 19.381 53.01 19.507 ;
     RECT  33.372 19.507 53.01 19.579 ;
     RECT  66.816 19.483 69.642 19.579 ;
     RECT  66.744 19.579 69.642 19.613 ;
     RECT  124.668 19.373 129.726 19.643 ;
     RECT  18.615 19.507 19.17 19.651 ;
     RECT  19.944 19.273 21.222 19.651 ;
     RECT  25.2 18.869 27.882 19.651 ;
     RECT  33.372 19.579 53.298 19.651 ;
     RECT  66.744 19.613 69.57 19.651 ;
     RECT  112.284 19.615 112.302 19.651 ;
     RECT  109.98 18.995 111.114 19.679 ;
     RECT  142.2 18.959 144.954 19.679 ;
     RECT  33.264 19.651 53.298 19.709 ;
     RECT  33.264 19.709 52.794 19.769 ;
     RECT  66.708 19.651 69.57 19.769 ;
     RECT  101.628 19.345 101.646 19.769 ;
     RECT  124.668 19.643 128.97 19.769 ;
     RECT  106.596 18.535 106.614 19.777 ;
     RECT  110.415 19.679 111.114 19.777 ;
     RECT  118.116 19.499 118.278 19.777 ;
     RECT  33.264 19.769 51.606 19.805 ;
     RECT  66.708 19.769 67.806 19.805 ;
     RECT  118.116 19.777 118.35 19.805 ;
     RECT  220.356 19.741 220.374 19.805 ;
     RECT  21.96 19.201 24.354 19.813 ;
     RECT  25.2 19.651 28.314 19.813 ;
     RECT  61.815 2.413 62.097 19.819 ;
     RECT  65.52 16.403 65.538 19.841 ;
     RECT  66.708 19.805 67.497 19.841 ;
     RECT  17.064 19.813 17.082 19.849 ;
     RECT  18.18 19.651 21.222 19.849 ;
     RECT  57.744 16.231 57.762 19.849 ;
     RECT  112.284 19.651 112.446 19.853 ;
     RECT  52.704 19.769 52.794 19.877 ;
     RECT  114.588 19.777 114.606 19.877 ;
     RECT  118.332 19.805 118.35 19.877 ;
     RECT  129.708 19.643 129.726 19.877 ;
     RECT  16.992 19.849 17.082 19.885 ;
     RECT  110.415 19.777 111.186 19.913 ;
     RECT  18.036 19.849 21.222 19.915 ;
     RECT  21.96 19.813 28.314 19.915 ;
     RECT  16.992 19.885 17.118 19.921 ;
     RECT  29.052 19.483 31.446 19.921 ;
     RECT  32.22 19.345 32.238 19.921 ;
     RECT  57.744 19.849 57.834 19.921 ;
     RECT  52.776 19.877 52.794 19.949 ;
     RECT  54.72 19.849 54.738 19.949 ;
     RECT  56.304 19.471 56.697 19.949 ;
     RECT  57.6 19.921 57.834 19.949 ;
     RECT  61.815 19.819 62.73 19.949 ;
     RECT  66.744 19.841 67.497 19.949 ;
     RECT  74.664 19.819 74.682 19.949 ;
     RECT  86.652 19.819 86.67 19.949 ;
     RECT  98.604 19.819 98.622 19.949 ;
     RECT  106.596 19.777 106.65 19.949 ;
     RECT  112.428 19.853 112.446 19.949 ;
     RECT  220.644 19.915 220.662 19.949 ;
     RECT  132.015 16.835 132.297 20.011 ;
     RECT  33.264 19.805 51.462 20.039 ;
     RECT  142.2 19.679 144.162 20.039 ;
     RECT  131.904 20.011 132.297 20.045 ;
     RECT  153.504 19.471 153.897 20.045 ;
     RECT  164.304 19.471 164.697 20.045 ;
     RECT  175.104 19.471 175.497 20.045 ;
     RECT  185.904 19.471 186.297 20.045 ;
     RECT  196.704 19.471 197.097 20.045 ;
     RECT  207.504 19.471 207.897 20.045 ;
     RECT  16.992 19.921 17.19 20.047 ;
     RECT  33.264 20.039 47.97 20.075 ;
     RECT  57.6 19.949 57.618 20.075 ;
     RECT  68.616 19.769 69.57 20.075 ;
     RECT  16.596 20.047 17.19 20.083 ;
     RECT  18.036 19.915 28.314 20.083 ;
     RECT  108.108 19.301 108.198 20.083 ;
     RECT  124.92 19.769 128.97 20.093 ;
     RECT  214.344 20.011 214.362 20.141 ;
     RECT  108.072 20.083 108.198 20.155 ;
     RECT  144.936 19.679 144.954 20.183 ;
     RECT  13.215 2.413 13.497 20.191 ;
     RECT  97.236 20.119 97.254 20.191 ;
     RECT  16.596 20.083 28.314 20.219 ;
     RECT  48.96 20.039 51.462 20.219 ;
     RECT  145.008 20.191 145.026 20.309 ;
     RECT  29.052 19.921 32.238 20.317 ;
     RECT  88.815 17.885 89.097 20.317 ;
     RECT  106.668 19.963 106.974 20.345 ;
     RECT  16.812 20.219 28.314 20.389 ;
     RECT  29.052 20.317 32.418 20.389 ;
     RECT  108.036 20.155 108.198 20.461 ;
     RECT  217.26 19.111 219.258 20.461 ;
     RECT  102.6 19.777 102.618 20.489 ;
     RECT  217.26 20.461 219.582 20.539 ;
     RECT  48.96 20.219 51.297 20.579 ;
     RECT  13.215 20.191 13.806 20.587 ;
     RECT  107.964 20.461 108.198 20.587 ;
     RECT  217.044 20.539 219.582 20.587 ;
     RECT  126.396 20.093 128.97 20.615 ;
     RECT  49.032 20.579 51.297 20.621 ;
     RECT  144.144 20.039 144.162 20.635 ;
     RECT  16.812 20.389 32.418 20.695 ;
     RECT  49.068 20.621 51.297 20.723 ;
     RECT  97.128 20.191 97.254 20.731 ;
     RECT  106.668 20.345 106.902 20.731 ;
     RECT  107.964 20.587 108.27 20.731 ;
     RECT  217.044 20.587 219.762 20.731 ;
     RECT  142.2 20.039 143.097 20.821 ;
     RECT  142.2 20.821 143.334 20.849 ;
     RECT  112.86 20.875 112.878 20.88 ;
     RECT  97.128 20.731 97.794 20.885 ;
     RECT  107.964 20.731 108.342 20.885 ;
     RECT  16.812 20.695 32.454 20.893 ;
     RECT  33.264 20.075 47.898 20.893 ;
     RECT  112.857 20.88 112.881 20.919 ;
     RECT  112.86 20.919 112.881 20.921 ;
     RECT  108.324 20.885 108.342 20.957 ;
     RECT  97.128 20.885 97.47 20.965 ;
     RECT  126.396 20.615 128.862 20.993 ;
     RECT  16.812 20.893 47.898 21.001 ;
     RECT  99.615 17.915 99.897 21.001 ;
     RECT  207.615 20.045 207.897 21.001 ;
     RECT  220.896 20.683 220.914 21.001 ;
     RECT  220.896 21.001 221.202 21.053 ;
     RECT  15.984 21.001 47.898 21.091 ;
     RECT  130.968 16.907 130.986 21.091 ;
     RECT  132.015 20.045 132.297 21.091 ;
     RECT  142.236 20.849 143.334 21.091 ;
     RECT  144.144 20.635 144.27 21.091 ;
     RECT  67.215 19.949 67.497 21.115 ;
     RECT  69.552 20.075 69.57 21.115 ;
     RECT  75.24 20.587 75.258 21.115 ;
     RECT  110.415 19.913 110.697 21.115 ;
     RECT  115.815 19.037 116.097 21.115 ;
     RECT  120.06 14.099 123.354 21.115 ;
     RECT  136.872 14.945 137.697 21.115 ;
     RECT  164.415 20.045 164.697 21.115 ;
     RECT  217.044 20.731 220.086 21.115 ;
     RECT  69.552 21.115 69.714 21.119 ;
     RECT  88.815 20.317 89.73 21.119 ;
     RECT  106.596 20.731 106.902 21.119 ;
     RECT  130.968 21.091 132.297 21.119 ;
     RECT  136.296 21.115 137.697 21.119 ;
     RECT  142.236 21.091 144.27 21.119 ;
     RECT  161.424 4.109 161.442 21.119 ;
     RECT  70.704 21.091 70.722 21.127 ;
     RECT  94.215 17.933 94.497 21.127 ;
     RECT  118.908 20.659 118.926 21.127 ;
     RECT  142.272 21.119 144.27 21.127 ;
     RECT  191.415 2.413 191.697 21.127 ;
     RECT  131.616 21.119 132.297 21.149 ;
     RECT  79.632 21.115 79.65 21.155 ;
     RECT  13.215 20.587 14.13 21.163 ;
     RECT  78.015 18.869 78.297 21.163 ;
     RECT  118.836 21.127 118.926 21.163 ;
     RECT  138.852 19.139 138.87 21.163 ;
     RECT  148.215 4.379 148.497 21.163 ;
     RECT  186.015 20.045 186.297 21.163 ;
     RECT  190.404 21.127 190.422 21.163 ;
     RECT  110.415 21.115 110.79 21.199 ;
     RECT  118.656 21.163 118.926 21.199 ;
     RECT  176.292 21.127 176.31 21.199 ;
     RECT  190.404 21.163 190.494 21.199 ;
     RECT  124.92 20.093 125.586 21.211 ;
     RECT  70.596 21.127 70.722 21.227 ;
     RECT  142.272 21.127 144.594 21.227 ;
     RECT  174.42 21.127 174.438 21.227 ;
     RECT  176.22 21.199 176.31 21.227 ;
     RECT  190.404 21.199 190.53 21.227 ;
     RECT  191.415 21.127 191.934 21.227 ;
     RECT  175.215 20.045 175.497 21.235 ;
     RECT  176.22 21.227 176.238 21.235 ;
     RECT  175.215 21.235 176.238 21.245 ;
     RECT  54.504 21.115 54.522 21.259 ;
     RECT  15.408 21.091 47.898 21.263 ;
     RECT  49.14 20.723 51.297 21.263 ;
     RECT  83.415 16.259 83.697 21.271 ;
     RECT  90.648 21.127 90.666 21.271 ;
     RECT  92.052 21.235 92.07 21.271 ;
     RECT  94.215 21.127 95.094 21.271 ;
     RECT  216.612 21.115 220.086 21.271 ;
     RECT  67.215 21.115 67.59 21.293 ;
     RECT  118.584 21.199 118.926 21.293 ;
     RECT  146.484 21.163 146.61 21.293 ;
     RECT  162.18 21.235 162.198 21.293 ;
     RECT  190.476 21.227 190.53 21.293 ;
     RECT  74.808 21.115 75.258 21.299 ;
     RECT  142.488 21.227 144.558 21.299 ;
     RECT  190.512 21.293 190.53 21.299 ;
     RECT  191.415 21.227 191.862 21.299 ;
     RECT  99.144 21.001 99.897 21.307 ;
     RECT  115.596 21.115 116.097 21.307 ;
     RECT  106.596 21.119 106.794 21.341 ;
     RECT  186.015 21.163 186.426 21.341 ;
     RECT  216.612 21.271 220.59 21.341 ;
     RECT  49.32 21.263 51.297 21.347 ;
     RECT  56.415 19.949 56.697 21.347 ;
     RECT  61.815 19.949 62.097 21.347 ;
     RECT  67.215 21.293 67.497 21.347 ;
     RECT  72.615 10.829 72.897 21.347 ;
     RECT  88.815 21.119 89.097 21.347 ;
     RECT  105.015 11.213 105.297 21.347 ;
     RECT  131.904 21.149 132.297 21.347 ;
     RECT  169.815 2.413 170.097 21.347 ;
     RECT  180.615 6.605 180.897 21.347 ;
     RECT  186.015 21.341 186.297 21.347 ;
     RECT  191.415 21.299 191.697 21.347 ;
     RECT  202.215 2.413 202.497 21.347 ;
     RECT  206.928 21.001 207.897 21.347 ;
     RECT  213.015 2.413 213.297 21.347 ;
     RECT  83.415 21.271 83.826 21.355 ;
     RECT  114.66 21.091 114.678 21.355 ;
     RECT  115.596 21.307 116.19 21.355 ;
     RECT  118.62 21.293 118.926 21.355 ;
     RECT  119.988 21.115 123.354 21.355 ;
     RECT  153.615 20.045 153.897 21.355 ;
     RECT  159.015 5.549 159.297 21.355 ;
     RECT  164.415 21.115 164.97 21.355 ;
     RECT  194.256 21.163 194.274 21.355 ;
     RECT  196.815 20.045 197.097 21.355 ;
     RECT  198.216 21.259 198.234 21.355 ;
     RECT  66.024 21.115 66.042 21.361 ;
     RECT  69.696 21.119 69.714 21.361 ;
     RECT  83.415 21.355 84.258 21.361 ;
     RECT  90 21.271 90.666 21.361 ;
     RECT  49.32 21.347 51.105 21.389 ;
     RECT  54.504 21.259 54.738 21.389 ;
     RECT  83.196 21.361 84.258 21.389 ;
     RECT  94.215 21.271 95.238 21.389 ;
     RECT  97.056 20.965 97.47 21.389 ;
     RECT  98.604 21.307 99.99 21.389 ;
     RECT  124.848 21.211 125.586 21.389 ;
     RECT  126.396 20.993 128.754 21.389 ;
     RECT  136.296 21.119 136.314 21.389 ;
     RECT  138.852 21.163 139.086 21.389 ;
     RECT  144.36 21.299 144.558 21.389 ;
     RECT  148.215 21.163 148.806 21.389 ;
     RECT  153.615 21.355 153.99 21.389 ;
     RECT  159.015 21.355 159.39 21.389 ;
     RECT  164.412 21.355 164.97 21.389 ;
     RECT  194.256 21.355 194.382 21.389 ;
     RECT  196.815 21.355 197.19 21.389 ;
     RECT  106.596 21.341 106.614 21.397 ;
     RECT  114.66 21.355 116.19 21.397 ;
     RECT  146.484 21.293 146.502 21.397 ;
     RECT  106.452 21.397 106.614 21.403 ;
     RECT  15.408 21.263 46.458 21.425 ;
     RECT  54.504 21.389 54.522 21.425 ;
     RECT  66.024 21.361 66.15 21.425 ;
     RECT  69.696 21.361 69.822 21.425 ;
     RECT  74.052 21.211 74.07 21.425 ;
     RECT  74.808 21.299 74.97 21.425 ;
     RECT  81.9 20.461 81.918 21.425 ;
     RECT  85.932 21.307 86.67 21.425 ;
     RECT  108.576 21.235 108.594 21.425 ;
     RECT  113.112 21.001 113.418 21.433 ;
     RECT  86.652 21.425 86.67 21.437 ;
     RECT  98.604 21.389 98.622 21.437 ;
     RECT  99.615 21.389 99.99 21.437 ;
     RECT  103.608 21.397 103.626 21.437 ;
     RECT  114.624 21.397 116.19 21.437 ;
     RECT  145.98 21.397 146.502 21.437 ;
     RECT  114.624 21.437 116.082 21.451 ;
     RECT  92.052 21.271 92.178 21.461 ;
     RECT  83.196 21.389 83.973 21.48 ;
     RECT  83.196 21.48 83.97 21.485 ;
     RECT  94.215 21.389 95.166 21.485 ;
     RECT  124.848 21.389 124.974 21.485 ;
     RECT  127.728 21.389 128.754 21.485 ;
     RECT  194.364 21.389 194.382 21.485 ;
     RECT  195.372 21.361 195.39 21.485 ;
     RECT  198.216 21.355 198.342 21.485 ;
     RECT  78.015 21.163 78.678 21.497 ;
     RECT  102.708 21.307 102.726 21.499 ;
     RECT  137.304 21.119 137.697 21.499 ;
     RECT  78.015 21.497 78.606 21.505 ;
     RECT  117.684 21.397 117.702 21.505 ;
     RECT  153.615 21.389 153.81 21.505 ;
     RECT  159.015 21.389 159.21 21.505 ;
     RECT  164.412 21.389 164.61 21.505 ;
     RECT  169.815 21.347 170.01 21.505 ;
     RECT  175.215 21.245 175.986 21.505 ;
     RECT  180.615 21.347 180.81 21.505 ;
     RECT  186.015 21.347 186.21 21.505 ;
     RECT  191.415 21.347 191.61 21.505 ;
     RECT  196.815 21.389 197.01 21.505 ;
     RECT  202.215 21.347 202.41 21.505 ;
     RECT  213.015 21.347 213.21 21.505 ;
     RECT  46.44 21.425 46.458 21.533 ;
     RECT  49.32 21.389 50.202 21.533 ;
     RECT  90 21.361 90.702 21.533 ;
     RECT  102.6 21.499 102.726 21.533 ;
     RECT  117.468 21.505 117.702 21.533 ;
     RECT  137.304 21.499 138.042 21.533 ;
     RECT  144.36 21.389 144.522 21.533 ;
     RECT  146.052 21.437 146.502 21.533 ;
     RECT  13.215 21.163 14.49 21.541 ;
     RECT  15.408 21.425 44.154 21.541 ;
     RECT  90.108 21.533 90.702 21.541 ;
     RECT  110.415 21.199 111.294 21.541 ;
     RECT  126.396 21.389 126.81 21.541 ;
     RECT  148.215 21.389 148.485 21.547 ;
     RECT  13.215 21.541 44.154 21.569 ;
     RECT  45 21.425 45.705 21.569 ;
     RECT  74.196 21.469 74.214 21.569 ;
     RECT  77.58 21.505 78.606 21.569 ;
     RECT  118.62 21.355 123.354 21.569 ;
     RECT  83.196 21.485 83.826 21.581 ;
     RECT  106.344 21.403 106.614 21.581 ;
     RECT  110.304 21.541 111.402 21.581 ;
     RECT  114.588 21.451 116.082 21.581 ;
     RECT  131.904 21.347 132.21 21.581 ;
     RECT  142.524 21.299 143.622 21.581 ;
     RECT  153.504 21.505 153.81 21.581 ;
     RECT  158.904 21.505 159.21 21.581 ;
     RECT  164.304 21.505 164.61 21.581 ;
     RECT  169.704 21.505 170.01 21.581 ;
     RECT  175.104 21.505 175.986 21.581 ;
     RECT  180.504 21.505 180.81 21.581 ;
     RECT  185.904 21.505 186.21 21.581 ;
     RECT  191.304 21.505 191.61 21.581 ;
     RECT  196.704 21.505 197.01 21.581 ;
     RECT  202.104 21.505 202.41 21.581 ;
     RECT  206.928 21.347 207.81 21.581 ;
     RECT  212.904 21.505 213.21 21.581 ;
     RECT  105.015 21.347 105.21 21.595 ;
     RECT  45.615 21.569 45.705 21.617 ;
     RECT  51.015 21.389 51.105 21.617 ;
     RECT  56.415 21.347 56.505 21.617 ;
     RECT  61.815 21.347 61.905 21.617 ;
     RECT  67.215 21.347 67.305 21.617 ;
     RECT  72.615 21.347 72.705 21.617 ;
     RECT  83.415 21.581 83.826 21.617 ;
     RECT  88.815 21.347 88.905 21.617 ;
     RECT  94.215 21.485 94.305 21.617 ;
     RECT  99.615 21.437 99.705 21.617 ;
     RECT  110.415 21.581 111.402 21.617 ;
     RECT  132.015 21.581 132.105 21.617 ;
     RECT  142.632 21.581 143.622 21.617 ;
     RECT  153.615 21.581 153.705 21.617 ;
     RECT  159.015 21.581 159.105 21.617 ;
     RECT  164.415 21.581 164.505 21.617 ;
     RECT  169.815 21.581 169.905 21.617 ;
     RECT  175.215 21.581 175.986 21.617 ;
     RECT  180.615 21.581 180.705 21.617 ;
     RECT  186.015 21.581 186.105 21.617 ;
     RECT  191.415 21.581 191.505 21.617 ;
     RECT  196.815 21.581 196.905 21.617 ;
     RECT  202.215 21.581 202.305 21.617 ;
     RECT  206.928 21.581 207.705 21.617 ;
     RECT  213.015 21.581 213.105 21.617 ;
     RECT  102.6 21.533 102.618 21.629 ;
     RECT  106.56 21.581 106.614 21.629 ;
     RECT  114.588 21.581 114.93 21.629 ;
     RECT  115.704 21.581 116.082 21.629 ;
     RECT  125.964 21.541 126.81 21.629 ;
     RECT  127.944 21.485 128.754 21.629 ;
     RECT  143.604 21.617 143.622 21.629 ;
     RECT  146.124 21.533 146.502 21.629 ;
     RECT  13.215 21.569 43.866 21.659 ;
     RECT  49.824 21.533 49.842 21.659 ;
     RECT  70.704 21.227 70.722 21.659 ;
     RECT  82.08 21.541 82.17 21.659 ;
     RECT  104.904 21.595 105.21 21.659 ;
     RECT  106.596 21.629 106.614 21.659 ;
     RECT  110.664 21.617 111.402 21.659 ;
     RECT  113.112 21.433 113.49 21.659 ;
     RECT  117.468 21.533 117.63 21.659 ;
     RECT  128.268 21.629 128.754 21.659 ;
     RECT  134.532 21.541 134.55 21.659 ;
     RECT  137.304 21.533 138.006 21.659 ;
     RECT  142.632 21.617 142.65 21.659 ;
     RECT  146.124 21.629 146.142 21.659 ;
     RECT  148.032 21.547 148.485 21.659 ;
     RECT  13.215 21.659 19.926 21.667 ;
     RECT  126.504 21.629 126.81 21.695 ;
     RECT  137.304 21.659 137.934 21.695 ;
     RECT  148.104 21.659 148.485 21.72 ;
     RECT  77.58 21.569 78.282 21.725 ;
     RECT  114.912 21.629 114.93 21.725 ;
     RECT  148.104 21.72 148.482 21.725 ;
     RECT  118.62 21.569 119.034 21.731 ;
     RECT  77.58 21.725 77.706 21.821 ;
     RECT  120.06 21.569 123.354 21.821 ;
     RECT  148.104 21.725 148.122 21.821 ;
     RECT  47.196 21.263 47.898 21.839 ;
     RECT  113.112 21.659 113.13 21.869 ;
     RECT  137.916 21.695 137.934 21.869 ;
     RECT  103.752 21.541 103.77 21.917 ;
     RECT  116.064 21.629 116.082 21.917 ;
     RECT  120.24 21.821 123.354 21.917 ;
     RECT  90.108 21.541 90.846 21.965 ;
     RECT  128.268 21.659 128.682 21.965 ;
     RECT  83.808 21.617 83.826 22.001 ;
     RECT  120.348 21.917 123.354 22.001 ;
     RECT  82.08 21.659 82.098 22.037 ;
     RECT  126.54 21.695 126.594 22.037 ;
     RECT  77.688 21.821 77.706 22.073 ;
     RECT  74.952 21.425 74.97 22.109 ;
     RECT  126.54 22.037 126.558 22.109 ;
     RECT  47.196 21.839 47.214 22.154 ;
     RECT  216.612 21.341 220.158 22.171 ;
     RECT  12.996 21.667 19.926 22.199 ;
     RECT  12.996 22.199 16.146 22.235 ;
     RECT  20.664 21.659 43.866 22.271 ;
     RECT  53.604 21.091 53.622 22.271 ;
     RECT  175.968 21.617 175.986 22.271 ;
     RECT  95.148 21.485 95.166 22.541 ;
     RECT  97.452 21.389 97.47 22.541 ;
     RECT  118.944 21.731 118.962 22.577 ;
     RECT  128.268 21.965 128.574 22.577 ;
     RECT  117.612 21.659 117.63 22.613 ;
     RECT  128.556 22.577 128.574 22.613 ;
     RECT  16.92 22.199 19.926 22.621 ;
     RECT  20.664 22.271 43.362 22.621 ;
     RECT  92.16 21.461 92.178 22.649 ;
     RECT  206.928 21.617 206.946 22.649 ;
     RECT  79.812 21.271 79.83 22.694 ;
     RECT  66.132 21.425 66.15 22.739 ;
     RECT  120.348 22.001 122.562 22.819 ;
     RECT  123.336 22.001 123.354 22.819 ;
     RECT  11.88 22.795 11.898 23.017 ;
     RECT  11.808 23.017 11.898 23.053 ;
     RECT  13.104 22.235 16.146 23.053 ;
     RECT  16.92 22.621 43.362 23.053 ;
     RECT  216.612 22.171 220.41 23.213 ;
     RECT  11.556 23.053 11.898 23.251 ;
     RECT  13.104 23.053 43.362 23.251 ;
     RECT  11.556 23.251 43.362 23.323 ;
     RECT  221.184 23.251 221.202 23.357 ;
     RECT  10.836 23.323 43.362 23.76 ;
     RECT  69.804 21.425 69.822 23.76 ;
     RECT  87.264 21.541 87.282 23.76 ;
     RECT  90.828 21.965 90.846 23.76 ;
     RECT  108.684 21.541 108.702 23.76 ;
     RECT  111.384 21.659 111.402 23.76 ;
     RECT  120.348 22.819 123.354 23.76 ;
     RECT  216.612 23.213 220.374 23.76 ;
     RECT  10.836 23.76 220.374 23.819 ;
     RECT  221.472 23.899 221.49 23.933 ;
     RECT  9.972 24.091 9.99 24.125 ;
     RECT  7.815 2.413 8.097 24.745 ;
     RECT  9.216 24.601 9.234 24.745 ;
     RECT  7.815 24.745 9.234 24.781 ;
     RECT  10.836 23.819 220.086 24.907 ;
     RECT  10.8 24.907 220.086 25.051 ;
     RECT  7.815 24.781 9.522 25.141 ;
     RECT  10.764 25.051 220.086 25.141 ;
     RECT  7.815 25.141 220.086 25.243 ;
     RECT  7.668 25.243 220.086 25.555 ;
     RECT  7.416 25.555 220.086 26.221 ;
     RECT  7.344 26.221 220.086 26.401 ;
     RECT  6.264 26.401 6.282 26.671 ;
     RECT  7.02 26.401 220.086 26.671 ;
     RECT  4.464 26.869 4.482 26.941 ;
     RECT  6.192 26.671 220.086 26.941 ;
     RECT  4.464 26.941 5.202 27.139 ;
     RECT  4.464 27.139 5.274 27.301 ;
     RECT  6.12 26.941 220.086 27.301 ;
     RECT  4.284 27.301 220.086 27.599 ;
     RECT  2.415 2.413 2.697 27.877 ;
     RECT  2.415 27.877 3.186 27.917 ;
     RECT  4.284 27.599 220.05 27.917 ;
     RECT  4.284 27.917 219.942 28.021 ;
     RECT  4.104 28.021 219.942 28.715 ;
     RECT  3.492 29.323 3.51 29.461 ;
     RECT  4.284 28.715 219.942 29.461 ;
     RECT  2.415 27.917 2.697 29.605 ;
     RECT  3.492 29.461 219.942 29.605 ;
     RECT  2.412 29.605 219.942 29.645 ;
     RECT  2.415 29.645 219.942 30.235 ;
     RECT  2.415 30.235 220.374 30.569 ;
     RECT  221.184 30.715 221.202 30.749 ;
     RECT  3.564 30.569 220.05 31.181 ;
     RECT  219.024 31.181 220.05 31.277 ;
     RECT  3.564 31.181 218.07 31.373 ;
     RECT  2.415 30.569 2.718 31.531 ;
     RECT  3.564 31.373 217.71 31.531 ;
     RECT  219.276 31.277 220.05 31.649 ;
     RECT  2.415 31.531 2.754 31.657 ;
     RECT  3.492 31.531 217.71 31.657 ;
     RECT  219.384 31.649 220.05 31.853 ;
     RECT  2.415 31.657 217.71 32.341 ;
     RECT  2.415 32.341 217.782 32.431 ;
     RECT  219.384 31.853 219.942 32.491 ;
     RECT  2.415 32.431 217.818 32.495 ;
     RECT  219.276 32.491 219.942 32.729 ;
     RECT  219.42 32.729 219.942 32.813 ;
     RECT  2.415 32.495 11.394 32.845 ;
     RECT  12.492 32.495 217.818 32.875 ;
     RECT  219.564 32.813 219.942 32.881 ;
     RECT  219.564 32.881 220.05 32.957 ;
     RECT  12.492 32.875 218.322 33.067 ;
     RECT  12.492 33.067 218.358 33.197 ;
     RECT  218.196 33.197 218.358 33.305 ;
     RECT  12.492 33.197 217.206 33.313 ;
     RECT  2.376 32.845 11.394 33.349 ;
     RECT  218.232 33.305 218.358 33.377 ;
     RECT  2.376 33.349 11.646 33.547 ;
     RECT  12.384 33.313 217.206 33.547 ;
     RECT  219.564 32.957 220.014 33.547 ;
     RECT  2.376 33.547 217.206 33.575 ;
     RECT  2.415 33.575 217.206 33.581 ;
     RECT  219.42 33.547 220.014 33.739 ;
     RECT  2.415 33.581 11.322 33.845 ;
     RECT  3.42 33.845 11.322 33.881 ;
     RECT  3.42 33.881 5.778 33.953 ;
     RECT  6.552 33.881 11.322 34.079 ;
     RECT  218.304 33.377 218.358 34.079 ;
     RECT  219.384 33.739 220.014 34.123 ;
     RECT  6.588 34.079 11.322 34.501 ;
     RECT  12.168 33.581 217.206 34.501 ;
     RECT  6.588 34.501 217.206 34.619 ;
     RECT  2.415 33.845 2.697 34.663 ;
     RECT  218.88 34.123 220.014 34.691 ;
     RECT  3.528 33.953 5.778 34.925 ;
     RECT  220.896 34.795 220.914 35.035 ;
     RECT  220.896 35.035 221.202 35.069 ;
     RECT  3.6 34.925 5.778 35.179 ;
     RECT  3.6 35.179 5.814 35.275 ;
     RECT  6.588 34.619 217.08 35.275 ;
     RECT  219.312 34.691 220.014 35.311 ;
     RECT  219.312 35.311 220.122 35.581 ;
     RECT  3.6 35.275 217.08 35.609 ;
     RECT  219.312 35.581 220.734 35.659 ;
     RECT  3.6 35.609 4.662 35.671 ;
     RECT  5.436 35.609 217.08 35.843 ;
     RECT  218.88 35.659 220.734 35.851 ;
     RECT  221.688 35.671 221.706 35.851 ;
     RECT  2.415 34.663 2.754 36.085 ;
     RECT  3.564 35.671 4.662 36.085 ;
     RECT  6.336 35.843 217.08 36.091 ;
     RECT  218.88 35.851 221.706 36.235 ;
     RECT  218.196 36.235 221.706 36.379 ;
     RECT  2.415 36.085 4.662 36.391 ;
     RECT  5.436 35.843 5.526 36.391 ;
     RECT  218.196 36.379 222.03 36.419 ;
     RECT  218.304 36.419 222.03 36.461 ;
     RECT  218.88 36.461 222.03 36.545 ;
     RECT  218.916 36.545 222.03 36.625 ;
     RECT  218.916 36.625 222.354 36.661 ;
     RECT  2.415 36.391 5.526 36.751 ;
     RECT  6.336 36.091 217.242 36.751 ;
     RECT  218.916 36.661 223.002 36.851 ;
     RECT  2.415 36.751 217.242 36.859 ;
     RECT  218.916 36.851 222.246 37.049 ;
     RECT  222.984 36.851 223.002 37.049 ;
     RECT  218.916 37.049 221.922 37.157 ;
     RECT  2.415 36.859 217.278 37.327 ;
     RECT  218.916 37.157 221.886 37.471 ;
     RECT  2.412 37.327 217.278 37.483 ;
     RECT  218.304 37.471 221.886 37.483 ;
     RECT  2.412 37.483 221.886 37.589 ;
     RECT  2.412 37.589 217.89 37.613 ;
     RECT  2.412 37.613 217.17 37.859 ;
     RECT  2.412 37.859 2.697 37.867 ;
     RECT  222.66 37.741 222.678 38.471 ;
     RECT  218.916 37.589 221.886 38.551 ;
     RECT  218.916 38.551 222.174 38.635 ;
     RECT  2.376 37.867 2.697 38.779 ;
     RECT  3.42 37.859 217.17 38.779 ;
     RECT  2.376 38.779 217.17 39.181 ;
     RECT  218.304 38.635 222.174 39.181 ;
     RECT  2.376 39.181 222.174 39.341 ;
     RECT  2.376 39.341 217.782 39.479 ;
     RECT  3.42 39.479 217.782 39.515 ;
     RECT  3.708 39.515 217.782 39.533 ;
     RECT  3.708 39.533 217.17 40.267 ;
     RECT  3.708 40.267 217.206 40.363 ;
     RECT  3.708 40.363 217.494 40.405 ;
     RECT  2.376 39.479 2.697 40.441 ;
     RECT  3.6 40.405 217.494 40.441 ;
     RECT  2.376 40.441 217.494 40.445 ;
     RECT  2.415 40.445 217.494 40.631 ;
     RECT  218.736 39.341 222.174 40.711 ;
     RECT  222.912 40.171 222.93 40.711 ;
     RECT  218.736 40.711 222.93 40.981 ;
     RECT  223.815 2.413 224.097 40.981 ;
     RECT  218.736 40.981 223.002 41.071 ;
     RECT  223.815 40.981 224.226 41.071 ;
     RECT  218.736 41.071 224.226 41.099 ;
     RECT  218.736 41.099 221.958 41.135 ;
     RECT  218.736 41.135 221.886 41.227 ;
     RECT  2.415 40.631 217.17 41.251 ;
     RECT  218.304 41.227 221.886 41.279 ;
     RECT  222.696 41.099 224.226 41.279 ;
     RECT  218.304 41.279 221.742 41.357 ;
     RECT  222.696 41.279 224.097 41.357 ;
     RECT  2.376 41.251 217.17 41.405 ;
     RECT  222.696 41.357 223.002 41.405 ;
     RECT  3.708 41.405 217.17 41.995 ;
     RECT  218.736 41.357 221.742 42.025 ;
     RECT  218.736 42.025 221.778 42.061 ;
     RECT  222.696 41.405 222.894 42.061 ;
     RECT  3.708 41.995 217.206 42.091 ;
     RECT  218.736 42.061 222.894 42.269 ;
     RECT  2.376 41.405 2.898 42.283 ;
     RECT  3.708 42.091 217.494 42.283 ;
     RECT  221.076 42.269 222.894 42.331 ;
     RECT  2.376 42.283 217.494 42.359 ;
     RECT  221.076 42.331 223.074 42.571 ;
     RECT  223.815 41.357 224.097 42.571 ;
     RECT  218.736 42.269 220.194 42.601 ;
     RECT  221.076 42.571 224.097 42.719 ;
     RECT  218.304 42.601 220.194 42.755 ;
     RECT  218.736 42.755 220.194 42.791 ;
     RECT  221.076 42.719 222.714 43.051 ;
     RECT  2.376 42.359 217.206 43.099 ;
     RECT  218.808 42.791 220.194 43.141 ;
     RECT  220.968 43.051 222.714 43.141 ;
     RECT  2.376 43.099 217.242 43.295 ;
     RECT  2.415 43.295 217.242 43.439 ;
     RECT  3.924 43.439 217.242 43.529 ;
     RECT  2.415 43.439 3.186 43.565 ;
     RECT  218.808 43.141 222.714 43.681 ;
     RECT  223.452 42.719 224.097 43.681 ;
     RECT  2.415 43.565 2.934 43.709 ;
     RECT  4.14 43.529 217.242 43.771 ;
     RECT  4.14 43.771 217.494 43.853 ;
     RECT  4.14 43.853 11.754 43.871 ;
     RECT  218.808 43.681 224.097 44.011 ;
     RECT  12.564 43.853 217.494 44.141 ;
     RECT  218.304 44.011 224.097 44.141 ;
     RECT  12.564 44.141 217.206 44.237 ;
     RECT  4.14 43.871 11.682 44.347 ;
     RECT  3.492 44.347 11.682 44.381 ;
     RECT  4.14 44.381 11.682 44.411 ;
     RECT  4.176 44.411 11.682 44.519 ;
     RECT  218.808 44.141 221.166 44.609 ;
     RECT  2.415 43.709 2.697 44.761 ;
     RECT  2.415 44.761 3.402 44.813 ;
     RECT  2.415 44.813 3.258 44.861 ;
     RECT  222.228 44.141 224.097 45.031 ;
     RECT  6.624 44.519 11.682 45.121 ;
     RECT  12.564 44.237 217.17 45.121 ;
     RECT  222.192 45.031 224.097 45.391 ;
     RECT  222.048 45.391 224.097 45.419 ;
     RECT  4.176 44.519 5.85 45.451 ;
     RECT  4.176 45.451 5.886 45.455 ;
     RECT  4.248 45.455 5.886 45.463 ;
     RECT  6.624 45.121 217.17 45.463 ;
     RECT  218.808 44.609 220.878 45.535 ;
     RECT  218.808 45.535 221.022 45.571 ;
     RECT  222.048 45.419 222.462 45.571 ;
     RECT  218.808 45.571 221.166 45.661 ;
     RECT  221.94 45.571 222.462 45.661 ;
     RECT  4.248 45.463 217.17 45.869 ;
     RECT  218.808 45.661 222.462 45.959 ;
     RECT  219.672 45.959 222.462 46.201 ;
     RECT  4.896 45.869 217.17 46.607 ;
     RECT  12.42 46.607 217.17 46.679 ;
     RECT  219.672 46.201 222.642 46.741 ;
     RECT  218.808 45.959 218.934 46.849 ;
     RECT  219.672 46.741 222.93 46.849 ;
     RECT  4.896 46.607 11.682 46.891 ;
     RECT  218.808 46.849 222.93 47.047 ;
     RECT  223.815 45.419 224.097 47.047 ;
     RECT  4.86 46.891 11.682 47.191 ;
     RECT  17.604 46.679 217.17 47.191 ;
     RECT  218.808 47.047 224.097 47.309 ;
     RECT  4.572 47.191 11.682 47.317 ;
     RECT  4.14 47.317 11.682 47.345 ;
     RECT  17.604 47.191 217.494 47.405 ;
     RECT  12.42 46.679 16.794 47.425 ;
     RECT  17.604 47.405 217.206 47.425 ;
     RECT  12.42 47.425 217.206 47.501 ;
     RECT  218.808 47.309 222.966 47.659 ;
     RECT  218.304 47.659 222.966 47.741 ;
     RECT  218.304 47.741 221.454 47.759 ;
     RECT  4.14 47.345 4.302 47.849 ;
     RECT  4.14 47.849 4.158 47.965 ;
     RECT  3.924 47.965 4.158 47.993 ;
     RECT  222.192 47.741 222.966 48.235 ;
     RECT  223.815 47.309 224.097 48.235 ;
     RECT  222.192 48.235 224.097 48.389 ;
     RECT  218.808 47.759 221.454 48.541 ;
     RECT  222.192 48.389 222.966 48.541 ;
     RECT  5.112 47.345 11.682 48.659 ;
     RECT  218.808 48.541 222.966 48.659 ;
     RECT  5.112 48.659 11.574 48.667 ;
     RECT  4.932 48.667 11.574 48.811 ;
     RECT  4.86 48.811 11.574 48.965 ;
     RECT  218.808 48.659 222.894 49.009 ;
     RECT  3.924 47.993 3.942 49.037 ;
     RECT  218.304 49.009 222.894 49.109 ;
     RECT  12.42 47.501 217.17 49.291 ;
     RECT  12.42 49.291 217.206 49.387 ;
     RECT  4.968 48.965 11.574 49.483 ;
     RECT  218.808 49.109 222.894 49.577 ;
     RECT  4.968 49.483 11.646 49.613 ;
     RECT  220.896 49.577 222.894 49.621 ;
     RECT  5.184 49.613 11.646 49.775 ;
     RECT  12.42 49.387 217.494 49.783 ;
     RECT  5.364 49.775 11.646 49.883 ;
     RECT  5.652 49.883 11.646 49.891 ;
     RECT  12.42 49.783 217.782 49.891 ;
     RECT  5.652 49.891 217.782 49.901 ;
     RECT  5.652 49.901 217.17 50.153 ;
     RECT  220.896 49.621 223.074 50.161 ;
     RECT  223.815 48.389 224.097 50.161 ;
     RECT  218.808 49.577 220.05 50.347 ;
     RECT  218.304 50.347 220.05 50.431 ;
     RECT  220.896 50.161 224.097 50.431 ;
     RECT  5.76 50.153 217.17 50.629 ;
     RECT  218.304 50.431 224.097 50.629 ;
     RECT  5.76 50.629 224.097 50.729 ;
     RECT  5.76 50.729 218.898 50.855 ;
     RECT  223.776 50.729 224.097 51.089 ;
     RECT  5.76 50.855 5.814 51.269 ;
     RECT  5.796 51.269 5.814 51.431 ;
     RECT  219.636 50.729 222.822 51.431 ;
     RECT  6.696 50.855 218.898 51.511 ;
     RECT  219.636 51.431 222.75 51.511 ;
     RECT  6.696 51.511 222.75 51.629 ;
     RECT  218.304 51.629 222.75 51.899 ;
     RECT  218.304 51.899 222.606 52.301 ;
     RECT  223.815 51.089 224.097 52.321 ;
     RECT  222.336 52.301 222.606 52.439 ;
     RECT  223.344 52.321 224.097 52.439 ;
     RECT  6.696 51.629 217.206 52.651 ;
     RECT  218.304 52.301 221.562 52.651 ;
     RECT  6.696 52.651 221.562 52.709 ;
     RECT  6.696 52.709 218.898 52.889 ;
     RECT  219.672 52.709 221.562 53.159 ;
     RECT  222.336 52.439 222.498 53.221 ;
     RECT  219.924 53.159 221.562 53.401 ;
     RECT  222.336 53.221 222.642 53.401 ;
     RECT  223.815 52.439 224.097 53.401 ;
     RECT  219.924 53.401 224.097 53.519 ;
     RECT  6.696 52.889 217.206 53.549 ;
     RECT  8.892 53.549 217.206 53.645 ;
     RECT  6.696 53.549 8.097 53.761 ;
     RECT  219.924 53.519 222.642 53.789 ;
     RECT  6.228 53.761 8.097 53.905 ;
     RECT  219.924 53.789 222.498 53.905 ;
     RECT  218.808 52.889 218.898 53.941 ;
     RECT  219.78 53.905 222.498 53.941 ;
     RECT  218.808 53.941 222.498 54.599 ;
     RECT  6.012 53.905 8.097 54.715 ;
     RECT  8.892 53.645 217.17 54.715 ;
     RECT  221.292 54.599 222.498 54.751 ;
     RECT  6.012 54.715 217.17 54.905 ;
     RECT  221.292 54.751 222.714 54.955 ;
     RECT  9 54.905 217.17 54.985 ;
     RECT  221.292 54.955 222.894 55.051 ;
     RECT  221.292 55.051 223.038 55.139 ;
     RECT  223.815 53.519 224.097 55.255 ;
     RECT  221.292 55.139 222.678 55.409 ;
     RECT  223.452 55.255 224.097 55.409 ;
     RECT  221.292 55.409 222.534 55.445 ;
     RECT  9 54.985 217.206 55.481 ;
     RECT  217.98 55.381 217.998 55.531 ;
     RECT  218.808 54.599 220.446 55.531 ;
     RECT  217.98 55.531 220.446 55.661 ;
     RECT  218.088 55.661 220.446 55.679 ;
     RECT  218.808 55.679 220.446 55.831 ;
     RECT  221.292 55.445 222.426 55.831 ;
     RECT  11.88 55.481 217.206 55.853 ;
     RECT  11.916 55.853 217.206 55.949 ;
     RECT  221.256 55.831 222.426 55.949 ;
     RECT  218.808 55.831 220.482 56.011 ;
     RECT  221.256 55.949 221.994 56.011 ;
     RECT  6.012 54.905 8.097 56.129 ;
     RECT  218.808 56.011 221.994 56.333 ;
     RECT  11.916 55.949 217.17 56.597 ;
     RECT  220.824 56.333 221.994 56.731 ;
     RECT  222.768 56.371 222.786 56.731 ;
     RECT  9 55.481 11.142 56.803 ;
     RECT  11.916 56.597 37.386 56.803 ;
     RECT  9 56.803 37.386 56.831 ;
     RECT  218.808 56.333 220.05 56.875 ;
     RECT  220.824 56.731 222.786 56.939 ;
     RECT  9 56.831 37.134 57.029 ;
     RECT  218.304 56.875 220.05 57.029 ;
     RECT  220.824 56.939 222.354 57.029 ;
     RECT  9 57.029 37.098 57.053 ;
     RECT  9 57.053 11.178 57.065 ;
     RECT  220.824 57.029 222.21 57.065 ;
     RECT  218.808 57.029 220.05 57.145 ;
     RECT  218.808 57.145 220.086 57.343 ;
     RECT  220.824 57.065 221.994 57.343 ;
     RECT  218.808 57.343 221.994 57.931 ;
     RECT  218.304 57.931 221.994 57.991 ;
     RECT  218.304 57.991 222.246 58.109 ;
     RECT  12.132 57.053 37.098 58.145 ;
     RECT  12.24 58.145 37.098 58.289 ;
     RECT  12.492 58.289 37.098 58.523 ;
     RECT  222.912 58.531 222.93 58.649 ;
     RECT  12.528 58.523 37.098 58.685 ;
     RECT  38.16 56.597 217.17 58.693 ;
     RECT  218.304 58.109 222.138 58.721 ;
     RECT  12.996 58.685 37.098 58.919 ;
     RECT  218.736 58.721 222.138 58.919 ;
     RECT  218.736 58.919 221.958 59.099 ;
     RECT  218.736 59.099 221.85 59.189 ;
     RECT  12.996 58.919 31.77 59.261 ;
     RECT  12.996 59.261 21.114 59.309 ;
     RECT  218.736 59.189 221.562 59.467 ;
     RECT  13.032 59.309 21.114 59.495 ;
     RECT  218.304 59.467 221.562 59.531 ;
     RECT  32.544 58.919 37.098 59.729 ;
     RECT  13.215 59.495 21.114 59.741 ;
     RECT  13.215 59.741 14.31 59.765 ;
     RECT  21.924 59.261 22.95 59.995 ;
     RECT  23.688 59.261 31.77 59.995 ;
     RECT  15.372 59.741 21.114 59.999 ;
     RECT  15.372 59.999 15.822 60.035 ;
     RECT  16.56 59.999 21.114 60.035 ;
     RECT  38.088 58.693 217.17 60.043 ;
     RECT  219.492 59.531 221.562 60.151 ;
     RECT  219.492 60.151 221.922 60.269 ;
     RECT  218.304 59.531 218.754 60.385 ;
     RECT  219.492 60.269 219.978 60.385 ;
     RECT  218.304 60.385 219.978 60.511 ;
     RECT  38.088 60.043 217.206 60.523 ;
     RECT  218.232 60.511 219.978 60.523 ;
     RECT  221.724 60.269 221.742 60.539 ;
     RECT  220.896 60.269 220.914 60.749 ;
     RECT  21.924 59.995 31.77 60.845 ;
     RECT  32.652 59.729 37.098 60.845 ;
     RECT  18.615 60.035 21.114 60.853 ;
     RECT  21.924 60.845 25.866 60.853 ;
     RECT  33.012 60.845 37.098 60.953 ;
     RECT  38.088 60.523 219.978 60.953 ;
     RECT  18.615 60.853 25.866 60.989 ;
     RECT  18.615 60.989 25.83 61.115 ;
     RECT  218.232 60.953 219.978 61.195 ;
     RECT  38.088 60.953 217.17 61.229 ;
     RECT  218.232 61.195 220.05 61.325 ;
     RECT  22.212 61.115 24.297 61.349 ;
     RECT  26.82 60.845 31.77 61.349 ;
     RECT  30.672 61.349 31.77 61.373 ;
     RECT  22.212 61.349 22.842 61.385 ;
     RECT  218.232 61.325 218.754 61.517 ;
     RECT  38.088 61.229 39.906 61.613 ;
     RECT  219.492 61.325 220.05 61.735 ;
     RECT  40.644 61.229 217.17 62.041 ;
     RECT  39.996 62.041 217.17 62.141 ;
     RECT  219.492 61.735 220.086 62.159 ;
     RECT  18.615 61.115 21.186 62.311 ;
     RECT  22.212 61.385 22.734 62.311 ;
     RECT  219.492 62.159 219.978 62.339 ;
     RECT  18.615 62.311 21.222 62.401 ;
     RECT  21.996 62.311 22.734 62.401 ;
     RECT  18.615 62.401 22.734 62.437 ;
     RECT  25.38 61.115 25.83 62.437 ;
     RECT  26.82 61.349 29.697 62.437 ;
     RECT  218.736 61.517 218.754 62.437 ;
     RECT  219.492 62.339 219.762 62.437 ;
     RECT  40.644 62.141 217.17 62.443 ;
     RECT  18.615 62.437 22.806 62.501 ;
     RECT  21.852 62.501 22.806 62.609 ;
     RECT  40.644 62.443 217.206 62.669 ;
     RECT  218.736 62.437 219.762 62.671 ;
     RECT  21.852 62.609 22.23 62.699 ;
     RECT  31.248 61.373 31.77 62.699 ;
     RECT  218.664 62.671 219.762 62.699 ;
     RECT  218.664 62.699 219.438 62.735 ;
     RECT  22.068 62.699 22.23 62.969 ;
     RECT  16.956 60.035 17.874 63.013 ;
     RECT  22.14 62.969 22.23 63.077 ;
     RECT  40.644 62.669 217.08 63.163 ;
     RECT  40.215 63.163 217.08 63.197 ;
     RECT  40.644 63.197 217.08 63.341 ;
     RECT  40.644 63.341 41.598 63.533 ;
     RECT  25.38 62.437 29.697 63.581 ;
     RECT  25.38 63.581 25.758 63.653 ;
     RECT  40.644 63.533 41.49 63.725 ;
     RECT  218.772 62.735 219.438 63.779 ;
     RECT  13.215 59.765 13.878 64.075 ;
     RECT  218.772 63.779 219.402 64.085 ;
     RECT  40.644 63.725 41.454 64.109 ;
     RECT  40.644 64.109 40.806 64.301 ;
     RECT  218.772 64.085 219.366 64.319 ;
     RECT  218.772 64.319 218.934 64.859 ;
     RECT  26.496 63.581 29.697 65.011 ;
     RECT  33.588 60.953 37.098 65.209 ;
     RECT  38.088 61.613 39.258 65.209 ;
     RECT  33.588 65.209 39.258 65.261 ;
     RECT  16.416 63.013 17.874 65.975 ;
     RECT  15.372 60.035 15.498 66.091 ;
     RECT  218.772 64.859 218.79 66.667 ;
     RECT  221.364 67.819 221.382 68.099 ;
     RECT  220.356 68.251 220.374 68.285 ;
     RECT  31.248 62.699 31.698 69.691 ;
     RECT  26.496 65.011 30.114 69.755 ;
     RECT  29.052 69.755 30.114 69.871 ;
     RECT  30.888 69.691 31.698 69.871 ;
     RECT  218.772 66.667 218.862 70.645 ;
     RECT  15.372 66.091 15.678 70.681 ;
     RECT  218.736 70.645 218.862 70.681 ;
     RECT  218.736 70.681 218.898 71.035 ;
     RECT  218.736 71.035 219.582 71.069 ;
     RECT  218.736 71.069 219.294 71.261 ;
     RECT  17.604 65.975 17.874 71.879 ;
     RECT  22.14 63.077 22.158 72.265 ;
     RECT  22.14 72.265 22.662 72.301 ;
     RECT  23.652 61.349 24.297 72.301 ;
     RECT  22.14 72.301 22.842 72.419 ;
     RECT  22.14 72.419 22.158 72.455 ;
     RECT  23.58 72.301 24.297 72.455 ;
     RECT  17.856 71.879 17.874 72.463 ;
     RECT  18.615 62.501 20.97 72.463 ;
     RECT  15.3 70.681 15.678 72.499 ;
     RECT  16.416 65.975 16.722 72.499 ;
     RECT  15.3 72.499 16.722 72.661 ;
     RECT  23.616 72.455 24.297 72.689 ;
     RECT  15.3 72.661 17.082 72.805 ;
     RECT  13.215 64.075 14.526 72.967 ;
     RECT  15.264 72.805 17.082 72.967 ;
     RECT  13.215 72.967 17.082 73.075 ;
     RECT  17.856 72.463 20.97 73.075 ;
     RECT  9 57.065 11.142 73.381 ;
     RECT  8.82 73.381 11.142 73.471 ;
     RECT  8.82 73.471 11.754 73.499 ;
     RECT  13.215 73.075 20.97 73.499 ;
     RECT  8.928 73.499 11.754 73.531 ;
     RECT  13.215 73.499 17.118 73.535 ;
     RECT  13.215 73.535 16.794 73.741 ;
     RECT  8.928 73.531 12.294 73.769 ;
     RECT  9.18 73.769 12.294 74.039 ;
     RECT  12.168 74.039 12.294 74.047 ;
     RECT  13.068 73.741 16.794 74.047 ;
     RECT  6.696 56.129 8.097 74.119 ;
     RECT  12.168 74.047 16.794 74.389 ;
     RECT  12.168 74.389 16.866 74.461 ;
     RECT  26.496 69.755 28.314 74.615 ;
     RECT  12.168 74.461 16.902 74.623 ;
     RECT  12.168 74.623 16.938 74.857 ;
     RECT  9.18 74.039 11.322 74.965 ;
     RECT  12.168 74.857 17.082 74.965 ;
     RECT  17.856 73.499 20.97 74.965 ;
     RECT  6.696 74.119 8.19 75.001 ;
     RECT  9.18 74.965 20.97 75.001 ;
     RECT  6.696 75.001 20.97 75.299 ;
     RECT  6.732 75.299 20.97 75.461 ;
     RECT  25.38 63.653 25.434 75.461 ;
     RECT  10.656 75.461 20.97 75.695 ;
     RECT  23.652 72.689 24.297 75.695 ;
     RECT  10.728 75.695 20.97 75.725 ;
     RECT  220.284 75.835 220.302 75.901 ;
     RECT  221.184 75.883 221.202 75.901 ;
     RECT  220.284 75.901 221.202 75.929 ;
     RECT  220.284 75.929 220.914 76.013 ;
     RECT  220.284 76.013 220.302 76.199 ;
     RECT  10.8 75.725 20.97 76.307 ;
     RECT  218.736 71.261 218.898 76.351 ;
     RECT  218.736 76.351 219.294 76.363 ;
     RECT  218.376 76.363 219.294 76.397 ;
     RECT  6.732 75.461 9.882 76.477 ;
     RECT  10.8 76.307 19.674 76.477 ;
     RECT  6.732 76.477 19.674 77.315 ;
     RECT  6.84 77.315 19.674 77.521 ;
     RECT  20.412 76.307 20.97 77.521 ;
     RECT  6.84 77.521 20.97 77.549 ;
     RECT  29.052 69.871 31.698 77.701 ;
     RECT  7.236 77.549 20.97 77.819 ;
     RECT  7.236 77.819 19.53 77.855 ;
     RECT  20.412 77.819 20.97 77.927 ;
     RECT  26.64 74.615 28.314 78.061 ;
     RECT  29.052 77.701 31.986 78.061 ;
     RECT  7.236 77.855 19.494 78.089 ;
     RECT  20.952 77.927 20.97 78.097 ;
     RECT  20.952 78.097 21.042 78.125 ;
     RECT  26.64 78.061 31.986 78.241 ;
     RECT  7.815 78.089 19.494 78.395 ;
     RECT  21.024 78.125 21.042 78.395 ;
     RECT  26.64 78.241 32.094 78.439 ;
     RECT  9.072 78.395 19.494 78.467 ;
     RECT  22.248 78.403 22.266 78.475 ;
     RECT  218.376 76.397 218.898 78.601 ;
     RECT  21.06 78.511 21.186 78.629 ;
     RECT  26.64 78.439 32.202 78.629 ;
     RECT  220.32 78.091 220.338 78.629 ;
     RECT  26.64 78.629 32.13 78.637 ;
     RECT  21.06 78.629 21.078 78.653 ;
     RECT  218.376 78.601 219.294 78.653 ;
     RECT  218.376 78.653 218.898 78.665 ;
     RECT  25.38 75.461 25.398 78.701 ;
     RECT  22.14 78.475 22.266 78.781 ;
     RECT  9.108 78.467 19.494 78.899 ;
     RECT  21.996 78.781 22.266 78.899 ;
     RECT  9.108 78.899 9.126 78.935 ;
     RECT  21.996 78.899 22.014 78.935 ;
     RECT  26.316 78.637 32.13 78.935 ;
     RECT  26.316 78.935 27.162 78.979 ;
     RECT  25.344 78.781 25.362 79.015 ;
     RECT  25.2 79.015 25.362 79.181 ;
     RECT  27.9 78.935 32.13 79.205 ;
     RECT  10.044 78.899 19.494 79.229 ;
     RECT  11.952 79.229 17.154 79.277 ;
     RECT  18.252 79.229 19.494 79.313 ;
     RECT  26.208 78.979 27.162 79.435 ;
     RECT  18.252 79.313 19.386 79.475 ;
     RECT  20.484 79.321 20.502 79.519 ;
     RECT  18.252 79.475 19.098 79.547 ;
     RECT  27.9 79.205 28.35 79.583 ;
     RECT  20.484 79.519 20.61 79.591 ;
     RECT  29.232 79.205 32.13 79.681 ;
     RECT  20.304 79.591 20.61 79.709 ;
     RECT  10.044 79.229 11.214 79.745 ;
     RECT  20.304 79.709 20.502 79.745 ;
     RECT  29.232 79.681 32.202 79.745 ;
     RECT  20.484 79.745 20.502 79.817 ;
     RECT  29.415 79.745 32.202 79.825 ;
     RECT  24.015 75.695 24.297 79.963 ;
     RECT  24.015 79.963 24.462 80.015 ;
     RECT  25.452 79.435 27.162 80.015 ;
     RECT  18.252 79.547 18.897 80.131 ;
     RECT  29.415 79.825 32.454 80.131 ;
     RECT  26.496 80.015 27.162 80.159 ;
     RECT  23.076 79.789 23.094 80.293 ;
     RECT  24.015 80.015 24.297 80.293 ;
     RECT  28.404 79.987 28.422 80.329 ;
     RECT  26.532 80.159 27.162 80.381 ;
     RECT  25.452 80.015 25.722 80.555 ;
     RECT  25.668 80.555 25.722 80.591 ;
     RECT  33.588 65.261 37.098 80.671 ;
     RECT  25.704 80.591 25.722 80.699 ;
     RECT  29.415 80.131 32.67 80.699 ;
     RECT  29.415 80.699 31.086 80.789 ;
     RECT  28.224 80.329 28.422 80.825 ;
     RECT  29.415 80.789 31.014 80.825 ;
     RECT  29.415 80.825 30.87 80.941 ;
     RECT  38.088 65.261 39.258 81.499 ;
     RECT  40.215 64.783 40.305 81.499 ;
     RECT  38.088 81.499 40.305 81.599 ;
     RECT  38.088 81.599 39.294 81.821 ;
     RECT  28.944 80.941 30.87 82.381 ;
     RECT  31.824 80.699 32.67 82.381 ;
     RECT  28.944 82.381 32.67 82.481 ;
     RECT  28.944 82.481 30.87 82.589 ;
     RECT  218.376 78.665 218.862 82.606 ;
     RECT  26.64 80.381 27.162 83.803 ;
     RECT  28.944 82.589 30.834 83.851 ;
     RECT  26.64 83.803 27.306 84.037 ;
     RECT  28.944 83.851 30.906 84.109 ;
     RECT  31.824 82.481 32.67 84.109 ;
     RECT  26.64 84.037 27.342 84.181 ;
     RECT  26.64 84.181 27.486 84.365 ;
     RECT  27.468 84.365 27.486 84.451 ;
     RECT  28.476 84.109 32.67 84.479 ;
     RECT  27.468 84.451 27.666 84.569 ;
     RECT  27.468 84.569 27.486 84.605 ;
     RECT  38.088 81.821 39.258 84.811 ;
     RECT  38.088 84.811 39.33 84.845 ;
     RECT  28.512 84.479 32.67 84.875 ;
     RECT  218.34 82.606 218.862 85.339 ;
     RECT  218.34 85.339 219.582 85.379 ;
     RECT  28.944 84.875 32.67 85.415 ;
     RECT  218.34 85.379 219.294 85.421 ;
     RECT  30.6 85.415 30.798 86.635 ;
     RECT  26.64 84.365 26.658 86.729 ;
     RECT  30.6 86.635 31.086 86.773 ;
     RECT  31.824 85.415 32.67 86.773 ;
     RECT  220.392 87.211 220.41 87.539 ;
     RECT  28.944 85.415 29.79 87.655 ;
     RECT  30.6 86.773 32.67 87.655 ;
     RECT  218.34 85.421 218.862 87.691 ;
     RECT  218.34 87.691 219.294 87.773 ;
     RECT  23.076 80.293 24.297 87.809 ;
     RECT  28.944 87.655 32.67 88.385 ;
     RECT  38.088 84.845 39.258 88.411 ;
     RECT  40.215 81.599 40.305 88.411 ;
     RECT  33.48 80.671 37.098 88.603 ;
     RECT  30.42 88.385 32.67 88.843 ;
     RECT  33.408 88.603 37.098 88.843 ;
     RECT  30.42 88.843 37.098 88.961 ;
     RECT  30.6 88.961 37.098 89.041 ;
     RECT  30.6 89.041 37.134 89.195 ;
     RECT  30.744 89.195 37.134 89.309 ;
     RECT  30.78 89.309 37.134 89.429 ;
     RECT  33.48 89.429 37.134 89.581 ;
     RECT  33.48 89.581 37.314 89.969 ;
     RECT  30.78 89.429 32.67 90.625 ;
     RECT  33.48 89.969 37.242 90.625 ;
     RECT  30.78 90.625 37.242 90.823 ;
     RECT  38.088 88.411 40.305 90.823 ;
     RECT  30.78 90.823 40.305 91.967 ;
     RECT  41.292 90.211 41.31 92.011 ;
     RECT  31.824 91.967 40.305 92.273 ;
     RECT  32.112 92.273 40.305 92.435 ;
     RECT  32.184 92.435 40.305 92.821 ;
     RECT  41.04 92.011 41.31 92.821 ;
     RECT  32.184 92.821 41.31 93.451 ;
     RECT  30.78 91.967 30.798 93.515 ;
     RECT  31.536 93.451 41.31 93.559 ;
     RECT  31.356 93.559 41.31 93.659 ;
     RECT  31.428 93.659 41.31 93.965 ;
     RECT  31.536 93.965 41.31 94.163 ;
     RECT  42.336 63.341 217.08 94.248 ;
     RECT  220.356 94.075 220.374 94.289 ;
     RECT  220.644 94.363 220.662 94.469 ;
     RECT  218.34 87.773 218.862 94.651 ;
     RECT  32.184 94.163 41.31 94.901 ;
     RECT  32.184 94.901 40.305 94.981 ;
     RECT  218.34 94.651 219.438 95.071 ;
     RECT  218.34 95.071 219.582 95.117 ;
     RECT  32.148 94.981 40.305 95.371 ;
     RECT  32.004 95.371 40.305 95.467 ;
     RECT  41.04 94.901 41.31 95.477 ;
     RECT  41.292 95.477 41.31 95.521 ;
     RECT  31.788 95.467 40.305 95.675 ;
     RECT  41.292 95.521 41.634 96.331 ;
     RECT  42.444 94.248 42.462 96.331 ;
     RECT  56.736 95.449 56.754 96.331 ;
     RECT  57.492 96.025 57.51 96.331 ;
     RECT  62.352 94.248 62.37 96.331 ;
     RECT  84.276 94.248 84.294 96.331 ;
     RECT  88.668 96.043 88.686 96.331 ;
     RECT  51.12 96.331 51.39 96.365 ;
     RECT  56.52 96.331 57.51 96.365 ;
     RECT  31.932 95.675 40.305 96.373 ;
     RECT  41.148 96.331 42.462 96.373 ;
     RECT  99.648 96.331 99.666 96.373 ;
     RECT  31.932 96.373 42.462 96.379 ;
     RECT  88.668 96.331 89.19 96.379 ;
     RECT  99.648 96.373 99.897 96.379 ;
     RECT  105.207 96.373 105.297 96.379 ;
     RECT  143.007 96.373 143.097 96.421 ;
     RECT  217.476 96.331 217.494 96.421 ;
     RECT  218.34 95.117 218.862 96.421 ;
     RECT  31.932 96.379 42.498 96.427 ;
     RECT  56.52 96.365 56.754 96.449 ;
     RECT  57.492 96.365 57.51 96.449 ;
     RECT  217.476 96.421 218.862 96.449 ;
     RECT  101.484 96.331 101.502 96.457 ;
     RECT  102.636 96.427 102.762 96.457 ;
     RECT  109.476 96.379 109.494 96.457 ;
     RECT  107.064 96.421 107.082 96.461 ;
     RECT  217.8 96.449 218.862 96.461 ;
     RECT  31.68 96.427 42.498 96.521 ;
     RECT  88.668 96.379 89.262 96.523 ;
     RECT  102.384 96.457 102.762 96.523 ;
     RECT  105.12 96.379 105.39 96.523 ;
     RECT  58.716 96.457 58.734 96.557 ;
     RECT  101.088 96.457 101.502 96.565 ;
     RECT  88.38 96.523 89.262 96.571 ;
     RECT  94.32 96.331 94.59 96.571 ;
     RECT  142.488 96.421 143.097 96.571 ;
     RECT  41.94 96.521 42.498 96.601 ;
     RECT  93.492 96.379 93.51 96.601 ;
     RECT  94.32 96.571 94.77 96.601 ;
     RECT  99.648 96.379 99.99 96.601 ;
     RECT  101.016 96.565 101.502 96.601 ;
     RECT  109.476 96.457 109.566 96.601 ;
     RECT  126.807 96.373 126.897 96.601 ;
     RECT  148.407 96.373 148.497 96.601 ;
     RECT  170.007 96.373 170.097 96.601 ;
     RECT  102.312 96.523 102.762 96.629 ;
     RECT  51.12 96.365 51.297 96.643 ;
     RECT  56.52 96.449 56.697 96.643 ;
     RECT  61.92 96.331 62.37 96.643 ;
     RECT  67.32 96.331 67.59 96.643 ;
     RECT  72.72 96.331 72.99 96.643 ;
     RECT  78.12 96.331 78.39 96.643 ;
     RECT  83.52 96.331 84.294 96.643 ;
     RECT  99.648 96.601 101.502 96.643 ;
     RECT  105.12 96.523 106.074 96.643 ;
     RECT  110.607 96.373 110.697 96.643 ;
     RECT  116.007 96.373 116.097 96.643 ;
     RECT  121.407 96.373 121.497 96.643 ;
     RECT  132.207 96.373 132.297 96.643 ;
     RECT  137.607 96.373 137.697 96.643 ;
     RECT  148.392 96.601 148.497 96.643 ;
     RECT  153.807 96.373 153.897 96.643 ;
     RECT  159.207 96.373 159.297 96.643 ;
     RECT  164.607 96.373 164.697 96.643 ;
     RECT  175.407 96.373 175.497 96.643 ;
     RECT  180.807 96.373 180.897 96.643 ;
     RECT  186.207 96.373 186.297 96.643 ;
     RECT  191.607 96.373 191.697 96.643 ;
     RECT  197.007 96.373 197.097 96.643 ;
     RECT  202.407 96.373 202.497 96.643 ;
     RECT  207.807 96.373 207.897 96.643 ;
     RECT  213.207 96.373 213.297 96.643 ;
     RECT  102.6 96.629 102.762 96.653 ;
     RECT  105.015 96.643 106.074 96.653 ;
     RECT  106.884 96.601 106.902 96.653 ;
     RECT  147.384 96.601 147.402 96.653 ;
     RECT  72.615 96.643 72.99 96.667 ;
     RECT  85.32 96.523 85.338 96.667 ;
     RECT  67.215 96.643 67.59 96.691 ;
     RECT  99.615 96.643 101.502 96.691 ;
     RECT  109.152 96.601 109.566 96.691 ;
     RECT  58.176 96.601 58.194 96.701 ;
     RECT  82.44 96.691 82.458 96.715 ;
     RECT  83.415 96.643 84.294 96.715 ;
     RECT  86.616 96.619 86.634 96.715 ;
     RECT  98.604 96.523 98.622 96.715 ;
     RECT  146.484 96.523 146.502 96.715 ;
     RECT  151.236 96.523 151.362 96.715 ;
     RECT  31.68 96.521 41.166 96.719 ;
     RECT  41.94 96.601 43.182 96.719 ;
     RECT  92.196 95.995 92.214 96.719 ;
     RECT  142.308 96.571 143.097 96.719 ;
     RECT  218.268 96.461 218.862 96.719 ;
     RECT  98.604 96.715 98.766 96.727 ;
     RECT  151.128 96.715 151.362 96.727 ;
     RECT  99.615 96.691 101.538 96.749 ;
     RECT  109.152 96.691 109.638 96.749 ;
     RECT  218.376 96.719 218.862 96.749 ;
     RECT  45.288 96.331 45.99 96.755 ;
     RECT  90.72 96.715 90.738 96.763 ;
     RECT  160.416 96.601 160.434 96.797 ;
     RECT  161.532 96.601 161.55 96.797 ;
     RECT  90.72 96.763 90.954 96.799 ;
     RECT  72.216 96.667 72.99 96.835 ;
     RECT  90.648 96.799 90.954 96.835 ;
     RECT  91.872 96.799 91.89 96.845 ;
     RECT  169.308 96.601 170.097 96.845 ;
     RECT  76.392 96.835 76.41 96.859 ;
     RECT  113.184 96.571 113.202 96.859 ;
     RECT  31.68 96.719 41.058 96.863 ;
     RECT  67.215 96.691 68.274 96.871 ;
     RECT  72.108 96.835 72.99 96.871 ;
     RECT  75.492 96.799 75.51 96.871 ;
     RECT  76.392 96.859 76.986 96.871 ;
     RECT  79.308 96.835 79.326 96.871 ;
     RECT  151.128 96.727 151.434 96.871 ;
     RECT  80.244 96.859 80.262 96.899 ;
     RECT  44.352 96.871 44.37 96.955 ;
     RECT  93.24 96.601 94.77 96.955 ;
     RECT  74.664 96.763 74.682 96.961 ;
     RECT  75.492 96.871 76.986 96.961 ;
     RECT  82.44 96.715 84.294 96.961 ;
     RECT  85.032 96.667 85.338 96.961 ;
     RECT  86.508 96.715 86.634 96.961 ;
     RECT  98.604 96.727 98.874 96.961 ;
     RECT  99.615 96.749 101.502 96.961 ;
     RECT  44.028 96.955 44.37 96.989 ;
     RECT  86.328 96.961 86.67 96.997 ;
     RECT  90.468 96.835 90.99 96.997 ;
     RECT  67.14 96.871 68.274 97.003 ;
     RECT  86.112 96.997 86.67 97.033 ;
     RECT  90.396 96.997 90.99 97.033 ;
     RECT  95.724 96.523 95.742 97.033 ;
     RECT  123.804 96.421 123.822 97.033 ;
     RECT  72.108 96.871 73.314 97.069 ;
     RECT  88.2 96.571 89.262 97.069 ;
     RECT  90.324 97.033 90.99 97.069 ;
     RECT  95.724 97.033 96.102 97.069 ;
     RECT  150.48 96.871 151.434 97.069 ;
     RECT  90.324 97.069 91.242 97.085 ;
     RECT  133.812 96.871 133.83 97.099 ;
     RECT  71.496 97.069 73.71 97.105 ;
     RECT  74.664 96.961 76.986 97.105 ;
     RECT  81.324 96.961 81.342 97.105 ;
     RECT  82.44 96.961 85.374 97.105 ;
     RECT  88.2 97.069 89.37 97.105 ;
     RECT  105.015 96.653 105.297 97.105 ;
     RECT  120.276 97.069 120.438 97.105 ;
     RECT  121.215 96.643 121.497 97.105 ;
     RECT  133.452 97.099 133.83 97.105 ;
     RECT  78.015 96.643 78.39 97.141 ;
     RECT  79.308 96.871 79.434 97.141 ;
     RECT  86.112 97.033 87.174 97.141 ;
     RECT  95.724 97.069 97.074 97.141 ;
     RECT  98.604 96.961 101.502 97.141 ;
     RECT  112.896 96.859 113.202 97.141 ;
     RECT  120.276 97.105 121.497 97.141 ;
     RECT  123.732 97.033 123.822 97.141 ;
     RECT  126.216 96.601 126.897 97.141 ;
     RECT  132.015 96.643 132.297 97.141 ;
     RECT  133.164 97.105 133.83 97.141 ;
     RECT  146.484 96.715 146.61 97.141 ;
     RECT  51.015 96.643 51.297 97.195 ;
     RECT  56.415 96.643 56.697 97.195 ;
     RECT  61.815 96.643 62.37 97.195 ;
     RECT  67.14 97.003 68.994 97.195 ;
     RECT  80.388 96.907 80.406 97.195 ;
     RECT  81.144 97.105 85.374 97.195 ;
     RECT  86.112 97.141 87.21 97.195 ;
     RECT  45.432 96.755 45.99 97.229 ;
     RECT  80.388 97.195 85.374 97.231 ;
     RECT  86.112 97.195 87.39 97.231 ;
     RECT  95.724 97.141 101.502 97.231 ;
     RECT  120.06 97.141 121.497 97.231 ;
     RECT  61.704 97.195 62.37 97.259 ;
     RECT  45.504 97.229 45.99 97.267 ;
     RECT  128.376 97.231 128.394 97.267 ;
     RECT  132.015 97.141 133.83 97.267 ;
     RECT  150.084 97.069 151.434 97.267 ;
     RECT  126 97.141 126.897 97.291 ;
     RECT  67.104 97.195 69.138 97.303 ;
     RECT  66.744 97.303 69.138 97.339 ;
     RECT  104.328 97.105 105.297 97.339 ;
     RECT  112.392 97.141 113.202 97.339 ;
     RECT  115.815 96.643 116.097 97.339 ;
     RECT  45.504 97.267 46.098 97.373 ;
     RECT  70.74 97.141 70.758 97.375 ;
     RECT  71.496 97.105 76.986 97.375 ;
     RECT  92.7 96.955 94.77 97.375 ;
     RECT  95.508 97.231 101.502 97.375 ;
     RECT  102.6 96.653 102.726 97.375 ;
     RECT  103.932 97.339 105.297 97.375 ;
     RECT  120.06 97.231 121.77 97.375 ;
     RECT  44.28 96.989 44.37 97.411 ;
     RECT  50.904 97.195 51.297 97.411 ;
     RECT  56.304 97.195 56.697 97.411 ;
     RECT  65.16 97.375 65.178 97.411 ;
     RECT  80.388 97.231 87.39 97.411 ;
     RECT  88.2 97.105 89.514 97.411 ;
     RECT  102.564 97.375 103.122 97.411 ;
     RECT  103.932 97.375 105.39 97.411 ;
     RECT  106.308 97.033 106.614 97.411 ;
     RECT  110.415 96.643 110.697 97.411 ;
     RECT  111.996 97.339 113.202 97.411 ;
     RECT  117.648 96.457 117.666 97.411 ;
     RECT  122.76 97.267 122.85 97.411 ;
     RECT  123.732 97.141 123.858 97.411 ;
     RECT  128.376 97.267 128.466 97.411 ;
     RECT  129.96 96.691 129.978 97.411 ;
     RECT  132.015 97.267 133.974 97.411 ;
     RECT  144.864 97.105 144.882 97.411 ;
     RECT  145.656 97.141 146.61 97.411 ;
     RECT  148.215 96.643 148.497 97.411 ;
     RECT  149.868 97.267 151.974 97.411 ;
     RECT  117.648 97.411 118.602 97.435 ;
     RECT  142.488 96.719 143.097 97.435 ;
     RECT  41.94 96.719 42.642 97.439 ;
     RECT  41.94 97.439 41.958 97.469 ;
     RECT  45.504 97.373 45.99 97.469 ;
     RECT  50.904 97.411 51.39 97.469 ;
     RECT  56.304 97.411 56.79 97.469 ;
     RECT  66.744 97.339 69.21 97.469 ;
     RECT  102.564 97.411 106.686 97.483 ;
     RECT  107.46 97.411 107.478 97.483 ;
     RECT  70.128 97.375 76.986 97.501 ;
     RECT  92.7 97.375 101.502 97.501 ;
     RECT  102.564 97.483 108.198 97.501 ;
     RECT  109.152 96.749 109.53 97.501 ;
     RECT  110.415 97.411 113.418 97.501 ;
     RECT  114.156 97.411 114.174 97.501 ;
     RECT  115.815 97.339 116.766 97.501 ;
     RECT  122.76 97.411 123.858 97.501 ;
     RECT  125.892 97.291 127.566 97.501 ;
     RECT  128.376 97.411 128.574 97.501 ;
     RECT  129.384 97.411 130.446 97.501 ;
     RECT  132.015 97.411 134.334 97.501 ;
     RECT  135.144 97.435 135.162 97.501 ;
     RECT  141.66 96.871 141.678 97.501 ;
     RECT  32.184 96.863 41.058 97.531 ;
     RECT  119.916 97.375 121.77 97.531 ;
     RECT  122.76 97.501 124.146 97.531 ;
     RECT  131.904 97.501 134.334 97.531 ;
     RECT  135.144 97.501 135.846 97.531 ;
     RECT  52.56 97.531 52.578 97.537 ;
     RECT  65.16 97.411 65.394 97.537 ;
     RECT  70.128 97.501 77.202 97.537 ;
     RECT  78.015 97.141 79.434 97.537 ;
     RECT  115.344 97.501 116.766 97.537 ;
     RECT  131.472 97.531 135.846 97.537 ;
     RECT  138.996 97.501 139.014 97.537 ;
     RECT  65.16 97.537 65.934 97.573 ;
     RECT  69.264 97.483 69.282 97.573 ;
     RECT  70.128 97.537 79.434 97.573 ;
     RECT  102.456 97.501 108.198 97.573 ;
     RECT  142.488 97.435 143.802 97.573 ;
     RECT  144.864 97.411 147.078 97.573 ;
     RECT  92.52 97.501 101.502 97.609 ;
     RECT  102.42 97.573 108.198 97.609 ;
     RECT  109.152 97.501 114.174 97.609 ;
     RECT  131.472 97.537 136.35 97.609 ;
     RECT  137.415 96.643 137.697 97.609 ;
     RECT  138.996 97.537 139.266 97.609 ;
     RECT  61.815 97.259 62.37 97.627 ;
     RECT  63.18 96.997 63.198 97.627 ;
     RECT  131.472 97.609 137.697 97.627 ;
     RECT  138.996 97.609 139.59 97.645 ;
     RECT  142.488 97.573 147.078 97.645 ;
     RECT  148.215 97.411 152.19 97.645 ;
     RECT  42.768 97.609 42.786 97.681 ;
     RECT  50.904 97.469 51.297 97.681 ;
     RECT  52.416 97.537 53.226 97.681 ;
     RECT  64.944 97.573 65.97 97.681 ;
     RECT  66.744 97.469 68.49 97.681 ;
     RECT  115.164 97.537 116.766 97.681 ;
     RECT  117.648 97.435 119.142 97.681 ;
     RECT  119.916 97.531 124.146 97.681 ;
     RECT  125.892 97.501 130.446 97.681 ;
     RECT  142.488 97.645 152.19 97.681 ;
     RECT  54.72 97.609 54.738 97.709 ;
     RECT  102.42 97.609 114.174 97.771 ;
     RECT  115.164 97.681 124.146 97.771 ;
     RECT  153.615 96.643 153.897 97.771 ;
     RECT  164.415 96.643 164.697 97.771 ;
     RECT  175.215 96.643 175.497 97.771 ;
     RECT  186.015 96.643 186.297 97.771 ;
     RECT  196.815 96.643 197.097 97.771 ;
     RECT  207.615 96.643 207.897 97.771 ;
     RECT  69.264 97.573 79.434 97.819 ;
     RECT  80.388 97.411 89.514 97.819 ;
     RECT  52.416 97.681 53.766 97.835 ;
     RECT  92.448 97.609 101.502 97.843 ;
     RECT  102.42 97.771 124.146 97.843 ;
     RECT  125.892 97.681 130.518 97.843 ;
     RECT  131.436 97.627 137.697 97.867 ;
     RECT  142.488 97.681 152.478 97.879 ;
     RECT  153.504 97.771 153.897 97.879 ;
     RECT  50.724 97.681 51.297 97.907 ;
     RECT  53.748 97.835 53.766 97.907 ;
     RECT  69.264 97.819 79.65 97.915 ;
     RECT  80.388 97.819 89.55 97.915 ;
     RECT  90.396 97.085 91.242 97.915 ;
     RECT  131.436 97.867 137.826 97.915 ;
     RECT  138.996 97.645 139.662 97.915 ;
     RECT  42.768 97.681 42.858 97.951 ;
     RECT  92.448 97.843 124.146 97.979 ;
     RECT  42.768 97.951 43.218 97.997 ;
     RECT  141.624 97.501 141.678 98.041 ;
     RECT  142.488 97.879 153.897 98.041 ;
     RECT  52.416 97.835 53.01 98.045 ;
     RECT  44.28 97.411 44.586 98.059 ;
     RECT  45.504 97.469 45.897 98.059 ;
     RECT  52.452 98.045 53.01 98.093 ;
     RECT  98.244 97.979 124.146 98.093 ;
     RECT  32.184 97.531 41.742 98.105 ;
     RECT  44.28 98.059 45.897 98.105 ;
     RECT  69.264 97.915 91.242 98.105 ;
     RECT  125.892 97.843 130.59 98.107 ;
     RECT  32.184 98.105 40.878 98.141 ;
     RECT  52.452 98.093 52.47 98.141 ;
     RECT  115.668 98.093 124.146 98.141 ;
     RECT  75.672 98.105 91.242 98.149 ;
     RECT  115.704 98.141 124.146 98.185 ;
     RECT  131.436 97.915 139.662 98.185 ;
     RECT  218.415 96.749 218.862 98.203 ;
     RECT  41.652 98.105 41.742 98.221 ;
     RECT  45.504 98.105 45.897 98.221 ;
     RECT  46.62 98.107 46.638 98.221 ;
     RECT  75.672 98.149 91.386 98.221 ;
     RECT  92.448 97.979 97.506 98.221 ;
     RECT  115.704 98.185 124.29 98.221 ;
     RECT  131.436 98.185 139.734 98.221 ;
     RECT  140.472 98.041 140.49 98.221 ;
     RECT  44.28 98.105 44.586 98.249 ;
     RECT  56.304 97.469 56.697 98.249 ;
     RECT  69.264 98.105 74.898 98.249 ;
     RECT  164.304 97.771 164.697 98.249 ;
     RECT  175.104 97.771 175.497 98.249 ;
     RECT  185.904 97.771 186.297 98.249 ;
     RECT  196.704 97.771 197.097 98.249 ;
     RECT  207.504 97.771 207.897 98.249 ;
     RECT  125.892 98.107 130.626 98.311 ;
     RECT  131.436 98.221 140.706 98.311 ;
     RECT  45.504 98.221 46.638 98.339 ;
     RECT  218.304 98.203 218.862 98.339 ;
     RECT  219.888 98.299 219.906 98.339 ;
     RECT  46.62 98.339 46.638 98.347 ;
     RECT  115.704 98.221 124.434 98.347 ;
     RECT  125.892 98.311 140.706 98.347 ;
     RECT  141.48 98.041 153.897 98.347 ;
     RECT  45.504 98.339 45.897 98.381 ;
     RECT  46.62 98.347 46.746 98.381 ;
     RECT  75.672 98.221 97.506 98.381 ;
     RECT  115.704 98.347 124.794 98.443 ;
     RECT  41.652 98.221 41.922 98.447 ;
     RECT  41.904 98.447 41.922 98.477 ;
     RECT  42.768 97.997 42.894 98.477 ;
     RECT  46.728 98.381 46.746 98.477 ;
     RECT  115.704 98.443 124.866 98.483 ;
     RECT  125.892 98.347 153.897 98.491 ;
     RECT  61.815 97.627 63.198 98.525 ;
     RECT  42.768 98.477 42.858 98.573 ;
     RECT  61.815 98.525 62.262 98.581 ;
     RECT  54.144 98.059 54.162 98.609 ;
     RECT  64.728 97.681 68.49 98.617 ;
     RECT  39.96 98.141 40.878 98.621 ;
     RECT  125.892 98.491 153.954 98.621 ;
     RECT  64.62 98.617 68.49 98.669 ;
     RECT  63.072 98.525 63.198 98.681 ;
     RECT  65.016 98.669 68.49 98.689 ;
     RECT  54.972 97.951 54.99 98.725 ;
     RECT  47.484 98.491 47.502 98.731 ;
     RECT  47.484 98.731 47.718 98.875 ;
     RECT  47.304 98.875 47.718 98.879 ;
     RECT  39.96 98.621 40.662 98.887 ;
     RECT  42.768 98.573 42.786 98.909 ;
     RECT  61.524 98.581 62.262 98.915 ;
     RECT  69.552 98.249 74.898 98.915 ;
     RECT  142.524 98.621 153.954 98.923 ;
     RECT  65.016 98.689 68.778 98.995 ;
     RECT  47.304 98.879 47.574 99.023 ;
     RECT  48.348 98.959 48.438 99.031 ;
     RECT  70.128 98.915 74.898 99.031 ;
     RECT  75.672 98.381 89.478 99.031 ;
     RECT  90.216 98.381 97.506 99.031 ;
     RECT  98.244 98.093 114.678 99.031 ;
     RECT  47.484 99.023 47.574 99.053 ;
     RECT  125.892 98.621 141.714 99.059 ;
     RECT  48.348 99.031 48.834 99.149 ;
     RECT  65.016 98.995 69.318 99.149 ;
     RECT  70.128 99.031 89.478 99.163 ;
     RECT  90.216 99.031 114.678 99.163 ;
     RECT  70.128 99.163 114.678 99.185 ;
     RECT  70.38 99.185 114.678 99.193 ;
     RECT  48.42 99.149 48.834 99.197 ;
     RECT  115.704 98.483 124.83 99.211 ;
     RECT  115.632 99.211 124.83 99.265 ;
     RECT  125.892 99.059 141.678 99.265 ;
     RECT  65.016 99.149 69.066 99.329 ;
     RECT  115.632 99.265 141.678 99.391 ;
     RECT  142.524 98.923 154.134 99.419 ;
     RECT  65.196 99.329 69.066 99.491 ;
     RECT  39.924 98.887 40.662 99.571 ;
     RECT  41.436 99.391 41.454 99.571 ;
     RECT  70.38 99.193 114.822 99.571 ;
     RECT  70.38 99.571 114.858 99.643 ;
     RECT  115.596 99.391 141.678 99.643 ;
     RECT  32.184 98.141 39.186 99.691 ;
     RECT  39.924 99.571 41.454 99.691 ;
     RECT  56.415 98.249 56.697 99.691 ;
     RECT  56.415 99.691 56.97 99.725 ;
     RECT  54.54 98.725 54.99 99.841 ;
     RECT  45.615 98.381 45.897 99.931 ;
     RECT  56.415 99.725 56.697 99.931 ;
     RECT  70.38 99.643 141.678 99.959 ;
     RECT  45.504 99.931 45.897 99.965 ;
     RECT  56.304 99.931 56.697 99.965 ;
     RECT  65.52 99.491 69.066 99.967 ;
     RECT  32.184 99.691 41.454 99.995 ;
     RECT  54.468 99.841 54.99 100.027 ;
     RECT  142.524 99.419 154.098 100.027 ;
     RECT  115.596 99.959 141.678 100.075 ;
     RECT  142.488 100.027 154.098 100.075 ;
     RECT  40.14 99.995 41.454 100.103 ;
     RECT  65.52 99.967 69.642 100.109 ;
     RECT  41.4 100.103 41.454 100.111 ;
     RECT  53.46 100.027 54.99 100.111 ;
     RECT  70.38 99.959 114.858 100.139 ;
     RECT  41.4 100.111 41.598 100.229 ;
     RECT  53.46 100.111 55.314 100.229 ;
     RECT  102.636 100.139 114.858 100.265 ;
     RECT  32.184 99.995 39.402 100.301 ;
     RECT  65.88 100.109 69.642 100.315 ;
     RECT  70.38 100.139 101.754 100.315 ;
     RECT  115.596 100.075 154.098 100.315 ;
     RECT  54.144 100.229 55.314 100.459 ;
     RECT  40.215 100.103 40.662 100.499 ;
     RECT  52.56 100.381 52.578 100.499 ;
     RECT  54.144 100.459 55.386 100.499 ;
     RECT  115.596 100.315 154.638 100.499 ;
     RECT  115.596 100.499 154.242 100.535 ;
     RECT  65.88 100.315 101.754 100.637 ;
     RECT  41.4 100.229 41.418 100.685 ;
     RECT  42.192 100.651 42.21 100.685 ;
     RECT  102.744 100.265 114.858 100.741 ;
     RECT  115.596 100.535 154.098 100.741 ;
     RECT  32.184 100.301 39.006 100.769 ;
     RECT  63.18 98.681 63.198 100.769 ;
     RECT  32.184 100.769 35.298 101.039 ;
     RECT  52.74 100.651 52.758 101.155 ;
     RECT  82.764 100.637 101.754 101.191 ;
     RECT  102.744 100.741 154.098 101.191 ;
     RECT  54.144 100.499 54.99 101.317 ;
     RECT  64.404 100.849 64.422 101.345 ;
     RECT  65.88 100.637 81.99 101.353 ;
     RECT  52.74 101.155 53.226 101.357 ;
     RECT  65.592 101.353 81.99 101.389 ;
     RECT  82.764 101.191 154.098 101.389 ;
     RECT  65.592 101.389 154.098 101.417 ;
     RECT  102.852 101.417 154.098 101.453 ;
     RECT  45.615 99.965 45.897 101.551 ;
     RECT  56.415 99.965 56.697 101.551 ;
     RECT  65.592 101.417 101.862 101.551 ;
     RECT  65.556 101.551 101.862 101.579 ;
     RECT  45.504 101.551 45.897 101.597 ;
     RECT  56.304 101.551 56.697 101.597 ;
     RECT  65.556 101.579 101.682 101.597 ;
     RECT  53.964 101.317 54.99 101.615 ;
     RECT  65.592 101.597 101.682 101.615 ;
     RECT  65.592 101.615 101.538 101.687 ;
     RECT  61.815 98.915 62.262 101.695 ;
     RECT  48.816 99.197 48.834 101.759 ;
     RECT  58.392 101.731 58.41 101.849 ;
     RECT  61.815 101.695 62.73 101.851 ;
     RECT  164.415 98.249 164.697 101.947 ;
     RECT  103.068 101.453 154.098 101.957 ;
     RECT  61.815 101.851 62.766 101.981 ;
     RECT  147.06 101.957 154.098 102.001 ;
     RECT  58.68 101.947 58.698 102.029 ;
     RECT  54.144 101.615 54.99 102.227 ;
     RECT  147.06 102.001 154.746 102.263 ;
     RECT  36.252 100.769 39.006 102.389 ;
     RECT  65.592 101.687 101.466 102.397 ;
     RECT  65.052 102.397 101.466 102.469 ;
     RECT  103.068 101.957 146.286 102.505 ;
     RECT  45.615 101.597 45.897 102.523 ;
     RECT  56.415 101.597 56.697 102.523 ;
     RECT  45.504 102.523 45.897 102.569 ;
     RECT  56.304 102.523 56.697 102.569 ;
     RECT  147.06 102.263 154.494 102.569 ;
     RECT  65.052 102.469 101.826 102.703 ;
     RECT  102.996 102.505 146.286 102.703 ;
     RECT  64.296 102.775 64.314 102.811 ;
     RECT  65.052 102.703 146.286 102.811 ;
     RECT  64.296 102.811 146.286 102.929 ;
     RECT  64.296 102.929 102.114 103.181 ;
     RECT  102.888 102.929 146.286 103.243 ;
     RECT  147.06 102.569 154.206 103.243 ;
     RECT  40.215 100.499 40.497 103.441 ;
     RECT  36.252 102.389 36.63 103.469 ;
     RECT  37.404 102.389 39.006 103.531 ;
     RECT  39.924 103.441 40.497 103.531 ;
     RECT  102.888 103.243 154.206 103.549 ;
     RECT  102.888 103.549 154.314 103.585 ;
     RECT  155.052 103.351 155.07 103.585 ;
     RECT  32.184 101.039 35.097 103.621 ;
     RECT  36.252 103.469 36.522 103.621 ;
     RECT  102.888 103.585 155.07 103.621 ;
     RECT  37.404 103.531 40.497 103.649 ;
     RECT  102.888 103.621 155.43 103.709 ;
     RECT  64.44 103.181 102.114 103.711 ;
     RECT  102.888 103.709 154.314 103.711 ;
     RECT  37.404 103.649 39.006 103.723 ;
     RECT  155.052 103.709 155.43 103.739 ;
     RECT  61.815 101.981 62.097 103.771 ;
     RECT  155.088 103.739 155.43 103.811 ;
     RECT  61.815 103.771 62.73 103.901 ;
     RECT  32.184 103.621 36.522 104.279 ;
     RECT  36.252 104.279 36.522 104.287 ;
     RECT  37.26 103.723 39.006 104.287 ;
     RECT  36.252 104.287 39.006 104.315 ;
     RECT  64.44 103.711 154.314 104.423 ;
     RECT  106.02 104.423 154.314 104.549 ;
     RECT  133.992 104.549 154.314 104.557 ;
     RECT  155.088 103.811 155.106 104.557 ;
     RECT  133.992 104.557 155.106 104.729 ;
     RECT  133.992 104.729 154.422 104.819 ;
     RECT  64.44 104.423 105.297 105.367 ;
     RECT  106.02 104.549 133.182 105.367 ;
     RECT  64.44 105.367 133.182 105.403 ;
     RECT  133.992 104.819 154.134 105.403 ;
     RECT  64.44 105.403 154.134 105.737 ;
     RECT  65.196 105.737 154.134 105.745 ;
     RECT  65.196 105.745 154.422 106.555 ;
     RECT  65.196 106.555 154.638 106.589 ;
     RECT  64.44 105.737 64.458 106.651 ;
     RECT  65.196 106.589 154.242 106.651 ;
     RECT  60.12 106.603 60.138 106.709 ;
     RECT  64.44 106.651 154.242 106.709 ;
     RECT  61.815 103.901 62.097 106.747 ;
     RECT  45.615 102.569 45.897 106.843 ;
     RECT  56.415 102.569 56.697 106.843 ;
     RECT  61.815 106.747 62.73 106.877 ;
     RECT  65.196 106.709 154.242 106.877 ;
     RECT  65.196 106.877 154.134 107.123 ;
     RECT  44.568 98.249 44.586 107.221 ;
     RECT  45.504 106.843 45.897 107.221 ;
     RECT  59.508 106.861 59.526 107.249 ;
     RECT  57.6 107.257 57.618 107.309 ;
     RECT  56.304 106.843 56.697 107.527 ;
     RECT  58.392 107.257 58.41 107.555 ;
     RECT  64.44 106.709 64.458 107.611 ;
     RECT  65.196 107.123 80.874 107.611 ;
     RECT  81.684 107.123 154.134 107.693 ;
     RECT  54.144 102.227 54.162 107.699 ;
     RECT  162.036 107.761 162.054 107.837 ;
     RECT  111.924 107.693 154.134 108.067 ;
     RECT  64.44 107.611 80.874 108.131 ;
     RECT  81.684 107.693 111.114 108.337 ;
     RECT  64.584 108.131 80.874 108.373 ;
     RECT  81.612 108.337 111.114 108.373 ;
     RECT  218.415 98.339 218.862 108.427 ;
     RECT  64.584 108.373 111.114 108.445 ;
     RECT  111.924 108.067 154.782 108.445 ;
     RECT  175.215 98.249 175.497 108.571 ;
     RECT  186.015 98.249 186.297 108.571 ;
     RECT  196.815 98.249 197.097 108.571 ;
     RECT  207.615 98.249 207.897 108.571 ;
     RECT  175.104 108.571 175.497 108.605 ;
     RECT  185.904 108.571 186.297 108.605 ;
     RECT  196.704 108.571 197.097 108.605 ;
     RECT  207.504 108.571 207.897 108.605 ;
     RECT  218.304 108.427 218.862 108.605 ;
     RECT  64.584 108.445 154.782 108.707 ;
     RECT  136.044 108.707 154.782 108.749 ;
     RECT  64.584 108.707 135.09 109.049 ;
     RECT  136.188 108.749 154.782 109.147 ;
     RECT  120.816 109.049 135.09 109.247 ;
     RECT  64.584 109.049 119.97 109.409 ;
     RECT  120.852 109.247 135.09 109.409 ;
     RECT  136.188 109.147 154.962 109.409 ;
     RECT  120.888 109.409 135.09 109.489 ;
     RECT  136.188 109.409 154.746 109.489 ;
     RECT  120.888 109.489 154.746 109.679 ;
     RECT  120.888 109.679 154.314 109.715 ;
     RECT  120.888 109.715 154.062 109.949 ;
     RECT  120.888 109.949 153.954 110.021 ;
     RECT  65.196 109.409 119.97 110.057 ;
     RECT  44.568 107.221 45.897 110.219 ;
     RECT  86.328 110.057 119.97 110.227 ;
     RECT  120.888 110.021 153.897 110.227 ;
     RECT  86.328 110.227 153.897 110.525 ;
     RECT  65.196 110.057 85.59 110.561 ;
     RECT  218.415 108.605 218.862 110.561 ;
     RECT  175.215 108.605 175.497 110.635 ;
     RECT  186.015 108.605 186.297 110.635 ;
     RECT  196.815 108.605 197.097 110.635 ;
     RECT  207.615 108.605 207.897 110.635 ;
     RECT  66.276 110.561 85.59 110.779 ;
     RECT  86.328 110.525 121.95 110.779 ;
     RECT  162.792 107.941 162.81 110.779 ;
     RECT  163.836 101.947 164.697 110.779 ;
     RECT  166.32 110.731 166.338 110.861 ;
     RECT  66.276 110.779 121.95 110.909 ;
     RECT  66.276 110.909 106.29 111.101 ;
     RECT  56.232 107.527 56.697 111.109 ;
     RECT  162.468 110.779 162.81 111.149 ;
     RECT  163.836 110.779 164.898 111.149 ;
     RECT  123.012 110.525 153.897 111.181 ;
     RECT  175.104 110.635 175.497 111.209 ;
     RECT  185.904 110.635 186.297 111.209 ;
     RECT  196.704 110.635 197.097 111.209 ;
     RECT  207.504 110.635 207.897 111.209 ;
     RECT  218.415 110.561 218.79 111.341 ;
     RECT  218.415 111.341 218.697 111.355 ;
     RECT  169.815 96.845 170.097 111.451 ;
     RECT  175.215 111.209 175.497 111.451 ;
     RECT  180.615 96.643 180.897 111.451 ;
     RECT  186.015 111.209 186.297 111.451 ;
     RECT  191.415 96.643 191.697 111.451 ;
     RECT  196.815 111.209 197.097 111.451 ;
     RECT  202.215 96.643 202.497 111.451 ;
     RECT  207.615 111.209 207.897 111.451 ;
     RECT  213.015 96.643 213.297 111.451 ;
     RECT  169.815 111.451 170.19 111.485 ;
     RECT  32.184 104.279 35.097 111.541 ;
     RECT  123.012 111.181 154.134 111.547 ;
     RECT  122.976 111.547 154.134 111.641 ;
     RECT  218.304 111.355 218.697 111.677 ;
     RECT  77.868 111.101 106.29 111.685 ;
     RECT  107.064 110.909 121.95 111.685 ;
     RECT  77.868 111.685 122.13 111.691 ;
     RECT  77.868 111.691 122.166 111.713 ;
     RECT  77.868 111.713 111.222 111.725 ;
     RECT  111.96 111.713 122.166 111.847 ;
     RECT  122.976 111.641 153.99 111.847 ;
     RECT  40.215 103.649 40.497 111.883 ;
     RECT  66.276 111.101 77.094 111.883 ;
     RECT  77.868 111.725 81.018 111.883 ;
     RECT  40.215 111.883 40.59 112.013 ;
     RECT  214.416 111.883 214.434 112.013 ;
     RECT  175.215 111.451 175.59 112.061 ;
     RECT  180.615 111.451 180.99 112.061 ;
     RECT  186.015 111.451 186.39 112.061 ;
     RECT  191.415 111.451 191.79 112.061 ;
     RECT  196.815 111.451 197.19 112.061 ;
     RECT  202.215 111.451 202.59 112.061 ;
     RECT  207.615 111.451 207.99 112.061 ;
     RECT  213.015 111.451 213.39 112.061 ;
     RECT  66.276 111.883 81.018 112.145 ;
     RECT  66.276 112.145 72.897 112.219 ;
     RECT  66.06 112.219 72.897 112.253 ;
     RECT  73.62 112.145 81.018 112.301 ;
     RECT  81.828 111.725 111.222 112.301 ;
     RECT  163.836 111.149 164.697 112.379 ;
     RECT  61.815 106.877 62.097 112.507 ;
     RECT  164.304 112.379 164.697 112.507 ;
     RECT  73.728 112.301 81.018 112.523 ;
     RECT  73.872 112.523 81.018 112.531 ;
     RECT  81.828 112.301 105.75 112.531 ;
     RECT  32.184 111.541 35.154 112.649 ;
     RECT  37.008 104.315 39.006 112.649 ;
     RECT  73.872 112.531 105.75 112.649 ;
     RECT  162.792 111.149 162.81 112.699 ;
     RECT  54.972 102.227 54.99 112.781 ;
     RECT  61.815 112.507 62.73 112.781 ;
     RECT  66.384 112.253 72.897 112.793 ;
     RECT  111.96 111.847 153.99 112.793 ;
     RECT  175.215 112.061 175.497 112.795 ;
     RECT  36.252 104.315 36.27 112.801 ;
     RECT  66.96 112.793 72.897 112.829 ;
     RECT  111.96 112.793 153.897 112.829 ;
     RECT  164.304 112.507 165.294 112.829 ;
     RECT  159.015 96.643 159.297 112.843 ;
     RECT  162.792 112.699 163.026 112.843 ;
     RECT  164.34 112.829 165.294 112.843 ;
     RECT  169.815 111.485 170.097 112.843 ;
     RECT  173.484 112.651 173.502 112.843 ;
     RECT  186.015 112.061 186.297 112.891 ;
     RECT  196.815 112.061 197.097 112.891 ;
     RECT  207.615 112.061 207.897 112.891 ;
     RECT  218.415 111.677 218.697 112.891 ;
     RECT  23.616 87.809 24.297 112.919 ;
     RECT  35.928 112.801 36.486 112.919 ;
     RECT  173.484 112.843 174.15 112.919 ;
     RECT  164.34 112.843 165.942 112.927 ;
     RECT  167.976 112.843 167.994 112.927 ;
     RECT  161.748 112.843 161.766 112.939 ;
     RECT  168.984 112.843 170.097 112.939 ;
     RECT  66.996 112.829 72.897 112.955 ;
     RECT  106.488 112.301 111.222 112.963 ;
     RECT  111.96 112.829 121.842 112.963 ;
     RECT  168.984 112.939 170.406 112.987 ;
     RECT  32.184 112.649 35.097 113.035 ;
     RECT  162.504 112.843 163.026 113.035 ;
     RECT  161.388 112.939 161.766 113.071 ;
     RECT  164.34 112.927 166.302 113.071 ;
     RECT  168.984 112.987 170.982 113.071 ;
     RECT  185.904 112.891 186.297 113.131 ;
     RECT  164.34 113.071 166.41 113.179 ;
     RECT  37.62 112.649 39.006 113.189 ;
     RECT  122.724 112.829 152.802 113.189 ;
     RECT  122.724 113.189 152.586 113.225 ;
     RECT  73.908 112.649 105.75 113.227 ;
     RECT  106.488 112.963 121.842 113.227 ;
     RECT  168.984 113.071 171.018 113.227 ;
     RECT  161.172 113.071 161.766 113.269 ;
     RECT  162.504 113.035 163.566 113.269 ;
     RECT  164.34 113.179 166.734 113.269 ;
     RECT  167.58 112.927 167.994 113.269 ;
     RECT  168.804 113.227 171.018 113.269 ;
     RECT  73.908 113.227 121.842 113.333 ;
     RECT  122.724 113.225 151.938 113.333 ;
     RECT  173.844 112.919 174.15 113.341 ;
     RECT  175.104 112.795 175.497 113.341 ;
     RECT  67.104 112.955 72.897 113.357 ;
     RECT  77.832 113.333 121.842 113.357 ;
     RECT  122.868 113.333 151.938 113.369 ;
     RECT  161.172 113.269 163.566 113.419 ;
     RECT  180.615 112.061 180.897 113.419 ;
     RECT  191.415 112.061 191.697 113.419 ;
     RECT  202.215 112.061 202.497 113.419 ;
     RECT  213.015 112.061 213.297 113.419 ;
     RECT  38.304 113.189 39.006 113.459 ;
     RECT  133.956 113.369 151.938 113.459 ;
     RECT  160.776 113.419 163.566 113.459 ;
     RECT  180.504 113.419 180.897 113.459 ;
     RECT  191.304 113.419 191.697 113.459 ;
     RECT  196.704 112.891 197.097 113.459 ;
     RECT  202.104 113.419 202.497 113.459 ;
     RECT  207.504 112.891 207.897 113.459 ;
     RECT  212.904 113.419 213.297 113.459 ;
     RECT  67.215 113.357 72.897 113.467 ;
     RECT  73.908 113.333 76.878 113.467 ;
     RECT  10.476 79.745 11.214 113.495 ;
     RECT  11.952 79.277 16.614 113.495 ;
     RECT  38.988 113.459 39.006 113.495 ;
     RECT  77.868 113.357 121.842 113.495 ;
     RECT  133.956 113.459 151.722 113.495 ;
     RECT  161.172 113.459 163.566 113.495 ;
     RECT  67.215 113.467 73.026 113.503 ;
     RECT  73.764 113.467 76.878 113.503 ;
     RECT  173.844 113.341 175.497 113.503 ;
     RECT  178.488 113.431 178.506 113.503 ;
     RECT  180.615 113.459 180.897 113.503 ;
     RECT  182.52 113.227 182.538 113.503 ;
     RECT  184.932 113.431 184.95 113.539 ;
     RECT  185.904 113.131 186.426 113.575 ;
     RECT  187.668 113.431 187.686 113.575 ;
     RECT  161.28 113.495 163.566 113.611 ;
     RECT  164.34 113.269 167.994 113.611 ;
     RECT  107.82 113.495 121.842 113.645 ;
     RECT  118.224 113.645 121.842 113.701 ;
     RECT  36.108 112.919 36.486 113.729 ;
     RECT  67.215 113.503 76.878 113.729 ;
     RECT  77.868 113.495 107.046 113.729 ;
     RECT  182.52 113.503 182.862 113.729 ;
     RECT  182.52 113.729 182.79 113.737 ;
     RECT  10.692 113.495 11.106 113.765 ;
     RECT  18 80.131 18.897 113.765 ;
     RECT  161.28 113.611 168.066 113.765 ;
     RECT  168.804 113.269 171.162 113.765 ;
     RECT  173.844 113.503 175.554 113.765 ;
     RECT  184.86 113.539 184.95 113.773 ;
     RECT  185.904 113.575 187.686 113.773 ;
     RECT  77.976 113.729 85.374 113.789 ;
     RECT  162.288 113.765 168.066 113.789 ;
     RECT  86.148 113.729 107.046 113.801 ;
     RECT  173.88 113.765 175.554 113.801 ;
     RECT  172.008 113.611 172.098 113.809 ;
     RECT  184.86 113.773 187.686 113.809 ;
     RECT  11.952 113.495 16.254 113.837 ;
     RECT  86.148 113.801 106.002 113.837 ;
     RECT  161.28 113.765 161.478 113.837 ;
     RECT  162.72 113.789 168.066 113.837 ;
     RECT  178.416 113.503 178.506 113.837 ;
     RECT  218.304 112.891 218.697 113.837 ;
     RECT  28.944 88.385 29.697 113.845 ;
     RECT  159.015 112.843 159.354 113.845 ;
     RECT  10.692 113.765 10.71 113.873 ;
     RECT  90.936 113.837 106.002 113.873 ;
     RECT  106.776 113.801 107.046 113.873 ;
     RECT  107.82 113.645 117.126 113.873 ;
     RECT  31.68 113.035 35.097 113.881 ;
     RECT  172.008 113.809 172.206 113.881 ;
     RECT  180.615 113.503 180.954 113.881 ;
     RECT  181.836 113.737 182.79 113.881 ;
     RECT  77.976 113.789 85.014 113.909 ;
     RECT  107.82 113.873 116.802 113.909 ;
     RECT  178.488 113.837 178.506 113.909 ;
     RECT  184.14 113.809 187.686 113.971 ;
     RECT  122.868 113.369 132.93 113.981 ;
     RECT  28.944 113.845 30.222 113.999 ;
     RECT  36.468 113.729 36.486 113.999 ;
     RECT  56.016 111.109 56.697 113.999 ;
     RECT  67.215 113.729 75.726 113.999 ;
     RECT  78.015 113.909 85.014 113.999 ;
     RECT  86.148 113.837 90.162 113.999 ;
     RECT  90.936 113.873 105.822 113.999 ;
     RECT  107.82 113.909 116.766 113.999 ;
     RECT  133.956 113.495 151.506 113.999 ;
     RECT  162.72 113.837 167.922 113.999 ;
     RECT  180.615 113.881 182.79 113.999 ;
     RECT  28.944 113.999 29.697 114.035 ;
     RECT  67.215 113.999 74.358 114.035 ;
     RECT  80.316 113.999 80.442 114.035 ;
     RECT  81.252 113.999 81.27 114.035 ;
     RECT  86.724 113.999 90.162 114.035 ;
     RECT  92.664 113.999 105.642 114.035 ;
     RECT  107.82 113.999 111.762 114.035 ;
     RECT  112.716 113.999 116.766 114.035 ;
     RECT  142.524 113.999 148.497 114.035 ;
     RECT  162.72 113.999 164.697 114.035 ;
     RECT  165.456 113.999 167.922 114.035 ;
     RECT  169.815 113.765 171.018 114.035 ;
     RECT  78.015 113.999 79.578 114.071 ;
     RECT  82.116 113.999 84.978 114.071 ;
     RECT  111.744 114.035 111.762 114.071 ;
     RECT  118.224 113.701 121.986 114.071 ;
     RECT  67.215 114.035 73.926 114.077 ;
     RECT  88.704 114.035 90.162 114.077 ;
     RECT  107.028 113.873 107.046 114.077 ;
     RECT  112.716 114.035 116.514 114.107 ;
     RECT  118.224 114.071 118.602 114.107 ;
     RECT  159.015 113.845 159.39 114.115 ;
     RECT  134.028 113.999 141.786 114.125 ;
     RECT  142.524 114.035 147.258 114.125 ;
     RECT  103.14 114.035 105.642 114.143 ;
     RECT  31.68 113.881 35.154 114.151 ;
     RECT  82.116 114.071 83.697 114.173 ;
     RECT  88.704 114.077 90.018 114.173 ;
     RECT  134.028 114.125 134.226 114.173 ;
     RECT  214.416 114.043 214.434 114.173 ;
     RECT  67.215 114.077 73.566 114.179 ;
     RECT  84.42 114.071 84.978 114.179 ;
     RECT  123.804 113.981 132.93 114.187 ;
     RECT  184.14 113.971 188.046 114.221 ;
     RECT  2.415 44.861 2.697 114.227 ;
     RECT  7.815 78.395 8.097 114.227 ;
     RECT  18.615 113.765 18.897 114.227 ;
     RECT  24.015 112.919 24.297 114.227 ;
     RECT  29.304 114.035 29.697 114.227 ;
     RECT  40.215 112.013 40.497 114.227 ;
     RECT  45.615 110.219 45.897 114.227 ;
     RECT  51.015 97.907 51.297 114.227 ;
     RECT  56.304 113.999 56.697 114.227 ;
     RECT  61.815 112.781 62.097 114.227 ;
     RECT  67.215 114.179 71.046 114.227 ;
     RECT  83.268 114.173 83.697 114.227 ;
     RECT  112.716 114.107 116.097 114.227 ;
     RECT  148.215 114.035 148.497 114.227 ;
     RECT  153.615 112.829 153.897 114.227 ;
     RECT  163.62 114.035 164.697 114.227 ;
     RECT  184.14 114.221 186.297 114.227 ;
     RECT  191.415 113.459 191.697 114.227 ;
     RECT  196.815 113.459 197.097 114.227 ;
     RECT  202.215 113.459 202.497 114.227 ;
     RECT  207.615 113.459 207.897 114.227 ;
     RECT  213.015 113.459 213.297 114.227 ;
     RECT  218.415 113.837 218.697 114.227 ;
     RECT  223.815 55.409 224.097 114.227 ;
     RECT  229.215 2.413 229.497 114.227 ;
     RECT  234.615 2.413 234.897 114.227 ;
     RECT  240.015 2.413 240.297 114.227 ;
     RECT  245.415 2.413 245.697 114.227 ;
     RECT  250.815 2.413 251.097 114.227 ;
     RECT  256.215 2.413 256.497 114.227 ;
     RECT  150.552 113.999 151.506 114.241 ;
     RECT  31.68 114.151 35.226 114.269 ;
     RECT  68.04 114.227 71.046 114.269 ;
     RECT  72.144 114.179 73.458 114.269 ;
     RECT  75.132 113.999 75.726 114.269 ;
     RECT  78.015 114.071 79.542 114.269 ;
     RECT  80.316 114.035 80.37 114.269 ;
     RECT  82.116 114.173 82.314 114.269 ;
     RECT  92.664 114.035 102.402 114.269 ;
     RECT  103.14 114.143 105.606 114.269 ;
     RECT  110.268 114.035 110.898 114.269 ;
     RECT  112.716 114.227 115.905 114.269 ;
     RECT  119.556 114.071 121.986 114.269 ;
     RECT  123.804 114.187 133.182 114.269 ;
     RECT  134.064 114.173 134.226 114.269 ;
     RECT  135 114.125 141.786 114.269 ;
     RECT  142.815 114.125 147.258 114.269 ;
     RECT  150.552 114.241 151.578 114.269 ;
     RECT  158.472 114.115 159.39 114.269 ;
     RECT  162.72 114.035 162.846 114.269 ;
     RECT  168.804 113.765 168.966 114.269 ;
     RECT  180.615 113.999 182.502 114.269 ;
     RECT  172.008 113.881 172.746 114.277 ;
     RECT  12.348 113.837 16.254 114.305 ;
     RECT  69.084 114.269 69.102 114.305 ;
     RECT  70.092 114.269 70.83 114.305 ;
     RECT  82.116 114.269 82.134 114.305 ;
     RECT  83.268 114.227 83.505 114.305 ;
     RECT  86.724 114.035 87.642 114.305 ;
     RECT  92.808 114.269 102.222 114.305 ;
     RECT  103.32 114.269 103.338 114.305 ;
     RECT  108.036 114.035 109.026 114.305 ;
     RECT  119.556 114.269 119.61 114.305 ;
     RECT  134.064 114.269 134.082 114.305 ;
     RECT  135.468 114.269 141.246 114.305 ;
     RECT  155.448 114.151 155.466 114.305 ;
     RECT  159.015 114.269 159.39 114.305 ;
     RECT  161.46 113.837 161.478 114.305 ;
     RECT  165.456 114.035 167.022 114.305 ;
     RECT  167.832 114.035 167.922 114.305 ;
     RECT  72.612 114.269 72.705 114.317 ;
     RECT  84.924 114.179 84.978 114.317 ;
     RECT  120.852 114.269 121.986 114.317 ;
     RECT  122.868 113.981 123.066 114.317 ;
     RECT  75.276 114.269 75.726 114.341 ;
     RECT  108.684 114.305 109.026 114.341 ;
     RECT  112.788 114.269 113.922 114.341 ;
     RECT  67.215 114.227 67.305 114.349 ;
     RECT  168.804 114.269 168.894 114.349 ;
     RECT  70.092 114.305 70.722 114.365 ;
     RECT  73.44 114.269 73.458 114.365 ;
     RECT  86.724 114.305 86.742 114.377 ;
     RECT  91.044 113.999 91.926 114.377 ;
     RECT  92.808 114.305 98.046 114.377 ;
     RECT  119.556 114.305 119.574 114.377 ;
     RECT  123.804 114.269 132.93 114.377 ;
     RECT  136.224 114.305 140.058 114.377 ;
     RECT  121.104 114.317 121.986 114.385 ;
     RECT  184.14 114.227 186.105 114.385 ;
     RECT  92.808 114.377 95.49 114.413 ;
     RECT  96.336 114.377 98.046 114.413 ;
     RECT  104.22 114.269 105.105 114.413 ;
     RECT  113.544 114.341 113.922 114.413 ;
     RECT  123.804 114.377 131.022 114.413 ;
     RECT  131.796 114.377 132.93 114.413 ;
     RECT  136.224 114.377 139.05 114.413 ;
     RECT  139.824 114.377 140.058 114.413 ;
     RECT  142.815 114.269 146.61 114.413 ;
     RECT  174.42 113.801 175.554 114.413 ;
     RECT  184.104 114.385 186.105 114.421 ;
     RECT  66.708 114.349 67.305 114.449 ;
     RECT  75.348 114.341 75.726 114.449 ;
     RECT  78.015 114.269 78.678 114.449 ;
     RECT  80.352 114.269 80.37 114.449 ;
     RECT  84.924 114.317 84.942 114.449 ;
     RECT  88.704 114.173 89.73 114.449 ;
     RECT  91.584 114.377 91.926 114.449 ;
     RECT  92.808 114.413 94.842 114.449 ;
     RECT  96.336 114.413 96.354 114.449 ;
     RECT  109.008 114.341 109.026 114.449 ;
     RECT  118.584 114.107 118.602 114.449 ;
     RECT  123.912 114.413 128.898 114.449 ;
     RECT  129.816 114.413 131.022 114.449 ;
     RECT  136.764 114.413 139.05 114.449 ;
     RECT  143.892 114.413 146.61 114.449 ;
     RECT  151.524 114.269 151.578 114.449 ;
     RECT  98.892 114.305 102.222 114.461 ;
     RECT  123.912 114.449 128.79 114.461 ;
     RECT  131.796 114.413 132.426 114.461 ;
     RECT  136.872 114.449 138.546 114.461 ;
     RECT  139.86 114.413 140.058 114.461 ;
     RECT  2.415 114.227 2.505 114.497 ;
     RECT  7.815 114.227 7.905 114.497 ;
     RECT  18.615 114.227 18.705 114.497 ;
     RECT  24.015 114.227 24.105 114.497 ;
     RECT  29.304 114.227 29.505 114.497 ;
     RECT  40.215 114.227 40.305 114.497 ;
     RECT  51.015 114.227 51.105 114.497 ;
     RECT  61.815 114.227 61.905 114.497 ;
     RECT  67.215 114.449 67.305 114.497 ;
     RECT  72.615 114.317 72.705 114.497 ;
     RECT  78.015 114.449 78.105 114.497 ;
     RECT  83.415 114.305 83.505 114.497 ;
     RECT  92.808 114.449 94.305 114.497 ;
     RECT  105.015 114.413 105.105 114.497 ;
     RECT  115.596 114.269 115.905 114.497 ;
     RECT  131.796 114.461 132.105 114.497 ;
     RECT  142.815 114.413 142.905 114.497 ;
     RECT  148.215 114.227 148.305 114.497 ;
     RECT  159.015 114.305 159.105 114.497 ;
     RECT  169.815 114.035 170.586 114.497 ;
     RECT  180.615 114.269 181.422 114.497 ;
     RECT  183.564 114.421 186.105 114.497 ;
     RECT  191.415 114.227 191.505 114.497 ;
     RECT  196.815 114.227 196.905 114.497 ;
     RECT  202.215 114.227 202.305 114.497 ;
     RECT  207.615 114.227 207.705 114.497 ;
     RECT  213.015 114.227 213.105 114.497 ;
     RECT  218.415 114.227 218.505 114.497 ;
     RECT  223.815 114.227 223.905 114.497 ;
     RECT  229.215 114.227 229.305 114.497 ;
     RECT  234.615 114.227 234.705 114.497 ;
     RECT  240.015 114.227 240.105 114.497 ;
     RECT  245.415 114.227 245.505 114.497 ;
     RECT  250.815 114.227 250.905 114.497 ;
     RECT  256.215 114.227 256.305 114.497 ;
     RECT  12.924 114.305 15.786 114.509 ;
     RECT  98.892 114.461 100.494 114.509 ;
     RECT  102.204 114.461 102.222 114.509 ;
     RECT  137.052 114.461 138.546 114.509 ;
     RECT  140.976 114.305 141.246 114.509 ;
     RECT  180.792 114.497 181.422 114.509 ;
     RECT  45.615 114.227 45.81 114.511 ;
     RECT  153.615 114.227 153.81 114.511 ;
     RECT  87.624 114.305 87.642 114.539 ;
     RECT  92.808 114.497 93.51 114.539 ;
     RECT  97.344 114.413 98.046 114.539 ;
     RECT  98.928 114.509 99.954 114.539 ;
     RECT  110.304 114.269 110.754 114.539 ;
     RECT  115.596 114.497 115.614 114.539 ;
     RECT  121.104 114.385 122.418 114.539 ;
     RECT  137.88 114.509 138.546 114.539 ;
     RECT  141.228 114.509 141.246 114.539 ;
     RECT  146.592 114.449 146.61 114.539 ;
     RECT  151.56 114.449 151.578 114.539 ;
     RECT  166.644 114.305 167.022 114.539 ;
     RECT  170.388 114.497 170.586 114.539 ;
     RECT  171.972 114.277 172.746 114.539 ;
     RECT  174.42 114.413 175.482 114.539 ;
     RECT  13.104 114.509 15.786 114.557 ;
     RECT  45.504 114.511 45.81 114.557 ;
     RECT  56.304 114.227 56.61 114.557 ;
     RECT  99.504 114.539 99.954 114.557 ;
     RECT  110.304 114.539 110.61 114.557 ;
     RECT  121.104 114.539 121.122 114.557 ;
     RECT  123.912 114.461 128.142 114.557 ;
     RECT  131.796 114.497 131.814 114.557 ;
     RECT  153.504 114.511 153.81 114.557 ;
     RECT  163.62 114.227 164.61 114.557 ;
     RECT  174.42 114.539 175.41 114.557 ;
     RECT  178.524 114.379 178.542 114.557 ;
     RECT  182.376 114.269 182.502 114.557 ;
     RECT  88.704 114.449 89.19 114.575 ;
     RECT  91.908 114.449 91.926 114.575 ;
     RECT  135.468 114.305 135.486 114.575 ;
     RECT  162.72 114.269 162.81 114.575 ;
     RECT  165.852 114.305 165.906 114.575 ;
     RECT  168.732 114.349 168.894 114.575 ;
     RECT  170.388 114.539 170.406 114.575 ;
     RECT  98.028 114.539 98.046 114.605 ;
     RECT  99.576 114.557 99.954 114.605 ;
     RECT  123.912 114.557 127.458 114.605 ;
     RECT  183.564 114.497 185.346 114.605 ;
     RECT  121.968 114.539 122.418 114.611 ;
     RECT  155.556 114.421 155.574 114.611 ;
     RECT  52.74 101.357 52.758 114.647 ;
     RECT  88.956 114.575 89.19 114.653 ;
     RECT  99.576 114.605 99.774 114.653 ;
     RECT  187.02 114.221 188.046 114.653 ;
     RECT  70.092 114.365 70.11 114.683 ;
     RECT  121.968 114.611 121.986 114.683 ;
     RECT  13.356 114.557 15.462 114.701 ;
     RECT  126.54 114.605 126.558 114.701 ;
     RECT  47.484 99.053 47.502 114.719 ;
     RECT  123.912 114.605 125.514 114.719 ;
     RECT  172.728 114.539 172.746 114.797 ;
     RECT  131.004 114.449 131.022 114.845 ;
     RECT  39.312 113.611 39.33 114.881 ;
     RECT  139.86 114.461 139.878 114.893 ;
     RECT  184.86 114.605 185.346 114.893 ;
     RECT  143.892 114.449 145.242 114.941 ;
     RECT  162.72 114.575 162.738 114.989 ;
     RECT  163.62 114.557 163.854 115.037 ;
     RECT  167.004 114.539 167.022 115.085 ;
     RECT  31.68 114.269 35.154 115.133 ;
     RECT  165.852 114.575 165.87 115.133 ;
     RECT  13.392 114.701 15.462 115.181 ;
     RECT  124.272 114.719 125.514 115.181 ;
     RECT  182.376 114.557 182.43 115.181 ;
     RECT  65.196 110.561 65.214 115.187 ;
     RECT  75.708 114.449 75.726 115.223 ;
     RECT  181.26 114.509 181.422 115.223 ;
     RECT  181.26 115.223 181.314 115.229 ;
     RECT  183.564 114.605 184.122 115.229 ;
     RECT  124.272 115.181 125.046 115.277 ;
     RECT  183.564 115.229 183.618 115.277 ;
     RECT  125.028 115.277 125.046 115.325 ;
     RECT  185.256 114.893 185.346 115.325 ;
     RECT  17.856 113.881 17.874 115.421 ;
     RECT  44.568 110.219 44.586 115.421 ;
     RECT  127.44 114.605 127.458 115.421 ;
     RECT  185.292 115.325 185.346 115.421 ;
     RECT  137.88 114.539 137.898 115.469 ;
     RECT  143.892 114.941 144.63 115.517 ;
     RECT  185.328 115.421 185.346 115.517 ;
     RECT  143.892 115.517 143.91 115.565 ;
     RECT  168.732 114.575 168.75 115.613 ;
     RECT  174.42 114.557 174.798 115.661 ;
     RECT  14.904 115.181 15.462 115.709 ;
     RECT  181.26 115.229 181.278 115.709 ;
     RECT  13.392 115.181 13.986 115.757 ;
     RECT  14.904 115.709 15.03 115.757 ;
     RECT  31.68 115.133 34.182 115.757 ;
     RECT  124.272 115.277 124.29 115.757 ;
     RECT  182.376 115.181 182.394 115.757 ;
     RECT  183.564 115.277 183.582 115.757 ;
     RECT  13.788 115.757 13.986 115.805 ;
     RECT  15.012 115.757 15.03 115.805 ;
     RECT  31.68 115.757 31.878 115.805 ;
     RECT  33.156 115.757 33.678 115.805 ;
     RECT  31.86 115.805 31.878 115.853 ;
     RECT  99.324 116.059 99.342 116.237 ;
     RECT  174.78 115.661 174.798 116.237 ;
     RECT  171.972 114.539 171.99 116.285 ;
     RECT  163.836 115.037 163.854 116.333 ;
     RECT  100.188 116.299 100.206 116.347 ;
     RECT  13.788 115.805 13.806 116.381 ;
     RECT  33.48 115.805 33.678 116.381 ;
     RECT  167.832 114.305 167.85 116.381 ;
     RECT  127.548 116.107 127.566 116.429 ;
     RECT  125.712 116.347 125.73 116.443 ;
     RECT  100.188 116.347 100.278 116.477 ;
     RECT  137.052 114.509 137.07 116.477 ;
     RECT  184.176 116.395 184.194 116.491 ;
     RECT  100.26 116.477 100.278 116.525 ;
     RECT  125.316 116.443 125.73 116.525 ;
     RECT  129.816 114.449 129.834 116.525 ;
     RECT  187.668 114.653 188.046 116.525 ;
     RECT  125.316 116.525 125.334 116.573 ;
     RECT  184.176 116.491 184.266 116.573 ;
     RECT  29.304 114.497 29.322 116.621 ;
     RECT  34.2 116.491 34.218 116.621 ;
     RECT  184.248 116.573 184.266 116.621 ;
    LAYER M4 ;
     RECT  2.401 29.616 2.408 29.64 ;
     RECT  2.401 37.344 2.408 37.368 ;
     RECT  2.365 40.416 2.408 40.44 ;
     RECT  2.408 2.148 2.512 114.492 ;
     RECT  2.512 2.418 2.704 114.222 ;
     RECT  2.704 40.416 3.011 46.2 ;
     RECT  2.704 33.264 3.017 39.384 ;
     RECT  2.704 27.888 3.059 30.84 ;
     RECT  2.704 31.92 3.059 32.088 ;
     RECT  3.017 33.264 3.059 35.688 ;
     RECT  3.059 27.888 3.203 29.688 ;
     RECT  3.203 27.888 3.443 29.64 ;
     RECT  3.017 36.768 3.443 39.384 ;
     RECT  3.443 28.32 3.521 29.64 ;
     RECT  3.011 43.68 3.539 46.2 ;
     RECT  3.443 37.584 3.683 39.384 ;
     RECT  3.059 34.752 3.737 35.688 ;
     RECT  3.737 34.896 3.773 35.688 ;
     RECT  3.683 37.824 3.773 38.232 ;
     RECT  3.539 43.68 4.019 44.472 ;
     RECT  3.683 39.36 4.057 39.384 ;
     RECT  3.805 33.024 4.129 33.192 ;
     RECT  3.773 37.872 4.169 38.232 ;
     RECT  3.059 31.92 4.237 32.04 ;
     RECT  4.129 33.024 4.237 33.672 ;
     RECT  3.011 40.416 4.241 42.456 ;
     RECT  3.521 28.32 4.277 29.496 ;
     RECT  3.773 34.896 4.421 35.496 ;
     RECT  4.421 34.944 4.457 35.496 ;
     RECT  4.019 43.92 4.565 44.472 ;
     RECT  3.539 45.6 4.597 46.2 ;
     RECT  4.169 38.16 4.777 38.232 ;
     RECT  4.057 39.36 4.777 39.432 ;
     RECT  4.565 44.448 4.849 44.472 ;
     RECT  4.597 45.504 4.849 46.2 ;
     RECT  4.813 47.232 4.849 47.256 ;
     RECT  4.277 28.416 4.853 29.496 ;
     RECT  4.849 44.448 4.925 47.256 ;
     RECT  3.913 49.008 4.957 49.032 ;
     RECT  4.241 41.424 5.029 42.456 ;
     RECT  5.029 41.424 5.105 42.744 ;
     RECT  4.925 44.448 5.123 45.864 ;
     RECT  4.925 46.896 5.245 47.256 ;
     RECT  3.059 30.816 5.317 30.84 ;
     RECT  4.237 31.92 5.317 33.672 ;
     RECT  5.245 46.896 5.317 47.88 ;
     RECT  4.957 49.008 5.317 49.608 ;
     RECT  4.853 28.416 5.321 29.256 ;
     RECT  5.317 30.72 5.363 33.672 ;
     RECT  5.105 42.432 5.389 42.744 ;
     RECT  4.457 34.944 5.425 35.256 ;
     RECT  4.241 40.416 5.501 40.44 ;
     RECT  5.425 34.944 5.537 35.88 ;
     RECT  4.777 38.16 5.605 39.432 ;
     RECT  5.317 46.896 5.641 49.608 ;
     RECT  5.537 35.184 5.651 35.88 ;
     RECT  5.363 32.448 5.677 33.672 ;
     RECT  5.105 41.424 5.677 41.448 ;
     RECT  5.605 37.584 5.681 39.432 ;
     RECT  5.363 30.72 5.753 31.416 ;
     RECT  5.641 46.896 5.789 50.136 ;
     RECT  5.681 38.208 5.825 39.432 ;
     RECT  5.123 45.456 5.897 45.864 ;
     RECT  5.825 38.688 5.929 39.432 ;
     RECT  5.753 31.152 5.933 31.416 ;
     RECT  5.677 32.448 5.939 33.96 ;
     RECT  5.789 47.28 6.005 50.136 ;
     RECT  5.749 37.104 6.083 37.128 ;
     RECT  5.897 45.504 6.085 45.864 ;
     RECT  6.005 47.76 6.217 50.136 ;
     RECT  6.217 47.76 6.323 50.808 ;
     RECT  5.389 42.432 6.325 42.84 ;
     RECT  5.123 44.448 6.325 44.472 ;
     RECT  5.321 28.416 6.361 28.44 ;
     RECT  5.677 40.896 6.419 41.448 ;
     RECT  5.929 38.688 6.437 39.864 ;
     RECT  6.325 42.432 6.437 44.472 ;
     RECT  6.437 38.688 6.467 39.576 ;
     RECT  6.361 26.88 6.473 26.904 ;
     RECT  5.651 35.184 6.581 35.832 ;
     RECT  6.467 38.688 6.617 39.432 ;
     RECT  6.581 35.184 6.689 35.592 ;
     RECT  6.085 45.504 6.865 46.248 ;
     RECT  5.933 31.392 6.937 31.416 ;
     RECT  5.939 33.072 6.937 33.624 ;
     RECT  6.865 45.504 7.045 46.728 ;
     RECT  6.323 50.592 7.117 50.808 ;
     RECT  7.045 45.456 7.189 46.728 ;
     RECT  6.323 47.76 7.189 49.608 ;
     RECT  6.361 28.416 7.261 28.824 ;
     RECT  7.225 76.368 7.297 76.392 ;
     RECT  6.419 41.424 7.333 41.448 ;
     RECT  7.189 45.456 7.369 49.608 ;
     RECT  7.117 50.592 7.369 51.24 ;
     RECT  7.261 28.416 7.381 29.064 ;
     RECT  7.369 45.456 7.477 51.24 ;
     RECT  7.369 52.272 7.477 52.296 ;
     RECT  7.297 76.32 7.513 76.392 ;
     RECT  7.381 28.224 7.657 29.064 ;
     RECT  7.333 41.424 7.693 41.736 ;
     RECT  7.693 41.184 7.765 41.736 ;
     RECT  7.657 25.248 7.808 25.272 ;
     RECT  7.009 26.496 7.808 26.52 ;
     RECT  7.657 27.936 7.808 29.064 ;
     RECT  6.937 31.344 7.808 31.416 ;
     RECT  6.937 32.688 7.808 33.624 ;
     RECT  6.689 35.184 7.808 35.496 ;
     RECT  6.617 38.688 7.808 39.336 ;
     RECT  7.765 40.944 7.808 41.736 ;
     RECT  6.437 42.72 7.808 44.472 ;
     RECT  7.477 45.456 7.808 52.296 ;
     RECT  6.217 53.808 7.808 53.832 ;
     RECT  7.513 75.696 7.808 76.392 ;
     RECT  7.333 77.664 7.808 77.688 ;
     RECT  7.808 2.148 7.912 114.492 ;
     RECT  7.912 2.418 8.104 114.222 ;
     RECT  8.104 35.184 8.243 45.48 ;
     RECT  8.104 48.432 8.243 49.32 ;
     RECT  8.104 50.304 8.243 52.296 ;
     RECT  8.243 48.432 8.273 48.504 ;
     RECT  8.104 53.52 8.489 54.744 ;
     RECT  8.104 24.768 8.597 25.272 ;
     RECT  8.243 35.28 8.849 45.48 ;
     RECT  8.273 48.432 8.849 48.456 ;
     RECT  8.849 40.368 8.993 45.48 ;
     RECT  8.104 26.544 9.029 34.056 ;
     RECT  8.849 35.28 9.029 39.336 ;
     RECT  8.993 40.464 9.097 45.48 ;
     RECT  8.104 46.464 9.097 47.064 ;
     RECT  8.104 77.664 9.097 77.688 ;
     RECT  9.097 40.464 9.173 47.064 ;
     RECT  9.029 33.216 9.205 34.056 ;
     RECT  9.029 35.28 9.205 39.288 ;
     RECT  9.173 40.464 9.317 44.472 ;
     RECT  9.029 26.544 9.353 31.992 ;
     RECT  8.597 25.248 9.389 25.272 ;
     RECT  8.243 50.592 9.457 52.296 ;
     RECT  9.205 33.216 9.533 39.288 ;
     RECT  8.489 53.808 9.541 54.744 ;
     RECT  9.533 33.216 9.569 39.24 ;
     RECT  9.457 50.592 9.587 52.632 ;
     RECT  9.541 53.76 9.605 54.744 ;
     RECT  9.353 26.544 9.637 28.536 ;
     RECT  9.569 33.456 9.713 39.24 ;
     RECT  9.353 29.664 9.749 31.992 ;
     RECT  9.173 45.456 10.141 47.064 ;
     RECT  9.317 40.608 10.249 44.472 ;
     RECT  10.141 45.456 10.249 47.352 ;
     RECT  9.097 77.664 10.253 78.12 ;
     RECT  10.253 77.664 10.321 77.688 ;
     RECT  9.587 52.608 10.357 52.632 ;
     RECT  9.889 48.528 10.393 48.552 ;
     RECT  10.249 40.608 10.429 47.352 ;
     RECT  10.393 48.528 10.429 49.128 ;
     RECT  9.637 25.296 10.501 28.536 ;
     RECT  9.749 29.664 10.501 31.416 ;
     RECT  10.429 40.608 10.573 49.128 ;
     RECT  8.104 75.696 10.645 75.72 ;
     RECT  10.321 77.52 10.685 77.688 ;
     RECT  9.713 33.552 10.717 39.24 ;
     RECT  10.573 40.32 10.717 49.128 ;
     RECT  9.587 50.592 10.741 51.192 ;
     RECT  10.357 52.608 10.741 52.92 ;
     RECT  9.605 54.144 10.741 54.744 ;
     RECT  10.717 33.552 10.753 49.128 ;
     RECT  10.741 50.16 10.753 51.192 ;
     RECT  10.753 33.552 10.789 51.192 ;
     RECT  10.741 52.608 10.789 54.84 ;
     RECT  10.789 33.552 10.793 54.84 ;
     RECT  9.961 24.096 10.825 24.12 ;
     RECT  10.793 33.552 10.901 52.92 ;
     RECT  10.901 35.568 10.937 52.92 ;
     RECT  10.357 32.448 10.969 32.472 ;
     RECT  10.901 33.552 10.969 34.536 ;
     RECT  10.969 32.448 11.009 34.536 ;
     RECT  10.645 75.648 11.113 75.72 ;
     RECT  10.937 35.568 11.153 45.816 ;
     RECT  10.937 46.848 11.153 52.92 ;
     RECT  11.153 46.848 11.189 50.904 ;
     RECT  10.685 77.52 11.221 77.544 ;
     RECT  11.153 51.888 11.225 52.92 ;
     RECT  10.825 23.328 11.261 24.12 ;
     RECT  11.153 35.568 11.261 40.392 ;
     RECT  11.221 76.704 11.267 77.544 ;
     RECT  11.153 41.424 11.333 45.816 ;
     RECT  11.009 33.168 11.369 34.536 ;
     RECT  11.189 46.848 11.369 50.856 ;
     RECT  9.205 73.536 11.401 73.56 ;
     RECT  11.225 51.936 11.411 52.92 ;
     RECT  11.113 75.264 11.413 75.72 ;
     RECT  11.401 73.488 11.459 73.56 ;
     RECT  11.267 77.52 11.459 77.544 ;
     RECT  10.793 54.144 11.461 54.84 ;
     RECT  11.261 35.568 11.513 40.2 ;
     RECT  11.461 54.144 11.513 55.368 ;
     RECT  11.369 48.672 11.549 50.856 ;
     RECT  11.513 54.432 11.555 54.744 ;
     RECT  10.501 25.296 11.557 31.416 ;
     RECT  11.549 49.488 11.657 50.856 ;
     RECT  11.261 23.328 11.869 23.736 ;
     RECT  11.555 54.432 11.873 54.648 ;
     RECT  11.797 55.824 11.893 55.848 ;
     RECT  11.149 57.024 11.893 57.048 ;
     RECT  11.893 55.824 11.939 57.048 ;
     RECT  11.369 46.848 11.941 47.304 ;
     RECT  11.939 56.064 11.941 57.048 ;
     RECT  11.941 46.416 11.987 47.304 ;
     RECT  11.941 56.064 11.987 57.624 ;
     RECT  11.557 25.296 12.013 31.992 ;
     RECT  11.987 57.6 12.161 57.624 ;
     RECT  11.413 75.264 12.193 76.296 ;
     RECT  12.193 74.688 12.197 76.296 ;
     RECT  11.369 33.552 12.265 34.536 ;
     RECT  11.513 36.528 12.265 40.2 ;
     RECT  11.333 41.424 12.265 45.192 ;
     RECT  11.657 49.728 12.409 50.856 ;
     RECT  11.411 52.032 12.409 52.92 ;
     RECT  12.013 25.296 12.517 32.328 ;
     RECT  12.265 33.552 12.517 35.016 ;
     RECT  12.265 36.528 12.517 45.192 ;
     RECT  12.409 49.728 12.517 52.92 ;
     RECT  11.987 46.56 12.553 47.304 ;
     RECT  12.517 48.48 12.553 48.504 ;
     RECT  11.459 73.536 12.553 73.56 ;
     RECT  12.197 74.688 12.553 74.712 ;
     RECT  12.517 25.2 12.565 35.016 ;
     RECT  12.553 46.56 12.661 48.744 ;
     RECT  12.517 49.728 12.661 53.4 ;
     RECT  12.709 114 12.733 114.024 ;
     RECT  12.565 25.2 12.805 35.352 ;
     RECT  12.733 113.856 12.805 114.024 ;
     RECT  12.661 46.56 12.841 53.4 ;
     RECT  11.873 54.432 12.841 54.456 ;
     RECT  12.517 36.432 12.877 45.192 ;
     RECT  11.869 22.8 12.913 23.736 ;
     RECT  12.805 25.104 12.913 35.352 ;
     RECT  12.877 36.336 12.949 45.192 ;
     RECT  12.841 46.56 12.949 54.456 ;
     RECT  11.987 56.064 13.045 56.568 ;
     RECT  11.365 79.2 13.045 79.224 ;
     RECT  12.913 22.8 13.093 35.352 ;
     RECT  12.949 36.336 13.093 54.456 ;
     RECT  12.805 113.856 13.189 114.552 ;
     RECT  12.985 21.696 13.208 21.72 ;
     RECT  13.093 22.8 13.208 54.456 ;
     RECT  13.045 55.68 13.208 56.568 ;
     RECT  12.985 59.28 13.208 59.304 ;
     RECT  12.553 73.536 13.208 74.712 ;
     RECT  12.197 75.84 13.208 76.296 ;
     RECT  13.165 77.664 13.208 77.688 ;
     RECT  13.045 78.672 13.208 79.224 ;
     RECT  13.189 113.856 13.208 115.416 ;
     RECT  13.208 2.148 13.312 115.416 ;
     RECT  13.312 2.418 13.381 115.416 ;
     RECT  13.285 116.448 13.381 116.472 ;
     RECT  13.381 2.418 13.504 116.472 ;
     RECT  13.504 30.048 13.565 48.12 ;
     RECT  13.504 50.592 13.565 53.4 ;
     RECT  13.504 21.552 13.601 29.064 ;
     RECT  13.565 30.048 13.601 44.472 ;
     RECT  13.601 21.552 13.619 29.016 ;
     RECT  13.601 35.52 13.619 44.472 ;
     RECT  13.504 113.424 13.667 116.472 ;
     RECT  13.601 30.048 13.673 34.392 ;
     RECT  13.619 21.552 13.745 23.64 ;
     RECT  13.619 36 13.745 44.424 ;
     RECT  13.504 77.328 13.763 79.224 ;
     RECT  13.667 113.424 13.817 116.376 ;
     RECT  13.745 36.288 13.859 44.424 ;
     RECT  13.745 21.552 13.889 23.304 ;
     RECT  13.673 30.048 13.997 31.704 ;
     RECT  13.859 36.288 13.997 44.376 ;
     RECT  13.889 21.552 14.147 23.208 ;
     RECT  13.997 36.576 14.177 42.6 ;
     RECT  13.763 77.664 14.177 79.224 ;
     RECT  13.997 30.048 14.249 31.128 ;
     RECT  13.504 74.112 14.285 75.192 ;
     RECT  13.504 59.28 14.321 59.304 ;
     RECT  13.619 24.672 14.465 29.016 ;
     RECT  13.997 43.584 14.465 44.376 ;
     RECT  13.565 45.504 14.465 48.12 ;
     RECT  13.565 50.88 14.497 53.4 ;
     RECT  13.504 54.528 14.497 56.904 ;
     RECT  13.673 33.024 14.641 34.392 ;
     RECT  14.177 79.2 14.645 79.224 ;
     RECT  13.504 49.2 14.713 49.224 ;
     RECT  14.465 45.792 14.753 48.12 ;
     RECT  13.504 76.272 14.773 76.344 ;
     RECT  14.177 77.664 14.773 77.976 ;
     RECT  14.773 76.272 14.785 77.976 ;
     RECT  14.465 25.152 14.789 28.824 ;
     RECT  14.641 33.024 14.821 35.16 ;
     RECT  14.785 76.176 14.825 77.976 ;
     RECT  14.713 49.2 14.861 49.608 ;
     RECT  14.497 50.88 14.861 56.904 ;
     RECT  14.789 25.2 14.933 28.824 ;
     RECT  14.821 32.496 15.001 35.16 ;
     RECT  14.753 45.984 15.037 48.12 ;
     RECT  14.861 49.2 15.037 49.32 ;
     RECT  15.037 45.984 15.041 49.32 ;
     RECT  13.817 113.424 15.059 115.8 ;
     RECT  14.249 30.288 15.073 31.128 ;
     RECT  14.861 50.88 15.077 55.224 ;
     RECT  15.001 32.256 15.181 35.16 ;
     RECT  14.285 75.168 15.181 75.192 ;
     RECT  14.825 76.176 15.181 76.392 ;
     RECT  15.181 32.256 15.185 35.256 ;
     RECT  15.059 113.424 15.185 115.704 ;
     RECT  14.177 36.576 15.205 42.504 ;
     RECT  14.147 21.552 15.221 22.584 ;
     RECT  15.185 35.232 15.251 35.256 ;
     RECT  15.181 75.168 15.251 76.392 ;
     RECT  14.861 56.544 15.253 56.904 ;
     RECT  15.077 50.88 15.293 54.984 ;
     RECT  15.253 56.544 15.293 57.048 ;
     RECT  14.285 74.112 15.325 74.136 ;
     RECT  15.205 36.24 15.469 42.504 ;
     RECT  15.185 113.424 15.473 113.448 ;
     RECT  15.185 114.48 15.473 115.704 ;
     RECT  15.469 36.24 15.541 42.648 ;
     RECT  14.465 43.728 15.541 44.376 ;
     RECT  15.293 50.88 15.541 54.072 ;
     RECT  15.325 74.064 15.541 74.136 ;
     RECT  15.251 75.168 15.541 75.192 ;
     RECT  15.041 45.984 15.581 49.272 ;
     RECT  15.581 46.032 15.617 49.272 ;
     RECT  15.293 56.88 15.653 57.048 ;
     RECT  15.473 114.48 15.653 115.416 ;
     RECT  15.541 74.064 15.689 75.192 ;
     RECT  15.541 36.24 15.757 44.376 ;
     RECT  14.825 77.52 15.757 77.976 ;
     RECT  15.721 79.248 15.757 79.272 ;
     RECT  14.933 25.2 15.761 28.536 ;
     RECT  15.653 114.528 15.797 115.416 ;
     RECT  15.757 77.52 15.827 79.272 ;
     RECT  15.469 23.808 15.865 23.832 ;
     RECT  15.761 25.2 15.865 28.008 ;
     RECT  15.073 30.288 15.937 31.176 ;
     RECT  15.937 30.288 16.009 31.224 ;
     RECT  15.757 36.24 16.009 44.712 ;
     RECT  16.009 36.24 16.021 44.904 ;
     RECT  15.827 77.52 16.049 77.544 ;
     RECT  16.021 36.24 16.085 45 ;
     RECT  15.865 23.808 16.153 28.008 ;
     RECT  15.541 50.448 16.153 54.072 ;
     RECT  16.009 29.616 16.225 31.224 ;
     RECT  15.221 21.552 16.297 22.536 ;
     RECT  15.653 57.024 16.297 57.048 ;
     RECT  15.689 74.064 16.297 75.048 ;
     RECT  16.085 36.24 16.441 44.904 ;
     RECT  16.297 57.024 16.477 57.864 ;
     RECT  14.749 59.328 16.477 59.736 ;
     RECT  15.185 32.256 16.513 34.2 ;
     RECT  16.441 35.808 16.513 44.904 ;
     RECT  16.153 49.44 16.513 54.072 ;
     RECT  16.081 55.248 16.513 55.272 ;
     RECT  16.513 49.44 16.553 55.272 ;
     RECT  16.225 29.616 16.621 31.272 ;
     RECT  16.513 32.256 16.621 44.904 ;
     RECT  16.553 51.36 16.625 55.272 ;
     RECT  16.297 73.488 16.625 75.048 ;
     RECT  16.297 21.024 16.645 22.536 ;
     RECT  16.477 59.328 16.661 59.784 ;
     RECT  16.645 20.16 16.697 22.536 ;
     RECT  16.621 29.616 16.729 44.904 ;
     RECT  16.697 20.352 16.765 22.536 ;
     RECT  16.153 23.712 16.765 28.008 ;
     RECT  16.625 73.488 16.805 74.328 ;
     RECT  16.625 51.36 16.841 54.84 ;
     RECT  16.765 20.352 16.873 28.44 ;
     RECT  16.729 29.52 16.873 44.904 ;
     RECT  16.477 57.024 16.873 58.248 ;
     RECT  15.251 76.176 16.909 76.392 ;
     RECT  16.841 51.36 16.913 54.024 ;
     RECT  16.873 56.256 17.017 58.248 ;
     RECT  15.617 46.032 17.053 48.12 ;
     RECT  16.553 49.44 17.053 50.04 ;
     RECT  15.827 78.96 17.053 79.272 ;
     RECT  16.805 73.488 17.089 73.512 ;
     RECT  17.017 55.92 17.093 58.248 ;
     RECT  16.909 76.176 17.125 76.968 ;
     RECT  17.089 73.344 17.129 73.512 ;
     RECT  17.053 78.624 17.165 79.272 ;
     RECT  16.913 51.36 17.237 53.496 ;
     RECT  16.873 20.352 17.365 44.904 ;
     RECT  17.053 46.032 17.365 50.04 ;
     RECT  17.125 75.648 17.737 76.968 ;
     RECT  17.737 75.648 17.749 77.304 ;
     RECT  17.165 78.624 17.749 79.224 ;
     RECT  17.093 55.92 17.845 57.864 ;
     RECT  17.237 51.696 17.881 53.496 ;
     RECT  15.797 115.392 17.885 115.416 ;
     RECT  17.881 51.696 17.953 53.592 ;
     RECT  17.845 55.2 18.133 57.864 ;
     RECT  17.749 75.648 18.133 79.224 ;
     RECT  18.133 55.2 18.169 58.44 ;
     RECT  16.661 59.76 18.169 59.784 ;
     RECT  17.129 73.344 18.205 73.368 ;
     RECT  17.365 20.352 18.313 50.04 ;
     RECT  18.133 74.784 18.349 79.224 ;
     RECT  17.953 51.696 18.385 54.12 ;
     RECT  18.169 55.2 18.385 59.784 ;
     RECT  18.385 51.696 18.565 59.784 ;
     RECT  18.313 20.352 18.608 50.088 ;
     RECT  18.565 51.696 18.608 59.832 ;
     RECT  14.497 64.08 18.608 64.104 ;
     RECT  18.205 72.96 18.608 73.368 ;
     RECT  18.349 74.784 18.608 79.464 ;
     RECT  18.608 2.148 18.712 114.492 ;
     RECT  18.712 2.418 18.904 114.222 ;
     RECT  18.904 21.648 19.145 55.224 ;
     RECT  18.904 72.336 19.253 73.368 ;
     RECT  19.253 72.336 19.283 73.224 ;
     RECT  19.283 72.336 19.811 72.984 ;
     RECT  19.145 22.464 19.901 55.224 ;
     RECT  18.904 59.232 19.955 59.976 ;
     RECT  18.904 19.632 20.113 19.656 ;
     RECT  20.113 18.768 20.149 19.656 ;
     RECT  19.901 51.696 20.185 55.224 ;
     RECT  18.904 56.4 20.185 57.864 ;
     RECT  19.901 22.464 20.261 50.712 ;
     RECT  20.149 18.768 20.293 19.944 ;
     RECT  20.185 51.696 20.293 57.864 ;
     RECT  19.955 59.232 20.293 59.832 ;
     RECT  20.293 18.768 20.339 20.088 ;
     RECT  20.261 22.464 20.405 23.112 ;
     RECT  20.293 51.696 20.441 59.832 ;
     RECT  19.897 61.344 20.509 61.368 ;
     RECT  20.441 56.016 20.549 59.832 ;
     RECT  20.261 24.096 20.693 50.712 ;
     RECT  20.549 56.016 20.693 59.784 ;
     RECT  20.693 56.016 20.801 57.48 ;
     RECT  20.693 24.096 20.837 45 ;
     RECT  20.693 46.032 21.013 50.712 ;
     RECT  20.441 51.696 21.013 55.032 ;
     RECT  18.904 79.2 21.049 79.464 ;
     RECT  20.693 59.232 21.089 59.784 ;
     RECT  21.049 78.624 21.107 79.464 ;
     RECT  20.761 21.264 21.109 21.288 ;
     RECT  20.405 22.464 21.155 23.064 ;
     RECT  21.013 46.032 21.161 55.032 ;
     RECT  20.801 56.064 21.341 57.48 ;
     RECT  21.155 22.8 21.445 23.064 ;
     RECT  20.837 24.096 21.445 25.608 ;
     RECT  21.445 22.8 21.629 25.608 ;
     RECT  20.339 18.768 21.661 19.944 ;
     RECT  20.509 61.008 21.809 61.368 ;
     RECT  21.661 18.432 21.985 19.944 ;
     RECT  21.109 20.976 21.985 21.288 ;
     RECT  21.089 59.232 21.985 59.256 ;
     RECT  21.985 58.8 22.093 59.256 ;
     RECT  22.057 62.544 22.093 62.568 ;
     RECT  21.629 23.04 22.129 25.608 ;
     RECT  20.837 26.784 22.129 45 ;
     RECT  22.093 58.8 22.133 59.352 ;
     RECT  21.161 46.032 22.237 54.6 ;
     RECT  22.093 62.544 22.241 62.664 ;
     RECT  22.241 62.544 22.313 62.568 ;
     RECT  22.237 46.032 22.345 54.696 ;
     RECT  22.129 23.04 22.525 45 ;
     RECT  22.345 46.032 22.525 54.984 ;
     RECT  21.341 56.064 22.525 57.144 ;
     RECT  19.811 72.336 22.673 72.36 ;
     RECT  21.985 18.432 22.705 21.288 ;
     RECT  22.525 23.04 22.705 54.984 ;
     RECT  22.705 18.432 22.853 54.984 ;
     RECT  22.853 20.544 22.925 54.984 ;
     RECT  21.809 61.344 23.029 61.368 ;
     RECT  22.925 35.184 23.353 54.984 ;
     RECT  22.525 56.064 23.353 57.576 ;
     RECT  22.133 59.04 23.569 59.352 ;
     RECT  23.029 60.384 23.569 61.368 ;
     RECT  23.569 59.04 23.677 61.368 ;
     RECT  18.904 76.176 23.893 76.2 ;
     RECT  23.677 58.992 23.929 61.368 ;
     RECT  22.853 18.432 24.008 19.368 ;
     RECT  22.925 20.544 24.008 34.2 ;
     RECT  23.353 35.184 24.008 57.576 ;
     RECT  23.929 58.656 24.008 61.368 ;
     RECT  18.904 64.08 24.008 64.104 ;
     RECT  23.893 76.176 24.008 76.344 ;
     RECT  21.107 78.912 24.008 79.464 ;
     RECT  24.008 2.148 24.112 114.492 ;
     RECT  24.112 2.418 24.304 114.222 ;
     RECT  24.304 56.4 24.437 60.408 ;
     RECT  24.304 27.072 24.473 54.984 ;
     RECT  24.304 78.912 24.515 79.992 ;
     RECT  24.473 52.224 24.545 54.984 ;
     RECT  24.545 52.224 24.653 54.888 ;
     RECT  24.653 53.28 24.689 54.696 ;
     RECT  24.437 57.552 25.139 58.68 ;
     RECT  24.304 18.768 25.285 21.768 ;
     RECT  24.437 56.4 25.301 56.424 ;
     RECT  24.304 23.088 25.405 25.8 ;
     RECT  24.437 60.24 25.427 60.408 ;
     RECT  25.139 58.08 25.513 58.68 ;
     RECT  24.515 79.152 25.549 79.464 ;
     RECT  25.405 23.088 25.585 25.896 ;
     RECT  24.473 27.072 25.621 51 ;
     RECT  24.653 52.224 25.621 52.248 ;
     RECT  25.621 27.072 25.657 52.248 ;
     RECT  24.689 53.28 25.657 54.216 ;
     RECT  25.549 79.152 25.657 79.8 ;
     RECT  25.657 79.152 25.715 80.568 ;
     RECT  25.657 27.072 25.765 54.216 ;
     RECT  25.621 55.488 25.765 55.512 ;
     RECT  25.285 18.528 25.805 21.768 ;
     RECT  25.585 23.04 25.837 25.896 ;
     RECT  25.693 62.736 25.859 62.76 ;
     RECT  25.837 23.04 25.861 25.992 ;
     RECT  25.813 60.96 25.877 61.368 ;
     RECT  25.805 19.344 25.907 21.768 ;
     RECT  25.907 19.344 25.955 20.664 ;
     RECT  25.861 22.752 26.053 25.992 ;
     RECT  25.765 27.072 26.053 55.512 ;
     RECT  26.053 22.752 26.089 55.512 ;
     RECT  26.089 57.024 26.345 57.048 ;
     RECT  25.955 19.632 26.417 20.664 ;
     RECT  26.089 21.984 26.417 55.512 ;
     RECT  24.304 64.08 26.483 64.104 ;
     RECT  25.715 79.152 26.677 80.376 ;
     RECT  26.417 21.984 26.741 54.792 ;
     RECT  26.677 78.672 26.741 80.376 ;
     RECT  24.304 76.32 26.773 76.344 ;
     RECT  26.773 76.224 26.813 76.344 ;
     RECT  26.741 21.984 26.885 54.648 ;
     RECT  25.877 61.344 26.917 61.368 ;
     RECT  26.917 61.008 26.957 61.368 ;
     RECT  26.885 21.984 27.025 47.496 ;
     RECT  26.741 79.152 27.065 80.376 ;
     RECT  27.025 21.552 27.107 47.496 ;
     RECT  26.581 83.808 27.313 83.832 ;
     RECT  27.313 83.808 27.317 84.36 ;
     RECT  26.125 17.856 27.349 17.88 ;
     RECT  26.417 19.632 27.349 20.328 ;
     RECT  27.349 19.488 27.395 20.328 ;
     RECT  26.885 48.48 27.533 50.76 ;
     RECT  27.395 20.304 27.565 20.328 ;
     RECT  25.513 58.08 27.673 58.728 ;
     RECT  26.161 59.712 27.673 59.784 ;
     RECT  27.673 58.08 27.749 59.784 ;
     RECT  27.733 56.928 27.785 56.952 ;
     RECT  27.749 58.08 28.069 58.104 ;
     RECT  27.565 20.304 28.177 20.904 ;
     RECT  27.533 48.672 28.181 50.76 ;
     RECT  28.069 57.936 28.249 58.104 ;
     RECT  26.885 52.224 28.393 54.648 ;
     RECT  27.749 59.184 28.537 59.784 ;
     RECT  26.957 61.008 28.537 61.032 ;
     RECT  28.181 50.16 28.609 50.76 ;
     RECT  28.393 51.936 28.609 54.648 ;
     RECT  27.065 79.152 28.645 79.176 ;
     RECT  28.537 59.184 28.789 61.032 ;
     RECT  27.349 17.856 28.825 18.456 ;
     RECT  28.177 20.304 28.861 21 ;
     RECT  27.107 22.224 28.861 47.496 ;
     RECT  28.609 50.16 28.861 54.648 ;
     RECT  28.249 57.12 28.885 58.104 ;
     RECT  28.789 59.184 28.885 61.08 ;
     RECT  28.885 57.12 28.933 61.08 ;
     RECT  28.181 48.672 29.077 48.984 ;
     RECT  29.077 48.48 29.269 48.984 ;
     RECT  28.861 50.16 29.269 54.696 ;
     RECT  28.825 17.856 29.408 19.272 ;
     RECT  28.861 20.304 29.408 47.496 ;
     RECT  29.269 48.48 29.408 54.696 ;
     RECT  28.933 57.12 29.408 61.128 ;
     RECT  28.069 64.848 29.408 64.872 ;
     RECT  28.741 69.552 29.408 69.576 ;
     RECT  26.813 76.224 29.408 76.248 ;
     RECT  28.645 79.008 29.408 79.176 ;
     RECT  27.065 80.352 29.408 80.376 ;
     RECT  27.317 84.336 29.408 84.36 ;
     RECT  29.408 2.148 29.512 114.492 ;
     RECT  29.512 2.418 29.704 114.222 ;
     RECT  29.704 79.008 29.843 80.52 ;
     RECT  29.704 17.856 29.909 57.96 ;
     RECT  29.843 79.152 30.089 80.52 ;
     RECT  29.909 22.752 30.161 57.96 ;
     RECT  29.909 17.856 30.305 21.528 ;
     RECT  30.305 18.912 30.341 21.528 ;
     RECT  30.161 22.752 30.341 50.184 ;
     RECT  29.704 61.008 30.419 61.368 ;
     RECT  29.704 76.224 30.419 76.392 ;
     RECT  30.341 19.248 30.449 21.528 ;
     RECT  30.449 19.296 30.485 21.528 ;
     RECT  30.419 76.368 30.515 76.392 ;
     RECT  29.704 59.04 30.665 59.208 ;
     RECT  29.704 87.936 30.733 88.632 ;
     RECT  30.485 19.296 30.809 21.48 ;
     RECT  30.161 51.168 30.845 57.96 ;
     RECT  29.704 84.336 30.877 85.32 ;
     RECT  30.733 87.936 30.901 89.304 ;
     RECT  30.877 83.856 30.947 85.32 ;
     RECT  30.901 87.936 30.953 89.688 ;
     RECT  30.089 79.152 30.997 80.376 ;
     RECT  30.947 84.24 31.043 85.32 ;
     RECT  30.953 87.936 31.057 89.304 ;
     RECT  29.704 77.376 31.061 77.4 ;
     RECT  30.997 78.672 31.061 80.376 ;
     RECT  30.341 23.904 31.129 50.184 ;
     RECT  30.845 51.168 31.129 51.288 ;
     RECT  30.809 19.296 31.133 20.808 ;
     RECT  31.057 86.64 31.139 89.304 ;
     RECT  31.043 84.912 31.187 85.32 ;
     RECT  31.139 86.976 31.187 89.304 ;
     RECT  31.187 84.912 31.241 84.936 ;
     RECT  31.061 79.2 31.273 80.376 ;
     RECT  30.845 52.32 31.277 57.96 ;
     RECT  30.341 22.752 31.309 22.776 ;
     RECT  31.129 23.904 31.309 51.288 ;
     RECT  31.277 52.32 31.331 56.76 ;
     RECT  31.273 79.2 31.331 80.664 ;
     RECT  31.187 87.36 31.349 89.304 ;
     RECT  31.331 79.2 31.385 79.8 ;
     RECT  29.704 82.416 31.421 82.68 ;
     RECT  31.133 19.488 31.457 20.808 ;
     RECT  31.309 22.752 31.529 51.288 ;
     RECT  31.349 87.984 31.637 89.304 ;
     RECT  29.293 116.592 31.669 116.616 ;
     RECT  31.669 96.432 31.777 96.456 ;
     RECT  31.669 115.776 31.813 116.616 ;
     RECT  31.525 107.184 31.909 107.208 ;
     RECT  31.277 57.936 31.925 57.96 ;
     RECT  31.777 95.472 31.957 96.456 ;
     RECT  31.331 56.592 31.961 56.76 ;
     RECT  31.385 79.776 31.961 79.8 ;
     RECT  31.417 93.936 32.003 93.96 ;
     RECT  31.529 22.752 32.173 50.184 ;
     RECT  32.101 114.144 32.245 114.168 ;
     RECT  32.245 113.424 32.281 114.168 ;
     RECT  31.637 87.984 32.291 88.872 ;
     RECT  30.665 59.04 32.353 59.064 ;
     RECT  31.457 20.304 32.437 20.808 ;
     RECT  31.957 95.376 32.461 96.456 ;
     RECT  31.529 51.264 32.533 51.288 ;
     RECT  31.331 52.32 32.533 55.416 ;
     RECT  32.437 20.304 32.537 21.576 ;
     RECT  32.353 58.56 32.573 59.064 ;
     RECT  32.461 94.56 32.821 96.504 ;
     RECT  32.821 94.56 32.917 96.984 ;
     RECT  32.173 22.704 32.929 50.184 ;
     RECT  32.533 51.264 32.929 55.416 ;
     RECT  32.917 94.56 32.969 97.512 ;
     RECT  30.305 17.856 33.001 17.88 ;
     RECT  31.961 56.592 33.001 56.616 ;
     RECT  32.281 113.424 33.001 114.648 ;
     RECT  31.813 115.728 33.001 116.616 ;
     RECT  33.001 17.088 33.013 17.88 ;
     RECT  33.013 16.416 33.041 17.88 ;
     RECT  32.537 20.304 33.041 21.48 ;
     RECT  33.041 16.416 33.059 17.112 ;
     RECT  32.929 22.704 33.077 55.416 ;
     RECT  31.909 106.272 33.155 107.208 ;
     RECT  32.573 58.656 33.205 59.064 ;
     RECT  33.077 22.704 33.221 52.632 ;
     RECT  33.145 93.12 33.251 93.144 ;
     RECT  33.221 22.704 33.257 52.248 ;
     RECT  33.257 22.704 33.329 52.2 ;
     RECT  33.329 31.152 33.365 52.2 ;
     RECT  33.365 31.152 33.401 51.288 ;
     RECT  32.291 88.608 33.437 88.872 ;
     RECT  33.041 20.304 33.469 20.904 ;
     RECT  33.329 23.52 33.509 30.168 ;
     RECT  33.437 88.8 33.541 88.872 ;
     RECT  33.401 31.152 33.545 51.048 ;
     RECT  33.155 107.184 33.545 107.208 ;
     RECT  33.001 56.592 33.689 57.576 ;
     RECT  32.969 94.56 33.757 96.888 ;
     RECT  30.419 61.344 33.781 61.368 ;
     RECT  33.613 62.736 33.781 62.76 ;
     RECT  33.781 60.864 33.827 62.76 ;
     RECT  33.059 16.416 33.901 16.44 ;
     RECT  33.205 58.656 33.901 59.304 ;
     RECT  33.827 60.864 33.901 60.888 ;
     RECT  33.469 19.536 34.081 20.904 ;
     RECT  33.001 113.424 34.165 116.616 ;
     RECT  34.165 113.184 34.229 116.616 ;
     RECT  33.077 53.904 34.333 55.416 ;
     RECT  33.689 56.592 34.333 57.384 ;
     RECT  34.297 110.592 34.405 110.616 ;
     RECT  32.929 111.744 34.405 111.768 ;
     RECT  34.229 113.184 34.451 116.52 ;
     RECT  34.333 53.904 34.513 57.384 ;
     RECT  34.513 53.52 34.621 57.384 ;
     RECT  31.993 92.016 34.621 92.04 ;
     RECT  34.621 52.8 34.657 57.384 ;
     RECT  34.621 92.016 34.693 93 ;
     RECT  33.901 15.984 34.729 16.44 ;
     RECT  34.297 17.616 34.729 17.64 ;
     RECT  34.451 113.184 34.739 115.176 ;
     RECT  34.189 97.92 34.765 97.944 ;
     RECT  34.657 52.512 34.801 57.384 ;
     RECT  33.937 2.784 34.808 2.808 ;
     RECT  34.729 15.984 34.808 17.64 ;
     RECT  34.081 19.536 34.808 21.144 ;
     RECT  33.509 23.52 34.808 23.544 ;
     RECT  33.509 24.768 34.808 30.168 ;
     RECT  33.545 31.152 34.808 51 ;
     RECT  34.801 52.176 34.808 57.384 ;
     RECT  33.901 58.656 34.808 60.888 ;
     RECT  33.827 62.16 34.808 62.184 ;
     RECT  31.421 82.656 34.808 82.68 ;
     RECT  33.541 88.8 34.808 88.92 ;
     RECT  34.693 91.632 34.808 93 ;
     RECT  33.757 94.416 34.808 96.888 ;
     RECT  34.765 97.92 34.808 98.088 ;
     RECT  34.153 100.896 34.808 100.92 ;
     RECT  33.829 102.576 34.808 102.6 ;
     RECT  34.369 104.256 34.808 104.28 ;
     RECT  34.213 106.032 34.808 106.056 ;
     RECT  34.405 110.592 34.808 111.768 ;
     RECT  34.739 113.184 34.808 115.128 ;
     RECT  34.808 2.148 34.912 115.128 ;
     RECT  34.912 2.418 35.104 115.128 ;
     RECT  35.104 113.856 35.165 115.128 ;
     RECT  35.104 91.632 35.219 100.92 ;
     RECT  35.165 113.856 35.219 114.552 ;
     RECT  34.451 116.496 35.219 116.52 ;
     RECT  35.104 60.672 35.237 60.84 ;
     RECT  35.104 18.048 35.267 30.072 ;
     RECT  35.219 92.976 35.267 100.92 ;
     RECT  35.104 56.544 35.309 58.152 ;
     RECT  35.104 2.64 35.315 2.856 ;
     RECT  35.104 31.152 35.363 50.952 ;
     RECT  35.104 59.232 35.363 59.256 ;
     RECT  35.267 92.976 35.381 100.104 ;
     RECT  35.309 56.544 35.417 57.144 ;
     RECT  35.104 64.368 35.417 64.392 ;
     RECT  35.237 60.816 35.525 60.84 ;
     RECT  35.104 85.488 35.561 85.8 ;
     RECT  35.104 51.936 35.597 55.416 ;
     RECT  35.597 51.936 35.603 54.168 ;
     RECT  35.104 82.656 35.603 82.68 ;
     RECT  35.363 31.152 35.669 50.28 ;
     RECT  35.104 89.952 35.699 90.648 ;
     RECT  35.561 85.488 35.747 85.512 ;
     RECT  35.309 58.128 35.795 58.152 ;
     RECT  35.669 46.272 35.813 50.28 ;
     RECT  35.104 88.608 35.921 88.92 ;
     RECT  35.381 93.504 35.987 100.104 ;
     RECT  35.104 16.032 36.133 16.92 ;
     RECT  35.267 18.048 36.133 25.464 ;
     RECT  35.267 26.544 36.205 30.072 ;
     RECT  35.669 31.152 36.205 45.192 ;
     RECT  35.603 51.936 36.209 52.056 ;
     RECT  35.104 11.136 36.373 11.16 ;
     RECT  35.813 46.608 36.385 50.28 ;
     RECT  35.104 7.872 36.421 7.896 ;
     RECT  36.385 46.608 36.421 50.472 ;
     RECT  35.219 91.632 36.421 91.656 ;
     RECT  36.421 91.2 36.461 91.656 ;
     RECT  36.421 46.608 36.493 50.52 ;
     RECT  36.373 10.464 36.517 11.16 ;
     RECT  35.603 53.136 36.565 54.168 ;
     RECT  36.205 26.544 36.569 45.192 ;
     RECT  35.417 56.544 36.601 56.664 ;
     RECT  35.104 75.456 36.605 75.48 ;
     RECT  36.493 46.608 36.637 50.712 ;
     RECT  35.597 55.152 36.661 55.416 ;
     RECT  36.601 56.544 36.661 57 ;
     RECT  36.601 78.528 36.707 78.552 ;
     RECT  36.637 46.608 36.709 50.856 ;
     RECT  35.699 89.952 36.709 89.976 ;
     RECT  36.661 55.152 36.713 57 ;
     RECT  36.565 53.088 36.781 54.168 ;
     RECT  36.709 89.952 36.781 90.072 ;
     RECT  36.461 91.2 36.781 91.224 ;
     RECT  36.709 86.64 36.821 86.664 ;
     RECT  36.781 89.952 36.893 91.224 ;
     RECT  36.889 75.264 36.947 75.288 ;
     RECT  36.893 89.952 36.947 90.456 ;
     RECT  36.569 32.112 37.069 45.192 ;
     RECT  36.709 46.608 37.069 50.952 ;
     RECT  36.133 16.032 37.093 25.464 ;
     RECT  36.569 26.544 37.093 30.936 ;
     RECT  36.781 52.176 37.105 54.168 ;
     RECT  36.713 55.152 37.105 56.664 ;
     RECT  35.987 93.504 37.105 98.712 ;
     RECT  35.987 99.696 37.105 100.104 ;
     RECT  37.105 93.504 37.141 100.104 ;
     RECT  36.947 89.952 37.145 90.072 ;
     RECT  37.069 32.112 37.213 50.952 ;
     RECT  36.901 103.584 37.249 103.608 ;
     RECT  37.105 52.176 37.289 56.664 ;
     RECT  37.289 52.176 37.333 56.232 ;
     RECT  37.249 103.584 37.427 103.752 ;
     RECT  37.213 32.112 37.465 51 ;
     RECT  37.333 52.08 37.465 56.232 ;
     RECT  37.093 16.032 37.609 30.936 ;
     RECT  37.141 92.832 37.621 100.104 ;
     RECT  36.901 65.232 37.721 65.256 ;
     RECT  37.465 32.112 37.757 56.232 ;
     RECT  35.104 13.008 37.813 13.032 ;
     RECT  37.427 103.584 37.957 103.608 ;
     RECT  37.621 92.544 37.973 100.104 ;
     RECT  37.609 16.032 38.041 30.984 ;
     RECT  37.757 32.112 38.041 52.488 ;
     RECT  37.973 93.504 38.225 100.104 ;
     RECT  37.333 14.976 38.245 15 ;
     RECT  38.149 92.496 38.261 92.52 ;
     RECT  37.813 13.008 38.341 13.08 ;
     RECT  38.341 12.816 38.437 13.08 ;
     RECT  38.041 16.032 38.585 52.488 ;
     RECT  36.517 10.08 38.773 11.16 ;
     RECT  38.437 12.24 38.773 13.08 ;
     RECT  38.581 64.992 38.801 65.016 ;
     RECT  38.225 99.456 38.869 100.104 ;
     RECT  37.757 53.568 38.905 56.232 ;
     RECT  38.585 16.032 38.909 51.912 ;
     RECT  35.315 2.64 38.917 2.664 ;
     RECT  38.773 10.08 38.965 13.08 ;
     RECT  38.245 14.16 38.965 15 ;
     RECT  38.101 84.816 39.013 84.84 ;
     RECT  38.677 89.952 39.013 89.976 ;
     RECT  38.225 93.504 39.013 98.472 ;
     RECT  39.013 84.816 39.059 84.936 ;
     RECT  39.013 89.952 39.107 90.072 ;
     RECT  37.957 103.344 39.109 103.608 ;
     RECT  39.013 107.856 39.301 107.88 ;
     RECT  38.905 52.896 39.337 56.232 ;
     RECT  39.013 93.456 39.349 98.472 ;
     RECT  38.909 24.624 39.683 51.912 ;
     RECT  39.109 103.344 39.685 103.896 ;
     RECT  39.683 48.912 39.731 51.912 ;
     RECT  39.731 49.008 39.733 51.912 ;
     RECT  39.337 52.896 39.733 56.328 ;
     RECT  39.265 81.792 39.733 81.816 ;
     RECT  39.733 49.008 39.737 56.328 ;
     RECT  39.737 49.296 39.779 56.328 ;
     RECT  39.013 61.584 39.805 61.608 ;
     RECT  39.805 61.488 39.841 61.608 ;
     RECT  37.957 58.656 39.913 58.68 ;
     RECT  39.193 59.808 39.913 59.832 ;
     RECT  39.349 93.408 39.913 98.472 ;
     RECT  35.921 88.608 39.925 88.632 ;
     RECT  36.229 102.24 39.925 102.264 ;
     RECT  39.779 50.208 39.953 56.328 ;
     RECT  39.913 58.656 39.973 59.832 ;
     RECT  39.841 61.392 39.973 61.608 ;
     RECT  38.909 16.032 40.021 23.544 ;
     RECT  39.683 24.624 40.021 47.928 ;
     RECT  39.973 58.656 40.025 62.136 ;
     RECT  39.913 92.928 40.069 98.472 ;
     RECT  38.869 99.456 40.069 100.296 ;
     RECT  39.925 101.76 40.069 102.264 ;
     RECT  40.021 16.032 40.097 47.928 ;
     RECT  38.509 1.44 40.208 1.464 ;
     RECT  38.917 2.64 40.208 3.336 ;
     RECT  38.197 4.368 40.208 4.392 ;
     RECT  35.104 6.576 40.208 6.6 ;
     RECT  36.421 7.872 40.208 8.52 ;
     RECT  38.965 10.08 40.208 15 ;
     RECT  40.097 16.032 40.208 46.68 ;
     RECT  39.049 74.448 40.208 74.472 ;
     RECT  39.733 81.504 40.208 81.816 ;
     RECT  39.059 84.816 40.208 84.84 ;
     RECT  39.925 88.416 40.208 88.632 ;
     RECT  39.107 89.952 40.208 89.976 ;
     RECT  40.069 92.928 40.208 100.296 ;
     RECT  40.069 101.664 40.208 102.264 ;
     RECT  39.685 103.296 40.208 103.896 ;
     RECT  39.637 105.744 40.208 105.768 ;
     RECT  39.301 107.856 40.208 107.928 ;
     RECT  39.157 109.536 40.208 109.56 ;
     RECT  40.069 110.88 40.208 110.904 ;
     RECT  39.973 111.888 40.208 111.912 ;
     RECT  39.445 113.52 40.208 113.544 ;
     RECT  35.219 114.528 40.208 114.552 ;
     RECT  40.208 1.44 40.312 46.68 ;
     RECT  39.953 50.208 40.312 51 ;
     RECT  40.208 64.788 40.312 114.552 ;
     RECT  40.312 1.44 40.504 23.64 ;
     RECT  40.312 94.08 40.504 114.552 ;
     RECT  40.025 58.656 40.597 61.608 ;
     RECT  40.504 111.888 40.601 112.008 ;
     RECT  40.312 24.624 40.787 46.68 ;
     RECT  39.953 51.984 40.789 56.328 ;
     RECT  40.312 50.256 41.137 51 ;
     RECT  40.789 51.984 41.137 56.424 ;
     RECT  40.208 63.168 41.137 63.192 ;
     RECT  40.633 64.176 41.137 64.296 ;
     RECT  40.597 58.128 41.173 61.608 ;
     RECT  41.173 57.744 41.209 61.608 ;
     RECT  41.137 63.168 41.209 64.296 ;
     RECT  41.137 50.256 41.245 56.424 ;
     RECT  41.209 57.648 41.245 61.608 ;
     RECT  41.209 62.832 41.245 64.296 ;
     RECT  40.504 16.032 41.413 23.64 ;
     RECT  40.787 24.624 41.413 46.248 ;
     RECT  40.504 1.44 41.425 1.464 ;
     RECT  40.504 7.632 41.509 8.712 ;
     RECT  40.504 10.032 41.509 15.048 ;
     RECT  41.245 50.256 41.749 61.608 ;
     RECT  41.245 62.736 41.749 64.296 ;
     RECT  40.601 111.984 41.893 112.008 ;
     RECT  40.504 107.856 41.941 107.928 ;
     RECT  41.413 16.032 42.109 46.248 ;
     RECT  40.504 94.08 42.227 103.896 ;
     RECT  42.109 16.032 42.336 46.344 ;
     RECT  40.097 47.904 42.336 47.928 ;
     RECT  41.749 50.256 42.336 64.296 ;
     RECT  41.425 0.864 42.397 1.464 ;
     RECT  42.336 16.032 42.408 64.296 ;
     RECT  42.227 94.08 42.408 99.96 ;
     RECT  40.504 4.368 42.517 4.392 ;
     RECT  40.504 5.472 42.517 6.6 ;
     RECT  42.517 4.368 42.661 6.6 ;
     RECT  41.509 7.632 42.661 15.048 ;
     RECT  42.661 4.368 42.757 15.048 ;
     RECT  42.408 16.032 42.757 99.96 ;
     RECT  40.504 113.52 42.853 113.544 ;
     RECT  41.893 111.936 42.949 112.008 ;
     RECT  42.853 113.04 42.949 113.544 ;
     RECT  40.504 114.528 44.557 114.552 ;
     RECT  42.397 0.048 45.608 1.464 ;
     RECT  40.504 2.64 45.608 3.336 ;
     RECT  42.757 4.368 45.608 99.96 ;
     RECT  42.227 101.328 45.608 103.896 ;
     RECT  40.504 105.744 45.608 105.768 ;
     RECT  40.504 106.848 45.608 106.872 ;
     RECT  41.941 107.856 45.608 108.504 ;
     RECT  40.504 109.536 45.608 109.56 ;
     RECT  40.504 110.88 45.608 110.904 ;
     RECT  42.949 111.936 45.608 113.544 ;
     RECT  44.557 114.528 45.608 115.416 ;
     RECT  45.608 0.048 45.904 115.416 ;
     RECT  45.904 0.048 51.008 1.464 ;
     RECT  45.904 2.64 51.008 3.336 ;
     RECT  45.904 4.368 51.008 15.048 ;
     RECT  45.904 16.128 51.008 99.96 ;
     RECT  45.904 101.328 51.008 103.896 ;
     RECT  45.904 105.744 51.008 105.768 ;
     RECT  45.904 106.848 51.008 106.872 ;
     RECT  45.904 107.856 51.008 108.504 ;
     RECT  45.904 109.536 51.008 109.56 ;
     RECT  45.904 110.88 51.008 110.904 ;
     RECT  45.904 111.936 51.008 113.544 ;
     RECT  45.904 114.528 51.008 115.416 ;
     RECT  51.008 0.048 51.304 115.416 ;
     RECT  51.304 16.128 53.449 99.96 ;
     RECT  51.304 106.848 53.605 106.872 ;
     RECT  51.304 107.856 53.605 108.504 ;
     RECT  51.304 101.328 53.651 103.896 ;
     RECT  53.449 16.128 54.065 100.056 ;
     RECT  54.065 16.128 55.333 99.96 ;
     RECT  55.333 16.128 55.397 100.488 ;
     RECT  51.304 0.048 56.408 1.464 ;
     RECT  51.304 2.64 56.408 3.336 ;
     RECT  51.304 4.368 56.408 15.048 ;
     RECT  55.397 16.128 56.408 99.96 ;
     RECT  53.651 101.568 56.408 103.896 ;
     RECT  51.304 105.744 56.408 105.768 ;
     RECT  53.605 106.848 56.408 108.504 ;
     RECT  51.304 109.536 56.408 109.56 ;
     RECT  51.304 110.88 56.408 110.904 ;
     RECT  51.304 111.936 56.408 113.544 ;
     RECT  51.304 114.528 56.408 115.416 ;
     RECT  56.408 0.048 56.704 115.416 ;
     RECT  56.704 106.848 57.629 108.504 ;
     RECT  56.704 111.936 58.165 113.544 ;
     RECT  56.704 114.528 58.165 115.416 ;
     RECT  56.704 105.744 60.109 105.768 ;
     RECT  57.629 106.848 60.109 106.872 ;
     RECT  60.109 105.744 60.179 106.872 ;
     RECT  56.704 0.048 61.808 1.464 ;
     RECT  56.704 2.64 61.808 3.336 ;
     RECT  56.704 4.368 61.808 15.048 ;
     RECT  56.704 16.128 61.808 99.96 ;
     RECT  56.704 101.568 61.808 103.896 ;
     RECT  60.179 105.744 61.808 105.768 ;
     RECT  60.179 106.848 61.808 106.872 ;
     RECT  57.629 107.856 61.808 108.504 ;
     RECT  56.704 109.536 61.808 109.56 ;
     RECT  56.704 110.88 61.808 110.904 ;
     RECT  58.165 111.936 61.808 115.416 ;
     RECT  61.808 0.048 62.104 115.416 ;
     RECT  62.104 101.568 62.741 103.896 ;
     RECT  62.104 106.752 62.741 106.872 ;
     RECT  62.741 106.752 64.609 106.776 ;
     RECT  62.104 107.856 64.609 108.504 ;
     RECT  62.104 110.88 64.789 110.904 ;
     RECT  62.104 105.744 65.041 105.768 ;
     RECT  65.041 105.6 65.113 105.768 ;
     RECT  64.609 106.752 65.113 108.504 ;
     RECT  62.741 101.568 65.269 103.848 ;
     RECT  65.113 105.6 65.269 108.504 ;
     RECT  65.269 101.568 65.333 108.504 ;
     RECT  62.104 16.128 65.509 99.96 ;
     RECT  65.333 105.456 65.545 108.504 ;
     RECT  62.104 109.536 65.545 109.56 ;
     RECT  65.545 105.456 65.797 109.56 ;
     RECT  64.789 110.784 65.797 110.904 ;
     RECT  65.333 101.568 66.121 104.28 ;
     RECT  66.121 101.52 66.179 104.28 ;
     RECT  65.509 16.128 66.197 100.104 ;
     RECT  66.179 101.712 66.301 104.28 ;
     RECT  65.797 105.456 66.301 110.904 ;
     RECT  66.301 101.712 66.661 110.904 ;
     RECT  62.104 111.936 66.661 115.416 ;
     RECT  66.197 16.128 66.709 100.056 ;
     RECT  66.709 16.08 67.201 100.056 ;
     RECT  62.104 0.048 67.208 1.464 ;
     RECT  62.104 2.64 67.208 3.336 ;
     RECT  62.104 4.368 67.208 15.048 ;
     RECT  67.201 16.08 67.208 100.536 ;
     RECT  66.661 101.712 67.208 115.416 ;
     RECT  67.208 0.048 67.504 115.416 ;
     RECT  67.504 16.08 68.609 115.416 ;
     RECT  68.609 16.128 70.835 115.416 ;
     RECT  70.835 16.128 72.097 105.72 ;
     RECT  70.835 106.848 72.097 115.416 ;
     RECT  67.504 0.048 72.608 1.464 ;
     RECT  67.504 2.64 72.608 3.336 ;
     RECT  67.504 4.368 72.608 15.048 ;
     RECT  72.097 16.128 72.608 115.416 ;
     RECT  72.608 0.048 72.904 115.416 ;
     RECT  72.904 0.048 78.008 1.464 ;
     RECT  72.904 2.64 78.008 3.336 ;
     RECT  72.904 4.368 78.008 15.048 ;
     RECT  72.904 16.128 78.008 115.416 ;
     RECT  78.008 0.048 78.304 115.416 ;
     RECT  78.304 0.048 83.408 1.464 ;
     RECT  78.304 2.64 83.408 3.336 ;
     RECT  78.304 4.368 83.408 15.048 ;
     RECT  78.304 16.128 83.408 115.416 ;
     RECT  83.408 0.048 83.704 115.416 ;
     RECT  83.704 4.368 84.083 115.416 ;
     RECT  84.083 4.368 85.597 106.248 ;
     RECT  84.083 107.28 85.597 115.416 ;
     RECT  83.704 2.64 87.253 3.336 ;
     RECT  85.597 4.368 87.253 115.416 ;
     RECT  83.704 0.048 88.808 1.464 ;
     RECT  87.253 2.64 88.808 115.416 ;
     RECT  88.808 0.048 89.104 115.416 ;
     RECT  89.104 2.64 89.201 3.672 ;
     RECT  89.104 4.704 89.939 115.416 ;
     RECT  89.201 2.64 91.861 3.576 ;
     RECT  89.939 96 92.225 115.416 ;
     RECT  92.225 96.336 92.405 115.416 ;
     RECT  92.405 96.336 94.057 104.664 ;
     RECT  92.405 105.696 94.057 115.416 ;
     RECT  89.104 0.048 94.208 1.464 ;
     RECT  91.861 2.64 94.208 3.624 ;
     RECT  89.939 4.704 94.208 94.872 ;
     RECT  94.208 0.048 94.504 94.872 ;
     RECT  94.504 0.048 95.713 1.464 ;
     RECT  94.504 2.64 96.289 3.624 ;
     RECT  94.504 4.704 96.289 94.872 ;
     RECT  94.057 96.336 99.301 115.416 ;
     RECT  95.713 0.048 99.608 1.512 ;
     RECT  96.289 2.64 99.608 94.872 ;
     RECT  99.608 0.048 99.904 94.872 ;
     RECT  99.301 96.336 100.069 116.232 ;
     RECT  100.069 96.336 100.165 116.424 ;
     RECT  100.165 96.336 100.289 116.52 ;
     RECT  100.289 96.336 100.307 116.472 ;
     RECT  99.904 2.64 100.397 94.872 ;
     RECT  100.307 116.4 100.883 116.472 ;
     RECT  100.883 116.448 101.219 116.472 ;
     RECT  100.397 4.704 101.507 94.872 ;
     RECT  100.307 96.336 101.747 115.416 ;
     RECT  99.904 0.048 105.008 1.512 ;
     RECT  100.397 2.64 105.008 3.576 ;
     RECT  101.507 4.704 105.008 94.248 ;
     RECT  101.747 96.384 105.2 115.416 ;
     RECT  105.008 0.048 105.304 94.248 ;
     RECT  105.2 96.378 105.304 115.416 ;
     RECT  105.304 0.048 105.587 1.512 ;
     RECT  105.587 0.096 105.875 1.512 ;
     RECT  105.875 0.192 105.971 1.512 ;
     RECT  105.971 0.288 106.501 1.512 ;
     RECT  105.304 2.64 106.501 3.336 ;
     RECT  106.501 0.288 106.739 3.336 ;
     RECT  105.304 4.704 107.489 94.248 ;
     RECT  106.739 0.816 107.749 3.336 ;
     RECT  107.489 7.44 107.813 94.248 ;
     RECT  107.813 7.68 108.533 94.248 ;
     RECT  107.489 4.704 108.565 6.168 ;
     RECT  108.533 16.512 108.677 94.248 ;
     RECT  107.749 0.096 108.851 3.336 ;
     RECT  108.565 4.512 108.853 6.168 ;
     RECT  108.533 7.68 108.893 15.384 ;
     RECT  108.853 4.512 108.899 6.264 ;
     RECT  108.677 16.896 109.073 94.248 ;
     RECT  105.304 96.384 109.505 115.416 ;
     RECT  108.899 4.704 109.717 6.264 ;
     RECT  108.893 7.68 109.717 15.336 ;
     RECT  109.717 4.704 109.933 15.336 ;
     RECT  108.851 0.48 110.099 3.336 ;
     RECT  110.099 0.576 110.297 3.336 ;
     RECT  110.297 0.816 110.408 3.336 ;
     RECT  109.933 4.704 110.408 15.432 ;
     RECT  109.073 17.856 110.408 94.248 ;
     RECT  109.505 96.48 110.6 115.416 ;
     RECT  110.408 0.816 110.704 94.248 ;
     RECT  110.6 96.378 110.704 115.416 ;
     RECT  110.704 4.704 110.837 10.872 ;
     RECT  110.837 8.736 110.915 10.872 ;
     RECT  110.915 9.696 110.945 10.872 ;
     RECT  110.837 4.704 111.011 7.704 ;
     RECT  110.945 9.696 111.011 10.44 ;
     RECT  110.704 0.816 111.373 3.336 ;
     RECT  111.373 0.528 111.443 3.336 ;
     RECT  110.704 13.392 111.665 14.952 ;
     RECT  111.665 13.44 111.845 14.952 ;
     RECT  111.011 10.128 111.925 10.44 ;
     RECT  111.845 13.68 111.953 14.952 ;
     RECT  111.913 9.072 111.971 9.096 ;
     RECT  111.953 14.928 112.061 14.952 ;
     RECT  111.925 10.128 112.273 10.872 ;
     RECT  112.273 10.128 112.355 11.544 ;
     RECT  111.443 0.576 112.525 3.336 ;
     RECT  111.953 13.68 112.637 13.704 ;
     RECT  112.355 10.128 112.849 11.4 ;
     RECT  112.849 9.936 112.931 11.4 ;
     RECT  112.931 10.128 113.825 11.4 ;
     RECT  113.825 11.232 114.617 11.4 ;
     RECT  114.617 11.232 115.477 11.256 ;
     RECT  112.525 0.048 115.808 3.336 ;
     RECT  111.011 4.704 115.808 6.168 ;
     RECT  111.011 7.68 115.808 7.704 ;
     RECT  113.825 10.128 115.808 10.152 ;
     RECT  115.477 11.136 115.808 11.256 ;
     RECT  110.704 17.856 115.808 94.248 ;
     RECT  115.808 0.048 115.912 94.248 ;
     RECT  110.704 96.48 116 115.416 ;
     RECT  115.912 2.418 116.104 94.248 ;
     RECT  116 96.378 116.104 115.416 ;
     RECT  115.912 0.048 117.529 1.416 ;
     RECT  116.104 2.64 117.529 2.664 ;
     RECT  117.529 0.048 117.709 2.664 ;
     RECT  116.104 4.704 117.709 6.168 ;
     RECT  117.709 0.048 117.889 3.096 ;
     RECT  117.709 4.272 117.889 6.168 ;
     RECT  117.889 0.048 118.019 6.168 ;
     RECT  118.019 4.512 118.259 6.168 ;
     RECT  118.259 4.56 118.547 6.168 ;
     RECT  118.019 0.048 118.613 3.432 ;
     RECT  118.547 4.608 118.717 6.168 ;
     RECT  116.104 7.68 118.717 7.704 ;
     RECT  118.717 4.608 119.329 7.704 ;
     RECT  119.329 4.608 119.653 7.8 ;
     RECT  119.653 4.608 119.689 8.424 ;
     RECT  116.104 11.136 119.689 11.256 ;
     RECT  116.104 10.128 119.701 10.152 ;
     RECT  119.689 11.136 119.701 11.304 ;
     RECT  119.113 12.528 119.729 12.552 ;
     RECT  119.689 4.512 119.747 8.424 ;
     RECT  119.747 4.704 119.749 8.424 ;
     RECT  119.701 10.128 119.981 11.304 ;
     RECT  119.981 10.128 120.037 10.152 ;
     RECT  119.749 4.704 120.229 8.568 ;
     RECT  120.037 9.696 120.229 10.152 ;
     RECT  118.613 0.048 120.661 3.096 ;
     RECT  120.661 0.048 120.709 3.336 ;
     RECT  120.229 4.704 120.709 10.152 ;
     RECT  119.981 11.136 120.709 11.304 ;
     RECT  120.625 15.984 120.805 16.008 ;
     RECT  120.709 0.048 121.093 10.152 ;
     RECT  120.709 11.136 121.093 11.448 ;
     RECT  121.093 0.048 121.208 11.448 ;
     RECT  120.805 15.216 121.208 16.008 ;
     RECT  116.104 17.856 121.208 94.248 ;
     RECT  116.104 96.48 121.4 115.416 ;
     RECT  121.208 0.048 121.504 94.248 ;
     RECT  121.4 96.378 121.504 115.416 ;
     RECT  121.504 96.48 121.763 115.416 ;
     RECT  121.504 15.216 121.907 15.24 ;
     RECT  121.504 0.048 122.003 7.704 ;
     RECT  121.504 13.296 122.003 14.136 ;
     RECT  121.504 11.376 122.321 11.976 ;
     RECT  121.504 17.856 122.573 94.248 ;
     RECT  122.003 0.048 122.771 6.264 ;
     RECT  122.003 7.68 123.493 7.704 ;
     RECT  121.504 9.504 123.493 10.152 ;
     RECT  123.493 7.68 123.539 10.152 ;
     RECT  122.771 4.704 123.725 6.264 ;
     RECT  121.763 96.768 123.833 115.416 ;
     RECT  123.833 96.816 124.261 115.416 ;
     RECT  122.771 0.048 124.445 3.72 ;
     RECT  122.003 14.112 124.501 14.136 ;
     RECT  122.321 11.376 124.547 11.4 ;
     RECT  124.261 96.816 124.597 115.752 ;
     RECT  123.539 7.68 124.739 9.144 ;
     RECT  124.739 7.68 124.765 7.704 ;
     RECT  123.725 4.704 124.769 6.168 ;
     RECT  124.769 4.704 124.913 6.024 ;
     RECT  124.913 4.704 125.021 5.88 ;
     RECT  123.539 10.128 125.237 10.152 ;
     RECT  124.501 13.68 125.237 14.136 ;
     RECT  124.445 0.048 125.449 3.48 ;
     RECT  125.521 14.784 125.603 14.808 ;
     RECT  124.597 96.816 125.795 116.616 ;
     RECT  125.557 16.272 125.893 16.296 ;
     RECT  125.021 4.944 125.917 5.88 ;
     RECT  124.765 7.536 125.917 7.704 ;
     RECT  125.795 96.816 125.939 115.32 ;
     RECT  125.449 0.048 126.421 3.768 ;
     RECT  125.917 4.944 126.421 6.264 ;
     RECT  125.917 7.44 126.421 7.704 ;
     RECT  126.421 0.048 126.608 7.704 ;
     RECT  124.739 9.12 126.608 9.144 ;
     RECT  125.237 13.68 126.608 13.704 ;
     RECT  125.893 16.272 126.608 16.44 ;
     RECT  122.573 17.952 126.608 94.248 ;
     RECT  125.939 96.816 126.608 114.696 ;
     RECT  126.608 96.648 126.611 114.696 ;
     RECT  126.611 96.648 126.8 114.648 ;
     RECT  126.608 0.048 126.904 94.248 ;
     RECT  126.8 96.378 126.904 114.648 ;
     RECT  126.904 16.272 127.073 94.248 ;
     RECT  126.904 0.048 127.091 7.608 ;
     RECT  127.091 7.488 127.109 7.608 ;
     RECT  125.795 116.448 127.141 116.616 ;
     RECT  127.073 16.272 127.187 16.536 ;
     RECT  126.904 96.816 127.187 114.648 ;
     RECT  127.073 17.952 127.253 94.248 ;
     RECT  127.109 7.488 127.325 7.512 ;
     RECT  127.141 116.256 127.333 116.616 ;
     RECT  126.904 13.68 127.379 13.704 ;
     RECT  126.904 10.752 127.433 11.16 ;
     RECT  127.333 116.16 127.537 116.616 ;
     RECT  127.091 0.048 127.571 6.36 ;
     RECT  127.571 2.304 127.649 6.36 ;
     RECT  127.537 116.112 127.667 116.616 ;
     RECT  127.253 18.192 127.829 94.248 ;
     RECT  127.649 2.304 127.865 6.312 ;
     RECT  127.571 0.048 127.955 0.888 ;
     RECT  127.433 11.136 127.973 11.16 ;
     RECT  127.667 116.496 128.147 116.616 ;
     RECT  127.187 96.816 128.153 114.552 ;
     RECT  127.865 3.12 128.369 6.312 ;
     RECT  128.369 3.312 128.441 6.312 ;
     RECT  128.617 10.8 128.675 10.824 ;
     RECT  128.153 96.816 128.801 114.456 ;
     RECT  128.441 3.36 128.819 6.312 ;
     RECT  128.819 3.36 128.873 6.024 ;
     RECT  128.873 5.04 128.945 6.024 ;
     RECT  127.955 0.096 128.977 0.888 ;
     RECT  128.977 0.096 129.011 1.848 ;
     RECT  128.873 3.36 129.017 4.008 ;
     RECT  129.017 3.36 129.053 3.72 ;
     RECT  129.011 0.576 129.085 1.848 ;
     RECT  129.053 3.36 129.233 3.528 ;
     RECT  126.904 9.648 129.301 9.672 ;
     RECT  128.945 5.472 129.305 6.024 ;
     RECT  129.085 0.576 129.589 2.28 ;
     RECT  129.589 0.576 129.683 3.048 ;
     RECT  129.301 9.264 129.769 9.672 ;
     RECT  128.147 116.544 129.805 116.616 ;
     RECT  128.801 96.816 129.925 114.168 ;
     RECT  129.925 96.816 129.989 114.36 ;
     RECT  129.989 97.584 130.061 114.36 ;
     RECT  129.683 0.864 130.201 3.048 ;
     RECT  129.305 6 130.345 6.024 ;
     RECT  130.345 5.664 130.403 6.024 ;
     RECT  130.201 0.864 130.525 3.336 ;
     RECT  130.417 4.56 130.525 4.584 ;
     RECT  127.187 16.272 130.565 16.296 ;
     RECT  127.829 18.672 130.741 94.248 ;
     RECT  130.061 97.68 130.931 114.36 ;
     RECT  130.931 105.36 130.993 114.36 ;
     RECT  130.525 0.864 131.033 4.584 ;
     RECT  130.931 97.68 131.425 103.944 ;
     RECT  131.425 97.632 131.461 103.944 ;
     RECT  131.033 0.864 131.501 0.888 ;
     RECT  130.993 105.36 131.797 114.84 ;
     RECT  131.033 2.544 132.008 3.864 ;
     RECT  130.403 6 132.008 6.024 ;
     RECT  128.725 7.872 132.008 7.896 ;
     RECT  129.769 9.264 132.008 9.816 ;
     RECT  130.357 11.136 132.008 11.16 ;
     RECT  130.705 16.368 132.008 16.392 ;
     RECT  130.741 18.672 132.008 95.112 ;
     RECT  131.461 97.536 132.008 103.944 ;
     RECT  131.797 105.36 132.008 115.416 ;
     RECT  132.008 2.148 132.112 95.112 ;
     RECT  132.008 96.648 132.2 115.416 ;
     RECT  132.112 2.418 132.304 95.112 ;
     RECT  132.2 96.378 132.304 115.416 ;
     RECT  132.304 97.44 132.509 115.416 ;
     RECT  132.509 97.44 133.091 104.04 ;
     RECT  132.304 2.88 133.333 3.864 ;
     RECT  133.333 2.496 133.441 3.864 ;
     RECT  132.304 6 133.441 6.024 ;
     RECT  133.091 97.44 133.441 102.744 ;
     RECT  132.304 16.368 133.573 16.392 ;
     RECT  132.304 11.136 133.585 11.16 ;
     RECT  133.091 103.728 133.621 104.04 ;
     RECT  132.304 9.264 133.667 9.816 ;
     RECT  133.585 11.136 133.765 11.688 ;
     RECT  132.304 18.672 133.813 95.112 ;
     RECT  133.621 103.728 134.005 104.232 ;
     RECT  132.509 105.36 134.005 115.416 ;
     RECT  134.005 103.728 134.057 115.416 ;
     RECT  133.441 97.104 134.389 102.744 ;
     RECT  133.441 2.496 134.485 6.264 ;
     RECT  133.573 16.368 134.525 16.824 ;
     RECT  134.389 96.432 134.629 102.744 ;
     RECT  134.057 103.728 134.629 104.232 ;
     RECT  134.485 2.496 134.633 6.408 ;
     RECT  134.629 96.432 135.589 104.232 ;
     RECT  134.057 105.36 135.589 115.416 ;
     RECT  134.633 2.496 135.709 3.096 ;
     RECT  134.633 4.128 135.709 6.408 ;
     RECT  132.304 7.872 136.069 7.896 ;
     RECT  135.709 2.496 136.307 6.408 ;
     RECT  129.805 116.496 137.041 116.616 ;
     RECT  136.307 2.496 137.408 3.096 ;
     RECT  136.307 4.128 137.408 6.408 ;
     RECT  136.069 7.872 137.408 7.944 ;
     RECT  133.667 9.792 137.408 9.816 ;
     RECT  133.765 11.136 137.408 12.216 ;
     RECT  134.525 16.512 137.408 16.824 ;
     RECT  133.813 17.856 137.408 95.112 ;
     RECT  137.408 2.148 137.512 95.112 ;
     RECT  135.589 96.432 137.6 115.416 ;
     RECT  137.512 2.418 137.704 95.112 ;
     RECT  137.6 96.378 137.704 115.416 ;
     RECT  137.704 96.432 137.869 115.416 ;
     RECT  137.704 11.136 137.987 12.216 ;
     RECT  137.704 14.112 138.515 14.856 ;
     RECT  137.704 2.496 138.557 6.408 ;
     RECT  137.869 96.432 140.053 115.464 ;
     RECT  137.041 116.448 140.053 116.616 ;
     RECT  138.557 2.496 142.453 6.312 ;
     RECT  142.453 2.496 142.808 6.408 ;
     RECT  137.704 7.872 142.808 7.944 ;
     RECT  137.704 9.792 142.808 9.816 ;
     RECT  137.987 11.136 142.808 11.16 ;
     RECT  137.987 12.192 142.808 12.216 ;
     RECT  138.515 14.112 142.808 14.136 ;
     RECT  138.697 15.456 142.808 15.48 ;
     RECT  137.704 16.512 142.808 16.824 ;
     RECT  137.704 17.856 142.808 95.112 ;
     RECT  142.808 2.148 142.912 95.112 ;
     RECT  140.053 96.432 143 116.616 ;
     RECT  142.912 2.418 143.104 95.112 ;
     RECT  143 96.378 143.104 116.616 ;
     RECT  143.104 14.112 143.273 16.824 ;
     RECT  143.104 17.856 144.029 95.112 ;
     RECT  143.104 2.496 144.745 6.408 ;
     RECT  144.029 19.248 144.965 95.112 ;
     RECT  143.273 14.64 145.573 16.824 ;
     RECT  144.029 17.856 145.573 17.88 ;
     RECT  145.573 14.64 145.901 17.88 ;
     RECT  145.901 14.64 147.049 16.824 ;
     RECT  145.901 17.856 147.049 17.88 ;
     RECT  144.745 2.496 148.208 6.552 ;
     RECT  143.104 7.872 148.208 7.944 ;
     RECT  143.104 9.792 148.208 9.816 ;
     RECT  143.104 11.136 148.208 11.16 ;
     RECT  143.104 12.192 148.208 12.216 ;
     RECT  147.049 14.64 148.208 17.88 ;
     RECT  144.965 19.488 148.208 95.112 ;
     RECT  148.208 2.148 148.312 95.112 ;
     RECT  143.104 96.432 148.4 116.616 ;
     RECT  148.312 2.418 148.504 95.112 ;
     RECT  148.4 96.378 148.504 116.616 ;
     RECT  148.504 2.496 149.075 6.552 ;
     RECT  149.075 2.496 151.481 4.488 ;
     RECT  148.504 96.432 152.345 116.616 ;
     RECT  151.481 2.496 152.449 4.44 ;
     RECT  152.345 96.432 153.313 100.056 ;
     RECT  152.345 101.28 153.313 116.616 ;
     RECT  152.449 2.496 153.608 4.488 ;
     RECT  149.075 5.472 153.608 6.552 ;
     RECT  148.504 7.872 153.608 7.944 ;
     RECT  148.504 9.792 153.608 9.816 ;
     RECT  148.504 11.136 153.608 11.16 ;
     RECT  148.504 12.192 153.608 12.216 ;
     RECT  148.504 14.64 153.608 17.88 ;
     RECT  148.504 19.488 153.608 95.112 ;
     RECT  153.608 2.148 153.712 95.112 ;
     RECT  153.313 96.432 153.8 116.616 ;
     RECT  153.712 2.418 153.904 95.112 ;
     RECT  153.8 96.378 153.904 116.616 ;
     RECT  153.904 96.432 153.965 100.344 ;
     RECT  153.965 100.032 154.073 100.344 ;
     RECT  153.904 101.952 154.109 109.464 ;
     RECT  153.965 96.432 154.163 98.472 ;
     RECT  154.109 101.952 154.163 105.144 ;
     RECT  154.109 106.464 154.181 109.464 ;
     RECT  154.163 102.96 154.217 105.144 ;
     RECT  154.181 106.56 154.325 109.464 ;
     RECT  154.217 103.296 154.397 105.144 ;
     RECT  154.397 103.296 154.505 103.704 ;
     RECT  154.073 100.32 154.649 100.344 ;
     RECT  154.325 106.56 154.649 108.6 ;
     RECT  153.904 2.496 157.273 4.488 ;
     RECT  157.273 2.256 157.331 4.488 ;
     RECT  157.331 2.496 157.573 4.488 ;
     RECT  153.904 5.472 157.573 6.552 ;
     RECT  157.573 2.496 158.003 6.552 ;
     RECT  158.003 2.496 159.008 4.488 ;
     RECT  158.003 5.472 159.008 6.552 ;
     RECT  153.904 7.872 159.008 7.944 ;
     RECT  153.904 9.792 159.008 9.816 ;
     RECT  153.904 11.136 159.008 11.16 ;
     RECT  153.904 12.192 159.008 12.216 ;
     RECT  153.904 14.64 159.008 17.88 ;
     RECT  153.904 19.488 159.008 95.112 ;
     RECT  154.163 96.432 159.008 98.376 ;
     RECT  154.163 101.952 159.008 101.976 ;
     RECT  154.505 103.296 159.008 103.32 ;
     RECT  154.397 105.12 159.008 105.144 ;
     RECT  154.649 107.376 159.008 108.6 ;
     RECT  153.904 110.592 159.008 116.616 ;
     RECT  159.008 2.148 159.112 95.112 ;
     RECT  159.008 96.432 159.2 116.616 ;
     RECT  159.112 2.418 159.304 95.112 ;
     RECT  159.2 96.378 159.304 116.616 ;
     RECT  159.304 2.496 164.408 4.488 ;
     RECT  159.304 5.472 164.408 6.552 ;
     RECT  159.304 7.872 164.408 7.944 ;
     RECT  159.304 9.792 164.408 9.816 ;
     RECT  159.304 11.136 164.408 11.16 ;
     RECT  159.304 12.192 164.408 12.216 ;
     RECT  159.304 14.64 164.408 17.88 ;
     RECT  159.304 19.488 164.408 95.112 ;
     RECT  159.304 96.432 164.408 98.376 ;
     RECT  159.304 101.952 164.408 101.976 ;
     RECT  159.304 103.296 164.408 103.32 ;
     RECT  159.304 105.12 164.408 105.144 ;
     RECT  159.304 107.376 164.408 108.6 ;
     RECT  159.304 110.592 164.408 116.616 ;
     RECT  164.408 2.148 164.512 95.112 ;
     RECT  164.408 96.432 164.6 116.616 ;
     RECT  164.512 2.418 164.704 95.112 ;
     RECT  164.6 96.378 164.704 116.616 ;
     RECT  164.704 14.64 166.205 17.88 ;
     RECT  166.205 14.64 167.281 16.536 ;
     RECT  166.205 17.616 167.281 17.88 ;
     RECT  164.704 2.496 169.808 4.488 ;
     RECT  164.704 5.472 169.808 6.552 ;
     RECT  164.704 7.872 169.808 7.944 ;
     RECT  164.704 9.792 169.808 9.816 ;
     RECT  164.704 11.136 169.808 11.16 ;
     RECT  164.704 12.192 169.808 12.216 ;
     RECT  167.281 14.64 169.808 17.88 ;
     RECT  164.704 19.488 169.808 95.112 ;
     RECT  164.704 96.432 169.808 98.376 ;
     RECT  164.704 103.296 169.808 103.32 ;
     RECT  164.704 105.12 169.808 105.144 ;
     RECT  164.704 107.376 169.808 108.6 ;
     RECT  164.704 110.592 169.808 116.616 ;
     RECT  169.808 2.148 169.912 95.112 ;
     RECT  169.808 96.432 170 116.616 ;
     RECT  169.912 2.418 170.104 95.112 ;
     RECT  170 96.378 170.104 116.616 ;
     RECT  170.104 7.872 173.513 7.944 ;
     RECT  170.104 2.496 175.208 4.488 ;
     RECT  170.104 5.472 175.208 6.552 ;
     RECT  173.513 7.92 175.208 7.944 ;
     RECT  170.104 9.792 175.208 9.816 ;
     RECT  170.104 11.136 175.208 11.16 ;
     RECT  170.104 12.192 175.208 12.216 ;
     RECT  170.104 14.64 175.208 17.88 ;
     RECT  170.104 19.488 175.208 95.112 ;
     RECT  170.104 96.432 175.208 98.376 ;
     RECT  170.104 103.296 175.208 103.32 ;
     RECT  170.104 105.12 175.208 105.144 ;
     RECT  170.104 107.376 175.208 108.6 ;
     RECT  170.104 110.592 175.208 116.616 ;
     RECT  175.208 2.148 175.312 95.112 ;
     RECT  175.208 96.432 175.4 116.616 ;
     RECT  175.312 2.418 175.504 95.112 ;
     RECT  175.4 96.378 175.504 116.616 ;
     RECT  175.504 7.872 178.481 7.944 ;
     RECT  178.481 7.872 179.557 7.896 ;
     RECT  175.504 2.496 180.608 4.488 ;
     RECT  175.504 5.472 180.608 6.552 ;
     RECT  179.557 7.872 180.608 7.944 ;
     RECT  175.504 9.792 180.608 9.816 ;
     RECT  175.504 11.136 180.608 11.16 ;
     RECT  175.504 12.192 180.608 12.216 ;
     RECT  175.504 14.64 180.608 17.88 ;
     RECT  175.504 19.488 180.608 95.112 ;
     RECT  175.504 96.432 180.608 98.376 ;
     RECT  175.504 103.296 180.608 103.32 ;
     RECT  175.504 105.12 180.608 105.144 ;
     RECT  175.504 107.376 180.608 108.6 ;
     RECT  175.504 110.592 180.608 116.616 ;
     RECT  180.608 2.148 180.712 95.112 ;
     RECT  180.608 96.432 180.8 116.616 ;
     RECT  180.712 2.418 180.904 95.112 ;
     RECT  180.8 96.378 180.904 116.616 ;
     RECT  180.904 110.592 184.277 116.616 ;
     RECT  184.277 110.592 184.307 116.52 ;
     RECT  184.307 110.592 185.845 116.472 ;
     RECT  180.904 2.496 186.008 4.488 ;
     RECT  180.904 5.472 186.008 6.6 ;
     RECT  180.904 7.872 186.008 7.944 ;
     RECT  180.904 9.792 186.008 9.816 ;
     RECT  180.904 11.136 186.008 11.16 ;
     RECT  180.904 12.192 186.008 12.216 ;
     RECT  180.904 14.64 186.008 17.88 ;
     RECT  180.904 19.488 186.008 95.112 ;
     RECT  180.904 96.432 186.008 98.376 ;
     RECT  180.904 103.296 186.008 103.32 ;
     RECT  180.904 105.12 186.008 105.144 ;
     RECT  180.904 107.376 186.008 108.6 ;
     RECT  185.845 110.592 186.008 116.52 ;
     RECT  186.008 2.148 186.112 95.112 ;
     RECT  186.008 96.432 186.2 116.52 ;
     RECT  186.2 96.378 186.227 116.52 ;
     RECT  186.112 2.418 186.304 95.112 ;
     RECT  186.227 96.378 186.304 116.472 ;
     RECT  186.304 110.592 187.475 116.472 ;
     RECT  187.475 116.256 187.621 116.472 ;
     RECT  187.475 110.592 187.955 115.08 ;
     RECT  187.621 116.256 188.057 116.52 ;
     RECT  188.057 116.256 188.243 116.376 ;
     RECT  187.955 110.592 188.339 114.648 ;
     RECT  188.243 116.256 188.435 116.28 ;
     RECT  186.304 2.496 191.408 4.488 ;
     RECT  186.304 5.472 191.408 6.6 ;
     RECT  186.304 7.872 191.408 7.944 ;
     RECT  186.304 9.792 191.408 9.816 ;
     RECT  186.304 11.136 191.408 11.16 ;
     RECT  186.304 12.192 191.408 12.216 ;
     RECT  186.304 14.64 191.408 17.88 ;
     RECT  186.304 19.488 191.408 95.112 ;
     RECT  186.304 96.432 191.408 98.376 ;
     RECT  186.304 103.296 191.408 103.32 ;
     RECT  186.304 105.12 191.408 105.144 ;
     RECT  186.304 107.376 191.408 108.6 ;
     RECT  188.339 110.592 191.408 114.312 ;
     RECT  191.408 2.148 191.512 95.112 ;
     RECT  191.408 96.432 191.512 114.492 ;
     RECT  191.512 96.432 191.6 114.312 ;
     RECT  191.512 2.418 191.704 95.112 ;
     RECT  191.6 96.378 191.704 114.312 ;
     RECT  191.704 2.496 196.808 4.488 ;
     RECT  191.704 5.472 196.808 6.6 ;
     RECT  191.704 7.872 196.808 7.944 ;
     RECT  191.704 9.792 196.808 9.816 ;
     RECT  191.704 11.136 196.808 11.16 ;
     RECT  191.704 12.192 196.808 12.216 ;
     RECT  191.704 14.64 196.808 17.88 ;
     RECT  191.704 19.488 196.808 95.112 ;
     RECT  191.704 96.432 196.808 98.376 ;
     RECT  191.704 103.296 196.808 103.32 ;
     RECT  191.704 105.12 196.808 105.144 ;
     RECT  191.704 107.376 196.808 108.6 ;
     RECT  191.704 110.592 196.808 114.312 ;
     RECT  196.808 2.148 196.912 95.112 ;
     RECT  196.808 96.432 196.912 114.492 ;
     RECT  196.912 96.432 197 114.312 ;
     RECT  196.912 2.418 197.104 95.112 ;
     RECT  197 96.378 197.104 114.312 ;
     RECT  197.104 2.496 202.208 4.488 ;
     RECT  197.104 5.472 202.208 6.6 ;
     RECT  197.104 7.872 202.208 7.944 ;
     RECT  197.104 9.792 202.208 9.816 ;
     RECT  197.104 11.136 202.208 11.16 ;
     RECT  197.104 12.192 202.208 12.216 ;
     RECT  197.104 14.64 202.208 17.88 ;
     RECT  197.104 19.488 202.208 95.112 ;
     RECT  197.104 96.432 202.208 98.376 ;
     RECT  197.104 103.296 202.208 103.32 ;
     RECT  197.104 105.12 202.208 105.144 ;
     RECT  197.104 107.376 202.208 108.6 ;
     RECT  197.104 110.592 202.208 114.312 ;
     RECT  202.208 2.148 202.312 95.112 ;
     RECT  202.208 96.432 202.312 114.492 ;
     RECT  202.312 96.432 202.4 114.312 ;
     RECT  202.312 2.418 202.504 95.112 ;
     RECT  202.4 96.378 202.504 114.312 ;
     RECT  202.504 2.496 207.608 4.488 ;
     RECT  202.504 5.472 207.608 6.6 ;
     RECT  202.504 7.872 207.608 7.944 ;
     RECT  202.504 9.792 207.608 9.816 ;
     RECT  202.504 11.136 207.608 11.16 ;
     RECT  202.504 12.192 207.608 12.216 ;
     RECT  202.504 14.64 207.608 17.88 ;
     RECT  202.504 19.488 207.608 95.112 ;
     RECT  202.504 96.432 207.608 98.376 ;
     RECT  202.504 103.296 207.608 103.32 ;
     RECT  202.504 105.12 207.608 105.144 ;
     RECT  202.504 107.376 207.608 108.6 ;
     RECT  202.504 110.592 207.608 114.312 ;
     RECT  207.608 2.148 207.712 95.112 ;
     RECT  207.608 96.432 207.712 114.492 ;
     RECT  207.712 96.432 207.8 114.312 ;
     RECT  207.712 2.418 207.904 95.112 ;
     RECT  207.8 96.378 207.904 114.312 ;
     RECT  207.904 2.496 213.008 4.488 ;
     RECT  207.904 5.472 213.008 6.6 ;
     RECT  207.904 7.872 213.008 7.944 ;
     RECT  207.904 9.792 213.008 9.816 ;
     RECT  207.904 11.136 213.008 11.16 ;
     RECT  207.904 12.192 213.008 12.216 ;
     RECT  207.904 14.64 213.008 17.88 ;
     RECT  207.904 19.488 213.008 95.112 ;
     RECT  207.904 96.432 213.008 98.376 ;
     RECT  207.904 103.296 213.008 103.32 ;
     RECT  207.904 105.12 213.008 105.144 ;
     RECT  207.904 107.376 213.008 108.6 ;
     RECT  207.904 110.592 213.008 114.312 ;
     RECT  213.008 2.148 213.112 95.112 ;
     RECT  213.008 96.432 213.112 114.492 ;
     RECT  213.112 96.432 213.2 114.312 ;
     RECT  213.112 2.418 213.304 95.112 ;
     RECT  213.2 96.378 213.304 114.312 ;
     RECT  213.304 110.592 214.309 114.312 ;
     RECT  213.304 5.472 214.333 6.6 ;
     RECT  213.304 7.872 216.659 7.944 ;
     RECT  213.304 19.488 217.008 95.112 ;
     RECT  213.304 14.64 217.091 17.88 ;
     RECT  213.304 2.496 217.139 4.488 ;
     RECT  213.304 96.432 217.465 98.376 ;
     RECT  217.465 96.336 217.523 98.376 ;
     RECT  216.659 7.872 218.293 7.896 ;
     RECT  213.304 11.136 218.293 11.16 ;
     RECT  213.304 12.192 218.293 12.216 ;
     RECT  217.091 17.856 218.293 17.88 ;
     RECT  217.008 75.984 218.365 76.008 ;
     RECT  217.139 2.496 218.408 2.52 ;
     RECT  217.139 3.552 218.408 4.488 ;
     RECT  214.333 5.472 218.408 6.648 ;
     RECT  218.293 7.872 218.408 7.992 ;
     RECT  213.304 9.792 218.408 9.816 ;
     RECT  218.293 11.136 218.408 12.504 ;
     RECT  217.091 14.64 218.408 16.824 ;
     RECT  218.293 17.856 218.408 17.976 ;
     RECT  217.008 19.488 218.408 64.2 ;
     RECT  217.523 96.432 218.408 98.376 ;
     RECT  213.304 103.296 218.408 103.32 ;
     RECT  213.304 105.12 218.408 105.144 ;
     RECT  213.304 107.376 218.408 108.6 ;
     RECT  214.309 110.592 218.408 114.36 ;
     RECT  218.408 2.148 218.512 64.2 ;
     RECT  218.408 96.432 218.512 114.492 ;
     RECT  218.512 96.432 218.6 114.36 ;
     RECT  218.512 2.418 218.704 64.2 ;
     RECT  218.6 96.378 218.704 114.36 ;
     RECT  218.365 75.984 218.725 76.392 ;
     RECT  218.704 19.584 218.729 64.2 ;
     RECT  218.725 75.936 218.773 76.392 ;
     RECT  218.729 24.912 218.801 64.2 ;
     RECT  218.704 12.288 218.819 12.312 ;
     RECT  218.704 2.496 218.867 2.52 ;
     RECT  218.801 29.52 218.909 64.2 ;
     RECT  218.801 24.912 218.915 28.488 ;
     RECT  217.008 70.704 218.915 71.256 ;
     RECT  218.704 107.808 218.915 108.456 ;
     RECT  218.909 61.296 218.945 64.2 ;
     RECT  218.833 66.672 218.963 66.696 ;
     RECT  218.245 85.392 218.965 85.416 ;
     RECT  218.773 75.84 219.011 76.392 ;
     RECT  218.704 3.6 219.107 4.488 ;
     RECT  218.704 110.592 219.107 114.36 ;
     RECT  218.909 29.52 219.125 60.264 ;
     RECT  218.915 24.912 219.161 27.912 ;
     RECT  219.161 25.728 219.197 27.912 ;
     RECT  218.704 5.472 219.203 6.648 ;
     RECT  219.107 3.6 219.251 4.44 ;
     RECT  219.203 5.472 219.299 6.072 ;
     RECT  218.704 103.296 219.299 103.32 ;
     RECT  219.125 29.616 219.305 60.264 ;
     RECT  218.915 71.04 219.305 71.256 ;
     RECT  219.011 75.888 219.305 76.392 ;
     RECT  218.197 78.624 219.305 78.648 ;
     RECT  218.965 85.344 219.305 85.416 ;
     RECT  219.253 87.744 219.305 87.768 ;
     RECT  218.704 96.48 219.347 96.84 ;
     RECT  218.945 61.296 219.377 64.008 ;
     RECT  219.107 110.88 219.395 114.36 ;
     RECT  219.377 61.296 219.413 63.912 ;
     RECT  218.704 9.792 219.443 9.816 ;
     RECT  219.413 61.296 219.449 63.72 ;
     RECT  219.449 61.584 219.485 62.472 ;
     RECT  219.485 61.584 219.521 62.088 ;
     RECT  219.521 61.584 219.557 61.992 ;
     RECT  219.305 29.616 219.593 30.216 ;
     RECT  219.305 71.04 219.593 71.064 ;
     RECT  219.305 85.344 219.593 85.368 ;
     RECT  217.008 94.368 219.593 95.112 ;
     RECT  219.305 31.296 219.629 60.264 ;
     RECT  219.557 61.872 219.629 61.896 ;
     RECT  218.704 11.136 219.731 11.16 ;
     RECT  218.729 19.584 219.731 23.928 ;
     RECT  219.629 31.296 219.731 33.096 ;
     RECT  219.593 29.664 219.737 30.216 ;
     RECT  219.395 111.024 219.779 114.36 ;
     RECT  219.251 3.648 219.827 4.44 ;
     RECT  219.197 26.688 219.827 27.912 ;
     RECT  219.347 96.48 219.875 96.504 ;
     RECT  218.704 98.352 219.877 98.376 ;
     RECT  219.779 113.424 219.971 114.36 ;
     RECT  219.827 27.312 220.061 27.912 ;
     RECT  219.731 31.296 220.061 32.952 ;
     RECT  218.704 7.968 220.067 7.992 ;
     RECT  219.593 94.368 220.067 94.68 ;
     RECT  219.731 19.584 220.097 23.832 ;
     RECT  219.779 111.024 220.115 112.248 ;
     RECT  218.915 107.904 220.259 108.456 ;
     RECT  219.305 75.888 220.261 76.008 ;
     RECT  220.097 19.584 220.307 23.688 ;
     RECT  220.261 75.84 220.313 76.008 ;
     RECT  220.067 94.368 220.345 94.392 ;
     RECT  220.309 78.096 220.355 78.12 ;
     RECT  218.704 17.952 220.385 17.976 ;
     RECT  220.307 19.776 220.385 23.688 ;
     RECT  220.213 68.256 220.385 68.28 ;
     RECT  218.704 14.64 220.403 16.824 ;
     RECT  220.345 94.08 220.403 94.392 ;
     RECT  220.403 14.64 220.451 16.44 ;
     RECT  220.381 87.216 220.451 87.24 ;
     RECT  219.629 34.8 220.453 60.264 ;
     RECT  220.259 108.432 220.499 108.456 ;
     RECT  219.299 5.472 220.597 5.544 ;
     RECT  220.453 34.8 220.637 60.744 ;
     RECT  220.597 5.472 220.643 5.64 ;
     RECT  219.971 113.424 220.643 113.88 ;
     RECT  220.501 18.048 220.673 18.072 ;
     RECT  220.385 19.92 220.673 23.352 ;
     RECT  220.637 49.104 220.673 60.744 ;
     RECT  220.403 94.368 220.673 94.392 ;
     RECT  220.643 5.52 220.739 5.64 ;
     RECT  220.739 5.52 220.787 5.544 ;
     RECT  220.673 49.104 220.853 56.616 ;
     RECT  220.673 20.688 220.925 23.352 ;
     RECT  220.673 57.744 220.925 60.744 ;
     RECT  220.313 75.888 220.925 76.008 ;
     RECT  220.115 111.024 220.931 112.152 ;
     RECT  220.925 20.88 220.979 23.352 ;
     RECT  219.877 98.304 220.979 98.376 ;
     RECT  220.345 30.24 220.981 30.264 ;
     RECT  220.925 57.744 221.105 60.456 ;
     RECT  220.979 20.88 221.123 21.336 ;
     RECT  220.981 30.24 221.123 30.744 ;
     RECT  221.123 21.024 221.171 21.336 ;
     RECT  220.931 111.024 221.171 111.96 ;
     RECT  220.637 34.8 221.177 48.072 ;
     RECT  221.171 21.024 221.213 21.048 ;
     RECT  221.123 30.72 221.213 30.744 ;
     RECT  221.177 47.712 221.213 48.072 ;
     RECT  220.853 49.104 221.213 51.048 ;
     RECT  220.853 52.08 221.213 56.616 ;
     RECT  221.105 59.568 221.213 60.456 ;
     RECT  220.925 75.888 221.213 75.912 ;
     RECT  220.979 22.464 221.219 23.352 ;
     RECT  220.643 113.472 221.219 113.88 ;
     RECT  220.451 15.456 221.267 16.44 ;
     RECT  220.979 98.304 221.267 98.328 ;
     RECT  221.177 34.8 221.285 46.728 ;
     RECT  219.827 3.648 221.315 3.912 ;
     RECT  221.267 15.456 221.411 16.344 ;
     RECT  221.353 67.824 221.411 67.848 ;
     RECT  221.219 22.464 221.459 22.68 ;
     RECT  221.171 111.024 221.459 111.048 ;
     RECT  221.213 50.64 221.501 51.048 ;
     RECT  221.461 23.904 221.507 23.928 ;
     RECT  221.219 113.472 221.507 113.496 ;
     RECT  221.459 22.656 221.555 22.68 ;
     RECT  220.061 32.496 221.555 32.52 ;
     RECT  221.285 34.8 221.555 34.92 ;
     RECT  221.411 16.32 221.603 16.344 ;
     RECT  221.285 36.384 221.645 46.728 ;
     RECT  221.315 3.648 221.651 3.672 ;
     RECT  221.105 57.744 221.681 58.104 ;
     RECT  221.213 52.08 221.717 55.944 ;
     RECT  221.555 34.896 221.747 34.92 ;
     RECT  221.645 36.384 221.753 46.44 ;
     RECT  221.213 60.432 221.753 60.456 ;
     RECT  221.681 57.744 221.821 58.008 ;
     RECT  221.213 47.712 221.825 47.736 ;
     RECT  221.821 57.024 221.861 58.008 ;
     RECT  221.213 49.104 221.965 49.608 ;
     RECT  221.965 48.816 222.035 49.608 ;
     RECT  221.717 52.896 222.035 55.944 ;
     RECT  221.753 36.384 222.041 36.936 ;
     RECT  221.753 38.16 222.185 46.44 ;
     RECT  222.035 49.104 222.185 49.608 ;
     RECT  221.861 57.024 222.221 57.048 ;
     RECT  222.185 40.8 222.257 45.576 ;
     RECT  222.035 52.992 222.371 55.944 ;
     RECT  222.185 49.536 222.401 49.608 ;
     RECT  222.371 52.992 222.473 53.592 ;
     RECT  222.371 54.624 222.563 55.944 ;
     RECT  222.257 40.8 222.581 45.288 ;
     RECT  222.185 38.16 222.707 39.096 ;
     RECT  222.707 38.16 223.808 38.184 ;
     RECT  222.581 40.8 223.808 43.128 ;
     RECT  222.581 44.304 223.808 45.288 ;
     RECT  222.181 47.904 223.808 47.928 ;
     RECT  222.401 49.536 223.808 49.56 ;
     RECT  221.501 50.688 223.808 51.048 ;
     RECT  222.563 54.96 223.808 55.08 ;
     RECT  223.808 2.148 223.912 114.492 ;
     RECT  223.912 2.418 224.104 114.222 ;
     RECT  229.208 2.148 229.312 114.492 ;
     RECT  229.312 2.418 229.504 114.222 ;
     RECT  234.608 2.148 234.712 114.492 ;
     RECT  234.712 2.418 234.904 114.222 ;
     RECT  240.008 2.148 240.112 114.492 ;
     RECT  240.112 2.418 240.304 114.222 ;
     RECT  245.408 2.148 245.512 114.492 ;
     RECT  245.512 2.418 245.704 114.222 ;
     RECT  250.808 2.148 250.912 114.492 ;
     RECT  250.912 2.418 251.104 114.222 ;
     RECT  256.208 2.148 256.312 114.492 ;
     RECT  256.312 2.418 256.504 114.222 ;
    LAYER M5 ;
     RECT  105.648 0.016 111.72 0.037 ;
     RECT  118.032 0.016 127.848 0.037 ;
     RECT  118.032 0.037 127.944 0.131 ;
     RECT  128.976 0.016 130.824 0.131 ;
     RECT  118.128 0.131 127.944 0.179 ;
     RECT  105.552 0.037 111.72 0.227 ;
     RECT  118.128 0.179 127.752 0.227 ;
     RECT  118.128 0.227 127.56 1.139 ;
     RECT  118.224 1.139 124.008 1.187 ;
     RECT  125.232 1.139 127.56 1.427 ;
     RECT  118.32 1.187 124.008 1.715 ;
     RECT  129.072 0.131 130.824 1.763 ;
     RECT  105.648 0.227 111.72 1.811 ;
     RECT  118.416 1.715 124.008 1.859 ;
     RECT  106.8 1.811 111.72 1.907 ;
     RECT  129.264 1.763 130.824 1.907 ;
     RECT  105.648 1.811 105.672 2.137 ;
     RECT  2.4 2.137 2.52 2.151 ;
     RECT  7.8 2.137 7.92 2.151 ;
     RECT  13.2 2.137 13.32 2.151 ;
     RECT  18.6 2.137 18.72 2.151 ;
     RECT  24 2.137 24.12 2.151 ;
     RECT  29.4 2.137 29.52 2.151 ;
     RECT  34.8 2.137 34.92 2.151 ;
     RECT  40.2 2.137 40.32 2.151 ;
     RECT  45.6 2.137 45.72 2.151 ;
     RECT  51 2.137 51.12 2.151 ;
     RECT  56.4 2.137 56.52 2.151 ;
     RECT  61.8 2.137 61.92 2.151 ;
     RECT  67.2 2.137 67.32 2.151 ;
     RECT  72.6 2.137 72.72 2.151 ;
     RECT  78 2.137 78.12 2.151 ;
     RECT  83.4 2.137 83.52 2.151 ;
     RECT  88.8 2.137 88.92 2.151 ;
     RECT  94.2 2.137 94.32 2.151 ;
     RECT  99.6 2.137 99.72 2.151 ;
     RECT  115.8 2.137 115.92 2.151 ;
     RECT  132 2.137 132.12 2.151 ;
     RECT  137.4 2.137 137.52 2.151 ;
     RECT  142.8 2.137 142.92 2.151 ;
     RECT  148.2 2.137 148.32 2.151 ;
     RECT  153.6 2.137 153.72 2.151 ;
     RECT  159 2.137 159.12 2.151 ;
     RECT  164.4 2.137 164.52 2.151 ;
     RECT  169.8 2.137 169.92 2.151 ;
     RECT  175.2 2.137 175.32 2.151 ;
     RECT  180.6 2.137 180.72 2.151 ;
     RECT  186 2.137 186.12 2.151 ;
     RECT  191.4 2.137 191.52 2.151 ;
     RECT  196.8 2.137 196.92 2.151 ;
     RECT  202.2 2.137 202.32 2.151 ;
     RECT  207.6 2.137 207.72 2.151 ;
     RECT  213 2.137 213.12 2.151 ;
     RECT  218.4 2.137 218.52 2.151 ;
     RECT  223.8 2.137 223.92 2.151 ;
     RECT  229.2 2.137 229.32 2.151 ;
     RECT  234.6 2.137 234.72 2.151 ;
     RECT  240 2.137 240.12 2.151 ;
     RECT  245.4 2.137 245.52 2.151 ;
     RECT  250.8 2.137 250.92 2.151 ;
     RECT  256.2 2.137 256.32 2.151 ;
     RECT  106.8 1.907 111.144 2.195 ;
     RECT  118.416 1.859 123.624 2.195 ;
     RECT  106.8 2.195 108.072 2.291 ;
     RECT  118.416 2.195 123.528 2.291 ;
     RECT  125.232 1.427 127.272 2.291 ;
     RECT  129.264 1.907 130.44 2.291 ;
     RECT  109.104 2.195 111.144 2.339 ;
     RECT  118.416 2.291 118.824 2.339 ;
     RECT  125.424 2.291 127.272 2.339 ;
     RECT  218.4 2.151 218.712 2.485 ;
     RECT  118.416 2.339 118.536 2.725 ;
     RECT  120.816 2.291 123.144 2.771 ;
     RECT  34.8 2.151 35.112 2.821 ;
     RECT  118.176 2.725 118.536 2.821 ;
     RECT  106.8 2.291 107.688 2.915 ;
     RECT  109.104 2.339 109.128 2.915 ;
     RECT  110.208 2.339 111.144 2.915 ;
     RECT  106.8 2.915 107.016 3.011 ;
     RECT  118.08 2.821 118.536 3.107 ;
     RECT  120.816 2.771 122.76 3.301 ;
     RECT  148.2 2.151 148.512 3.301 ;
     RECT  157.296 2.245 157.32 3.301 ;
     RECT  157.296 3.301 157.992 3.347 ;
     RECT  216.912 3.301 216.936 3.397 ;
     RECT  218.4 2.485 218.856 3.589 ;
     RECT  218.4 3.589 219.24 3.637 ;
     RECT  218.304 3.637 219.24 3.685 ;
     RECT  216.912 3.397 217.128 3.829 ;
     RECT  221.616 3.637 221.64 3.877 ;
     RECT  133.92 3.397 133.944 3.925 ;
     RECT  162.432 3.397 162.456 3.925 ;
     RECT  164.4 2.151 164.712 3.925 ;
     RECT  120.672 3.301 122.76 4.019 ;
     RECT  122.736 4.019 122.76 4.115 ;
     RECT  125.904 2.339 127.272 4.117 ;
     RECT  216.768 3.829 217.128 4.117 ;
     RECT  138.816 3.301 138.84 4.259 ;
     RECT  118.176 3.107 118.536 4.261 ;
     RECT  38.928 3.301 38.952 4.357 ;
     RECT  88.8 2.151 89.112 4.501 ;
     RECT  120.672 4.019 121.608 4.501 ;
     RECT  133.584 3.925 134.52 4.501 ;
     RECT  142.8 2.151 143.112 4.501 ;
     RECT  117.984 4.261 118.536 4.595 ;
     RECT  130.8 3.301 130.824 4.595 ;
     RECT  157.968 3.347 157.992 4.643 ;
     RECT  148.2 3.301 148.632 4.645 ;
     RECT  85.488 4.693 85.512 4.885 ;
     RECT  125.904 4.117 128.184 5.029 ;
     RECT  84.72 4.885 85.512 5.171 ;
     RECT  117.984 4.595 118.248 5.171 ;
     RECT  40.2 2.151 40.512 5.461 ;
     RECT  218.304 3.685 220.2 5.461 ;
     RECT  221.28 3.877 221.64 5.461 ;
     RECT  119.712 4.501 121.608 5.605 ;
     RECT  106.896 3.011 107.016 5.653 ;
     RECT  119.712 5.605 121.992 5.653 ;
     RECT  106.8 5.653 107.016 5.747 ;
     RECT  117.984 5.171 118.008 5.747 ;
     RECT  125.904 5.029 128.808 5.747 ;
     RECT  87.264 3.637 87.288 5.845 ;
     RECT  108.864 4.501 108.888 5.845 ;
     RECT  216.72 4.117 217.128 5.989 ;
     RECT  218.304 5.461 221.64 5.989 ;
     RECT  157.584 4.837 157.608 6.035 ;
     RECT  86.592 5.845 87.288 6.083 ;
     RECT  108.624 5.845 108.888 6.229 ;
     RECT  126.48 5.747 128.808 6.323 ;
     RECT  126.48 6.323 127.512 6.371 ;
     RECT  133.488 4.501 134.52 6.419 ;
     RECT  142.464 4.501 143.112 6.419 ;
     RECT  34.8 2.821 35.304 6.565 ;
     RECT  42.528 5.173 42.552 6.661 ;
     RECT  110.208 2.915 110.712 6.709 ;
     RECT  119.52 5.653 121.992 6.757 ;
     RECT  108.624 6.229 109.032 6.805 ;
     RECT  110.208 6.709 111 6.805 ;
     RECT  106.8 5.747 106.92 6.851 ;
     RECT  126.48 6.371 127.08 6.899 ;
     RECT  119.328 6.757 121.992 6.947 ;
     RECT  126.6 6.899 127.08 7.139 ;
     RECT  106.896 6.851 106.92 7.237 ;
     RECT  119.328 6.947 121.512 7.381 ;
     RECT  80.352 5.269 80.376 7.475 ;
     RECT  106.896 7.237 107.352 7.475 ;
     RECT  34.8 6.565 35.928 7.861 ;
     RECT  216.72 5.989 221.64 7.909 ;
     RECT  108.624 6.805 111 8.051 ;
     RECT  34.8 7.861 35.976 8.149 ;
     RECT  108.624 8.051 108.696 8.197 ;
     RECT  105 2.137 105.672 8.243 ;
     RECT  107.328 7.475 107.352 8.485 ;
     RECT  108.384 8.197 108.696 8.485 ;
     RECT  124.704 5.077 124.728 8.485 ;
     RECT  124.512 8.485 124.728 8.531 ;
     RECT  40.2 5.461 41.352 8.677 ;
     RECT  109.728 8.051 111 9.061 ;
     RECT  109.728 9.061 111.96 9.155 ;
     RECT  40.2 8.677 41.448 9.205 ;
     RECT  123.504 8.485 123.528 9.539 ;
     RECT  94.2 2.151 94.512 9.637 ;
     RECT  109.92 9.155 111.96 9.731 ;
     RECT  111.936 9.731 111.96 9.925 ;
     RECT  118.848 7.381 121.512 9.925 ;
     RECT  38.208 4.357 38.952 10.117 ;
     RECT  40.2 9.205 41.544 10.117 ;
     RECT  92.304 9.061 92.328 10.307 ;
     RECT  38.208 10.117 41.544 10.309 ;
     RECT  42.528 6.661 42.696 10.309 ;
     RECT  93.648 9.637 94.512 10.355 ;
     RECT  126.6 7.139 127.032 10.741 ;
     RECT  72.6 2.151 72.912 10.789 ;
     RECT  107.328 8.485 108.696 10.883 ;
     RECT  109.92 9.731 110.904 10.883 ;
     RECT  111.936 9.925 112.92 10.883 ;
     RECT  87.264 6.083 87.288 10.931 ;
     RECT  115.8 2.151 116.112 11.125 ;
     RECT  118.848 9.925 122.04 11.171 ;
     RECT  130.368 5.653 130.392 11.171 ;
     RECT  107.856 10.883 108.696 11.269 ;
     RECT  83.4 2.151 83.712 11.365 ;
     RECT  88.704 4.501 89.112 11.411 ;
     RECT  112.32 10.883 112.92 11.411 ;
     RECT  107.856 11.269 108.84 11.413 ;
     RECT  109.92 10.883 110.712 11.413 ;
     RECT  137.4 2.151 137.712 11.653 ;
     RECT  107.856 11.413 110.712 12.515 ;
     RECT  84.72 5.171 84.744 12.563 ;
     RECT  83.184 11.365 83.712 12.755 ;
     RECT  67.2 2.151 67.512 12.997 ;
     RECT  38.208 10.309 42.696 13.045 ;
     RECT  107.856 12.515 108.84 13.523 ;
     RECT  109.968 12.515 110.712 13.573 ;
     RECT  108.816 13.523 108.84 13.715 ;
     RECT  112.32 11.411 112.344 13.715 ;
     RECT  124.512 8.531 124.536 13.715 ;
     RECT  126.6 10.741 127.368 13.715 ;
     RECT  137.4 11.653 137.976 14.101 ;
     RECT  109.968 13.573 111.192 14.291 ;
     RECT  137.4 14.101 138.504 14.867 ;
     RECT  34.8 8.149 36.84 14.965 ;
     RECT  37.824 13.045 42.696 14.965 ;
     RECT  109.968 14.291 110.712 15.443 ;
     RECT  67.2 12.997 68.088 16.069 ;
     RECT  66.72 16.069 68.088 16.307 ;
     RECT  125.568 14.773 125.592 16.307 ;
     RECT  126.6 13.715 127.032 16.405 ;
     RECT  67.2 16.307 68.088 16.501 ;
     RECT  125.904 16.405 127.032 16.501 ;
     RECT  83.4 12.755 83.712 16.789 ;
     RECT  72.6 10.789 73.176 16.835 ;
     RECT  33.024 16.405 33.048 17.123 ;
     RECT  145.584 3.013 145.608 17.123 ;
     RECT  53.232 12.757 53.256 17.219 ;
     RECT  45.6 2.151 45.912 17.509 ;
     RECT  34.8 14.965 42.696 17.605 ;
     RECT  44.976 17.509 45.912 17.989 ;
     RECT  51 2.151 51.312 18.565 ;
     RECT  21.744 18.421 21.768 18.757 ;
     RECT  29.4 2.151 29.712 18.757 ;
     RECT  110.4 15.443 110.712 18.853 ;
     RECT  67.2 16.501 68.28 18.899 ;
     RECT  108.288 16.501 108.312 18.995 ;
     RECT  110.016 18.853 110.712 18.995 ;
     RECT  50.448 18.565 51.312 19.045 ;
     RECT  20.16 18.757 20.184 19.189 ;
     RECT  29.4 18.757 30.264 19.237 ;
     RECT  44.976 17.989 46.296 19.283 ;
     RECT  24 2.151 24.312 19.333 ;
     RECT  25.296 18.517 25.32 19.333 ;
     RECT  125.904 16.501 127.176 19.427 ;
     RECT  45.408 19.283 46.296 19.429 ;
     RECT  29.088 19.237 30.264 19.477 ;
     RECT  27.36 18.181 27.384 19.523 ;
     RECT  29.088 19.477 30.744 19.523 ;
     RECT  67.2 18.899 67.512 19.573 ;
     RECT  53.184 17.317 53.208 19.619 ;
     RECT  45.408 19.429 46.824 19.621 ;
     RECT  50.16 19.045 51.312 19.669 ;
     RECT  66.72 19.573 67.512 19.715 ;
     RECT  45.408 19.621 46.92 19.763 ;
     RECT  49.008 19.669 49.032 19.811 ;
     RECT  45.408 19.763 46.2 19.859 ;
     RECT  20.16 19.189 20.328 19.955 ;
     RECT  21.744 18.757 22.68 19.955 ;
     RECT  24 19.333 25.944 20.003 ;
     RECT  30.72 19.523 30.744 20.003 ;
     RECT  106.992 17.413 107.016 20.003 ;
     RECT  20.304 19.955 20.328 20.099 ;
     RECT  128.64 10.789 128.664 20.293 ;
     RECT  50.16 19.669 51.672 20.339 ;
     RECT  128.448 20.293 128.664 20.435 ;
     RECT  22.656 19.955 22.68 20.579 ;
     RECT  133.488 6.419 134.04 20.627 ;
     RECT  162.432 3.925 164.712 20.723 ;
     RECT  32.256 20.725 32.28 20.773 ;
     RECT  32.256 20.773 32.472 20.869 ;
     RECT  29.088 19.523 29.712 20.965 ;
     RECT  18.6 2.151 18.912 21.013 ;
     RECT  16.656 20.149 16.68 21.059 ;
     RECT  119.376 11.171 122.04 21.061 ;
     RECT  132 2.151 132.312 21.109 ;
     RECT  34.32 17.605 42.696 21.155 ;
     RECT  45.6 19.859 46.2 21.155 ;
     RECT  54.672 19.477 54.696 21.155 ;
     RECT  70.08 20.581 70.104 21.155 ;
     RECT  75.216 20.677 75.24 21.155 ;
     RECT  115.488 11.125 116.112 21.155 ;
     RECT  135.744 3.925 136.296 21.155 ;
     RECT  148.2 4.645 149.064 21.203 ;
     RECT  34.8 21.155 42.696 21.205 ;
     RECT  126.6 19.427 127.176 21.205 ;
     RECT  128.208 21.061 128.232 21.205 ;
     RECT  142.8 6.419 143.112 21.205 ;
     RECT  194.352 21.157 194.376 21.299 ;
     RECT  88.8 11.411 89.112 21.301 ;
     RECT  105 8.243 105.312 21.301 ;
     RECT  34.8 21.205 42.888 21.347 ;
     RECT  118.56 21.061 122.04 21.347 ;
     RECT  83.4 16.789 84.072 21.395 ;
     RECT  115.8 21.155 116.112 21.397 ;
     RECT  144.624 21.109 144.648 21.445 ;
     RECT  126.6 21.205 128.232 21.491 ;
     RECT  137.4 14.867 137.712 21.493 ;
     RECT  142.56 21.205 143.112 21.539 ;
     RECT  13.2 2.151 13.512 21.541 ;
     RECT  83.4 21.395 83.712 21.541 ;
     RECT  34.8 21.347 42.792 21.587 ;
     RECT  119.136 21.347 122.04 21.587 ;
     RECT  144.528 21.445 144.648 21.587 ;
     RECT  142.8 21.539 143.112 21.589 ;
     RECT  18.192 21.013 18.912 21.683 ;
     RECT  13.2 21.541 13.656 21.731 ;
     RECT  115.8 21.397 116.328 21.875 ;
     RECT  114.672 21.493 114.696 21.923 ;
     RECT  148.2 21.203 148.632 21.971 ;
     RECT  24 20.003 24.312 22.069 ;
     RECT  128.16 21.491 128.232 22.115 ;
     RECT  131.616 21.109 132.312 22.163 ;
     RECT  162.864 20.723 164.712 22.211 ;
     RECT  27.072 21.541 27.096 22.213 ;
     RECT  29.04 20.965 29.712 22.259 ;
     RECT  135.744 21.155 135.768 22.451 ;
     RECT  21.12 20.965 21.144 22.499 ;
     RECT  83.184 21.541 83.712 22.499 ;
     RECT  88.8 21.301 90.072 22.547 ;
     RECT  137.4 21.493 137.928 22.643 ;
     RECT  142.8 21.589 143.64 22.691 ;
     RECT  29.4 22.259 29.712 22.741 ;
     RECT  25.872 20.003 25.944 22.787 ;
     RECT  163.44 22.211 164.712 23.027 ;
     RECT  105 21.301 106.008 23.075 ;
     RECT  119.136 21.587 121.608 23.075 ;
     RECT  120.24 23.075 121.608 23.123 ;
     RECT  119.136 23.075 119.16 23.171 ;
     RECT  13.2 21.731 13.512 23.173 ;
     RECT  44.016 21.109 44.04 23.267 ;
     RECT  128.208 22.115 128.232 23.267 ;
     RECT  121.2 23.123 121.608 23.315 ;
     RECT  133.488 20.627 133.512 23.315 ;
     RECT  51 20.339 51.672 23.363 ;
     RECT  25.92 22.787 25.944 23.411 ;
     RECT  216.624 7.909 221.64 23.555 ;
     RECT  34.8 21.587 42.696 23.651 ;
     RECT  216.768 23.555 221.64 23.651 ;
     RECT  18.6 21.683 18.912 23.653 ;
     RECT  34.8 23.651 42.552 23.699 ;
     RECT  217.008 23.651 221.64 23.699 ;
     RECT  29.4 22.741 30.36 23.941 ;
     RECT  18.6 23.653 19.896 24.083 ;
     RECT  18.6 24.083 19.752 24.227 ;
     RECT  28.896 23.941 30.36 24.325 ;
     RECT  32.256 20.869 33.144 24.709 ;
     RECT  7.8 2.151 8.112 24.757 ;
     RECT  32.16 24.709 33.336 25.189 ;
     RECT  34.8 23.699 42.168 25.189 ;
     RECT  20.64 25.141 20.664 25.283 ;
     RECT  31.584 25.189 42.168 25.381 ;
     RECT  31.584 25.381 42.216 25.571 ;
     RECT  31.584 25.571 42.168 25.619 ;
     RECT  31.92 25.619 42.168 25.811 ;
     RECT  16.176 23.701 16.2 25.813 ;
     RECT  18.6 24.227 18.912 25.813 ;
     RECT  16.08 25.813 16.2 25.859 ;
     RECT  23.088 22.069 24.312 26.003 ;
     RECT  16.08 25.859 16.104 26.243 ;
     RECT  7.8 24.757 8.568 26.579 ;
     RECT  27.072 22.213 27.528 26.867 ;
     RECT  10.704 27.205 10.728 27.349 ;
     RECT  28.56 24.325 30.36 27.397 ;
     RECT  32.256 25.811 42.168 27.731 ;
     RECT  10.656 27.349 10.728 27.779 ;
     RECT  32.256 27.731 33.384 27.781 ;
     RECT  2.4 2.151 2.712 27.877 ;
     RECT  13.2 23.173 14.136 27.923 ;
     RECT  22.32 26.821 22.344 27.923 ;
     RECT  28.56 27.397 30.408 27.923 ;
     RECT  25.968 27.061 25.992 27.971 ;
     RECT  13.2 27.923 13.704 27.973 ;
     RECT  10.656 27.779 10.68 28.019 ;
     RECT  13.104 27.973 13.704 28.019 ;
     RECT  7.8 26.579 8.112 28.213 ;
     RECT  15.36 27.301 15.384 28.261 ;
     RECT  15.072 28.261 15.384 28.307 ;
     RECT  32.016 27.781 33.384 28.405 ;
     RECT  11.952 26.533 11.976 28.451 ;
     RECT  18.6 25.813 19.8 28.453 ;
     RECT  20.928 27.877 20.952 28.453 ;
     RECT  34.8 27.731 42.168 28.741 ;
     RECT  13.104 28.019 13.656 28.789 ;
     RECT  13.008 28.789 13.656 28.835 ;
     RECT  17.136 28.885 17.16 29.027 ;
     RECT  18.6 28.453 20.952 29.077 ;
     RECT  22.704 28.789 22.728 29.077 ;
     RECT  25.728 28.453 25.752 29.123 ;
     RECT  22.416 29.077 22.728 29.219 ;
     RECT  2.4 27.877 3.432 29.363 ;
     RECT  22.704 29.219 22.728 29.459 ;
     RECT  28.8 27.923 30.408 29.509 ;
     RECT  31.92 28.405 33.384 29.509 ;
     RECT  27.072 26.867 27.096 29.653 ;
     RECT  28.8 29.509 33.384 29.653 ;
     RECT  2.4 29.363 3.192 29.699 ;
     RECT  18.6 29.077 21.288 29.843 ;
     RECT  13.008 28.835 13.512 29.845 ;
     RECT  12.528 29.845 13.512 30.037 ;
     RECT  15.072 28.307 15.096 30.037 ;
     RECT  24 26.003 24.312 30.037 ;
     RECT  34.608 28.741 42.168 30.037 ;
     RECT  34.608 30.037 42.264 30.227 ;
     RECT  18.6 29.843 21.096 30.563 ;
     RECT  22.896 30.037 24.312 30.613 ;
     RECT  22.8 30.613 24.312 30.757 ;
     RECT  27.072 29.653 33.384 30.803 ;
     RECT  27.072 30.803 30.408 30.947 ;
     RECT  12.528 30.037 15.096 31.139 ;
     RECT  7.392 28.213 8.112 31.141 ;
     RECT  22.8 30.757 25.128 31.141 ;
     RECT  18.6 30.563 20.952 31.237 ;
     RECT  18.48 31.237 20.952 31.285 ;
     RECT  7.392 31.141 8.232 31.381 ;
     RECT  16.8 29.893 16.824 31.381 ;
     RECT  34.608 30.227 42.168 31.427 ;
     RECT  22.8 31.141 25.944 31.619 ;
     RECT  16.8 31.381 16.872 31.669 ;
     RECT  25.92 31.619 25.944 31.669 ;
     RECT  27.072 30.947 27.096 31.669 ;
     RECT  12.528 31.139 13.512 31.861 ;
     RECT  6.96 31.381 8.232 31.909 ;
     RECT  28.368 30.947 30.408 31.909 ;
     RECT  31.536 30.803 33.384 31.909 ;
     RECT  18.288 31.285 20.952 32.101 ;
     RECT  5.328 30.709 5.352 32.437 ;
     RECT  11.568 31.861 13.512 32.437 ;
     RECT  18.288 32.101 21.336 32.437 ;
     RECT  28.368 31.909 33.384 32.437 ;
     RECT  15.072 31.139 15.096 32.485 ;
     RECT  14.832 32.485 15.096 32.531 ;
     RECT  6.96 31.909 8.28 32.723 ;
     RECT  16.8 31.669 17.304 32.725 ;
     RECT  18.288 32.437 21.528 32.725 ;
     RECT  5.328 32.437 5.928 32.771 ;
     RECT  16.8 32.725 21.528 33.059 ;
     RECT  28.368 32.437 33.576 33.061 ;
     RECT  11.568 32.437 13.656 33.107 ;
     RECT  22.8 31.619 24.312 33.109 ;
     RECT  25.92 31.669 27.096 33.109 ;
     RECT  28.08 33.061 33.576 33.109 ;
     RECT  25.92 33.109 33.576 33.251 ;
     RECT  31.536 33.251 33.576 33.299 ;
     RECT  9.552 27.109 9.576 33.349 ;
     RECT  7.8 32.723 8.28 33.445 ;
     RECT  9.264 33.349 9.576 33.445 ;
     RECT  25.92 33.251 30.264 33.491 ;
     RECT  11.568 33.107 11.592 33.587 ;
     RECT  13.008 33.107 13.656 33.587 ;
     RECT  16.8 33.059 21.336 33.587 ;
     RECT  7.8 33.445 9.576 33.635 ;
     RECT  25.92 33.491 29.712 33.829 ;
     RECT  16.8 33.587 20.04 33.973 ;
     RECT  13.008 33.587 13.512 34.117 ;
     RECT  16.224 33.973 20.04 34.163 ;
     RECT  14.832 32.531 14.856 34.165 ;
     RECT  14.832 34.165 15.24 34.211 ;
     RECT  31.536 33.299 33.384 34.259 ;
     RECT  25.296 33.829 29.712 34.501 ;
     RECT  2.4 29.699 3.048 34.741 ;
     RECT  217.104 23.699 221.64 34.885 ;
     RECT  9.408 33.635 9.576 34.979 ;
     RECT  22.32 33.109 24.312 35.027 ;
     RECT  12.576 34.117 13.512 35.363 ;
     RECT  7.8 33.635 8.328 35.413 ;
     RECT  9.408 34.979 9.48 35.413 ;
     RECT  16.224 34.163 19.8 35.459 ;
     RECT  13.104 35.363 13.512 35.509 ;
     RECT  25.296 34.501 30.552 35.603 ;
     RECT  21.312 33.587 21.336 35.747 ;
     RECT  7.8 35.413 9.48 35.843 ;
     RECT  5.904 32.771 5.928 35.845 ;
     RECT  7.8 35.843 8.328 35.891 ;
     RECT  9.408 35.843 9.48 35.891 ;
     RECT  16.224 35.459 17.496 35.939 ;
     RECT  28.512 35.603 30.552 35.939 ;
     RECT  31.68 34.259 33.384 35.941 ;
     RECT  34.8 31.427 42.168 35.941 ;
     RECT  31.68 35.941 42.168 36.083 ;
     RECT  15.216 34.211 15.24 36.275 ;
     RECT  13.104 35.509 13.608 36.371 ;
     RECT  13.104 36.371 13.512 36.421 ;
     RECT  18.6 35.459 19.8 36.421 ;
     RECT  217.104 34.885 221.736 36.421 ;
     RECT  22.992 35.027 24.312 36.517 ;
     RECT  25.296 35.603 27.096 36.517 ;
     RECT  22.992 36.517 27.096 36.565 ;
     RECT  28.512 35.939 29.712 36.565 ;
     RECT  217.104 36.421 221.88 36.707 ;
     RECT  22.992 36.565 29.712 36.755 ;
     RECT  22.992 36.755 27.48 36.757 ;
     RECT  22.416 36.757 27.48 36.851 ;
     RECT  16.224 35.939 16.584 36.899 ;
     RECT  22.416 36.851 24.312 36.995 ;
     RECT  5.616 35.845 5.928 37.093 ;
     RECT  7.8 35.891 8.232 37.093 ;
     RECT  31.68 36.083 33.384 37.189 ;
     RECT  31.68 37.189 33.432 37.235 ;
     RECT  7.8 37.093 8.424 37.525 ;
     RECT  9.456 35.891 9.48 37.525 ;
     RECT  7.8 37.525 9.48 37.571 ;
     RECT  5.616 37.093 6.072 37.619 ;
     RECT  25.92 36.851 27.48 37.619 ;
     RECT  32.256 37.235 33.432 37.619 ;
     RECT  7.8 37.571 9.336 37.811 ;
     RECT  12.528 36.421 13.512 37.861 ;
     RECT  17.808 36.421 19.8 37.909 ;
     RECT  15.12 37.861 15.144 38.003 ;
     RECT  28.848 36.755 29.712 38.149 ;
     RECT  217.152 36.707 221.88 38.149 ;
     RECT  223.8 2.151 224.112 38.149 ;
     RECT  17.232 37.909 19.8 38.195 ;
     RECT  23.088 36.995 24.312 38.341 ;
     RECT  11.472 36.949 11.496 38.389 ;
     RECT  12.48 37.861 13.512 38.389 ;
     RECT  7.8 37.811 9.144 38.579 ;
     RECT  25.92 37.619 27.096 38.581 ;
     RECT  6.048 37.619 6.072 38.677 ;
     RECT  25.92 38.581 27.624 38.677 ;
     RECT  22.896 38.341 24.312 38.773 ;
     RECT  25.296 38.677 27.624 38.773 ;
     RECT  2.4 34.741 3.672 38.819 ;
     RECT  28.848 38.149 29.976 39.205 ;
     RECT  30.96 37.861 30.984 39.205 ;
     RECT  11.472 38.389 13.512 39.251 ;
     RECT  17.232 38.195 17.256 39.299 ;
     RECT  6.048 38.677 6.456 39.301 ;
     RECT  7.8 38.579 8.112 39.301 ;
     RECT  22.896 38.773 27.624 39.443 ;
     RECT  217.152 38.149 224.112 39.443 ;
     RECT  6.048 39.301 8.112 39.587 ;
     RECT  6.048 39.587 6.408 39.683 ;
     RECT  28.848 39.205 30.984 39.733 ;
     RECT  16.224 36.899 16.248 39.973 ;
     RECT  15.984 39.973 16.248 40.019 ;
     RECT  32.64 37.619 33.432 40.165 ;
     RECT  217.2 39.443 224.112 40.453 ;
     RECT  7.392 39.587 8.112 40.549 ;
     RECT  9.12 38.579 9.144 40.549 ;
     RECT  32.64 40.165 33.528 40.549 ;
     RECT  217.152 40.453 224.112 40.595 ;
     RECT  217.2 40.595 224.112 40.787 ;
     RECT  7.392 40.549 9.144 40.835 ;
     RECT  217.344 40.787 224.112 40.835 ;
     RECT  15.984 40.019 16.008 41.029 ;
     RECT  17.088 40.885 17.112 41.029 ;
     RECT  28.512 39.733 30.984 41.029 ;
     RECT  28.368 41.029 30.984 41.219 ;
     RECT  10.56 41.077 10.584 41.267 ;
     RECT  4.56 40.405 4.584 41.651 ;
     RECT  6.384 39.683 6.408 41.701 ;
     RECT  7.392 40.835 8.856 41.701 ;
     RECT  15.984 41.029 17.208 41.701 ;
     RECT  18.6 38.195 19.8 41.701 ;
     RECT  15.984 41.701 19.8 41.843 ;
     RECT  22.896 39.443 27.384 41.891 ;
     RECT  25.92 41.891 27.384 41.989 ;
     RECT  217.344 40.835 221.928 42.229 ;
     RECT  12.24 39.251 13.512 42.277 ;
     RECT  2.4 38.819 3.576 42.323 ;
     RECT  6.384 41.701 8.856 42.467 ;
     RECT  12.24 42.277 13.848 42.515 ;
     RECT  22.896 41.891 24.792 42.709 ;
     RECT  34.8 36.083 42.168 42.901 ;
     RECT  32.496 40.549 33.528 42.997 ;
     RECT  2.4 42.323 3 43.187 ;
     RECT  12.24 42.515 13.608 43.283 ;
     RECT  25.92 41.989 27.528 43.285 ;
     RECT  12.336 43.283 13.608 43.331 ;
     RECT  12.528 43.331 13.608 43.379 ;
     RECT  15.984 41.843 17.208 43.379 ;
     RECT  34.8 42.901 42.264 43.427 ;
     RECT  32.16 42.997 33.528 43.475 ;
     RECT  217.344 42.229 222.504 43.523 ;
     RECT  15.984 43.379 16.296 43.571 ;
     RECT  28.848 41.219 30.984 43.571 ;
     RECT  4.128 42.421 4.152 43.669 ;
     RECT  29.28 43.571 30.984 43.715 ;
     RECT  29.4 43.715 30.984 43.717 ;
     RECT  22.464 42.709 24.792 43.861 ;
     RECT  25.92 43.285 27.864 43.861 ;
     RECT  7.104 42.467 8.856 43.955 ;
     RECT  16.272 43.571 16.296 43.955 ;
     RECT  22.464 43.861 27.864 43.955 ;
     RECT  34.8 43.427 42.216 44.005 ;
     RECT  12.624 43.379 13.608 44.051 ;
     RECT  7.104 43.955 8.112 44.099 ;
     RECT  34.656 44.005 42.216 44.291 ;
     RECT  2.4 43.187 2.712 44.341 ;
     RECT  3.984 43.669 4.152 44.341 ;
     RECT  13.2 44.051 13.608 44.389 ;
     RECT  2.4 44.341 4.152 44.437 ;
     RECT  2.4 44.437 4.536 44.483 ;
     RECT  29.4 43.717 31.32 44.629 ;
     RECT  32.64 43.475 33.528 44.629 ;
     RECT  4.512 44.483 4.536 44.965 ;
     RECT  29.4 44.629 33.528 44.965 ;
     RECT  16.032 44.869 16.056 45.011 ;
     RECT  29.4 44.965 33.672 45.107 ;
     RECT  13.2 44.389 13.848 45.157 ;
     RECT  7.248 44.099 8.112 45.445 ;
     RECT  10.896 44.389 10.92 45.539 ;
     RECT  6.096 45.493 6.12 45.541 ;
     RECT  7.248 45.445 9.096 45.541 ;
     RECT  4.512 44.965 5.112 45.635 ;
     RECT  22.848 43.955 27.864 45.635 ;
     RECT  32.64 45.107 33.672 45.635 ;
     RECT  5.088 45.635 5.112 45.731 ;
     RECT  6.096 45.541 9.096 45.731 ;
     RECT  22.848 45.635 26.472 45.731 ;
     RECT  6.096 45.731 6.12 45.829 ;
     RECT  18.6 41.843 19.8 45.925 ;
     RECT  22.848 45.731 24.792 46.067 ;
     RECT  10.32 45.637 10.344 46.115 ;
     RECT  2.4 44.483 3.528 46.211 ;
     RECT  29.4 45.107 31.32 46.213 ;
     RECT  32.64 45.635 33.528 46.213 ;
     RECT  5.28 45.829 6.12 46.259 ;
     RECT  7.392 45.731 9.096 46.499 ;
     RECT  18.6 45.925 19.992 46.501 ;
     RECT  13.056 45.157 13.848 46.547 ;
     RECT  7.392 46.499 8.112 46.741 ;
     RECT  29.4 46.213 33.528 46.787 ;
     RECT  18.6 46.501 20.04 46.789 ;
     RECT  31.296 46.787 33.528 46.979 ;
     RECT  10.944 46.837 10.968 47.029 ;
     RECT  11.952 46.405 11.976 47.029 ;
     RECT  31.296 46.979 33.48 47.075 ;
     RECT  10.944 47.029 11.976 47.221 ;
     RECT  5.28 46.259 5.304 47.269 ;
     RECT  10.8 47.221 11.976 47.315 ;
     RECT  17.376 44.869 17.4 47.315 ;
     RECT  10.8 47.315 11.544 47.317 ;
     RECT  7.2 46.741 8.112 47.363 ;
     RECT  13.056 46.547 13.512 47.461 ;
     RECT  27.936 46.021 27.96 47.507 ;
     RECT  31.296 47.075 32.04 47.795 ;
     RECT  5.28 47.269 5.736 47.891 ;
     RECT  31.296 47.795 31.992 47.891 ;
     RECT  18.6 46.789 20.136 47.893 ;
     RECT  12.672 47.461 13.512 48.035 ;
     RECT  18.24 47.893 20.136 48.131 ;
     RECT  34.656 44.291 42.168 48.229 ;
     RECT  7.392 47.363 8.112 48.373 ;
     RECT  5.712 47.891 5.736 48.419 ;
     RECT  22.848 46.067 24.312 48.419 ;
     RECT  7.104 48.373 8.112 48.421 ;
     RECT  29.4 46.787 30.024 48.805 ;
     RECT  25.92 45.731 26.472 48.995 ;
     RECT  13.056 48.035 13.512 48.997 ;
     RECT  23.376 48.419 24.312 48.997 ;
     RECT  29.4 48.805 30.936 48.997 ;
     RECT  18.24 48.131 19.8 49.043 ;
     RECT  23.376 48.997 25.032 49.139 ;
     RECT  7.104 48.421 8.232 49.477 ;
     RECT  29.4 48.997 31.176 49.477 ;
     RECT  6.288 49.477 8.232 49.619 ;
     RECT  33.024 47.075 33.48 50.005 ;
     RECT  34.464 48.229 42.168 50.005 ;
     RECT  23.376 49.139 24.408 50.101 ;
     RECT  7.488 49.619 8.232 50.339 ;
     RECT  15.552 47.461 15.576 50.771 ;
     RECT  29.28 49.477 31.176 50.771 ;
     RECT  6.288 49.619 6.312 50.819 ;
     RECT  21.456 49.237 21.48 51.203 ;
     RECT  23.376 50.101 24.456 51.203 ;
     RECT  29.28 50.771 30.216 51.347 ;
     RECT  7.488 50.339 8.112 51.635 ;
     RECT  7.8 51.635 8.112 51.733 ;
     RECT  29.28 51.347 30.168 51.779 ;
     RECT  7.8 51.733 8.376 51.781 ;
     RECT  10.512 47.317 11.544 51.925 ;
     RECT  33.024 50.005 42.168 52.213 ;
     RECT  7.8 51.781 8.52 52.307 ;
     RECT  9.552 51.925 11.544 52.451 ;
     RECT  12.672 48.997 13.512 52.499 ;
     RECT  9.552 52.451 10.536 52.691 ;
     RECT  32.88 52.213 42.168 52.691 ;
     RECT  33.024 52.691 42.168 52.739 ;
     RECT  31.296 50.965 31.32 52.835 ;
     RECT  23.376 51.203 24.408 52.981 ;
     RECT  26.448 48.995 26.472 52.981 ;
     RECT  29.28 51.779 30.024 53.123 ;
     RECT  12.72 52.499 13.512 53.267 ;
     RECT  22.752 52.981 24.408 53.269 ;
     RECT  26.448 52.981 26.616 53.315 ;
     RECT  22.752 53.269 24.504 53.363 ;
     RECT  23.376 53.363 24.504 53.411 ;
     RECT  11.52 52.451 11.544 53.557 ;
     RECT  217.344 43.523 222.024 53.557 ;
     RECT  9.552 52.691 9.576 53.795 ;
     RECT  29.28 53.123 29.928 53.797 ;
     RECT  7.8 52.307 8.376 53.843 ;
     RECT  31.728 52.981 31.992 54.179 ;
     RECT  29.136 53.797 29.928 54.181 ;
     RECT  217.344 53.557 222.36 54.277 ;
     RECT  29.088 54.181 29.928 54.371 ;
     RECT  13.2 53.267 13.512 54.421 ;
     RECT  29.136 54.371 29.928 54.467 ;
     RECT  10.752 53.557 11.544 54.469 ;
     RECT  23.376 53.411 24.456 54.515 ;
     RECT  217.152 54.277 222.36 54.611 ;
     RECT  217.344 54.611 222.36 54.613 ;
     RECT  7.8 53.843 8.232 54.755 ;
     RECT  10.752 54.469 11.832 54.851 ;
     RECT  31.728 54.179 31.752 55.093 ;
     RECT  31.296 55.093 31.752 55.331 ;
     RECT  11.472 54.851 11.832 55.379 ;
     RECT  33.12 52.739 42.168 55.379 ;
     RECT  29.4 54.467 29.928 55.381 ;
     RECT  31.296 55.331 31.32 55.381 ;
     RECT  11.808 55.379 11.832 55.813 ;
     RECT  11.808 55.813 11.928 55.859 ;
     RECT  29.4 55.381 31.32 55.907 ;
     RECT  217.344 54.613 222.552 55.955 ;
     RECT  18.6 49.043 19.8 56.389 ;
     RECT  23.376 54.515 24.408 56.389 ;
     RECT  34.8 55.379 42.168 56.389 ;
     RECT  13.056 54.421 13.512 56.531 ;
     RECT  11.904 55.859 11.928 56.579 ;
     RECT  217.344 55.955 221.592 56.581 ;
     RECT  29.4 55.907 30.792 56.723 ;
     RECT  34.704 56.389 42.168 57.155 ;
     RECT  217.152 56.581 221.592 57.299 ;
     RECT  11.952 57.013 11.976 57.635 ;
     RECT  17.664 56.389 19.8 57.875 ;
     RECT  23.376 56.389 25.128 58.115 ;
     RECT  27.744 56.917 27.768 58.115 ;
     RECT  33.12 55.379 33.288 58.741 ;
     RECT  34.8 57.155 42.168 58.741 ;
     RECT  29.4 56.723 30.408 59.029 ;
     RECT  28.896 59.029 30.408 59.173 ;
     RECT  18.6 57.875 19.8 59.221 ;
     RECT  23.376 58.115 24.312 59.221 ;
     RECT  33.12 58.741 42.168 59.315 ;
     RECT  217.344 57.299 221.592 59.653 ;
     RECT  34.176 59.315 42.168 59.891 ;
     RECT  18.6 59.221 19.944 59.987 ;
     RECT  25.392 58.645 25.416 60.275 ;
     RECT  23.04 59.221 24.312 60.419 ;
     RECT  217.152 59.653 221.592 60.467 ;
     RECT  217.152 60.467 221.496 60.563 ;
     RECT  33.12 59.315 33.144 60.853 ;
     RECT  26.448 53.315 26.472 60.949 ;
     RECT  28.56 59.173 30.408 60.997 ;
     RECT  23.376 60.419 24.312 61.379 ;
     RECT  25.824 60.949 26.472 62.771 ;
     RECT  33.12 60.853 33.816 62.771 ;
     RECT  26.448 62.771 26.472 64.115 ;
     RECT  28.512 60.997 30.408 64.883 ;
     RECT  28.752 64.883 30.408 69.587 ;
     RECT  217.344 60.563 221.496 71.221 ;
     RECT  18.6 59.987 19.8 72.995 ;
     RECT  18.6 72.995 19.272 73.235 ;
     RECT  18.6 73.235 18.912 73.333 ;
     RECT  13.2 56.531 13.512 74.149 ;
     RECT  13.2 74.149 13.848 74.723 ;
     RECT  11.424 73.477 11.448 75.637 ;
     RECT  217.248 71.221 221.496 75.973 ;
     RECT  24 61.379 24.312 76.165 ;
     RECT  7.8 54.755 8.112 76.309 ;
     RECT  15.216 75.637 15.24 76.309 ;
     RECT  23.904 76.165 24.312 76.355 ;
     RECT  18.144 73.333 18.912 76.357 ;
     RECT  29.4 69.587 30.408 76.357 ;
     RECT  14.784 76.309 15.24 76.403 ;
     RECT  11.232 75.637 11.448 76.739 ;
     RECT  14.784 76.403 14.808 76.979 ;
     RECT  13.2 74.723 13.512 77.317 ;
     RECT  11.424 76.739 11.448 77.555 ;
     RECT  7.344 76.309 8.112 77.699 ;
     RECT  17.76 76.357 18.912 78.131 ;
     RECT  15.792 77.509 15.816 78.323 ;
     RECT  13.2 77.317 13.752 78.659 ;
     RECT  13.2 78.659 13.512 78.661 ;
     RECT  29.4 76.357 30.504 78.661 ;
     RECT  26.688 76.309 26.712 78.707 ;
     RECT  24 76.355 24.312 78.901 ;
     RECT  13.056 78.661 13.512 79.235 ;
     RECT  21.072 78.613 21.096 79.235 ;
     RECT  29.4 78.661 31.032 79.765 ;
     RECT  24 78.901 24.504 80.003 ;
     RECT  25.68 79.765 25.704 80.341 ;
     RECT  25.68 80.341 26.616 80.579 ;
     RECT  29.4 79.765 31.32 82.451 ;
     RECT  26.592 80.579 26.616 83.843 ;
     RECT  29.4 82.451 31.032 84.901 ;
     RECT  29.4 84.901 31.128 85.285 ;
     RECT  29.4 85.285 31.176 87.349 ;
     RECT  29.4 87.349 31.32 87.973 ;
     RECT  33.12 62.771 33.144 87.973 ;
     RECT  29.4 87.973 33.144 88.643 ;
     RECT  34.8 59.891 42.168 88.789 ;
     RECT  30.912 88.643 33.144 89.699 ;
     RECT  31.536 89.699 33.144 93.109 ;
     RECT  34.464 88.789 42.168 94.069 ;
     RECT  34.464 94.069 42.216 94.165 ;
     RECT  99.6 2.151 99.912 94.357 ;
     RECT  137.4 22.643 137.712 94.357 ;
     RECT  94.2 10.355 94.512 94.405 ;
     RECT  67.2 19.715 67.512 94.453 ;
     RECT  99.6 94.357 100.584 94.837 ;
     RECT  83.4 22.499 83.712 94.933 ;
     RECT  88.8 22.547 89.112 95.365 ;
     RECT  34.464 94.165 42.312 95.701 ;
     RECT  99.6 94.837 101.496 96.325 ;
     RECT  99.6 96.325 101.736 96.371 ;
     RECT  94.2 94.405 94.872 96.419 ;
     RECT  45.6 21.155 45.912 96.421 ;
     RECT  121.2 23.315 121.512 96.469 ;
     RECT  217.104 75.973 221.496 96.515 ;
     RECT  34.32 95.701 42.312 96.565 ;
     RECT  88.8 95.365 89.928 96.565 ;
     RECT  99.6 96.371 99.912 96.565 ;
     RECT  34.224 96.565 42.312 96.611 ;
     RECT  94.2 96.419 94.512 96.613 ;
     RECT  105 23.075 105.312 96.613 ;
     RECT  148.2 21.971 148.512 96.613 ;
     RECT  101.04 96.371 101.736 96.659 ;
     RECT  34.227 96.611 42.312 96.661 ;
     RECT  67.2 94.453 68.088 96.707 ;
     RECT  83.4 94.933 83.832 96.709 ;
     RECT  98.64 96.565 99.912 96.755 ;
     RECT  101.04 96.659 101.64 96.755 ;
     RECT  134.4 96.421 134.424 96.757 ;
     RECT  34.227 96.661 42.744 96.803 ;
     RECT  147.408 96.613 148.512 96.805 ;
     RECT  85.92 96.805 85.944 96.997 ;
     RECT  217.248 96.515 221.496 97.139 ;
     RECT  83.184 96.709 83.832 97.141 ;
     RECT  105 96.613 105.816 97.141 ;
     RECT  106.896 96.613 106.92 97.141 ;
     RECT  109.392 96.853 109.416 97.141 ;
     RECT  34.227 96.803 42.312 97.187 ;
     RECT  34.227 97.187 42.216 97.283 ;
     RECT  93.216 96.613 94.512 97.285 ;
     RECT  83.184 97.141 84.12 97.333 ;
     RECT  85.488 96.997 85.944 97.333 ;
     RECT  96.576 96.997 96.6 97.333 ;
     RECT  87.264 97.045 87.288 97.379 ;
     RECT  92.544 97.285 94.512 97.381 ;
     RECT  103.968 97.333 103.992 97.381 ;
     RECT  110.4 18.995 110.712 97.429 ;
     RECT  113.376 96.853 113.4 97.429 ;
     RECT  121.2 96.469 121.752 97.429 ;
     RECT  122.736 97.333 122.76 97.429 ;
     RECT  123.792 97.333 123.816 97.429 ;
     RECT  145.968 96.853 145.992 97.429 ;
     RECT  147.168 96.805 148.512 97.429 ;
     RECT  150.528 97.381 150.552 97.429 ;
     RECT  122.736 97.429 123.816 97.475 ;
     RECT  83.184 97.333 85.944 97.477 ;
     RECT  96.576 97.333 96.888 97.477 ;
     RECT  103.104 97.381 103.992 97.477 ;
     RECT  105 97.141 106.92 97.477 ;
     RECT  112.512 97.429 113.4 97.523 ;
     RECT  78 2.151 78.312 97.525 ;
     RECT  82.08 97.477 82.104 97.525 ;
     RECT  83.184 97.477 86.424 97.525 ;
     RECT  96.576 97.477 96.936 97.525 ;
     RECT  120.864 97.429 121.752 97.525 ;
     RECT  145.968 97.429 148.512 97.525 ;
     RECT  75.792 97.381 75.816 97.573 ;
     RECT  137.28 94.357 137.712 97.573 ;
     RECT  77.904 97.525 78.312 97.621 ;
     RECT  132 22.163 132.312 97.621 ;
     RECT  145.872 97.525 148.512 97.621 ;
     RECT  150.528 97.429 151.08 97.621 ;
     RECT  77.904 97.621 78.6 97.717 ;
     RECT  92.544 97.381 94.632 97.717 ;
     RECT  96.48 97.525 96.936 97.717 ;
     RECT  103.104 97.477 106.92 97.717 ;
     RECT  115.8 21.875 116.112 97.717 ;
     RECT  119.04 97.669 119.064 97.717 ;
     RECT  77.904 97.717 78.648 97.765 ;
     RECT  99.6 96.755 99.912 97.765 ;
     RECT  126.6 21.491 126.912 97.765 ;
     RECT  72.6 16.835 72.912 97.813 ;
     RECT  77.904 97.765 79.128 97.813 ;
     RECT  99.6 97.765 100.056 97.813 ;
     RECT  101.04 96.755 101.064 97.813 ;
     RECT  131.904 97.621 132.312 97.813 ;
     RECT  80.928 97.813 80.952 97.861 ;
     RECT  92.544 97.717 94.824 97.861 ;
     RECT  99.6 97.813 101.064 97.861 ;
     RECT  102.624 97.717 106.92 97.861 ;
     RECT  110.4 97.429 111.048 97.861 ;
     RECT  118.128 97.717 119.064 97.861 ;
     RECT  134.4 96.757 134.52 97.861 ;
     RECT  145.872 97.621 148.728 97.907 ;
     RECT  67.2 96.707 67.512 97.909 ;
     RECT  77.904 97.813 79.8 97.909 ;
     RECT  80.928 97.861 81.096 97.909 ;
     RECT  82.08 97.525 86.424 97.909 ;
     RECT  88.8 96.565 90.648 97.909 ;
     RECT  92.4 97.861 94.824 97.909 ;
     RECT  96.144 97.717 96.936 97.909 ;
     RECT  102.624 97.861 107.592 97.909 ;
     RECT  150.528 97.621 151.128 97.909 ;
     RECT  117.744 97.861 119.064 97.955 ;
     RECT  77.904 97.909 86.424 98.003 ;
     RECT  92.4 97.909 96.936 98.003 ;
     RECT  43.2 97.957 43.224 98.005 ;
     RECT  72.384 97.813 72.912 98.005 ;
     RECT  137.28 97.573 137.832 98.005 ;
     RECT  145.872 97.907 148.512 98.005 ;
     RECT  150.528 97.909 151.608 98.005 ;
     RECT  77.904 98.003 81.48 98.051 ;
     RECT  76.896 96.853 76.92 98.053 ;
     RECT  77.904 98.051 79.848 98.053 ;
     RECT  88.8 97.909 90.984 98.053 ;
     RECT  99.504 97.861 101.064 98.195 ;
     RECT  130.752 95.077 130.776 98.197 ;
     RECT  72.336 98.005 72.912 98.245 ;
     RECT  92.4 98.003 96.888 98.339 ;
     RECT  115.8 97.717 116.328 98.341 ;
     RECT  153.6 2.151 153.912 98.341 ;
     RECT  65.184 97.621 65.208 98.389 ;
     RECT  82.512 98.003 86.424 98.389 ;
     RECT  109.344 97.141 109.416 98.437 ;
     RECT  110.4 97.861 111.288 98.437 ;
     RECT  131.904 97.813 133.08 98.437 ;
     RECT  139.776 98.389 139.8 98.437 ;
     RECT  153.36 98.341 153.912 98.437 ;
     RECT  34.227 97.283 42.168 98.485 ;
     RECT  43.2 98.005 43.32 98.485 ;
     RECT  115.8 98.341 116.472 98.485 ;
     RECT  65.184 98.389 66.072 98.531 ;
     RECT  80.928 98.051 81.48 98.531 ;
     RECT  115.8 98.485 116.664 98.533 ;
     RECT  76.896 98.053 79.848 98.579 ;
     RECT  109.344 98.437 111.288 98.581 ;
     RECT  122.976 97.475 123.816 98.581 ;
     RECT  134.4 97.861 134.664 98.581 ;
     RECT  136.08 96.709 136.104 98.581 ;
     RECT  142.8 22.691 143.112 98.581 ;
     RECT  102.192 97.909 107.592 98.627 ;
     RECT  61.8 2.151 62.112 98.629 ;
     RECT  120.528 97.525 121.752 98.629 ;
     RECT  130.32 98.197 130.776 98.629 ;
     RECT  65.184 98.531 65.208 98.675 ;
     RECT  99.504 98.195 100.968 98.675 ;
     RECT  122.976 98.581 124.296 98.675 ;
     RECT  134.352 98.581 134.664 98.677 ;
     RECT  137.28 98.005 137.928 98.677 ;
     RECT  139.44 98.437 139.8 98.725 ;
     RECT  150.528 98.005 151.896 98.725 ;
     RECT  72.336 98.245 73.56 98.773 ;
     RECT  137.28 98.677 138.408 98.773 ;
     RECT  139.44 98.725 140.76 98.773 ;
     RECT  123.552 98.675 124.296 98.821 ;
     RECT  117.744 97.955 118.296 98.869 ;
     RECT  34.227 98.485 43.32 98.915 ;
     RECT  52.368 98.005 52.392 98.915 ;
     RECT  61.68 98.629 62.112 98.915 ;
     RECT  115.68 98.533 116.664 98.917 ;
     RECT  123.552 98.821 124.872 98.917 ;
     RECT  126.288 97.765 127.704 98.917 ;
     RECT  134.256 98.677 134.664 98.917 ;
     RECT  136.08 98.581 136.248 98.917 ;
     RECT  131.76 98.437 133.08 98.965 ;
     RECT  134.256 98.917 136.248 98.965 ;
     RECT  44.928 96.421 45.912 99.011 ;
     RECT  120.288 98.629 121.752 99.013 ;
     RECT  129.984 98.629 130.776 99.013 ;
     RECT  131.76 98.965 136.248 99.013 ;
     RECT  145.344 98.005 148.512 99.013 ;
     RECT  117.696 98.869 118.296 99.061 ;
     RECT  98.448 97.621 98.472 99.109 ;
     RECT  82.512 98.389 86.664 99.155 ;
     RECT  72.336 98.773 73.608 99.157 ;
     RECT  112.512 97.523 112.536 99.157 ;
     RECT  113.904 97.909 113.928 99.157 ;
     RECT  145.344 99.013 149.4 99.157 ;
     RECT  150.432 98.725 151.896 99.157 ;
     RECT  71.664 99.157 73.608 99.205 ;
     RECT  108.816 98.581 111.288 99.301 ;
     RECT  83.232 99.155 86.664 99.349 ;
     RECT  112.512 99.157 112.824 99.397 ;
     RECT  113.904 99.157 114.072 99.397 ;
     RECT  98.064 99.109 98.472 99.443 ;
     RECT  142.416 98.581 143.352 99.443 ;
     RECT  77.184 98.579 79.848 99.445 ;
     RECT  129.072 99.013 136.248 99.491 ;
     RECT  77.184 99.445 79.992 99.541 ;
     RECT  81.12 98.531 81.48 99.541 ;
     RECT  112.512 99.397 114.072 99.541 ;
     RECT  115.152 98.917 116.664 99.541 ;
     RECT  117.696 99.061 118.344 99.541 ;
     RECT  34.227 98.915 43.224 99.587 ;
     RECT  71.136 99.205 73.608 99.589 ;
     RECT  74.64 99.541 74.664 99.589 ;
     RECT  123.552 98.917 127.704 99.589 ;
     RECT  142.512 99.443 143.352 99.589 ;
     RECT  77.184 99.541 81.48 99.683 ;
     RECT  92.544 98.339 96.888 99.683 ;
     RECT  80.88 99.683 81.48 99.685 ;
     RECT  83.232 99.349 87.096 99.685 ;
     RECT  88.08 98.053 90.984 99.685 ;
     RECT  92.544 99.683 96.456 99.685 ;
     RECT  108.72 99.301 111.288 99.685 ;
     RECT  112.32 99.541 114.072 99.685 ;
     RECT  120.288 99.013 122.424 99.685 ;
     RECT  123.552 99.589 128.04 99.685 ;
     RECT  137.28 98.773 140.76 99.685 ;
     RECT  34.227 99.587 42.984 99.731 ;
     RECT  47.904 99.157 47.928 99.731 ;
     RECT  71.136 99.589 74.664 99.731 ;
     RECT  75.648 97.573 75.816 99.731 ;
     RECT  83.232 99.685 90.984 99.781 ;
     RECT  92.448 99.685 96.456 99.781 ;
     RECT  142.512 99.589 143.976 99.781 ;
     RECT  145.344 99.157 151.896 99.781 ;
     RECT  108.72 99.685 114.072 99.827 ;
     RECT  102.192 98.627 102.792 99.829 ;
     RECT  103.92 98.627 107.592 99.829 ;
     RECT  83.232 99.781 96.456 100.019 ;
     RECT  115.152 99.541 118.344 100.021 ;
     RECT  53.568 98.869 53.592 100.067 ;
     RECT  102.192 99.829 107.592 100.067 ;
     RECT  99.504 98.675 100.632 100.069 ;
     RECT  92.448 100.019 96.456 100.115 ;
     RECT  98.064 99.443 98.28 100.163 ;
     RECT  108.72 99.827 113.976 100.163 ;
     RECT  115.152 100.021 118.536 100.259 ;
     RECT  142.512 99.781 151.896 100.259 ;
     RECT  71.136 99.731 74.472 100.261 ;
     RECT  77.184 99.683 79.896 100.261 ;
     RECT  41.856 99.731 42.984 100.355 ;
     RECT  108.72 100.163 111.576 100.355 ;
     RECT  142.704 100.259 151.896 100.355 ;
     RECT  115.152 100.259 116.664 100.357 ;
     RECT  55.344 99.397 55.368 100.499 ;
     RECT  115.008 100.357 116.664 100.547 ;
     RECT  76.896 100.261 79.896 100.595 ;
     RECT  70.8 100.261 74.472 100.597 ;
     RECT  99.456 100.069 100.632 100.645 ;
     RECT  132 99.491 136.248 100.645 ;
     RECT  137.232 99.685 140.76 100.645 ;
     RECT  75.648 99.731 75.672 100.739 ;
     RECT  92.544 100.115 96.456 100.741 ;
     RECT  117.696 100.259 118.536 100.789 ;
     RECT  123.504 99.685 128.04 100.789 ;
     RECT  129.072 99.491 130.968 100.789 ;
     RECT  79.632 100.595 79.896 100.837 ;
     RECT  80.88 99.685 81.768 100.837 ;
     RECT  112.56 100.163 113.976 100.837 ;
     RECT  115.008 100.547 116.28 100.837 ;
     RECT  123.504 100.789 130.968 100.837 ;
     RECT  132 100.645 140.76 100.837 ;
     RECT  75.696 100.837 75.72 100.885 ;
     RECT  76.896 100.595 78.6 100.885 ;
     RECT  70.272 100.597 74.472 100.931 ;
     RECT  117.696 100.789 118.584 101.077 ;
     RECT  92.544 100.741 96.6 101.123 ;
     RECT  67.2 97.909 68.04 101.125 ;
     RECT  69.264 98.437 69.288 101.125 ;
     RECT  67.2 101.125 69.288 101.173 ;
     RECT  70.272 100.931 74.184 101.173 ;
     RECT  93.984 101.123 96.6 101.173 ;
     RECT  99.456 100.645 100.92 101.173 ;
     RECT  99.264 101.173 100.92 101.317 ;
     RECT  102.288 100.067 107.592 101.317 ;
     RECT  117.696 101.077 118.968 101.363 ;
     RECT  79.632 100.837 81.768 101.365 ;
     RECT  83.232 100.019 90.984 101.365 ;
     RECT  142.8 100.355 151.896 101.365 ;
     RECT  142.704 101.365 152.184 101.411 ;
     RECT  79.632 101.365 90.984 101.413 ;
     RECT  117.744 101.363 118.968 101.413 ;
     RECT  119.952 99.685 122.424 101.413 ;
     RECT  151.104 101.411 152.184 101.413 ;
     RECT  153.36 98.437 154.152 101.413 ;
     RECT  92.544 101.123 92.712 101.507 ;
     RECT  123.504 100.837 140.76 101.507 ;
     RECT  108.816 100.355 111.576 101.605 ;
     RECT  75.696 100.885 78.6 101.701 ;
     RECT  79.632 101.413 91.56 101.701 ;
     RECT  123.504 101.507 136.104 101.747 ;
     RECT  142.704 101.411 150.12 101.747 ;
     RECT  93.984 101.173 97.128 101.891 ;
     RECT  92.592 101.507 92.712 101.987 ;
     RECT  94.032 101.891 97.128 101.989 ;
     RECT  98.256 100.163 98.28 101.989 ;
     RECT  137.232 101.507 140.76 101.989 ;
     RECT  75.696 101.701 91.56 102.131 ;
     RECT  99.264 101.317 107.592 102.131 ;
     RECT  112.56 100.837 116.28 102.179 ;
     RECT  94.032 101.989 98.28 102.181 ;
     RECT  99.264 102.131 107.208 102.181 ;
     RECT  34.227 99.731 40.824 102.275 ;
     RECT  79.68 102.131 91.56 102.467 ;
     RECT  137.232 101.989 141.192 102.565 ;
     RECT  66.144 99.685 66.168 102.659 ;
     RECT  117.744 101.413 122.424 102.659 ;
     RECT  129.072 101.747 136.104 102.709 ;
     RECT  137.184 102.565 141.192 102.709 ;
     RECT  108.576 101.605 111.576 102.757 ;
     RECT  112.56 102.179 116.112 102.757 ;
     RECT  91.536 102.467 91.56 102.805 ;
     RECT  92.592 101.987 92.616 102.805 ;
     RECT  94.032 102.181 107.208 102.899 ;
     RECT  142.704 101.747 149.976 102.947 ;
     RECT  142.704 102.947 146.232 102.995 ;
     RECT  91.536 102.805 92.616 102.997 ;
     RECT  94.032 102.899 96.6 102.997 ;
     RECT  117.84 102.659 122.424 103.237 ;
     RECT  123.504 101.747 128.04 103.237 ;
     RECT  75.696 102.131 78.696 103.285 ;
     RECT  79.68 102.467 90.552 103.285 ;
     RECT  129.072 102.709 141.192 103.333 ;
     RECT  142.704 102.995 144.168 103.333 ;
     RECT  36.912 102.275 40.824 103.379 ;
     RECT  38.448 103.379 40.824 103.523 ;
     RECT  117.84 103.237 128.04 103.525 ;
     RECT  129.072 103.333 144.168 103.525 ;
     RECT  36.912 103.379 37.416 103.619 ;
     RECT  117.84 103.525 144.168 103.619 ;
     RECT  75.696 103.285 90.552 103.669 ;
     RECT  91.536 102.997 96.6 103.669 ;
     RECT  108.576 102.757 116.112 103.669 ;
     RECT  75.696 103.669 96.6 103.715 ;
     RECT  67.2 101.173 74.184 103.717 ;
     RECT  37.392 103.619 37.416 103.763 ;
     RECT  151.104 101.413 154.152 103.763 ;
     RECT  98.256 102.899 107.208 103.859 ;
     RECT  137.184 103.619 144.168 103.859 ;
     RECT  147.216 102.947 149.976 103.907 ;
     RECT  75.696 103.715 76.728 104.003 ;
     RECT  108.576 103.669 116.52 104.005 ;
     RECT  117.84 103.619 136.2 104.005 ;
     RECT  67.2 103.717 74.472 104.053 ;
     RECT  145.344 102.995 146.232 104.101 ;
     RECT  147.216 103.907 149.88 104.101 ;
     RECT  137.232 103.859 144.168 104.149 ;
     RECT  145.344 104.101 149.88 104.149 ;
     RECT  65.28 103.141 65.304 104.197 ;
     RECT  108.576 104.005 136.2 104.243 ;
     RECT  108.576 104.243 132.792 104.339 ;
     RECT  66.72 104.053 74.472 104.533 ;
     RECT  75.696 104.003 75.72 104.533 ;
     RECT  77.808 103.715 96.6 104.821 ;
     RECT  98.304 103.859 107.208 104.821 ;
     RECT  77.808 104.821 107.208 104.867 ;
     RECT  134.016 104.243 136.2 105.059 ;
     RECT  77.808 104.867 90.888 105.109 ;
     RECT  76.704 104.003 76.728 105.155 ;
     RECT  134.4 105.059 136.2 105.205 ;
     RECT  137.232 104.149 149.88 105.205 ;
     RECT  108.576 104.339 129.72 105.397 ;
     RECT  65.28 104.197 65.352 105.445 ;
     RECT  66.72 104.533 75.72 105.445 ;
     RECT  92.064 104.867 107.208 105.445 ;
     RECT  108.192 105.397 129.72 105.445 ;
     RECT  92.064 105.445 129.72 105.637 ;
     RECT  130.752 104.339 132.792 105.637 ;
     RECT  92.064 105.637 132.792 105.683 ;
     RECT  65.28 105.445 75.72 105.923 ;
     RECT  134.4 105.205 149.88 105.973 ;
     RECT  151.2 103.763 154.152 105.973 ;
     RECT  34.227 102.275 35.64 106.021 ;
     RECT  34.224 106.021 35.64 106.067 ;
     RECT  92.256 105.683 132.792 106.211 ;
     RECT  134.4 105.973 154.152 106.211 ;
     RECT  134.4 106.211 145.704 106.451 ;
     RECT  60.144 95.077 60.168 106.643 ;
     RECT  92.256 106.211 113.832 106.837 ;
     RECT  147.216 106.211 154.152 106.837 ;
     RECT  39.024 103.523 40.824 106.883 ;
     RECT  142.464 106.451 145.704 107.027 ;
     RECT  114.816 106.211 132.792 107.125 ;
     RECT  31.536 93.109 33.24 107.219 ;
     RECT  77.76 105.109 90.888 107.219 ;
     RECT  65.28 105.923 68.088 107.269 ;
     RECT  69.264 105.923 75.72 107.269 ;
     RECT  53.616 101.317 53.64 107.315 ;
     RECT  92.208 106.837 113.832 107.507 ;
     RECT  134.4 106.451 141.48 107.557 ;
     RECT  142.464 107.027 144.744 107.557 ;
     RECT  108.528 107.507 113.832 107.605 ;
     RECT  114.816 107.125 132.84 107.605 ;
     RECT  65.28 107.269 75.72 107.651 ;
     RECT  147.216 106.837 154.2 107.653 ;
     RECT  65.808 107.651 75.72 107.797 ;
     RECT  39.024 106.883 40.512 107.891 ;
     RECT  108.528 107.605 132.84 107.891 ;
     RECT  109.968 107.891 132.84 107.939 ;
     RECT  146.256 107.653 154.2 107.939 ;
     RECT  152.832 107.939 154.2 108.035 ;
     RECT  92.208 107.507 107.208 108.323 ;
     RECT  146.256 107.939 151.848 108.323 ;
     RECT  147.312 108.323 151.848 108.419 ;
     RECT  65.808 107.797 76.488 108.469 ;
     RECT  77.76 107.219 84.984 108.469 ;
     RECT  65.808 108.469 84.984 108.611 ;
     RECT  109.968 107.939 132.696 108.611 ;
     RECT  64.8 107.701 64.824 108.709 ;
     RECT  65.808 108.611 74.136 108.709 ;
     RECT  112.8 108.611 132.696 108.755 ;
     RECT  64.8 108.709 74.136 108.995 ;
     RECT  75.12 108.611 84.984 109.141 ;
     RECT  85.968 107.219 90.888 109.141 ;
     RECT  92.208 108.323 97.8 109.141 ;
     RECT  92.16 109.141 97.8 109.285 ;
     RECT  98.784 108.323 107.208 109.285 ;
     RECT  122.976 108.755 132.696 109.333 ;
     RECT  134.4 107.557 144.744 109.333 ;
     RECT  108.528 107.891 108.696 109.381 ;
     RECT  109.968 108.611 111.72 109.381 ;
     RECT  146.256 108.323 146.28 109.427 ;
     RECT  134.4 109.333 144.84 109.429 ;
     RECT  64.8 108.995 67.944 109.475 ;
     RECT  122.976 109.333 132.744 109.525 ;
     RECT  133.824 109.429 144.84 109.525 ;
     RECT  39.168 107.891 40.512 109.571 ;
     RECT  69.264 108.995 74.136 109.571 ;
     RECT  147.36 108.419 151.848 109.765 ;
     RECT  153.216 108.035 154.2 109.765 ;
     RECT  122.976 109.525 144.84 109.909 ;
     RECT  112.8 108.755 121.992 110.053 ;
     RECT  122.976 109.909 145.128 110.053 ;
     RECT  75.12 109.141 90.888 110.243 ;
     RECT  74.112 109.571 74.136 110.245 ;
     RECT  75.12 110.243 76.728 110.245 ;
     RECT  65.808 109.475 67.944 110.341 ;
     RECT  69.264 109.571 73.128 110.341 ;
     RECT  92.16 109.285 107.208 110.341 ;
     RECT  112.8 110.053 145.128 110.341 ;
     RECT  112.8 110.341 145.752 110.533 ;
     RECT  147.36 109.765 154.2 110.533 ;
     RECT  34.32 106.067 35.64 110.627 ;
     RECT  64.8 109.475 64.824 110.819 ;
     RECT  180.6 2.151 180.912 110.821 ;
     RECT  85.92 110.243 90.888 110.915 ;
     RECT  74.112 110.245 76.728 110.963 ;
     RECT  112.8 110.533 154.2 111.011 ;
     RECT  74.112 110.963 76.584 111.059 ;
     RECT  159 2.151 159.312 111.061 ;
     RECT  65.808 110.341 73.128 111.155 ;
     RECT  77.808 110.243 84.84 111.155 ;
     RECT  115.488 111.011 154.2 111.155 ;
     RECT  166.416 110.821 166.44 111.157 ;
     RECT  115.488 111.155 152.232 111.203 ;
     RECT  86.112 110.915 90.888 111.395 ;
     RECT  161.28 111.013 161.304 111.541 ;
     RECT  92.16 110.341 107.448 111.587 ;
     RECT  77.808 111.155 84.168 111.637 ;
     RECT  183.792 111.109 183.816 111.637 ;
     RECT  90.864 111.395 90.888 111.685 ;
     RECT  92.16 111.587 107.208 111.685 ;
     RECT  161.28 111.541 161.832 111.685 ;
     RECT  163.008 110.821 163.032 111.685 ;
     RECT  115.488 111.203 143.112 111.731 ;
     RECT  31.92 107.219 33.24 111.733 ;
     RECT  34.416 110.627 35.64 111.733 ;
     RECT  68.976 111.155 73.128 111.827 ;
     RECT  115.488 111.731 121.848 111.827 ;
     RECT  169.8 2.151 170.112 111.829 ;
     RECT  115.536 111.827 121.848 111.923 ;
     RECT  214.32 111.781 214.344 111.923 ;
     RECT  71.808 111.827 73.128 111.925 ;
     RECT  74.112 111.059 76.008 111.925 ;
     RECT  169.68 111.829 170.112 111.925 ;
     RECT  41.904 100.355 42.984 111.971 ;
     RECT  115.536 111.923 117.48 111.971 ;
     RECT  118.512 111.923 121.848 112.019 ;
     RECT  175.2 2.151 175.512 112.021 ;
     RECT  77.76 111.637 84.168 112.067 ;
     RECT  68.976 111.827 70.824 112.115 ;
     RECT  112.992 111.011 114.264 112.115 ;
     RECT  68.976 112.115 70.68 112.163 ;
     RECT  118.512 112.019 121.704 112.163 ;
     RECT  144.192 111.203 151.848 112.163 ;
     RECT  164.4 23.027 164.712 112.165 ;
     RECT  165.792 111.157 166.44 112.165 ;
     RECT  77.808 112.067 84.168 112.211 ;
     RECT  77.856 112.211 84.168 112.213 ;
     RECT  168.048 111.877 168.072 112.213 ;
     RECT  90.864 111.685 107.208 112.259 ;
     RECT  118.56 112.163 121.704 112.259 ;
     RECT  71.808 111.925 76.008 112.307 ;
     RECT  144.192 112.163 144.6 112.355 ;
     RECT  145.728 112.163 151.848 112.355 ;
     RECT  86.112 111.395 89.496 112.357 ;
     RECT  90.864 112.259 94.968 112.357 ;
     RECT  153.216 111.155 154.2 112.405 ;
     RECT  183.792 111.637 184.104 112.405 ;
     RECT  86.112 112.357 94.968 112.451 ;
     RECT  122.976 111.731 143.112 112.451 ;
     RECT  42.864 111.971 42.984 112.499 ;
     RECT  186 2.151 186.312 112.501 ;
     RECT  67.104 111.155 67.944 112.547 ;
     RECT  147.024 112.355 151.848 112.691 ;
     RECT  153.216 112.405 154.296 112.691 ;
     RECT  186 112.501 186.6 112.693 ;
     RECT  86.112 112.451 92.664 112.741 ;
     RECT  115.584 111.971 117.48 112.787 ;
     RECT  217.44 97.139 221.496 112.787 ;
     RECT  183.6 112.405 184.104 112.789 ;
     RECT  68.976 112.163 70.488 112.883 ;
     RECT  71.808 112.307 75.768 112.883 ;
     RECT  108.528 109.381 111.72 112.883 ;
     RECT  117.456 112.787 117.48 112.883 ;
     RECT  122.976 112.451 132.84 112.883 ;
     RECT  144.192 112.355 144.216 112.883 ;
     RECT  147.024 112.691 150.168 112.883 ;
     RECT  159 111.061 159.576 112.883 ;
     RECT  161.28 111.685 163.032 112.883 ;
     RECT  164.4 112.165 166.44 112.883 ;
     RECT  168.048 112.213 168.12 112.883 ;
     RECT  169.248 111.925 170.112 112.883 ;
     RECT  174.384 112.021 175.512 112.883 ;
     RECT  113.472 112.115 114.264 112.885 ;
     RECT  147.024 112.883 149.64 112.931 ;
     RECT  113.472 112.885 114.552 112.933 ;
     RECT  115.584 112.787 116.28 112.933 ;
     RECT  185.904 112.693 186.6 112.933 ;
     RECT  118.704 112.259 121.704 112.979 ;
     RECT  161.28 112.883 161.832 112.979 ;
     RECT  165.84 112.883 166.392 112.979 ;
     RECT  168.048 112.883 168.072 112.979 ;
     RECT  185.136 112.933 186.6 112.981 ;
     RECT  109.776 112.883 111.72 113.027 ;
     RECT  183.024 112.789 184.104 113.029 ;
     RECT  185.136 112.981 186.888 113.029 ;
     RECT  42.864 112.499 42.888 113.075 ;
     RECT  133.92 112.451 143.112 113.075 ;
     RECT  85.776 112.741 92.664 113.077 ;
     RECT  153.216 112.691 153.912 113.123 ;
     RECT  96.048 112.259 107.208 113.125 ;
     RECT  108.528 112.883 108.696 113.125 ;
     RECT  183.024 113.029 186.888 113.125 ;
     RECT  113.472 112.933 116.28 113.171 ;
     RECT  140.448 113.075 143.112 113.171 ;
     RECT  77.856 112.213 84.36 113.219 ;
     RECT  110.016 113.027 111.72 113.219 ;
     RECT  133.92 113.075 139.128 113.219 ;
     RECT  147.024 112.931 149.256 113.219 ;
     RECT  110.016 113.219 111.24 113.267 ;
     RECT  122.976 112.883 132.696 113.267 ;
     RECT  133.92 113.219 136.104 113.267 ;
     RECT  182.4 113.125 186.888 113.267 ;
     RECT  110.016 113.267 111.192 113.315 ;
     RECT  145.728 112.355 145.992 113.365 ;
     RECT  147.024 113.219 147.048 113.365 ;
     RECT  134.304 113.267 136.104 113.411 ;
     RECT  13.2 79.235 13.512 113.413 ;
     RECT  68.976 112.883 70.152 113.459 ;
     RECT  71.808 112.883 74.856 113.459 ;
     RECT  77.904 113.219 84.36 113.459 ;
     RECT  85.536 113.077 92.664 113.459 ;
     RECT  96.048 113.125 108.696 113.459 ;
     RECT  110.16 113.315 111.192 113.459 ;
     RECT  113.472 113.171 113.976 113.459 ;
     RECT  118.752 112.979 121.704 113.459 ;
     RECT  123.648 113.267 132.696 113.459 ;
     RECT  134.304 113.411 134.712 113.459 ;
     RECT  145.728 113.365 147.048 113.459 ;
     RECT  148.2 113.219 149.256 113.459 ;
     RECT  151.392 112.691 151.848 113.459 ;
     RECT  161.28 112.979 161.304 113.459 ;
     RECT  78 113.459 79.8 113.507 ;
     RECT  80.928 113.459 84.36 113.507 ;
     RECT  86.832 113.459 89.112 113.507 ;
     RECT  94.2 112.451 94.968 113.507 ;
     RECT  96.048 113.459 107.112 113.507 ;
     RECT  118.848 113.459 121.608 113.507 ;
     RECT  123.648 113.459 128.328 113.507 ;
     RECT  142.656 113.171 143.112 113.507 ;
     RECT  151.824 113.459 151.848 113.507 ;
     RECT  217.536 112.787 221.496 113.507 ;
     RECT  39.456 109.571 40.512 113.555 ;
     RECT  85.536 113.459 85.8 113.555 ;
     RECT  90.144 113.459 92.664 113.555 ;
     RECT  94.2 113.507 94.824 113.555 ;
     RECT  96.048 113.507 106.056 113.555 ;
     RECT  110.16 113.459 111 113.555 ;
     RECT  140.448 113.171 141.432 113.555 ;
     RECT  65.808 111.155 65.832 113.603 ;
     RECT  72.384 113.459 74.856 113.603 ;
     RECT  87.072 113.507 89.112 113.603 ;
     RECT  104.256 113.555 106.056 113.603 ;
     RECT  217.536 113.507 221.208 113.603 ;
     RECT  180.6 110.821 181.272 113.651 ;
     RECT  72.6 113.603 74.856 113.699 ;
     RECT  78 113.507 79.704 113.699 ;
     RECT  115.104 113.171 116.28 113.699 ;
     RECT  141.312 113.555 141.432 113.699 ;
     RECT  90.864 113.555 91.8 113.747 ;
     RECT  108.528 113.459 108.696 113.747 ;
     RECT  115.104 113.699 116.112 113.747 ;
     RECT  119.664 113.507 121.608 113.747 ;
     RECT  134.304 113.459 134.52 113.747 ;
     RECT  72.6 113.699 74.136 113.795 ;
     RECT  80.928 113.507 83.712 113.795 ;
     RECT  85.536 113.555 85.56 113.795 ;
     RECT  90.864 113.747 91.752 113.795 ;
     RECT  104.448 113.603 106.056 113.795 ;
     RECT  110.16 113.555 110.712 113.795 ;
     RECT  113.28 113.509 113.4 113.795 ;
     RECT  159 112.883 159.528 113.795 ;
     RECT  217.536 113.603 219.96 113.795 ;
     RECT  80.928 113.795 81.912 113.843 ;
     RECT  94.2 113.555 94.632 113.843 ;
     RECT  96.192 113.555 102.936 113.843 ;
     RECT  108.672 113.747 108.696 113.843 ;
     RECT  13.2 113.413 13.656 113.845 ;
     RECT  67.104 112.547 67.512 113.891 ;
     RECT  110.304 113.795 110.712 113.891 ;
     RECT  221.184 113.603 221.208 113.891 ;
     RECT  13.2 113.845 14.184 113.941 ;
     RECT  13.2 113.941 14.664 113.989 ;
     RECT  68.976 113.459 69.864 114.035 ;
     RECT  81.888 113.843 81.912 114.035 ;
     RECT  87.216 113.603 89.112 114.035 ;
     RECT  91.44 113.795 91.752 114.035 ;
     RECT  96.192 113.843 102.408 114.035 ;
     RECT  107.088 113.507 107.112 114.035 ;
     RECT  115.68 113.747 116.112 114.035 ;
     RECT  123.648 113.507 128.184 114.035 ;
     RECT  129.36 113.459 132.648 114.035 ;
     RECT  146.496 113.459 147.048 114.035 ;
     RECT  104.448 113.795 105.312 114.083 ;
     RECT  119.664 113.747 121.512 114.083 ;
     RECT  136.08 113.411 136.104 114.083 ;
     RECT  141.312 113.699 141.336 114.083 ;
     RECT  217.632 113.795 219.96 114.083 ;
     RECT  58.176 96.661 58.2 114.131 ;
     RECT  72.6 113.795 73.368 114.131 ;
     RECT  137.4 113.219 139.128 114.131 ;
     RECT  91.728 114.035 91.752 114.179 ;
     RECT  96.384 114.035 101.736 114.179 ;
     RECT  129.36 114.035 130.488 114.179 ;
     RECT  188.496 113.125 188.52 114.181 ;
     RECT  97.632 114.179 101.736 114.227 ;
     RECT  123.648 114.035 128.136 114.227 ;
     RECT  79.68 113.699 79.704 114.275 ;
     RECT  87.216 114.035 87.24 114.275 ;
     RECT  96.384 114.179 96.552 114.275 ;
     RECT  97.968 114.227 101.736 114.275 ;
     RECT  134.496 113.747 134.52 114.275 ;
     RECT  72.6 114.131 73.032 114.323 ;
     RECT  96.528 114.275 96.552 114.323 ;
     RECT  113.28 113.795 113.304 114.323 ;
     RECT  120.432 114.083 121.512 114.323 ;
     RECT  217.632 114.083 218.712 114.323 ;
     RECT  183.024 113.267 186.888 114.325 ;
     RECT  188.112 114.181 188.52 114.325 ;
     RECT  129.936 114.179 129.96 114.371 ;
     RECT  214.32 114.037 214.344 114.371 ;
     RECT  219.936 114.083 219.96 114.371 ;
     RECT  178.416 114.229 178.44 114.419 ;
     RECT  139.104 114.131 139.128 114.421 ;
     RECT  183.024 114.325 188.52 114.421 ;
     RECT  137.4 114.131 137.832 114.467 ;
     RECT  12.72 113.989 14.664 114.469 ;
     RECT  2.4 46.211 2.712 114.489 ;
     RECT  7.8 77.699 8.112 114.489 ;
     RECT  18.6 78.131 18.912 114.489 ;
     RECT  24 80.003 24.312 114.489 ;
     RECT  29.4 88.643 29.712 114.489 ;
     RECT  40.2 113.555 40.512 114.489 ;
     RECT  45.6 99.011 45.912 114.489 ;
     RECT  51 23.363 51.312 114.489 ;
     RECT  56.4 2.151 56.712 114.489 ;
     RECT  61.8 98.915 62.112 114.489 ;
     RECT  67.2 113.891 67.512 114.489 ;
     RECT  72.6 114.323 72.912 114.489 ;
     RECT  78 113.699 78.312 114.489 ;
     RECT  83.4 113.795 83.712 114.489 ;
     RECT  88.8 114.035 89.112 114.489 ;
     RECT  94.2 113.843 94.512 114.489 ;
     RECT  105 114.083 105.312 114.489 ;
     RECT  110.4 113.891 110.712 114.489 ;
     RECT  115.8 114.035 116.112 114.489 ;
     RECT  121.2 114.323 121.512 114.489 ;
     RECT  131.808 114.035 132.312 114.489 ;
     RECT  137.4 114.467 137.712 114.489 ;
     RECT  142.8 113.507 143.112 114.489 ;
     RECT  148.2 113.459 148.512 114.489 ;
     RECT  153.6 113.123 153.912 114.489 ;
     RECT  159 113.795 159.312 114.489 ;
     RECT  164.4 112.883 164.712 114.489 ;
     RECT  169.8 112.883 170.112 114.489 ;
     RECT  175.2 112.883 175.512 114.489 ;
     RECT  180.6 113.651 180.912 114.489 ;
     RECT  191.4 2.151 191.712 114.489 ;
     RECT  196.8 2.151 197.112 114.489 ;
     RECT  202.2 2.151 202.512 114.489 ;
     RECT  207.6 2.151 207.912 114.489 ;
     RECT  213 2.151 213.312 114.489 ;
     RECT  218.4 114.323 218.712 114.489 ;
     RECT  223.8 40.835 224.112 114.489 ;
     RECT  229.2 2.151 229.512 114.489 ;
     RECT  234.6 2.151 234.912 114.489 ;
     RECT  240 2.151 240.312 114.489 ;
     RECT  245.4 2.151 245.712 114.489 ;
     RECT  250.8 2.151 251.112 114.489 ;
     RECT  256.2 2.151 256.512 114.489 ;
     RECT  2.4 114.489 2.52 114.503 ;
     RECT  7.8 114.489 7.92 114.503 ;
     RECT  18.6 114.489 18.72 114.503 ;
     RECT  24 114.489 24.12 114.503 ;
     RECT  29.4 114.489 29.52 114.503 ;
     RECT  40.2 114.489 40.32 114.503 ;
     RECT  45.6 114.489 45.72 114.503 ;
     RECT  51 114.489 51.12 114.503 ;
     RECT  56.4 114.489 56.52 114.503 ;
     RECT  61.8 114.489 61.92 114.503 ;
     RECT  67.2 114.489 67.32 114.503 ;
     RECT  72.6 114.489 72.72 114.503 ;
     RECT  78 114.489 78.12 114.503 ;
     RECT  83.4 114.489 83.52 114.503 ;
     RECT  88.8 114.489 88.92 114.503 ;
     RECT  94.2 114.489 94.32 114.503 ;
     RECT  105 114.489 105.12 114.503 ;
     RECT  110.4 114.489 110.52 114.503 ;
     RECT  115.8 114.489 115.92 114.503 ;
     RECT  121.2 114.489 121.32 114.503 ;
     RECT  131.808 114.489 132.12 114.503 ;
     RECT  137.4 114.489 137.52 114.503 ;
     RECT  142.8 114.489 142.92 114.503 ;
     RECT  148.2 114.489 148.32 114.503 ;
     RECT  153.6 114.489 153.72 114.503 ;
     RECT  159 114.489 159.12 114.503 ;
     RECT  164.4 114.489 164.52 114.503 ;
     RECT  169.8 114.489 169.92 114.503 ;
     RECT  175.2 114.489 175.32 114.503 ;
     RECT  180.6 114.489 180.72 114.503 ;
     RECT  191.4 114.489 191.52 114.503 ;
     RECT  196.8 114.489 196.92 114.503 ;
     RECT  202.2 114.489 202.32 114.503 ;
     RECT  207.6 114.489 207.72 114.503 ;
     RECT  213 114.489 213.12 114.503 ;
     RECT  218.4 114.489 218.52 114.503 ;
     RECT  223.8 114.489 223.92 114.503 ;
     RECT  229.2 114.489 229.32 114.503 ;
     RECT  234.6 114.489 234.72 114.503 ;
     RECT  240 114.489 240.12 114.503 ;
     RECT  245.4 114.489 245.52 114.503 ;
     RECT  250.8 114.489 250.92 114.503 ;
     RECT  256.2 114.489 256.32 114.503 ;
     RECT  12.72 114.469 15.624 114.517 ;
     RECT  31.92 111.733 35.64 114.563 ;
     RECT  139.104 114.421 140.088 114.563 ;
     RECT  131.808 114.503 131.832 115.427 ;
     RECT  140.064 114.563 140.088 116.435 ;
     RECT  31.92 114.563 35.208 116.531 ;
     RECT  124.608 114.227 128.136 116.531 ;
     RECT  12.72 114.517 15.72 116.624 ;
     RECT  31.92 116.531 34.92 116.624 ;
     RECT  98.736 114.275 101.736 116.624 ;
     RECT  124.608 116.531 127.848 116.624 ;
     RECT  182.448 114.421 188.52 116.624 ;
     RECT  124.608 116.624 124.632 116.627 ;
  END
END ot_hgi_topk_lane_tile
END LIBRARY
